VERSION 5.8 ;
BUSBITCHARS "[]" ;
DIVIDERCHAR "/" ;
UNITS
    DATABASE MICRONS 1000 ;
END UNITS

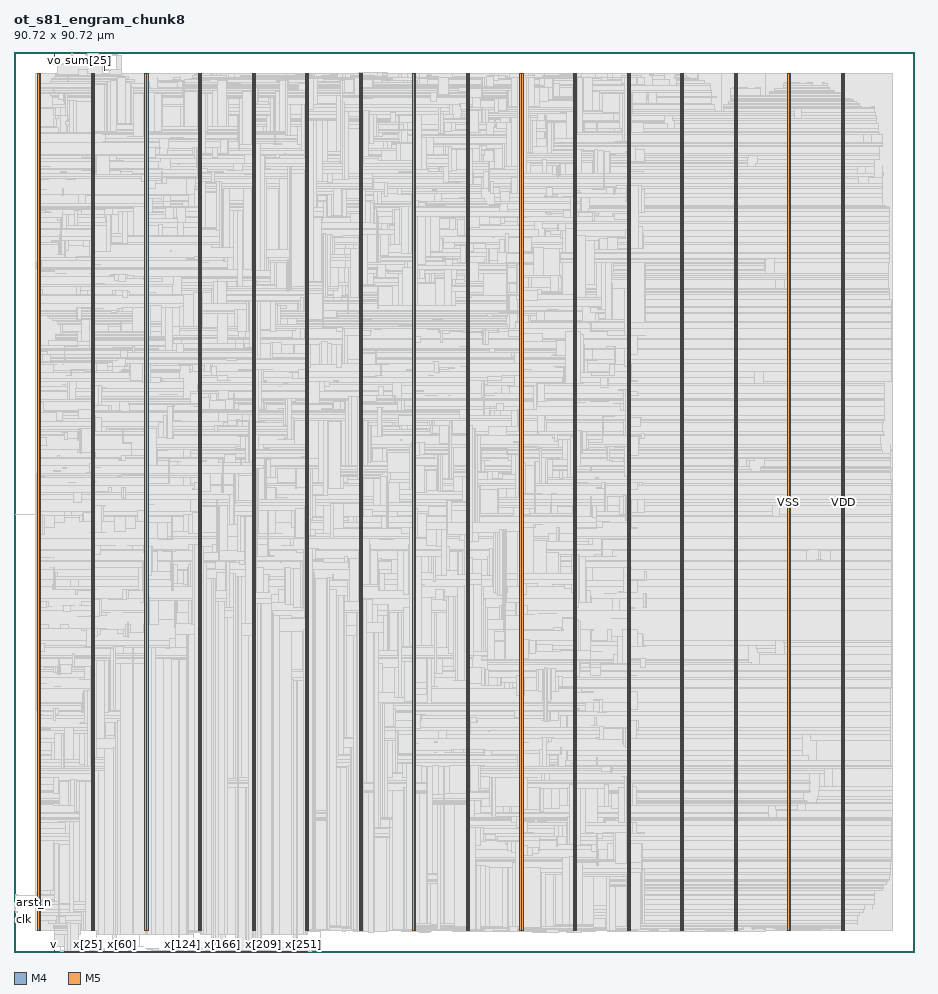
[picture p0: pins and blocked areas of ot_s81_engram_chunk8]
MACRO ot_s81_engram_chunk8
  FOREIGN ot_s81_engram_chunk8 0 0 ;
  CLASS BLOCK ;
  SIZE 90.72 BY 90.72 ;
  PIN arst_n
    DIRECTION INPUT ;
    USE SIGNAL ;
    PORT
      LAYER M4 ;
        RECT  0 4.992 0.084 5.016 ;
    END
  END arst_n
  PIN clk
    DIRECTION INPUT ;
    USE SIGNAL ;
    PORT
      LAYER M4 ;
        RECT  0 4.032 0.084 4.056 ;
    END
  END clk
  PIN fault
    DIRECTION OUTPUT ;
    USE SIGNAL ;
    PORT
      LAYER M5 ;
        RECT  9.12 90.636 9.144 90.72 ;
    END
    PORT
      LAYER M5 ;
        RECT  9.12 88.885 9.144 90.704 ;
    END
  END fault
  PIN sum[0]
    DIRECTION OUTPUT ;
    USE SIGNAL ;
    PORT
      LAYER M5 ;
        RECT  5.088 90.636 5.112 90.72 ;
    END
  END sum[0]
  PIN sum[10]
    DIRECTION OUTPUT ;
    USE SIGNAL ;
    PORT
      LAYER M5 ;
        RECT  6.048 90.636 6.072 90.72 ;
    END
  END sum[10]
  PIN sum[11]
    DIRECTION OUTPUT ;
    USE SIGNAL ;
    PORT
      LAYER M5 ;
        RECT  6.144 90.636 6.168 90.72 ;
    END
  END sum[11]
  PIN sum[12]
    DIRECTION OUTPUT ;
    USE SIGNAL ;
    PORT
      LAYER M5 ;
        RECT  6.24 90.636 6.264 90.72 ;
    END
  END sum[12]
  PIN sum[13]
    DIRECTION OUTPUT ;
    USE SIGNAL ;
    PORT
      LAYER M5 ;
        RECT  6.336 90.636 6.36 90.72 ;
    END
  END sum[13]
  PIN sum[14]
    DIRECTION OUTPUT ;
    USE SIGNAL ;
    PORT
      LAYER M5 ;
        RECT  6.432 90.636 6.456 90.72 ;
    END
  END sum[14]
  PIN sum[15]
    DIRECTION OUTPUT ;
    USE SIGNAL ;
    PORT
      LAYER M5 ;
        RECT  6.528 90.636 6.552 90.72 ;
    END
  END sum[15]
  PIN sum[16]
    DIRECTION OUTPUT ;
    USE SIGNAL ;
    PORT
      LAYER M5 ;
        RECT  6.624 90.636 6.648 90.72 ;
    END
  END sum[16]
  PIN sum[17]
    DIRECTION OUTPUT ;
    USE SIGNAL ;
    PORT
      LAYER M5 ;
        RECT  6.72 90.636 6.744 90.72 ;
    END
  END sum[17]
  PIN sum[18]
    DIRECTION OUTPUT ;
    USE SIGNAL ;
    PORT
      LAYER M5 ;
        RECT  6.816 90.636 6.84 90.72 ;
    END
  END sum[18]
  PIN sum[19]
    DIRECTION OUTPUT ;
    USE SIGNAL ;
    PORT
      LAYER M5 ;
        RECT  6.912 90.636 6.936 90.72 ;
    END
  END sum[19]
  PIN sum[1]
    DIRECTION OUTPUT ;
    USE SIGNAL ;
    PORT
      LAYER M5 ;
        RECT  5.184 90.636 5.208 90.72 ;
    END
  END sum[1]
  PIN sum[20]
    DIRECTION OUTPUT ;
    USE SIGNAL ;
    PORT
      LAYER M5 ;
        RECT  7.008 90.636 7.032 90.72 ;
    END
  END sum[20]
  PIN sum[21]
    DIRECTION OUTPUT ;
    USE SIGNAL ;
    PORT
      LAYER M5 ;
        RECT  7.104 90.636 7.128 90.72 ;
    END
  END sum[21]
  PIN sum[22]
    DIRECTION OUTPUT ;
    USE SIGNAL ;
    PORT
      LAYER M5 ;
        RECT  7.2 90.636 7.224 90.72 ;
    END
  END sum[22]
  PIN sum[23]
    DIRECTION OUTPUT ;
    USE SIGNAL ;
    PORT
      LAYER M5 ;
        RECT  7.296 90.636 7.32 90.72 ;
    END
  END sum[23]
  PIN sum[24]
    DIRECTION OUTPUT ;
    USE SIGNAL ;
    PORT
      LAYER M5 ;
        RECT  7.392 90.636 7.416 90.72 ;
    END
  END sum[24]
  PIN sum[25]
    DIRECTION OUTPUT ;
    USE SIGNAL ;
    PORT
      LAYER M5 ;
        RECT  7.488 90.636 7.512 90.72 ;
    END
  END sum[25]
  PIN sum[26]
    DIRECTION OUTPUT ;
    USE SIGNAL ;
    PORT
      LAYER M5 ;
        RECT  7.584 90.636 7.608 90.72 ;
    END
  END sum[26]
  PIN sum[27]
    DIRECTION OUTPUT ;
    USE SIGNAL ;
    PORT
      LAYER M5 ;
        RECT  7.68 90.636 7.704 90.72 ;
    END
  END sum[27]
  PIN sum[28]
    DIRECTION OUTPUT ;
    USE SIGNAL ;
    PORT
      LAYER M5 ;
        RECT  7.776 90.636 7.8 90.72 ;
    END
  END sum[28]
  PIN sum[29]
    DIRECTION OUTPUT ;
    USE SIGNAL ;
    PORT
      LAYER M5 ;
        RECT  7.872 90.636 7.896 90.72 ;
    END
  END sum[29]
  PIN sum[2]
    DIRECTION OUTPUT ;
    USE SIGNAL ;
    PORT
      LAYER M5 ;
        RECT  5.28 90.636 5.304 90.72 ;
    END
  END sum[2]
  PIN sum[30]
    DIRECTION OUTPUT ;
    USE SIGNAL ;
    PORT
      LAYER M5 ;
        RECT  7.968 90.636 7.992 90.72 ;
    END
  END sum[30]
  PIN sum[31]
    DIRECTION OUTPUT ;
    USE SIGNAL ;
    PORT
      LAYER M5 ;
        RECT  8.064 90.636 8.088 90.72 ;
    END
  END sum[31]
  PIN sum[3]
    DIRECTION OUTPUT ;
    USE SIGNAL ;
    PORT
      LAYER M5 ;
        RECT  5.376 90.636 5.4 90.72 ;
    END
  END sum[3]
  PIN sum[4]
    DIRECTION OUTPUT ;
    USE SIGNAL ;
    PORT
      LAYER M5 ;
        RECT  5.472 90.636 5.496 90.72 ;
    END
  END sum[4]
  PIN sum[5]
    DIRECTION OUTPUT ;
    USE SIGNAL ;
    PORT
      LAYER M5 ;
        RECT  5.568 90.636 5.592 90.72 ;
    END
  END sum[5]
  PIN sum[6]
    DIRECTION OUTPUT ;
    USE SIGNAL ;
    PORT
      LAYER M5 ;
        RECT  5.664 90.636 5.688 90.72 ;
    END
  END sum[6]
  PIN sum[7]
    DIRECTION OUTPUT ;
    USE SIGNAL ;
    PORT
      LAYER M5 ;
        RECT  5.76 90.636 5.784 90.72 ;
    END
  END sum[7]
  PIN sum[8]
    DIRECTION OUTPUT ;
    USE SIGNAL ;
    PORT
      LAYER M5 ;
        RECT  5.856 90.636 5.88 90.72 ;
    END
  END sum[8]
  PIN sum[9]
    DIRECTION OUTPUT ;
    USE SIGNAL ;
    PORT
      LAYER M5 ;
        RECT  5.952 90.636 5.976 90.72 ;
    END
  END sum[9]
  PIN v
    DIRECTION INPUT ;
    USE SIGNAL ;
    PORT
      LAYER M5 ;
        RECT  4.032 0 4.056 0.084 ;
    END
    PORT
      LAYER M5 ;
        RECT  4.032 0.016 4.056 0.611 ;
    END
  END v
  PIN vo
    DIRECTION OUTPUT ;
    USE SIGNAL ;
    PORT
      LAYER M5 ;
        RECT  4.032 90.636 4.056 90.72 ;
    END
    PORT
      LAYER M5 ;
        RECT  4.032 89.461 4.056 90.704 ;
    END
  END vo
  PIN x[0]
    DIRECTION INPUT ;
    USE SIGNAL ;
    PORT
      LAYER M5 ;
        RECT  5.088 0 5.112 0.084 ;
    END
  END x[0]
  PIN x[100]
    DIRECTION INPUT ;
    USE SIGNAL ;
    PORT
      LAYER M5 ;
        RECT  14.688 0 14.712 0.084 ;
    END
  END x[100]
  PIN x[101]
    DIRECTION INPUT ;
    USE SIGNAL ;
    PORT
      LAYER M5 ;
        RECT  14.784 0 14.808 0.084 ;
    END
  END x[101]
  PIN x[102]
    DIRECTION INPUT ;
    USE SIGNAL ;
    PORT
      LAYER M5 ;
        RECT  14.88 0 14.904 0.084 ;
    END
  END x[102]
  PIN x[103]
    DIRECTION INPUT ;
    USE SIGNAL ;
    PORT
      LAYER M5 ;
        RECT  14.976 0 15 0.084 ;
    END
  END x[103]
  PIN x[104]
    DIRECTION INPUT ;
    USE SIGNAL ;
    PORT
      LAYER M5 ;
        RECT  15.072 0 15.096 0.084 ;
    END
  END x[104]
  PIN x[105]
    DIRECTION INPUT ;
    USE SIGNAL ;
    PORT
      LAYER M5 ;
        RECT  15.168 0 15.192 0.084 ;
    END
  END x[105]
  PIN x[106]
    DIRECTION INPUT ;
    USE SIGNAL ;
    PORT
      LAYER M5 ;
        RECT  15.264 0 15.288 0.084 ;
    END
  END x[106]
  PIN x[107]
    DIRECTION INPUT ;
    USE SIGNAL ;
    PORT
      LAYER M5 ;
        RECT  15.36 0 15.384 0.084 ;
    END
  END x[107]
  PIN x[108]
    DIRECTION INPUT ;
    USE SIGNAL ;
    PORT
      LAYER M5 ;
        RECT  15.456 0 15.48 0.084 ;
    END
  END x[108]
  PIN x[109]
    DIRECTION INPUT ;
    USE SIGNAL ;
    PORT
      LAYER M5 ;
        RECT  15.552 0 15.576 0.084 ;
    END
  END x[109]
  PIN x[10]
    DIRECTION INPUT ;
    USE SIGNAL ;
    PORT
      LAYER M5 ;
        RECT  6.048 0 6.072 0.084 ;
    END
  END x[10]
  PIN x[110]
    DIRECTION INPUT ;
    USE SIGNAL ;
    PORT
      LAYER M5 ;
        RECT  15.648 0 15.672 0.084 ;
    END
  END x[110]
  PIN x[111]
    DIRECTION INPUT ;
    USE SIGNAL ;
    PORT
      LAYER M5 ;
        RECT  15.744 0 15.768 0.084 ;
    END
  END x[111]
  PIN x[112]
    DIRECTION INPUT ;
    USE SIGNAL ;
    PORT
      LAYER M5 ;
        RECT  15.84 0 15.864 0.084 ;
    END
  END x[112]
  PIN x[113]
    DIRECTION INPUT ;
    USE SIGNAL ;
    PORT
      LAYER M5 ;
        RECT  15.936 0 15.96 0.084 ;
    END
  END x[113]
  PIN x[114]
    DIRECTION INPUT ;
    USE SIGNAL ;
    PORT
      LAYER M5 ;
        RECT  16.032 0 16.056 0.084 ;
    END
  END x[114]
  PIN x[115]
    DIRECTION INPUT ;
    USE SIGNAL ;
    PORT
      LAYER M5 ;
        RECT  16.128 0 16.152 0.084 ;
    END
  END x[115]
  PIN x[116]
    DIRECTION INPUT ;
    USE SIGNAL ;
    PORT
      LAYER M5 ;
        RECT  16.224 0 16.248 0.084 ;
    END
  END x[116]
  PIN x[117]
    DIRECTION INPUT ;
    USE SIGNAL ;
    PORT
      LAYER M5 ;
        RECT  16.32 0 16.344 0.084 ;
    END
  END x[117]
  PIN x[118]
    DIRECTION INPUT ;
    USE SIGNAL ;
    PORT
      LAYER M5 ;
        RECT  16.416 0 16.44 0.084 ;
    END
  END x[118]
  PIN x[119]
    DIRECTION INPUT ;
    USE SIGNAL ;
    PORT
      LAYER M5 ;
        RECT  16.512 0 16.536 0.084 ;
    END
  END x[119]
  PIN x[11]
    DIRECTION INPUT ;
    USE SIGNAL ;
    PORT
      LAYER M5 ;
        RECT  6.144 0 6.168 0.084 ;
    END
  END x[11]
  PIN x[120]
    DIRECTION INPUT ;
    USE SIGNAL ;
    PORT
      LAYER M5 ;
        RECT  16.608 0 16.632 0.084 ;
    END
  END x[120]
  PIN x[121]
    DIRECTION INPUT ;
    USE SIGNAL ;
    PORT
      LAYER M5 ;
        RECT  16.704 0 16.728 0.084 ;
    END
  END x[121]
  PIN x[122]
    DIRECTION INPUT ;
    USE SIGNAL ;
    PORT
      LAYER M5 ;
        RECT  16.8 0 16.824 0.084 ;
    END
  END x[122]
  PIN x[123]
    DIRECTION INPUT ;
    USE SIGNAL ;
    PORT
      LAYER M5 ;
        RECT  16.896 0 16.92 0.084 ;
    END
  END x[123]
  PIN x[124]
    DIRECTION INPUT ;
    USE SIGNAL ;
    PORT
      LAYER M5 ;
        RECT  16.992 0 17.016 0.084 ;
    END
  END x[124]
  PIN x[125]
    DIRECTION INPUT ;
    USE SIGNAL ;
    PORT
      LAYER M5 ;
        RECT  17.088 0 17.112 0.084 ;
    END
  END x[125]
  PIN x[126]
    DIRECTION INPUT ;
    USE SIGNAL ;
    PORT
      LAYER M5 ;
        RECT  17.184 0 17.208 0.084 ;
    END
  END x[126]
  PIN x[127]
    DIRECTION INPUT ;
    USE SIGNAL ;
    PORT
      LAYER M5 ;
        RECT  17.28 0 17.304 0.084 ;
    END
  END x[127]
  PIN x[128]
    DIRECTION INPUT ;
    USE SIGNAL ;
    PORT
      LAYER M5 ;
        RECT  17.376 0 17.4 0.084 ;
    END
  END x[128]
  PIN x[129]
    DIRECTION INPUT ;
    USE SIGNAL ;
    PORT
      LAYER M5 ;
        RECT  17.472 0 17.496 0.084 ;
    END
  END x[129]
  PIN x[12]
    DIRECTION INPUT ;
    USE SIGNAL ;
    PORT
      LAYER M5 ;
        RECT  6.24 0 6.264 0.084 ;
    END
  END x[12]
  PIN x[130]
    DIRECTION INPUT ;
    USE SIGNAL ;
    PORT
      LAYER M5 ;
        RECT  17.568 0 17.592 0.084 ;
    END
  END x[130]
  PIN x[131]
    DIRECTION INPUT ;
    USE SIGNAL ;
    PORT
      LAYER M5 ;
        RECT  17.664 0 17.688 0.084 ;
    END
  END x[131]
  PIN x[132]
    DIRECTION INPUT ;
    USE SIGNAL ;
    PORT
      LAYER M5 ;
        RECT  17.76 0 17.784 0.084 ;
    END
  END x[132]
  PIN x[133]
    DIRECTION INPUT ;
    USE SIGNAL ;
    PORT
      LAYER M5 ;
        RECT  17.856 0 17.88 0.084 ;
    END
  END x[133]
  PIN x[134]
    DIRECTION INPUT ;
    USE SIGNAL ;
    PORT
      LAYER M5 ;
        RECT  17.952 0 17.976 0.084 ;
    END
  END x[134]
  PIN x[135]
    DIRECTION INPUT ;
    USE SIGNAL ;
    PORT
      LAYER M5 ;
        RECT  18.048 0 18.072 0.084 ;
    END
  END x[135]
  PIN x[136]
    DIRECTION INPUT ;
    USE SIGNAL ;
    PORT
      LAYER M5 ;
        RECT  18.144 0 18.168 0.084 ;
    END
  END x[136]
  PIN x[137]
    DIRECTION INPUT ;
    USE SIGNAL ;
    PORT
      LAYER M5 ;
        RECT  18.24 0 18.264 0.084 ;
    END
  END x[137]
  PIN x[138]
    DIRECTION INPUT ;
    USE SIGNAL ;
    PORT
      LAYER M5 ;
        RECT  18.336 0 18.36 0.084 ;
    END
  END x[138]
  PIN x[139]
    DIRECTION INPUT ;
    USE SIGNAL ;
    PORT
      LAYER M5 ;
        RECT  18.432 0 18.456 0.084 ;
    END
  END x[139]
  PIN x[13]
    DIRECTION INPUT ;
    USE SIGNAL ;
    PORT
      LAYER M5 ;
        RECT  6.336 0 6.36 0.084 ;
    END
  END x[13]
  PIN x[140]
    DIRECTION INPUT ;
    USE SIGNAL ;
    PORT
      LAYER M5 ;
        RECT  18.528 0 18.552 0.084 ;
    END
  END x[140]
  PIN x[141]
    DIRECTION INPUT ;
    USE SIGNAL ;
    PORT
      LAYER M5 ;
        RECT  18.624 0 18.648 0.084 ;
    END
  END x[141]
  PIN x[142]
    DIRECTION INPUT ;
    USE SIGNAL ;
    PORT
      LAYER M5 ;
        RECT  18.72 0 18.744 0.084 ;
    END
  END x[142]
  PIN x[143]
    DIRECTION INPUT ;
    USE SIGNAL ;
    PORT
      LAYER M5 ;
        RECT  18.816 0 18.84 0.084 ;
    END
  END x[143]
  PIN x[144]
    DIRECTION INPUT ;
    USE SIGNAL ;
    PORT
      LAYER M5 ;
        RECT  18.912 0 18.936 0.084 ;
    END
  END x[144]
  PIN x[145]
    DIRECTION INPUT ;
    USE SIGNAL ;
    PORT
      LAYER M5 ;
        RECT  19.008 0 19.032 0.084 ;
    END
  END x[145]
  PIN x[146]
    DIRECTION INPUT ;
    USE SIGNAL ;
    PORT
      LAYER M5 ;
        RECT  19.104 0 19.128 0.084 ;
    END
  END x[146]
  PIN x[147]
    DIRECTION INPUT ;
    USE SIGNAL ;
    PORT
      LAYER M5 ;
        RECT  19.2 0 19.224 0.084 ;
    END
  END x[147]
  PIN x[148]
    DIRECTION INPUT ;
    USE SIGNAL ;
    PORT
      LAYER M5 ;
        RECT  19.296 0 19.32 0.084 ;
    END
  END x[148]
  PIN x[149]
    DIRECTION INPUT ;
    USE SIGNAL ;
    PORT
      LAYER M5 ;
        RECT  19.392 0 19.416 0.084 ;
    END
  END x[149]
  PIN x[14]
    DIRECTION INPUT ;
    USE SIGNAL ;
    PORT
      LAYER M5 ;
        RECT  6.432 0 6.456 0.084 ;
    END
  END x[14]
  PIN x[150]
    DIRECTION INPUT ;
    USE SIGNAL ;
    PORT
      LAYER M5 ;
        RECT  19.488 0 19.512 0.084 ;
    END
  END x[150]
  PIN x[151]
    DIRECTION INPUT ;
    USE SIGNAL ;
    PORT
      LAYER M5 ;
        RECT  19.584 0 19.608 0.084 ;
    END
  END x[151]
  PIN x[152]
    DIRECTION INPUT ;
    USE SIGNAL ;
    PORT
      LAYER M5 ;
        RECT  19.68 0 19.704 0.084 ;
    END
  END x[152]
  PIN x[153]
    DIRECTION INPUT ;
    USE SIGNAL ;
    PORT
      LAYER M5 ;
        RECT  19.776 0 19.8 0.084 ;
    END
  END x[153]
  PIN x[154]
    DIRECTION INPUT ;
    USE SIGNAL ;
    PORT
      LAYER M5 ;
        RECT  19.872 0 19.896 0.084 ;
    END
  END x[154]
  PIN x[155]
    DIRECTION INPUT ;
    USE SIGNAL ;
    PORT
      LAYER M5 ;
        RECT  19.968 0 19.992 0.084 ;
    END
  END x[155]
  PIN x[156]
    DIRECTION INPUT ;
    USE SIGNAL ;
    PORT
      LAYER M5 ;
        RECT  20.064 0 20.088 0.084 ;
    END
  END x[156]
  PIN x[157]
    DIRECTION INPUT ;
    USE SIGNAL ;
    PORT
      LAYER M5 ;
        RECT  20.16 0 20.184 0.084 ;
    END
  END x[157]
  PIN x[158]
    DIRECTION INPUT ;
    USE SIGNAL ;
    PORT
      LAYER M5 ;
        RECT  20.256 0 20.28 0.084 ;
    END
  END x[158]
  PIN x[159]
    DIRECTION INPUT ;
    USE SIGNAL ;
    PORT
      LAYER M5 ;
        RECT  20.352 0 20.376 0.084 ;
    END
  END x[159]
  PIN x[15]
    DIRECTION INPUT ;
    USE SIGNAL ;
    PORT
      LAYER M5 ;
        RECT  6.528 0 6.552 0.084 ;
    END
  END x[15]
  PIN x[160]
    DIRECTION INPUT ;
    USE SIGNAL ;
    PORT
      LAYER M5 ;
        RECT  20.448 0 20.472 0.084 ;
    END
  END x[160]
  PIN x[161]
    DIRECTION INPUT ;
    USE SIGNAL ;
    PORT
      LAYER M5 ;
        RECT  20.544 0 20.568 0.084 ;
    END
  END x[161]
  PIN x[162]
    DIRECTION INPUT ;
    USE SIGNAL ;
    PORT
      LAYER M5 ;
        RECT  20.64 0 20.664 0.084 ;
    END
  END x[162]
  PIN x[163]
    DIRECTION INPUT ;
    USE SIGNAL ;
    PORT
      LAYER M5 ;
        RECT  20.736 0 20.76 0.084 ;
    END
  END x[163]
  PIN x[164]
    DIRECTION INPUT ;
    USE SIGNAL ;
    PORT
      LAYER M5 ;
        RECT  20.832 0 20.856 0.084 ;
    END
  END x[164]
  PIN x[165]
    DIRECTION INPUT ;
    USE SIGNAL ;
    PORT
      LAYER M5 ;
        RECT  20.928 0 20.952 0.084 ;
    END
  END x[165]
  PIN x[166]
    DIRECTION INPUT ;
    USE SIGNAL ;
    PORT
      LAYER M5 ;
        RECT  21.024 0 21.048 0.084 ;
    END
  END x[166]
  PIN x[167]
    DIRECTION INPUT ;
    USE SIGNAL ;
    PORT
      LAYER M5 ;
        RECT  21.12 0 21.144 0.084 ;
    END
  END x[167]
  PIN x[168]
    DIRECTION INPUT ;
    USE SIGNAL ;
    PORT
      LAYER M5 ;
        RECT  21.216 0 21.24 0.084 ;
    END
  END x[168]
  PIN x[169]
    DIRECTION INPUT ;
    USE SIGNAL ;
    PORT
      LAYER M5 ;
        RECT  21.312 0 21.336 0.084 ;
    END
  END x[169]
  PIN x[16]
    DIRECTION INPUT ;
    USE SIGNAL ;
    PORT
      LAYER M5 ;
        RECT  6.624 0 6.648 0.084 ;
    END
  END x[16]
  PIN x[170]
    DIRECTION INPUT ;
    USE SIGNAL ;
    PORT
      LAYER M5 ;
        RECT  21.408 0 21.432 0.084 ;
    END
  END x[170]
  PIN x[171]
    DIRECTION INPUT ;
    USE SIGNAL ;
    PORT
      LAYER M5 ;
        RECT  21.504 0 21.528 0.084 ;
    END
  END x[171]
  PIN x[172]
    DIRECTION INPUT ;
    USE SIGNAL ;
    PORT
      LAYER M5 ;
        RECT  21.6 0 21.624 0.084 ;
    END
  END x[172]
  PIN x[173]
    DIRECTION INPUT ;
    USE SIGNAL ;
    PORT
      LAYER M5 ;
        RECT  21.696 0 21.72 0.084 ;
    END
  END x[173]
  PIN x[174]
    DIRECTION INPUT ;
    USE SIGNAL ;
    PORT
      LAYER M5 ;
        RECT  21.792 0 21.816 0.084 ;
    END
  END x[174]
  PIN x[175]
    DIRECTION INPUT ;
    USE SIGNAL ;
    PORT
      LAYER M5 ;
        RECT  21.888 0 21.912 0.084 ;
    END
  END x[175]
  PIN x[176]
    DIRECTION INPUT ;
    USE SIGNAL ;
    PORT
      LAYER M5 ;
        RECT  21.984 0 22.008 0.084 ;
    END
  END x[176]
  PIN x[177]
    DIRECTION INPUT ;
    USE SIGNAL ;
    PORT
      LAYER M5 ;
        RECT  22.08 0 22.104 0.084 ;
    END
  END x[177]
  PIN x[178]
    DIRECTION INPUT ;
    USE SIGNAL ;
    PORT
      LAYER M5 ;
        RECT  22.176 0 22.2 0.084 ;
    END
  END x[178]
  PIN x[179]
    DIRECTION INPUT ;
    USE SIGNAL ;
    PORT
      LAYER M5 ;
        RECT  22.272 0 22.296 0.084 ;
    END
  END x[179]
  PIN x[17]
    DIRECTION INPUT ;
    USE SIGNAL ;
    PORT
      LAYER M5 ;
        RECT  6.72 0 6.744 0.084 ;
    END
  END x[17]
  PIN x[180]
    DIRECTION INPUT ;
    USE SIGNAL ;
    PORT
      LAYER M5 ;
        RECT  22.368 0 22.392 0.084 ;
    END
  END x[180]
  PIN x[181]
    DIRECTION INPUT ;
    USE SIGNAL ;
    PORT
      LAYER M5 ;
        RECT  22.464 0 22.488 0.084 ;
    END
  END x[181]
  PIN x[182]
    DIRECTION INPUT ;
    USE SIGNAL ;
    PORT
      LAYER M5 ;
        RECT  22.56 0 22.584 0.084 ;
    END
  END x[182]
  PIN x[183]
    DIRECTION INPUT ;
    USE SIGNAL ;
    PORT
      LAYER M5 ;
        RECT  22.656 0 22.68 0.084 ;
    END
  END x[183]
  PIN x[184]
    DIRECTION INPUT ;
    USE SIGNAL ;
    PORT
      LAYER M5 ;
        RECT  22.752 0 22.776 0.084 ;
    END
  END x[184]
  PIN x[185]
    DIRECTION INPUT ;
    USE SIGNAL ;
    PORT
      LAYER M5 ;
        RECT  22.848 0 22.872 0.084 ;
    END
  END x[185]
  PIN x[186]
    DIRECTION INPUT ;
    USE SIGNAL ;
    PORT
      LAYER M5 ;
        RECT  22.944 0 22.968 0.084 ;
    END
  END x[186]
  PIN x[187]
    DIRECTION INPUT ;
    USE SIGNAL ;
    PORT
      LAYER M5 ;
        RECT  23.04 0 23.064 0.084 ;
    END
  END x[187]
  PIN x[188]
    DIRECTION INPUT ;
    USE SIGNAL ;
    PORT
      LAYER M5 ;
        RECT  23.136 0 23.16 0.084 ;
    END
  END x[188]
  PIN x[189]
    DIRECTION INPUT ;
    USE SIGNAL ;
    PORT
      LAYER M5 ;
        RECT  23.232 0 23.256 0.084 ;
    END
  END x[189]
  PIN x[18]
    DIRECTION INPUT ;
    USE SIGNAL ;
    PORT
      LAYER M5 ;
        RECT  6.816 0 6.84 0.084 ;
    END
  END x[18]
  PIN x[190]
    DIRECTION INPUT ;
    USE SIGNAL ;
    PORT
      LAYER M5 ;
        RECT  23.328 0 23.352 0.084 ;
    END
  END x[190]
  PIN x[191]
    DIRECTION INPUT ;
    USE SIGNAL ;
    PORT
      LAYER M5 ;
        RECT  23.424 0 23.448 0.084 ;
    END
  END x[191]
  PIN x[192]
    DIRECTION INPUT ;
    USE SIGNAL ;
    PORT
      LAYER M5 ;
        RECT  23.52 0 23.544 0.084 ;
    END
  END x[192]
  PIN x[193]
    DIRECTION INPUT ;
    USE SIGNAL ;
    PORT
      LAYER M5 ;
        RECT  23.616 0 23.64 0.084 ;
    END
  END x[193]
  PIN x[194]
    DIRECTION INPUT ;
    USE SIGNAL ;
    PORT
      LAYER M5 ;
        RECT  23.712 0 23.736 0.084 ;
    END
  END x[194]
  PIN x[195]
    DIRECTION INPUT ;
    USE SIGNAL ;
    PORT
      LAYER M5 ;
        RECT  23.808 0 23.832 0.084 ;
    END
  END x[195]
  PIN x[196]
    DIRECTION INPUT ;
    USE SIGNAL ;
    PORT
      LAYER M5 ;
        RECT  23.904 0 23.928 0.084 ;
    END
  END x[196]
  PIN x[197]
    DIRECTION INPUT ;
    USE SIGNAL ;
    PORT
      LAYER M5 ;
        RECT  24 0 24.024 0.084 ;
    END
  END x[197]
  PIN x[198]
    DIRECTION INPUT ;
    USE SIGNAL ;
    PORT
      LAYER M5 ;
        RECT  24.096 0 24.12 0.084 ;
    END
  END x[198]
  PIN x[199]
    DIRECTION INPUT ;
    USE SIGNAL ;
    PORT
      LAYER M5 ;
        RECT  24.192 0 24.216 0.084 ;
    END
  END x[199]
  PIN x[19]
    DIRECTION INPUT ;
    USE SIGNAL ;
    PORT
      LAYER M5 ;
        RECT  6.912 0 6.936 0.084 ;
    END
  END x[19]
  PIN x[1]
    DIRECTION INPUT ;
    USE SIGNAL ;
    PORT
      LAYER M5 ;
        RECT  5.184 0 5.208 0.084 ;
    END
  END x[1]
  PIN x[200]
    DIRECTION INPUT ;
    USE SIGNAL ;
    PORT
      LAYER M5 ;
        RECT  24.288 0 24.312 0.084 ;
    END
  END x[200]
  PIN x[201]
    DIRECTION INPUT ;
    USE SIGNAL ;
    PORT
      LAYER M5 ;
        RECT  24.384 0 24.408 0.084 ;
    END
  END x[201]
  PIN x[202]
    DIRECTION INPUT ;
    USE SIGNAL ;
    PORT
      LAYER M5 ;
        RECT  24.48 0 24.504 0.084 ;
    END
  END x[202]
  PIN x[203]
    DIRECTION INPUT ;
    USE SIGNAL ;
    PORT
      LAYER M5 ;
        RECT  24.576 0 24.6 0.084 ;
    END
  END x[203]
  PIN x[204]
    DIRECTION INPUT ;
    USE SIGNAL ;
    PORT
      LAYER M5 ;
        RECT  24.672 0 24.696 0.084 ;
    END
  END x[204]
  PIN x[205]
    DIRECTION INPUT ;
    USE SIGNAL ;
    PORT
      LAYER M5 ;
        RECT  24.768 0 24.792 0.084 ;
    END
  END x[205]
  PIN x[206]
    DIRECTION INPUT ;
    USE SIGNAL ;
    PORT
      LAYER M5 ;
        RECT  24.864 0 24.888 0.084 ;
    END
  END x[206]
  PIN x[207]
    DIRECTION INPUT ;
    USE SIGNAL ;
    PORT
      LAYER M5 ;
        RECT  24.96 0 24.984 0.084 ;
    END
  END x[207]
  PIN x[208]
    DIRECTION INPUT ;
    USE SIGNAL ;
    PORT
      LAYER M5 ;
        RECT  25.056 0 25.08 0.084 ;
    END
  END x[208]
  PIN x[209]
    DIRECTION INPUT ;
    USE SIGNAL ;
    PORT
      LAYER M5 ;
        RECT  25.152 0 25.176 0.084 ;
    END
  END x[209]
  PIN x[20]
    DIRECTION INPUT ;
    USE SIGNAL ;
    PORT
      LAYER M5 ;
        RECT  7.008 0 7.032 0.084 ;
    END
  END x[20]
  PIN x[210]
    DIRECTION INPUT ;
    USE SIGNAL ;
    PORT
      LAYER M5 ;
        RECT  25.248 0 25.272 0.084 ;
    END
  END x[210]
  PIN x[211]
    DIRECTION INPUT ;
    USE SIGNAL ;
    PORT
      LAYER M5 ;
        RECT  25.344 0 25.368 0.084 ;
    END
  END x[211]
  PIN x[212]
    DIRECTION INPUT ;
    USE SIGNAL ;
    PORT
      LAYER M5 ;
        RECT  25.44 0 25.464 0.084 ;
    END
  END x[212]
  PIN x[213]
    DIRECTION INPUT ;
    USE SIGNAL ;
    PORT
      LAYER M5 ;
        RECT  25.536 0 25.56 0.084 ;
    END
  END x[213]
  PIN x[214]
    DIRECTION INPUT ;
    USE SIGNAL ;
    PORT
      LAYER M5 ;
        RECT  25.632 0 25.656 0.084 ;
    END
  END x[214]
  PIN x[215]
    DIRECTION INPUT ;
    USE SIGNAL ;
    PORT
      LAYER M5 ;
        RECT  25.728 0 25.752 0.084 ;
    END
  END x[215]
  PIN x[216]
    DIRECTION INPUT ;
    USE SIGNAL ;
    PORT
      LAYER M5 ;
        RECT  25.824 0 25.848 0.084 ;
    END
  END x[216]
  PIN x[217]
    DIRECTION INPUT ;
    USE SIGNAL ;
    PORT
      LAYER M5 ;
        RECT  25.92 0 25.944 0.084 ;
    END
  END x[217]
  PIN x[218]
    DIRECTION INPUT ;
    USE SIGNAL ;
    PORT
      LAYER M5 ;
        RECT  26.016 0 26.04 0.084 ;
    END
  END x[218]
  PIN x[219]
    DIRECTION INPUT ;
    USE SIGNAL ;
    PORT
      LAYER M5 ;
        RECT  26.112 0 26.136 0.084 ;
    END
  END x[219]
  PIN x[21]
    DIRECTION INPUT ;
    USE SIGNAL ;
    PORT
      LAYER M5 ;
        RECT  7.104 0 7.128 0.084 ;
    END
  END x[21]
  PIN x[220]
    DIRECTION INPUT ;
    USE SIGNAL ;
    PORT
      LAYER M5 ;
        RECT  26.208 0 26.232 0.084 ;
    END
  END x[220]
  PIN x[221]
    DIRECTION INPUT ;
    USE SIGNAL ;
    PORT
      LAYER M5 ;
        RECT  26.304 0 26.328 0.084 ;
    END
  END x[221]
  PIN x[222]
    DIRECTION INPUT ;
    USE SIGNAL ;
    PORT
      LAYER M5 ;
        RECT  26.4 0 26.424 0.084 ;
    END
  END x[222]
  PIN x[223]
    DIRECTION INPUT ;
    USE SIGNAL ;
    PORT
      LAYER M5 ;
        RECT  26.496 0 26.52 0.084 ;
    END
  END x[223]
  PIN x[224]
    DIRECTION INPUT ;
    USE SIGNAL ;
    PORT
      LAYER M5 ;
        RECT  26.592 0 26.616 0.084 ;
    END
  END x[224]
  PIN x[225]
    DIRECTION INPUT ;
    USE SIGNAL ;
    PORT
      LAYER M5 ;
        RECT  26.688 0 26.712 0.084 ;
    END
  END x[225]
  PIN x[226]
    DIRECTION INPUT ;
    USE SIGNAL ;
    PORT
      LAYER M5 ;
        RECT  26.784 0 26.808 0.084 ;
    END
  END x[226]
  PIN x[227]
    DIRECTION INPUT ;
    USE SIGNAL ;
    PORT
      LAYER M5 ;
        RECT  26.88 0 26.904 0.084 ;
    END
  END x[227]
  PIN x[228]
    DIRECTION INPUT ;
    USE SIGNAL ;
    PORT
      LAYER M5 ;
        RECT  26.976 0 27 0.084 ;
    END
  END x[228]
  PIN x[229]
    DIRECTION INPUT ;
    USE SIGNAL ;
    PORT
      LAYER M5 ;
        RECT  27.072 0 27.096 0.084 ;
    END
  END x[229]
  PIN x[22]
    DIRECTION INPUT ;
    USE SIGNAL ;
    PORT
      LAYER M5 ;
        RECT  7.2 0 7.224 0.084 ;
    END
  END x[22]
  PIN x[230]
    DIRECTION INPUT ;
    USE SIGNAL ;
    PORT
      LAYER M5 ;
        RECT  27.168 0 27.192 0.084 ;
    END
  END x[230]
  PIN x[231]
    DIRECTION INPUT ;
    USE SIGNAL ;
    PORT
      LAYER M5 ;
        RECT  27.264 0 27.288 0.084 ;
    END
  END x[231]
  PIN x[232]
    DIRECTION INPUT ;
    USE SIGNAL ;
    PORT
      LAYER M5 ;
        RECT  27.36 0 27.384 0.084 ;
    END
  END x[232]
  PIN x[233]
    DIRECTION INPUT ;
    USE SIGNAL ;
    PORT
      LAYER M5 ;
        RECT  27.456 0 27.48 0.084 ;
    END
  END x[233]
  PIN x[234]
    DIRECTION INPUT ;
    USE SIGNAL ;
    PORT
      LAYER M5 ;
        RECT  27.552 0 27.576 0.084 ;
    END
  END x[234]
  PIN x[235]
    DIRECTION INPUT ;
    USE SIGNAL ;
    PORT
      LAYER M5 ;
        RECT  27.648 0 27.672 0.084 ;
    END
  END x[235]
  PIN x[236]
    DIRECTION INPUT ;
    USE SIGNAL ;
    PORT
      LAYER M5 ;
        RECT  27.744 0 27.768 0.084 ;
    END
  END x[236]
  PIN x[237]
    DIRECTION INPUT ;
    USE SIGNAL ;
    PORT
      LAYER M5 ;
        RECT  27.84 0 27.864 0.084 ;
    END
  END x[237]
  PIN x[238]
    DIRECTION INPUT ;
    USE SIGNAL ;
    PORT
      LAYER M5 ;
        RECT  27.936 0 27.96 0.084 ;
    END
  END x[238]
  PIN x[239]
    DIRECTION INPUT ;
    USE SIGNAL ;
    PORT
      LAYER M5 ;
        RECT  28.032 0 28.056 0.084 ;
    END
  END x[239]
  PIN x[23]
    DIRECTION INPUT ;
    USE SIGNAL ;
    PORT
      LAYER M5 ;
        RECT  7.296 0 7.32 0.084 ;
    END
  END x[23]
  PIN x[240]
    DIRECTION INPUT ;
    USE SIGNAL ;
    PORT
      LAYER M5 ;
        RECT  28.128 0 28.152 0.084 ;
    END
  END x[240]
  PIN x[241]
    DIRECTION INPUT ;
    USE SIGNAL ;
    PORT
      LAYER M5 ;
        RECT  28.224 0 28.248 0.084 ;
    END
  END x[241]
  PIN x[242]
    DIRECTION INPUT ;
    USE SIGNAL ;
    PORT
      LAYER M5 ;
        RECT  28.32 0 28.344 0.084 ;
    END
  END x[242]
  PIN x[243]
    DIRECTION INPUT ;
    USE SIGNAL ;
    PORT
      LAYER M5 ;
        RECT  28.416 0 28.44 0.084 ;
    END
  END x[243]
  PIN x[244]
    DIRECTION INPUT ;
    USE SIGNAL ;
    PORT
      LAYER M5 ;
        RECT  28.512 0 28.536 0.084 ;
    END
  END x[244]
  PIN x[245]
    DIRECTION INPUT ;
    USE SIGNAL ;
    PORT
      LAYER M5 ;
        RECT  28.608 0 28.632 0.084 ;
    END
  END x[245]
  PIN x[246]
    DIRECTION INPUT ;
    USE SIGNAL ;
    PORT
      LAYER M5 ;
        RECT  28.704 0 28.728 0.084 ;
    END
  END x[246]
  PIN x[247]
    DIRECTION INPUT ;
    USE SIGNAL ;
    PORT
      LAYER M5 ;
        RECT  28.8 0 28.824 0.084 ;
    END
  END x[247]
  PIN x[248]
    DIRECTION INPUT ;
    USE SIGNAL ;
    PORT
      LAYER M5 ;
        RECT  28.896 0 28.92 0.084 ;
    END
  END x[248]
  PIN x[249]
    DIRECTION INPUT ;
    USE SIGNAL ;
    PORT
      LAYER M5 ;
        RECT  28.992 0 29.016 0.084 ;
    END
  END x[249]
  PIN x[24]
    DIRECTION INPUT ;
    USE SIGNAL ;
    PORT
      LAYER M5 ;
        RECT  7.392 0 7.416 0.084 ;
    END
  END x[24]
  PIN x[250]
    DIRECTION INPUT ;
    USE SIGNAL ;
    PORT
      LAYER M5 ;
        RECT  29.088 0 29.112 0.084 ;
    END
  END x[250]
  PIN x[251]
    DIRECTION INPUT ;
    USE SIGNAL ;
    PORT
      LAYER M5 ;
        RECT  29.184 0 29.208 0.084 ;
    END
  END x[251]
  PIN x[252]
    DIRECTION INPUT ;
    USE SIGNAL ;
    PORT
      LAYER M5 ;
        RECT  29.28 0 29.304 0.084 ;
    END
  END x[252]
  PIN x[253]
    DIRECTION INPUT ;
    USE SIGNAL ;
    PORT
      LAYER M5 ;
        RECT  29.376 0 29.4 0.084 ;
    END
  END x[253]
  PIN x[254]
    DIRECTION INPUT ;
    USE SIGNAL ;
    PORT
      LAYER M5 ;
        RECT  29.472 0 29.496 0.084 ;
    END
  END x[254]
  PIN x[255]
    DIRECTION INPUT ;
    USE SIGNAL ;
    PORT
      LAYER M5 ;
        RECT  29.568 0 29.592 0.084 ;
    END
  END x[255]
  PIN x[25]
    DIRECTION INPUT ;
    USE SIGNAL ;
    PORT
      LAYER M5 ;
        RECT  7.488 0 7.512 0.084 ;
    END
  END x[25]
  PIN x[26]
    DIRECTION INPUT ;
    USE SIGNAL ;
    PORT
      LAYER M5 ;
        RECT  7.584 0 7.608 0.084 ;
    END
  END x[26]
  PIN x[27]
    DIRECTION INPUT ;
    USE SIGNAL ;
    PORT
      LAYER M5 ;
        RECT  7.68 0 7.704 0.084 ;
    END
  END x[27]
  PIN x[28]
    DIRECTION INPUT ;
    USE SIGNAL ;
    PORT
      LAYER M5 ;
        RECT  7.776 0 7.8 0.084 ;
    END
  END x[28]
  PIN x[29]
    DIRECTION INPUT ;
    USE SIGNAL ;
    PORT
      LAYER M5 ;
        RECT  7.872 0 7.896 0.084 ;
    END
  END x[29]
  PIN x[2]
    DIRECTION INPUT ;
    USE SIGNAL ;
    PORT
      LAYER M5 ;
        RECT  5.28 0 5.304 0.084 ;
    END
  END x[2]
  PIN x[30]
    DIRECTION INPUT ;
    USE SIGNAL ;
    PORT
      LAYER M5 ;
        RECT  7.968 0 7.992 0.084 ;
    END
  END x[30]
  PIN x[31]
    DIRECTION INPUT ;
    USE SIGNAL ;
    PORT
      LAYER M5 ;
        RECT  8.064 0 8.088 0.084 ;
    END
  END x[31]
  PIN x[32]
    DIRECTION INPUT ;
    USE SIGNAL ;
    PORT
      LAYER M5 ;
        RECT  8.16 0 8.184 0.084 ;
    END
  END x[32]
  PIN x[33]
    DIRECTION INPUT ;
    USE SIGNAL ;
    PORT
      LAYER M5 ;
        RECT  8.256 0 8.28 0.084 ;
    END
  END x[33]
  PIN x[34]
    DIRECTION INPUT ;
    USE SIGNAL ;
    PORT
      LAYER M5 ;
        RECT  8.352 0 8.376 0.084 ;
    END
  END x[34]
  PIN x[35]
    DIRECTION INPUT ;
    USE SIGNAL ;
    PORT
      LAYER M5 ;
        RECT  8.448 0 8.472 0.084 ;
    END
  END x[35]
  PIN x[36]
    DIRECTION INPUT ;
    USE SIGNAL ;
    PORT
      LAYER M5 ;
        RECT  8.544 0 8.568 0.084 ;
    END
  END x[36]
  PIN x[37]
    DIRECTION INPUT ;
    USE SIGNAL ;
    PORT
      LAYER M5 ;
        RECT  8.64 0 8.664 0.084 ;
    END
  END x[37]
  PIN x[38]
    DIRECTION INPUT ;
    USE SIGNAL ;
    PORT
      LAYER M5 ;
        RECT  8.736 0 8.76 0.084 ;
    END
  END x[38]
  PIN x[39]
    DIRECTION INPUT ;
    USE SIGNAL ;
    PORT
      LAYER M5 ;
        RECT  8.832 0 8.856 0.084 ;
    END
  END x[39]
  PIN x[3]
    DIRECTION INPUT ;
    USE SIGNAL ;
    PORT
      LAYER M5 ;
        RECT  5.376 0 5.4 0.084 ;
    END
  END x[3]
  PIN x[40]
    DIRECTION INPUT ;
    USE SIGNAL ;
    PORT
      LAYER M5 ;
        RECT  8.928 0 8.952 0.084 ;
    END
  END x[40]
  PIN x[41]
    DIRECTION INPUT ;
    USE SIGNAL ;
    PORT
      LAYER M5 ;
        RECT  9.024 0 9.048 0.084 ;
    END
  END x[41]
  PIN x[42]
    DIRECTION INPUT ;
    USE SIGNAL ;
    PORT
      LAYER M5 ;
        RECT  9.12 0 9.144 0.084 ;
    END
  END x[42]
  PIN x[43]
    DIRECTION INPUT ;
    USE SIGNAL ;
    PORT
      LAYER M5 ;
        RECT  9.216 0 9.24 0.084 ;
    END
  END x[43]
  PIN x[44]
    DIRECTION INPUT ;
    USE SIGNAL ;
    PORT
      LAYER M5 ;
        RECT  9.312 0 9.336 0.084 ;
    END
  END x[44]
  PIN x[45]
    DIRECTION INPUT ;
    USE SIGNAL ;
    PORT
      LAYER M5 ;
        RECT  9.408 0 9.432 0.084 ;
    END
  END x[45]
  PIN x[46]
    DIRECTION INPUT ;
    USE SIGNAL ;
    PORT
      LAYER M5 ;
        RECT  9.504 0 9.528 0.084 ;
    END
  END x[46]
  PIN x[47]
    DIRECTION INPUT ;
    USE SIGNAL ;
    PORT
      LAYER M5 ;
        RECT  9.6 0 9.624 0.084 ;
    END
  END x[47]
  PIN x[48]
    DIRECTION INPUT ;
    USE SIGNAL ;
    PORT
      LAYER M5 ;
        RECT  9.696 0 9.72 0.084 ;
    END
  END x[48]
  PIN x[49]
    DIRECTION INPUT ;
    USE SIGNAL ;
    PORT
      LAYER M5 ;
        RECT  9.792 0 9.816 0.084 ;
    END
  END x[49]
  PIN x[4]
    DIRECTION INPUT ;
    USE SIGNAL ;
    PORT
      LAYER M5 ;
        RECT  5.472 0 5.496 0.084 ;
    END
  END x[4]
  PIN x[50]
    DIRECTION INPUT ;
    USE SIGNAL ;
    PORT
      LAYER M5 ;
        RECT  9.888 0 9.912 0.084 ;
    END
  END x[50]
  PIN x[51]
    DIRECTION INPUT ;
    USE SIGNAL ;
    PORT
      LAYER M5 ;
        RECT  9.984 0 10.008 0.084 ;
    END
  END x[51]
  PIN x[52]
    DIRECTION INPUT ;
    USE SIGNAL ;
    PORT
      LAYER M5 ;
        RECT  10.08 0 10.104 0.084 ;
    END
  END x[52]
  PIN x[53]
    DIRECTION INPUT ;
    USE SIGNAL ;
    PORT
      LAYER M5 ;
        RECT  10.176 0 10.2 0.084 ;
    END
  END x[53]
  PIN x[54]
    DIRECTION INPUT ;
    USE SIGNAL ;
    PORT
      LAYER M5 ;
        RECT  10.272 0 10.296 0.084 ;
    END
  END x[54]
  PIN x[55]
    DIRECTION INPUT ;
    USE SIGNAL ;
    PORT
      LAYER M5 ;
        RECT  10.368 0 10.392 0.084 ;
    END
  END x[55]
  PIN x[56]
    DIRECTION INPUT ;
    USE SIGNAL ;
    PORT
      LAYER M5 ;
        RECT  10.464 0 10.488 0.084 ;
    END
  END x[56]
  PIN x[57]
    DIRECTION INPUT ;
    USE SIGNAL ;
    PORT
      LAYER M5 ;
        RECT  10.56 0 10.584 0.084 ;
    END
  END x[57]
  PIN x[58]
    DIRECTION INPUT ;
    USE SIGNAL ;
    PORT
      LAYER M5 ;
        RECT  10.656 0 10.68 0.084 ;
    END
  END x[58]
  PIN x[59]
    DIRECTION INPUT ;
    USE SIGNAL ;
    PORT
      LAYER M5 ;
        RECT  10.752 0 10.776 0.084 ;
    END
  END x[59]
  PIN x[5]
    DIRECTION INPUT ;
    USE SIGNAL ;
    PORT
      LAYER M5 ;
        RECT  5.568 0 5.592 0.084 ;
    END
  END x[5]
  PIN x[60]
    DIRECTION INPUT ;
    USE SIGNAL ;
    PORT
      LAYER M5 ;
        RECT  10.848 0 10.872 0.084 ;
    END
  END x[60]
  PIN x[61]
    DIRECTION INPUT ;
    USE SIGNAL ;
    PORT
      LAYER M5 ;
        RECT  10.944 0 10.968 0.084 ;
    END
  END x[61]
  PIN x[62]
    DIRECTION INPUT ;
    USE SIGNAL ;
    PORT
      LAYER M5 ;
        RECT  11.04 0 11.064 0.084 ;
    END
  END x[62]
  PIN x[63]
    DIRECTION INPUT ;
    USE SIGNAL ;
    PORT
      LAYER M5 ;
        RECT  11.136 0 11.16 0.084 ;
    END
  END x[63]
  PIN x[64]
    DIRECTION INPUT ;
    USE SIGNAL ;
    PORT
      LAYER M5 ;
        RECT  11.232 0 11.256 0.084 ;
    END
  END x[64]
  PIN x[65]
    DIRECTION INPUT ;
    USE SIGNAL ;
    PORT
      LAYER M5 ;
        RECT  11.328 0 11.352 0.084 ;
    END
  END x[65]
  PIN x[66]
    DIRECTION INPUT ;
    USE SIGNAL ;
    PORT
      LAYER M5 ;
        RECT  11.424 0 11.448 0.084 ;
    END
  END x[66]
  PIN x[67]
    DIRECTION INPUT ;
    USE SIGNAL ;
    PORT
      LAYER M5 ;
        RECT  11.52 0 11.544 0.084 ;
    END
  END x[67]
  PIN x[68]
    DIRECTION INPUT ;
    USE SIGNAL ;
    PORT
      LAYER M5 ;
        RECT  11.616 0 11.64 0.084 ;
    END
  END x[68]
  PIN x[69]
    DIRECTION INPUT ;
    USE SIGNAL ;
    PORT
      LAYER M5 ;
        RECT  11.712 0 11.736 0.084 ;
    END
  END x[69]
  PIN x[6]
    DIRECTION INPUT ;
    USE SIGNAL ;
    PORT
      LAYER M5 ;
        RECT  5.664 0 5.688 0.084 ;
    END
  END x[6]
  PIN x[70]
    DIRECTION INPUT ;
    USE SIGNAL ;
    PORT
      LAYER M5 ;
        RECT  11.808 0 11.832 0.084 ;
    END
  END x[70]
  PIN x[71]
    DIRECTION INPUT ;
    USE SIGNAL ;
    PORT
      LAYER M5 ;
        RECT  11.904 0 11.928 0.084 ;
    END
  END x[71]
  PIN x[72]
    DIRECTION INPUT ;
    USE SIGNAL ;
    PORT
      LAYER M5 ;
        RECT  12 0 12.024 0.084 ;
    END
  END x[72]
  PIN x[73]
    DIRECTION INPUT ;
    USE SIGNAL ;
    PORT
      LAYER M5 ;
        RECT  12.096 0 12.12 0.084 ;
    END
  END x[73]
  PIN x[74]
    DIRECTION INPUT ;
    USE SIGNAL ;
    PORT
      LAYER M5 ;
        RECT  12.192 0 12.216 0.084 ;
    END
  END x[74]
  PIN x[75]
    DIRECTION INPUT ;
    USE SIGNAL ;
    PORT
      LAYER M5 ;
        RECT  12.288 0 12.312 0.084 ;
    END
  END x[75]
  PIN x[76]
    DIRECTION INPUT ;
    USE SIGNAL ;
    PORT
      LAYER M5 ;
        RECT  12.384 0 12.408 0.084 ;
    END
  END x[76]
  PIN x[77]
    DIRECTION INPUT ;
    USE SIGNAL ;
    PORT
      LAYER M5 ;
        RECT  12.48 0 12.504 0.084 ;
    END
  END x[77]
  PIN x[78]
    DIRECTION INPUT ;
    USE SIGNAL ;
    PORT
      LAYER M5 ;
        RECT  12.576 0 12.6 0.084 ;
    END
  END x[78]
  PIN x[79]
    DIRECTION INPUT ;
    USE SIGNAL ;
    PORT
      LAYER M5 ;
        RECT  12.672 0 12.696 0.084 ;
    END
  END x[79]
  PIN x[7]
    DIRECTION INPUT ;
    USE SIGNAL ;
    PORT
      LAYER M5 ;
        RECT  5.76 0 5.784 0.084 ;
    END
  END x[7]
  PIN x[80]
    DIRECTION INPUT ;
    USE SIGNAL ;
    PORT
      LAYER M5 ;
        RECT  12.768 0 12.792 0.084 ;
    END
  END x[80]
  PIN x[81]
    DIRECTION INPUT ;
    USE SIGNAL ;
    PORT
      LAYER M5 ;
        RECT  12.864 0 12.888 0.084 ;
    END
  END x[81]
  PIN x[82]
    DIRECTION INPUT ;
    USE SIGNAL ;
    PORT
      LAYER M5 ;
        RECT  12.96 0 12.984 0.084 ;
    END
  END x[82]
  PIN x[83]
    DIRECTION INPUT ;
    USE SIGNAL ;
    PORT
      LAYER M5 ;
        RECT  13.056 0 13.08 0.084 ;
    END
  END x[83]
  PIN x[84]
    DIRECTION INPUT ;
    USE SIGNAL ;
    PORT
      LAYER M5 ;
        RECT  13.152 0 13.176 0.084 ;
    END
  END x[84]
  PIN x[85]
    DIRECTION INPUT ;
    USE SIGNAL ;
    PORT
      LAYER M5 ;
        RECT  13.248 0 13.272 0.084 ;
    END
  END x[85]
  PIN x[86]
    DIRECTION INPUT ;
    USE SIGNAL ;
    PORT
      LAYER M5 ;
        RECT  13.344 0 13.368 0.084 ;
    END
  END x[86]
  PIN x[87]
    DIRECTION INPUT ;
    USE SIGNAL ;
    PORT
      LAYER M5 ;
        RECT  13.44 0 13.464 0.084 ;
    END
  END x[87]
  PIN x[88]
    DIRECTION INPUT ;
    USE SIGNAL ;
    PORT
      LAYER M5 ;
        RECT  13.536 0 13.56 0.084 ;
    END
  END x[88]
  PIN x[89]
    DIRECTION INPUT ;
    USE SIGNAL ;
    PORT
      LAYER M5 ;
        RECT  13.632 0 13.656 0.084 ;
    END
  END x[89]
  PIN x[8]
    DIRECTION INPUT ;
    USE SIGNAL ;
    PORT
      LAYER M5 ;
        RECT  5.856 0 5.88 0.084 ;
    END
  END x[8]
  PIN x[90]
    DIRECTION INPUT ;
    USE SIGNAL ;
    PORT
      LAYER M5 ;
        RECT  13.728 0 13.752 0.084 ;
    END
  END x[90]
  PIN x[91]
    DIRECTION INPUT ;
    USE SIGNAL ;
    PORT
      LAYER M5 ;
        RECT  13.824 0 13.848 0.084 ;
    END
  END x[91]
  PIN x[92]
    DIRECTION INPUT ;
    USE SIGNAL ;
    PORT
      LAYER M5 ;
        RECT  13.92 0 13.944 0.084 ;
    END
  END x[92]
  PIN x[93]
    DIRECTION INPUT ;
    USE SIGNAL ;
    PORT
      LAYER M5 ;
        RECT  14.016 0 14.04 0.084 ;
    END
  END x[93]
  PIN x[94]
    DIRECTION INPUT ;
    USE SIGNAL ;
    PORT
      LAYER M5 ;
        RECT  14.112 0 14.136 0.084 ;
    END
  END x[94]
  PIN x[95]
    DIRECTION INPUT ;
    USE SIGNAL ;
    PORT
      LAYER M5 ;
        RECT  14.208 0 14.232 0.084 ;
    END
  END x[95]
  PIN x[96]
    DIRECTION INPUT ;
    USE SIGNAL ;
    PORT
      LAYER M5 ;
        RECT  14.304 0 14.328 0.084 ;
    END
  END x[96]
  PIN x[97]
    DIRECTION INPUT ;
    USE SIGNAL ;
    PORT
      LAYER M5 ;
        RECT  14.4 0 14.424 0.084 ;
    END
  END x[97]
  PIN x[98]
    DIRECTION INPUT ;
    USE SIGNAL ;
    PORT
      LAYER M5 ;
        RECT  14.496 0 14.52 0.084 ;
    END
  END x[98]
  PIN x[99]
    DIRECTION INPUT ;
    USE SIGNAL ;
    PORT
      LAYER M5 ;
        RECT  14.592 0 14.616 0.084 ;
    END
  END x[99]
  PIN x[9]
    DIRECTION INPUT ;
    USE SIGNAL ;
    PORT
      LAYER M5 ;
        RECT  5.952 0 5.976 0.084 ;
    END
  END x[9]
  PIN VDD
    DIRECTION INOUT ;
    USE POWER ;
    PORT
      LAYER M5 ;
        RECT  83.592 2.151 83.712 88.569 ;
        RECT  78.192 2.151 78.312 88.569 ;
        RECT  72.792 2.151 72.912 88.569 ;
        RECT  67.392 2.151 67.512 88.569 ;
        RECT  61.992 2.151 62.112 88.569 ;
        RECT  56.592 2.151 56.712 88.569 ;
        RECT  51.192 2.151 51.312 88.569 ;
        RECT  45.792 2.151 45.912 88.569 ;
        RECT  40.392 2.151 40.512 88.569 ;
        RECT  34.992 2.151 35.112 88.569 ;
        RECT  29.592 2.151 29.712 88.569 ;
        RECT  24.192 2.151 24.312 88.569 ;
        RECT  18.792 2.151 18.912 88.569 ;
        RECT  13.392 2.151 13.512 88.569 ;
        RECT  7.992 2.151 8.112 88.569 ;
        RECT  2.592 2.151 2.712 88.569 ;
    END
  END VDD
  PIN VSS
    DIRECTION INOUT ;
    USE GROUND ;
    PORT
      LAYER M5 ;
        RECT  83.4 2.137 83.52 88.583 ;
        RECT  78 2.137 78.12 88.583 ;
        RECT  72.6 2.137 72.72 88.583 ;
        RECT  67.2 2.137 67.32 88.583 ;
        RECT  61.8 2.137 61.92 88.583 ;
        RECT  56.4 2.137 56.52 88.583 ;
        RECT  51 2.137 51.12 88.583 ;
        RECT  45.6 2.137 45.72 88.583 ;
        RECT  40.2 2.137 40.32 88.583 ;
        RECT  34.8 2.137 34.92 88.583 ;
        RECT  29.4 2.137 29.52 88.583 ;
        RECT  24 2.137 24.12 88.583 ;
        RECT  18.6 2.137 18.72 88.583 ;
        RECT  13.2 2.137 13.32 88.583 ;
        RECT  7.8 2.137 7.92 88.583 ;
        RECT  2.4 2.137 2.52 88.583 ;
    END
  END VSS
  # OT_OBS_CLOSED layer=M5 d_um=1.536 added=459
  OBS
    LAYER RVTN ;
     RECT  2.16 2.16 88.56 2.295 ;
     RECT  2.16 2.565 88.56 2.835 ;
     RECT  2.16 3.105 88.56 3.375 ;
     RECT  2.16 3.645 88.56 3.915 ;
     RECT  2.16 4.185 88.56 4.455 ;
     RECT  2.16 4.725 88.56 4.995 ;
     RECT  2.16 5.265 88.56 5.535 ;
     RECT  2.16 5.805 88.56 6.075 ;
     RECT  2.16 6.345 88.56 6.615 ;
     RECT  2.16 6.885 88.56 7.155 ;
     RECT  2.16 7.425 88.56 7.695 ;
     RECT  2.16 7.965 88.56 8.235 ;
     RECT  2.16 8.505 88.56 8.775 ;
     RECT  2.16 9.045 88.56 9.315 ;
     RECT  2.16 9.585 88.56 9.855 ;
     RECT  2.16 10.125 88.56 10.395 ;
     RECT  2.16 10.665 88.56 10.935 ;
     RECT  2.16 11.205 88.56 11.475 ;
     RECT  2.16 11.745 88.56 12.015 ;
     RECT  2.16 12.285 88.56 12.555 ;
     RECT  2.16 12.825 88.56 13.095 ;
     RECT  2.16 13.365 88.56 13.635 ;
     RECT  2.16 13.905 88.56 14.175 ;
     RECT  2.16 14.445 88.56 14.715 ;
     RECT  2.16 14.985 88.56 15.255 ;
     RECT  2.16 15.525 88.56 15.795 ;
     RECT  2.16 16.065 88.56 16.335 ;
     RECT  2.16 16.605 88.56 16.875 ;
     RECT  2.16 17.145 88.56 17.415 ;
     RECT  2.16 17.685 88.56 17.955 ;
     RECT  2.16 18.225 88.56 18.495 ;
     RECT  2.16 18.765 88.56 19.035 ;
     RECT  2.16 19.305 88.56 19.575 ;
     RECT  2.16 19.845 88.56 20.115 ;
     RECT  2.16 20.385 88.56 20.655 ;
     RECT  2.16 20.925 88.56 21.195 ;
     RECT  2.16 21.465 88.56 21.735 ;
     RECT  2.16 22.005 88.56 22.275 ;
     RECT  2.16 22.545 88.56 22.815 ;
     RECT  2.16 23.085 88.56 23.355 ;
     RECT  2.16 23.625 88.56 23.895 ;
     RECT  2.16 24.165 88.56 24.435 ;
     RECT  2.16 24.705 88.56 24.975 ;
     RECT  2.16 25.245 88.56 25.515 ;
     RECT  2.16 25.785 88.56 26.055 ;
     RECT  2.16 26.325 88.56 26.595 ;
     RECT  2.16 26.865 88.56 27.135 ;
     RECT  2.16 27.405 88.56 27.675 ;
     RECT  2.16 27.945 88.56 28.215 ;
     RECT  2.16 28.485 88.56 28.755 ;
     RECT  2.16 29.025 88.56 29.295 ;
     RECT  2.16 29.565 88.56 29.835 ;
     RECT  2.16 30.105 88.56 30.375 ;
     RECT  2.16 30.645 88.56 30.915 ;
     RECT  2.16 31.185 88.56 31.455 ;
     RECT  2.16 31.725 88.56 31.995 ;
     RECT  2.16 32.265 88.56 32.535 ;
     RECT  2.16 32.805 88.56 33.075 ;
     RECT  2.16 33.345 88.56 33.615 ;
     RECT  2.16 33.885 88.56 34.155 ;
     RECT  2.16 34.425 88.56 34.695 ;
     RECT  2.16 34.965 88.56 35.235 ;
     RECT  2.16 35.505 88.56 35.775 ;
     RECT  2.16 36.045 88.56 36.315 ;
     RECT  2.16 36.585 88.56 36.855 ;
     RECT  2.16 37.125 88.56 37.395 ;
     RECT  2.16 37.665 88.56 37.935 ;
     RECT  2.16 38.205 88.56 38.475 ;
     RECT  2.16 38.745 88.56 39.015 ;
     RECT  2.16 39.285 88.56 39.555 ;
     RECT  2.16 39.825 88.56 40.095 ;
     RECT  2.16 40.365 88.56 40.635 ;
     RECT  2.16 40.905 88.56 41.175 ;
     RECT  2.16 41.445 88.56 41.715 ;
     RECT  2.16 41.985 88.56 42.255 ;
     RECT  2.16 42.525 88.56 42.795 ;
     RECT  2.16 43.065 88.56 43.335 ;
     RECT  2.16 43.605 88.56 43.875 ;
     RECT  2.16 44.145 88.56 44.415 ;
     RECT  2.16 44.685 88.56 44.955 ;
     RECT  2.16 45.225 88.56 45.495 ;
     RECT  2.16 45.765 88.56 46.035 ;
     RECT  2.16 46.305 88.56 46.575 ;
     RECT  2.16 46.845 88.56 47.115 ;
     RECT  2.16 47.385 88.56 47.655 ;
     RECT  2.16 47.925 88.56 48.195 ;
     RECT  2.16 48.465 88.56 48.735 ;
     RECT  2.16 49.005 88.56 49.275 ;
     RECT  2.16 49.545 88.56 49.815 ;
     RECT  2.16 50.085 88.56 50.355 ;
     RECT  2.16 50.625 88.56 50.895 ;
     RECT  2.16 51.165 88.56 51.435 ;
     RECT  2.16 51.705 88.56 51.975 ;
     RECT  2.16 52.245 88.56 52.515 ;
     RECT  2.16 52.785 88.56 53.055 ;
     RECT  2.16 53.325 88.56 53.595 ;
     RECT  2.16 53.865 88.56 54.135 ;
     RECT  2.16 54.405 88.56 54.675 ;
     RECT  2.16 54.945 88.56 55.215 ;
     RECT  2.16 55.485 88.56 55.755 ;
     RECT  2.16 56.025 88.56 56.295 ;
     RECT  2.16 56.565 88.56 56.835 ;
     RECT  2.16 57.105 88.56 57.375 ;
     RECT  2.16 57.645 88.56 57.915 ;
     RECT  2.16 58.185 88.56 58.455 ;
     RECT  2.16 58.725 88.56 58.995 ;
     RECT  2.16 59.265 88.56 59.535 ;
     RECT  2.16 59.805 88.56 60.075 ;
     RECT  2.16 60.345 88.56 60.615 ;
     RECT  2.16 60.885 88.56 61.155 ;
     RECT  2.16 61.425 88.56 61.695 ;
     RECT  2.16 61.965 88.56 62.235 ;
     RECT  2.16 62.505 88.56 62.775 ;
     RECT  2.16 63.045 88.56 63.315 ;
     RECT  2.16 63.585 88.56 63.855 ;
     RECT  2.16 64.125 88.56 64.395 ;
     RECT  2.16 64.665 88.56 64.935 ;
     RECT  2.16 65.205 88.56 65.475 ;
     RECT  2.16 65.745 88.56 66.015 ;
     RECT  2.16 66.285 88.56 66.555 ;
     RECT  2.16 66.825 88.56 67.095 ;
     RECT  2.16 67.365 88.56 67.635 ;
     RECT  2.16 67.905 88.56 68.175 ;
     RECT  2.16 68.445 88.56 68.715 ;
     RECT  2.16 68.985 88.56 69.255 ;
     RECT  2.16 69.525 88.56 69.795 ;
     RECT  2.16 70.065 88.56 70.335 ;
     RECT  2.16 70.605 88.56 70.875 ;
     RECT  2.16 71.145 88.56 71.415 ;
     RECT  2.16 71.685 88.56 71.955 ;
     RECT  2.16 72.225 88.56 72.495 ;
     RECT  2.16 72.765 88.56 73.035 ;
     RECT  2.16 73.305 88.56 73.575 ;
     RECT  2.16 73.845 88.56 74.115 ;
     RECT  2.16 74.385 88.56 74.655 ;
     RECT  2.16 74.925 88.56 75.195 ;
     RECT  2.16 75.465 88.56 75.735 ;
     RECT  2.16 76.005 88.56 76.275 ;
     RECT  2.16 76.545 88.56 76.815 ;
     RECT  2.16 77.085 88.56 77.355 ;
     RECT  2.16 77.625 88.56 77.895 ;
     RECT  2.16 78.165 88.56 78.435 ;
     RECT  2.16 78.705 88.56 78.975 ;
     RECT  2.16 79.245 88.56 79.515 ;
     RECT  2.16 79.785 88.56 80.055 ;
     RECT  2.16 80.325 88.56 80.595 ;
     RECT  2.16 80.865 88.56 81.135 ;
     RECT  2.16 81.405 88.56 81.675 ;
     RECT  2.16 81.945 88.56 82.215 ;
     RECT  2.16 82.485 88.56 82.755 ;
     RECT  2.16 83.025 88.56 83.295 ;
     RECT  2.16 83.565 88.56 83.835 ;
     RECT  2.16 84.105 88.56 84.375 ;
     RECT  2.16 84.645 88.56 84.915 ;
     RECT  2.16 85.185 88.56 85.455 ;
     RECT  2.16 85.725 88.56 85.995 ;
     RECT  2.16 86.265 88.56 86.535 ;
     RECT  2.16 86.805 88.56 87.075 ;
     RECT  2.16 87.345 88.56 87.615 ;
     RECT  2.16 87.885 88.56 88.155 ;
     RECT  2.16 88.425 88.56 88.56 ;
    LAYER RVTP ;
     RECT  2.16 2.295 88.56 2.565 ;
     RECT  2.16 2.835 88.56 3.105 ;
     RECT  2.16 3.375 88.56 3.645 ;
     RECT  2.16 3.915 88.56 4.185 ;
     RECT  2.16 4.455 88.56 4.725 ;
     RECT  2.16 4.995 88.56 5.265 ;
     RECT  2.16 5.535 88.56 5.805 ;
     RECT  2.16 6.075 88.56 6.345 ;
     RECT  2.16 6.615 88.56 6.885 ;
     RECT  2.16 7.155 88.56 7.425 ;
     RECT  2.16 7.695 88.56 7.965 ;
     RECT  2.16 8.235 88.56 8.505 ;
     RECT  2.16 8.775 88.56 9.045 ;
     RECT  2.16 9.315 88.56 9.585 ;
     RECT  2.16 9.855 88.56 10.125 ;
     RECT  2.16 10.395 88.56 10.665 ;
     RECT  2.16 10.935 88.56 11.205 ;
     RECT  2.16 11.475 88.56 11.745 ;
     RECT  2.16 12.015 88.56 12.285 ;
     RECT  2.16 12.555 88.56 12.825 ;
     RECT  2.16 13.095 88.56 13.365 ;
     RECT  2.16 13.635 88.56 13.905 ;
     RECT  2.16 14.175 88.56 14.445 ;
     RECT  2.16 14.715 88.56 14.985 ;
     RECT  2.16 15.255 88.56 15.525 ;
     RECT  2.16 15.795 88.56 16.065 ;
     RECT  2.16 16.335 88.56 16.605 ;
     RECT  2.16 16.875 88.56 17.145 ;
     RECT  2.16 17.415 88.56 17.685 ;
     RECT  2.16 17.955 88.56 18.225 ;
     RECT  2.16 18.495 88.56 18.765 ;
     RECT  2.16 19.035 88.56 19.305 ;
     RECT  2.16 19.575 88.56 19.845 ;
     RECT  2.16 20.115 88.56 20.385 ;
     RECT  2.16 20.655 88.56 20.925 ;
     RECT  2.16 21.195 88.56 21.465 ;
     RECT  2.16 21.735 88.56 22.005 ;
     RECT  2.16 22.275 88.56 22.545 ;
     RECT  2.16 22.815 88.56 23.085 ;
     RECT  2.16 23.355 88.56 23.625 ;
     RECT  2.16 23.895 88.56 24.165 ;
     RECT  2.16 24.435 88.56 24.705 ;
     RECT  2.16 24.975 88.56 25.245 ;
     RECT  2.16 25.515 88.56 25.785 ;
     RECT  2.16 26.055 88.56 26.325 ;
     RECT  2.16 26.595 88.56 26.865 ;
     RECT  2.16 27.135 88.56 27.405 ;
     RECT  2.16 27.675 88.56 27.945 ;
     RECT  2.16 28.215 88.56 28.485 ;
     RECT  2.16 28.755 88.56 29.025 ;
     RECT  2.16 29.295 88.56 29.565 ;
     RECT  2.16 29.835 88.56 30.105 ;
     RECT  2.16 30.375 88.56 30.645 ;
     RECT  2.16 30.915 88.56 31.185 ;
     RECT  2.16 31.455 88.56 31.725 ;
     RECT  2.16 31.995 88.56 32.265 ;
     RECT  2.16 32.535 88.56 32.805 ;
     RECT  2.16 33.075 88.56 33.345 ;
     RECT  2.16 33.615 88.56 33.885 ;
     RECT  2.16 34.155 88.56 34.425 ;
     RECT  2.16 34.695 88.56 34.965 ;
     RECT  2.16 35.235 88.56 35.505 ;
     RECT  2.16 35.775 88.56 36.045 ;
     RECT  2.16 36.315 88.56 36.585 ;
     RECT  2.16 36.855 88.56 37.125 ;
     RECT  2.16 37.395 88.56 37.665 ;
     RECT  2.16 37.935 88.56 38.205 ;
     RECT  2.16 38.475 88.56 38.745 ;
     RECT  2.16 39.015 88.56 39.285 ;
     RECT  2.16 39.555 88.56 39.825 ;
     RECT  2.16 40.095 88.56 40.365 ;
     RECT  2.16 40.635 88.56 40.905 ;
     RECT  2.16 41.175 88.56 41.445 ;
     RECT  2.16 41.715 88.56 41.985 ;
     RECT  2.16 42.255 88.56 42.525 ;
     RECT  2.16 42.795 88.56 43.065 ;
     RECT  2.16 43.335 88.56 43.605 ;
     RECT  2.16 43.875 88.56 44.145 ;
     RECT  2.16 44.415 88.56 44.685 ;
     RECT  2.16 44.955 88.56 45.225 ;
     RECT  2.16 45.495 88.56 45.765 ;
     RECT  2.16 46.035 88.56 46.305 ;
     RECT  2.16 46.575 88.56 46.845 ;
     RECT  2.16 47.115 88.56 47.385 ;
     RECT  2.16 47.655 88.56 47.925 ;
     RECT  2.16 48.195 88.56 48.465 ;
     RECT  2.16 48.735 88.56 49.005 ;
     RECT  2.16 49.275 88.56 49.545 ;
     RECT  2.16 49.815 88.56 50.085 ;
     RECT  2.16 50.355 88.56 50.625 ;
     RECT  2.16 50.895 88.56 51.165 ;
     RECT  2.16 51.435 88.56 51.705 ;
     RECT  2.16 51.975 88.56 52.245 ;
     RECT  2.16 52.515 88.56 52.785 ;
     RECT  2.16 53.055 88.56 53.325 ;
     RECT  2.16 53.595 88.56 53.865 ;
     RECT  2.16 54.135 88.56 54.405 ;
     RECT  2.16 54.675 88.56 54.945 ;
     RECT  2.16 55.215 88.56 55.485 ;
     RECT  2.16 55.755 88.56 56.025 ;
     RECT  2.16 56.295 88.56 56.565 ;
     RECT  2.16 56.835 88.56 57.105 ;
     RECT  2.16 57.375 88.56 57.645 ;
     RECT  2.16 57.915 88.56 58.185 ;
     RECT  2.16 58.455 88.56 58.725 ;
     RECT  2.16 58.995 88.56 59.265 ;
     RECT  2.16 59.535 88.56 59.805 ;
     RECT  2.16 60.075 88.56 60.345 ;
     RECT  2.16 60.615 88.56 60.885 ;
     RECT  2.16 61.155 88.56 61.425 ;
     RECT  2.16 61.695 88.56 61.965 ;
     RECT  2.16 62.235 88.56 62.505 ;
     RECT  2.16 62.775 88.56 63.045 ;
     RECT  2.16 63.315 88.56 63.585 ;
     RECT  2.16 63.855 88.56 64.125 ;
     RECT  2.16 64.395 88.56 64.665 ;
     RECT  2.16 64.935 88.56 65.205 ;
     RECT  2.16 65.475 88.56 65.745 ;
     RECT  2.16 66.015 88.56 66.285 ;
     RECT  2.16 66.555 88.56 66.825 ;
     RECT  2.16 67.095 88.56 67.365 ;
     RECT  2.16 67.635 88.56 67.905 ;
     RECT  2.16 68.175 88.56 68.445 ;
     RECT  2.16 68.715 88.56 68.985 ;
     RECT  2.16 69.255 88.56 69.525 ;
     RECT  2.16 69.795 88.56 70.065 ;
     RECT  2.16 70.335 88.56 70.605 ;
     RECT  2.16 70.875 88.56 71.145 ;
     RECT  2.16 71.415 88.56 71.685 ;
     RECT  2.16 71.955 88.56 72.225 ;
     RECT  2.16 72.495 88.56 72.765 ;
     RECT  2.16 73.035 88.56 73.305 ;
     RECT  2.16 73.575 88.56 73.845 ;
     RECT  2.16 74.115 88.56 74.385 ;
     RECT  2.16 74.655 88.56 74.925 ;
     RECT  2.16 75.195 88.56 75.465 ;
     RECT  2.16 75.735 88.56 76.005 ;
     RECT  2.16 76.275 88.56 76.545 ;
     RECT  2.16 76.815 88.56 77.085 ;
     RECT  2.16 77.355 88.56 77.625 ;
     RECT  2.16 77.895 88.56 78.165 ;
     RECT  2.16 78.435 88.56 78.705 ;
     RECT  2.16 78.975 88.56 79.245 ;
     RECT  2.16 79.515 88.56 79.785 ;
     RECT  2.16 80.055 88.56 80.325 ;
     RECT  2.16 80.595 88.56 80.865 ;
     RECT  2.16 81.135 88.56 81.405 ;
     RECT  2.16 81.675 88.56 81.945 ;
     RECT  2.16 82.215 88.56 82.485 ;
     RECT  2.16 82.755 88.56 83.025 ;
     RECT  2.16 83.295 88.56 83.565 ;
     RECT  2.16 83.835 88.56 84.105 ;
     RECT  2.16 84.375 88.56 84.645 ;
     RECT  2.16 84.915 88.56 85.185 ;
     RECT  2.16 85.455 88.56 85.725 ;
     RECT  2.16 85.995 88.56 86.265 ;
     RECT  2.16 86.535 88.56 86.805 ;
     RECT  2.16 87.075 88.56 87.345 ;
     RECT  2.16 87.615 88.56 87.885 ;
     RECT  2.16 88.155 88.56 88.425 ;
    LAYER M1 ;
     RECT  2.16 2.151 88.56 88.569 ;
    LAYER M2 ;
     RECT  2.16 2.151 4.711 88.569 ;
     RECT  4.711 2.106 5.567 88.569 ;
     RECT  5.567 2.151 7.267 88.569 ;
     RECT  7.267 2.151 7.799 88.92 ;
     RECT  7.799 2.151 19.759 88.569 ;
     RECT  19.759 2.106 20.399 88.569 ;
     RECT  20.399 2.151 21.631 88.569 ;
     RECT  21.631 2.106 22.199 88.569 ;
     RECT  23.575 1.152 23.819 1.17 ;
     RECT  22.199 2.151 28.903 88.569 ;
     RECT  28.903 2.106 30.299 88.569 ;
     RECT  30.299 2.151 33.079 88.569 ;
     RECT  33.079 2.106 33.431 88.569 ;
     RECT  33.431 2.151 34.195 88.569 ;
     RECT  34.195 2.106 34.691 88.569 ;
     RECT  34.691 2.151 34.771 88.569 ;
     RECT  34.771 2.151 36.643 88.614 ;
     RECT  36.643 2.106 37.643 88.614 ;
     RECT  37.643 2.151 37.679 88.614 ;
     RECT  37.679 2.151 39.055 88.569 ;
     RECT  39.055 2.106 39.703 88.569 ;
     RECT  39.703 2.034 40.891 88.569 ;
     RECT  40.891 1.962 41.855 88.569 ;
     RECT  41.855 2.106 42.107 88.569 ;
     RECT  42.107 2.151 44.167 88.569 ;
     RECT  44.167 2.106 48.415 88.569 ;
     RECT  48.415 2.034 49.991 88.569 ;
     RECT  49.991 2.07 51.835 88.569 ;
     RECT  51.835 2.034 52.231 88.569 ;
     RECT  52.231 1.998 53.455 88.569 ;
     RECT  53.455 1.962 54.887 88.569 ;
     RECT  54.887 2.07 55.723 88.569 ;
     RECT  55.723 1.998 57.191 88.569 ;
     RECT  57.191 2.106 58.631 88.569 ;
     RECT  58.631 2.151 59.791 88.569 ;
     RECT  59.791 2.106 60.367 88.569 ;
     RECT  60.367 2.07 62.743 88.569 ;
     RECT  62.743 2.034 71.267 88.569 ;
     RECT  71.267 2.106 75.767 88.569 ;
     RECT  75.767 2.151 88.56 88.569 ;
    LAYER M3 ;
     RECT  8.28 0.091 8.91 0.139 ;
     RECT  23.4 0.091 23.418 0.139 ;
     RECT  24.912 0.091 24.93 0.221 ;
     RECT  26.028 0.091 26.622 0.221 ;
     RECT  22.968 0.139 23.418 0.235 ;
     RECT  28.332 0.091 28.35 0.235 ;
     RECT  13.896 0.091 13.914 0.269 ;
     RECT  8.28 0.139 9.018 0.317 ;
     RECT  22.968 0.235 23.742 0.365 ;
     RECT  26.028 0.221 26.334 0.365 ;
     RECT  8.28 0.317 8.766 0.413 ;
     RECT  27.288 0.235 27.306 0.413 ;
     RECT  23.04 0.365 23.742 0.461 ;
     RECT  4.68 0.091 4.698 0.523 ;
     RECT  5.652 0.091 5.67 0.523 ;
     RECT  10.296 0.091 10.314 0.523 ;
     RECT  4.68 0.523 5.67 0.571 ;
     RECT  6.48 0.091 6.498 0.571 ;
     RECT  23.4 0.461 23.742 1.147 ;
     RECT  28.188 0.235 28.35 1.147 ;
     RECT  4.032 0.571 6.498 1.723 ;
     RECT  9.972 0.523 10.314 1.723 ;
     RECT  12.6 0.523 12.618 1.723 ;
     RECT  16.56 1.099 16.578 1.723 ;
     RECT  18.072 0.091 18.09 1.723 ;
     RECT  20.772 0.091 21.294 1.723 ;
     RECT  23.4 1.147 23.814 1.723 ;
     RECT  24.66 1.147 24.678 1.723 ;
     RECT  28.188 1.147 28.53 1.723 ;
     RECT  8.28 0.413 8.298 1.771 ;
     RECT  9.072 1.723 9.09 1.771 ;
     RECT  11.916 1.723 13.122 1.771 ;
     RECT  13.86 1.723 13.878 1.771 ;
     RECT  19.836 1.723 19.854 1.771 ;
     RECT  8.28 1.771 9.09 1.819 ;
     RECT  9.972 1.723 10.998 1.819 ;
     RECT  19.728 1.771 19.854 1.963 ;
     RECT  53.46 1.957 53.478 1.993 ;
     RECT  17.424 1.723 18.09 2.011 ;
     RECT  19.116 1.963 19.854 2.011 ;
     RECT  40.896 1.957 40.914 2.029 ;
     RECT  41.832 1.957 41.85 2.029 ;
     RECT  52.236 1.993 52.254 2.029 ;
     RECT  53.28 1.993 53.478 2.029 ;
     RECT  36.252 2.011 36.27 2.059 ;
     RECT  49.968 2.029 49.986 2.065 ;
     RECT  51.84 2.029 52.254 2.065 ;
     RECT  54.864 1.957 54.882 2.065 ;
     RECT  55.728 1.993 55.746 2.065 ;
     RECT  62.748 2.029 62.766 2.065 ;
     RECT  17.424 2.011 19.854 2.101 ;
     RECT  20.772 1.723 22.482 2.101 ;
     RECT  27.144 1.723 29.574 2.101 ;
     RECT  30.888 0.523 30.906 2.101 ;
     RECT  34.632 2.059 34.65 2.101 ;
     RECT  36 2.059 36.27 2.101 ;
     RECT  37.476 2.059 37.494 2.101 ;
     RECT  39.708 2.029 39.726 2.101 ;
     RECT  40.896 2.029 41.85 2.101 ;
     RECT  48.42 2.029 48.438 2.101 ;
     RECT  49.32 2.065 49.986 2.101 ;
     RECT  51.696 2.065 52.254 2.101 ;
     RECT  53.28 2.029 53.55 2.101 ;
     RECT  54.864 2.065 56.322 2.101 ;
     RECT  57.168 1.993 57.186 2.101 ;
     RECT  60.372 2.065 62.766 2.101 ;
     RECT  71.244 2.029 71.262 2.101 ;
     RECT  36 2.101 36.666 2.107 ;
     RECT  8.28 1.819 10.998 2.143 ;
     RECT  34.2 2.101 34.686 2.143 ;
     RECT  39.06 2.101 40.05 2.143 ;
     RECT  40.896 2.101 42.102 2.143 ;
     RECT  44.172 2.101 45.27 2.143 ;
     RECT  50.796 2.101 50.814 2.143 ;
     RECT  51.696 2.101 53.694 2.143 ;
     RECT  54.864 2.101 56.358 2.143 ;
     RECT  57.168 2.101 57.69 2.143 ;
     RECT  66.024 2.029 66.726 2.143 ;
     RECT  7.815 2.143 10.998 2.155 ;
     RECT  11.772 1.771 13.95 2.155 ;
     RECT  15.048 1.723 16.578 2.155 ;
     RECT  17.424 2.101 22.482 2.155 ;
     RECT  23.4 1.723 26.262 2.155 ;
     RECT  4.032 1.723 6.678 2.191 ;
     RECT  7.416 2.155 10.998 2.191 ;
     RECT  11.772 2.155 16.578 2.191 ;
     RECT  17.424 2.155 26.262 2.191 ;
     RECT  27.144 2.101 30.906 2.191 ;
     RECT  35.712 2.107 36.666 2.191 ;
     RECT  37.476 2.101 37.638 2.191 ;
     RECT  44.172 2.143 45.705 2.191 ;
     RECT  47.124 2.101 47.322 2.191 ;
     RECT  48.42 2.101 49.986 2.191 ;
     RECT  54.864 2.143 57.69 2.191 ;
     RECT  58.608 2.101 58.626 2.191 ;
     RECT  59.796 2.101 62.766 2.191 ;
     RECT  64.044 2.101 64.062 2.191 ;
     RECT  64.944 2.101 64.962 2.191 ;
     RECT  66.024 2.143 67.305 2.191 ;
     RECT  69.66 2.101 71.262 2.191 ;
     RECT  72.615 2.143 72.705 2.191 ;
     RECT  78.015 2.143 78.105 2.191 ;
     RECT  54.864 2.191 58.914 2.203 ;
     RECT  59.796 2.191 62.874 2.203 ;
     RECT  27.036 2.191 30.906 2.227 ;
     RECT  50.796 2.143 53.694 2.227 ;
     RECT  54.864 2.203 62.874 2.227 ;
     RECT  66.024 2.191 67.554 2.227 ;
     RECT  68.4 2.191 68.418 2.227 ;
     RECT  69.66 2.191 71.766 2.227 ;
     RECT  72.615 2.191 73.134 2.227 ;
     RECT  77.976 2.191 79.254 2.227 ;
     RECT  43.488 2.191 47.322 2.251 ;
     RECT  66.024 2.227 68.418 2.251 ;
     RECT  77.976 2.227 81.378 2.251 ;
     RECT  39.06 2.143 42.102 2.263 ;
     RECT  42.948 2.251 47.322 2.263 ;
     RECT  50.796 2.227 62.874 2.263 ;
     RECT  64.044 2.191 64.962 2.263 ;
     RECT  66.024 2.251 68.634 2.263 ;
     RECT  69.48 2.227 71.766 2.263 ;
     RECT  72.615 2.227 73.386 2.263 ;
     RECT  77.4 2.251 81.378 2.263 ;
     RECT  35.64 2.191 38.106 2.299 ;
     RECT  39.06 2.263 47.574 2.299 ;
     RECT  74.592 2.263 74.61 2.299 ;
     RECT  75.744 2.101 75.762 2.299 ;
     RECT  33.084 2.101 33.426 2.335 ;
     RECT  34.2 2.143 34.905 2.335 ;
     RECT  35.64 2.299 47.574 2.335 ;
     RECT  48.312 2.191 49.986 2.335 ;
     RECT  33.084 2.335 34.905 2.347 ;
     RECT  35.64 2.335 49.986 2.347 ;
     RECT  4.032 2.191 26.298 2.371 ;
     RECT  27.036 2.227 31.59 2.371 ;
     RECT  50.796 2.263 64.962 2.371 ;
     RECT  66.024 2.263 73.53 2.371 ;
     RECT  74.448 2.299 74.61 2.371 ;
     RECT  75.564 2.299 75.762 2.371 ;
     RECT  76.86 2.263 81.378 2.371 ;
     RECT  82.368 2.251 82.386 2.371 ;
     RECT  83.415 2.143 83.505 2.371 ;
     RECT  2.415 2.143 2.505 2.413 ;
     RECT  76.572 2.371 83.505 2.413 ;
     RECT  3.996 2.371 26.298 2.461 ;
     RECT  27.036 2.371 31.698 2.461 ;
     RECT  33.084 2.347 49.986 2.461 ;
     RECT  74.376 2.371 75.762 2.461 ;
     RECT  76.572 2.413 83.697 2.461 ;
     RECT  3.996 2.461 49.986 2.605 ;
     RECT  50.796 2.371 73.53 2.605 ;
     RECT  74.376 2.461 83.697 2.605 ;
     RECT  3.996 2.605 83.697 2.641 ;
     RECT  3.996 2.641 83.718 2.875 ;
     RECT  84.996 2.731 85.014 2.875 ;
     RECT  3.996 2.875 85.014 2.911 ;
     RECT  2.415 2.413 2.697 3.158 ;
     RECT  3.492 2.911 85.014 3.158 ;
     RECT  2.415 3.158 85.014 3.685 ;
     RECT  2.415 3.685 85.23 3.955 ;
     RECT  2.415 3.955 85.626 4.261 ;
     RECT  2.415 4.261 85.734 4.765 ;
     RECT  86.508 4.261 86.526 4.765 ;
     RECT  2.415 4.765 86.526 4.801 ;
     RECT  2.415 4.801 86.706 5.305 ;
     RECT  2.376 5.305 86.706 5.707 ;
     RECT  2.304 5.707 86.706 5.801 ;
     RECT  2.304 5.801 2.754 5.909 ;
     RECT  2.304 5.909 2.697 6.035 ;
     RECT  3.636 5.801 86.706 6.151 ;
     RECT  3.636 6.151 87.39 6.241 ;
     RECT  3.636 6.241 87.534 6.385 ;
     RECT  3.636 6.385 87.678 6.547 ;
     RECT  2.415 6.035 2.697 6.655 ;
     RECT  3.6 6.547 87.678 6.655 ;
     RECT  2.415 6.655 87.678 6.781 ;
     RECT  2.415 6.781 87.93 7.123 ;
     RECT  2.415 7.123 88.002 7.231 ;
     RECT  2.415 7.231 88.11 7.321 ;
     RECT  2.415 7.321 88.254 7.771 ;
     RECT  2.415 7.771 88.326 8.041 ;
     RECT  2.415 8.041 88.362 8.429 ;
     RECT  34.668 8.429 88.362 9.085 ;
     RECT  2.415 8.429 33.93 9.247 ;
     RECT  34.668 9.085 88.434 9.247 ;
     RECT  2.415 9.247 88.434 9.355 ;
     RECT  2.412 9.355 88.434 9.509 ;
     RECT  2.415 9.509 88.434 10.291 ;
     RECT  2.376 10.291 88.434 11.281 ;
     RECT  2.376 11.281 88.47 11.669 ;
     RECT  2.376 11.669 54.522 11.939 ;
     RECT  2.415 11.939 54.522 12.479 ;
     RECT  38.736 12.479 54.522 12.721 ;
     RECT  55.26 11.669 88.47 12.721 ;
     RECT  38.736 12.721 88.47 13.261 ;
     RECT  2.415 12.479 37.89 13.405 ;
     RECT  38.664 13.261 88.47 13.405 ;
     RECT  2.415 13.405 88.47 13.441 ;
     RECT  2.415 13.441 88.506 13.559 ;
     RECT  2.415 13.559 76.086 13.973 ;
     RECT  2.415 13.973 76.014 14.099 ;
     RECT  76.86 13.559 88.506 14.243 ;
     RECT  76.86 14.243 78.966 14.341 ;
     RECT  50.112 14.099 76.014 14.719 ;
     RECT  76.788 14.341 78.966 14.719 ;
     RECT  2.415 14.099 49.374 14.989 ;
     RECT  50.112 14.719 78.966 14.989 ;
     RECT  79.74 14.243 88.506 14.989 ;
     RECT  2.376 14.989 49.374 15.061 ;
     RECT  50.112 14.989 88.506 15.061 ;
     RECT  2.376 15.061 88.506 15.089 ;
     RECT  2.376 15.089 79.974 15.179 ;
     RECT  2.376 15.179 79.866 15.251 ;
     RECT  80.928 15.089 88.506 15.359 ;
     RECT  2.376 15.251 79.578 15.449 ;
     RECT  80.964 15.359 88.506 15.629 ;
     RECT  2.415 15.449 79.578 16.105 ;
     RECT  2.415 16.105 80.19 16.141 ;
     RECT  2.415 16.141 80.334 16.259 ;
     RECT  81.108 15.629 88.506 16.259 ;
     RECT  81.144 16.259 88.506 16.673 ;
     RECT  2.415 16.259 80.19 16.951 ;
     RECT  2.376 16.951 80.19 16.987 ;
     RECT  2.376 16.987 80.262 17.069 ;
     RECT  2.376 17.069 80.226 17.249 ;
     RECT  2.376 17.249 53.19 18.031 ;
     RECT  53.928 17.249 80.226 18.031 ;
     RECT  81.144 16.673 81.666 18.031 ;
     RECT  2.376 18.031 80.226 18.043 ;
     RECT  80.964 18.031 81.666 18.043 ;
     RECT  2.376 18.043 81.666 18.329 ;
     RECT  2.415 18.329 81.666 18.463 ;
     RECT  82.512 16.673 88.506 18.463 ;
     RECT  2.415 18.463 88.506 18.689 ;
     RECT  55.62 18.689 88.506 18.797 ;
     RECT  2.415 18.689 54.81 19.111 ;
     RECT  55.62 18.797 88.398 19.265 ;
     RECT  55.62 19.265 80.082 19.301 ;
     RECT  2.376 19.111 54.81 19.373 ;
     RECT  55.836 19.301 80.082 19.769 ;
     RECT  2.415 19.373 54.81 19.849 ;
     RECT  2.415 19.849 54.846 19.921 ;
     RECT  2.415 19.921 55.098 20.317 ;
     RECT  55.836 19.769 79.47 20.317 ;
     RECT  80.856 19.265 88.398 21.271 ;
     RECT  80.388 21.271 88.398 21.361 ;
     RECT  2.415 20.317 79.47 21.533 ;
     RECT  43.596 21.533 79.47 21.901 ;
     RECT  80.244 21.361 88.398 21.901 ;
     RECT  2.415 21.533 42.75 22.279 ;
     RECT  43.596 21.901 88.398 22.279 ;
     RECT  2.415 22.279 88.398 22.613 ;
     RECT  2.415 22.613 55.062 23.557 ;
     RECT  2.34 23.557 55.062 23.863 ;
     RECT  55.836 22.613 88.398 23.863 ;
     RECT  2.34 23.863 88.398 24.269 ;
     RECT  2.34 24.269 57.618 24.331 ;
     RECT  2.304 24.331 57.618 24.871 ;
     RECT  2.268 24.871 57.618 25.051 ;
     RECT  2.268 25.051 57.654 25.141 ;
     RECT  58.428 24.269 88.398 25.141 ;
     RECT  2.268 25.141 88.398 26.591 ;
     RECT  50.292 26.591 88.398 26.671 ;
     RECT  50.292 26.671 88.47 27.445 ;
     RECT  2.268 26.591 49.482 27.643 ;
     RECT  50.22 27.445 88.47 27.643 ;
     RECT  2.268 27.643 88.47 28.319 ;
     RECT  47.304 28.319 88.47 28.409 ;
     RECT  2.268 28.319 46.386 28.451 ;
     RECT  47.772 28.409 88.47 28.949 ;
     RECT  47.772 28.949 74.358 29.219 ;
     RECT  47.772 29.219 74.034 29.335 ;
     RECT  47.124 29.335 74.034 29.489 ;
     RECT  2.268 28.451 46.242 29.561 ;
     RECT  2.304 29.561 46.242 29.641 ;
     RECT  47.124 29.489 49.59 29.759 ;
     RECT  2.304 29.641 46.314 29.875 ;
     RECT  47.124 29.759 49.482 29.875 ;
     RECT  75.096 28.949 88.47 29.939 ;
     RECT  75.096 29.939 76.806 30.181 ;
     RECT  74.988 30.181 76.806 30.613 ;
     RECT  2.304 29.875 49.482 30.685 ;
     RECT  77.652 29.939 88.47 30.811 ;
     RECT  2.304 30.685 49.698 30.883 ;
     RECT  50.544 29.489 74.034 30.883 ;
     RECT  74.844 30.613 76.806 30.883 ;
     RECT  2.304 30.883 49.77 30.919 ;
     RECT  50.544 30.883 76.806 30.919 ;
     RECT  77.616 30.811 88.47 31.153 ;
     RECT  2.304 30.919 76.806 31.351 ;
     RECT  77.544 31.153 88.47 31.351 ;
     RECT  2.304 31.351 88.47 34.385 ;
     RECT  2.304 34.385 60.318 35.671 ;
     RECT  61.056 34.385 88.47 35.671 ;
     RECT  2.304 35.671 88.47 36.815 ;
     RECT  2.304 36.815 5.742 37.561 ;
     RECT  6.48 36.815 88.47 37.561 ;
     RECT  2.304 37.561 88.47 38.543 ;
     RECT  2.304 38.543 43.11 39.361 ;
     RECT  43.884 38.543 88.47 39.361 ;
     RECT  2.304 39.361 88.47 39.479 ;
     RECT  80.856 39.479 81.486 39.515 ;
     RECT  80.892 39.515 81.342 39.587 ;
     RECT  2.304 39.479 79.902 40.441 ;
     RECT  81.072 39.587 81.342 40.441 ;
     RECT  82.26 39.479 88.47 40.441 ;
     RECT  2.304 40.441 80.118 40.531 ;
     RECT  81.072 40.441 88.47 40.531 ;
     RECT  2.304 40.531 88.47 41.645 ;
     RECT  2.304 41.645 14.598 41.648 ;
     RECT  15.444 41.645 88.47 41.909 ;
     RECT  15.516 41.909 88.47 43.259 ;
     RECT  15.516 43.259 33.714 43.303 ;
     RECT  15.48 43.303 33.714 43.537 ;
     RECT  2.304 41.648 14.49 43.843 ;
     RECT  15.372 43.537 33.714 43.843 ;
     RECT  34.524 43.259 88.47 43.871 ;
     RECT  2.304 43.843 33.714 44.041 ;
     RECT  34.524 43.871 76.41 44.041 ;
     RECT  77.184 43.871 88.47 44.141 ;
     RECT  2.304 44.041 76.41 44.375 ;
     RECT  18.615 44.375 76.41 45.031 ;
     RECT  77.184 44.141 88.434 45.031 ;
     RECT  18.615 45.031 88.434 45.293 ;
     RECT  2.304 44.375 17.838 45.571 ;
     RECT  18.615 45.293 88.398 45.571 ;
     RECT  2.304 45.571 88.398 46.111 ;
     RECT  2.304 46.111 88.434 47.039 ;
     RECT  17.82 47.039 88.434 47.183 ;
     RECT  37.836 47.183 88.434 47.615 ;
     RECT  37.98 47.615 88.434 47.651 ;
     RECT  2.304 47.039 17.082 47.857 ;
     RECT  17.82 47.183 36.99 47.857 ;
     RECT  2.304 47.857 36.99 47.981 ;
     RECT  25.128 47.981 36.99 48.091 ;
     RECT  2.304 47.981 24.297 48.191 ;
     RECT  25.128 48.091 37.134 48.361 ;
     RECT  37.98 47.651 88.398 48.361 ;
     RECT  25.128 48.361 88.398 48.389 ;
     RECT  25.128 48.389 74.43 48.425 ;
     RECT  75.24 48.389 88.398 48.505 ;
     RECT  25.128 48.425 74.358 48.659 ;
     RECT  75.24 48.505 88.434 48.767 ;
     RECT  75.24 48.767 88.398 48.803 ;
     RECT  75.348 48.803 88.398 48.929 ;
     RECT  25.128 48.659 74.178 48.965 ;
     RECT  75.384 48.929 88.398 48.965 ;
     RECT  2.34 48.191 24.297 49.045 ;
     RECT  25.128 48.965 73.062 49.045 ;
     RECT  75.672 48.965 88.398 49.541 ;
     RECT  73.872 48.965 74.178 49.549 ;
     RECT  73.872 49.549 74.214 49.585 ;
     RECT  2.34 49.045 73.062 49.711 ;
     RECT  73.872 49.585 74.646 49.711 ;
     RECT  2.34 49.711 74.646 49.747 ;
     RECT  75.672 49.541 88.362 49.747 ;
     RECT  2.34 49.747 88.362 49.811 ;
     RECT  17.82 49.811 88.362 50.279 ;
     RECT  88.308 50.279 88.362 50.431 ;
     RECT  17.82 50.279 87.498 50.549 ;
     RECT  88.308 50.431 88.434 50.657 ;
     RECT  2.34 49.811 17.082 50.693 ;
     RECT  14.292 50.693 17.082 50.701 ;
     RECT  17.82 50.549 87.462 50.701 ;
     RECT  14.292 50.701 87.462 50.891 ;
     RECT  88.308 50.657 88.362 50.999 ;
     RECT  88.308 50.999 88.326 51.125 ;
     RECT  14.292 50.891 87.426 51.197 ;
     RECT  14.292 51.197 87.318 52.015 ;
     RECT  2.34 50.693 13.497 52.051 ;
     RECT  14.292 52.015 87.786 52.051 ;
     RECT  2.34 52.051 87.786 52.205 ;
     RECT  2.34 52.205 87.678 52.439 ;
     RECT  2.34 52.439 41.67 52.475 ;
     RECT  42.408 52.439 87.534 52.475 ;
     RECT  42.408 52.475 52.866 52.493 ;
     RECT  2.376 52.475 41.67 52.619 ;
     RECT  2.376 52.619 38.826 52.979 ;
     RECT  24.015 52.979 38.826 53.365 ;
     RECT  39.636 52.619 41.67 53.365 ;
     RECT  53.676 52.475 87.534 53.401 ;
     RECT  2.376 52.979 23.058 53.519 ;
     RECT  24.015 53.365 41.67 53.557 ;
     RECT  42.408 52.493 52.758 53.557 ;
     RECT  53.676 53.401 87.678 53.563 ;
     RECT  53.64 53.563 87.786 53.635 ;
     RECT  24.015 53.557 52.758 53.789 ;
     RECT  45.615 53.789 52.758 54.031 ;
     RECT  53.532 53.635 87.786 54.031 ;
     RECT  45.615 54.031 87.786 54.059 ;
     RECT  24.015 53.789 44.874 54.133 ;
     RECT  21.492 53.519 23.058 54.139 ;
     RECT  23.832 54.133 44.874 54.139 ;
     RECT  2.376 53.519 20.574 54.409 ;
     RECT  21.492 54.139 44.874 54.409 ;
     RECT  2.376 54.409 44.874 54.473 ;
     RECT  2.376 54.473 10.854 54.599 ;
     RECT  11.628 54.473 44.874 54.599 ;
     RECT  39.348 54.599 44.874 54.715 ;
     RECT  45.615 54.059 48.006 54.715 ;
     RECT  39.348 54.715 48.006 54.985 ;
     RECT  39.348 54.985 48.222 55.021 ;
     RECT  49.068 54.059 87.786 55.021 ;
     RECT  11.628 54.599 38.61 55.219 ;
     RECT  11.52 55.219 38.61 55.247 ;
     RECT  18.615 55.247 38.61 55.409 ;
     RECT  18.615 55.409 19.674 55.445 ;
     RECT  2.415 54.599 10.674 55.489 ;
     RECT  11.52 55.247 17.838 55.489 ;
     RECT  20.412 55.409 38.61 55.561 ;
     RECT  39.348 55.021 87.786 55.561 ;
     RECT  2.415 55.489 17.838 55.679 ;
     RECT  20.412 55.561 87.786 55.715 ;
     RECT  21.636 55.715 87.786 55.751 ;
     RECT  6.228 55.679 17.838 55.823 ;
     RECT  6.228 55.823 17.082 55.949 ;
     RECT  39.096 55.751 87.786 56.255 ;
     RECT  17.82 55.823 17.838 56.335 ;
     RECT  18.615 55.445 19.602 56.335 ;
     RECT  20.412 55.715 20.646 56.335 ;
     RECT  6.228 55.949 17.046 56.461 ;
     RECT  17.82 56.335 20.646 56.489 ;
     RECT  21.636 55.751 38.178 56.489 ;
     RECT  2.415 55.679 5.346 56.539 ;
     RECT  2.376 56.539 5.346 56.641 ;
     RECT  18.504 56.489 20.646 56.641 ;
     RECT  21.636 56.489 38.142 56.641 ;
     RECT  6.192 56.461 17.046 56.795 ;
     RECT  2.376 56.641 5.418 57.029 ;
     RECT  49.896 56.255 87.786 57.065 ;
     RECT  39.096 56.255 49.158 57.109 ;
     RECT  49.896 57.065 59.094 57.109 ;
     RECT  18.504 56.641 38.142 57.209 ;
     RECT  59.904 57.065 87.786 57.335 ;
     RECT  18.615 57.209 38.142 57.415 ;
     RECT  39.096 57.109 59.094 57.415 ;
     RECT  2.415 57.029 5.418 57.541 ;
     RECT  6.264 56.795 17.046 57.541 ;
     RECT  75.564 57.335 87.786 57.541 ;
     RECT  2.415 57.541 17.046 57.839 ;
     RECT  18.615 57.415 59.094 57.955 ;
     RECT  59.904 57.335 74.682 57.955 ;
     RECT  2.415 57.839 16.722 58.379 ;
     RECT  17.676 58.459 17.766 58.495 ;
     RECT  18.615 57.955 74.682 58.495 ;
     RECT  75.564 57.541 88.434 58.495 ;
     RECT  10.656 58.379 16.722 58.523 ;
     RECT  17.676 58.495 88.434 58.541 ;
     RECT  10.8 58.523 16.722 58.559 ;
     RECT  10.836 58.559 16.722 58.621 ;
     RECT  2.415 58.379 9.918 58.649 ;
     RECT  10.836 58.621 16.758 58.685 ;
     RECT  17.676 58.541 19.206 58.693 ;
     RECT  11.088 58.685 16.758 58.729 ;
     RECT  11.088 58.729 16.83 59.069 ;
     RECT  11.268 59.069 16.83 59.071 ;
     RECT  17.64 58.693 19.206 59.071 ;
     RECT  11.268 59.071 19.206 59.305 ;
     RECT  20.016 58.541 88.434 59.305 ;
     RECT  2.415 58.649 3.006 59.431 ;
     RECT  3.744 58.649 9.918 59.431 ;
     RECT  2.415 59.431 9.918 59.495 ;
     RECT  3.672 59.495 9.918 59.611 ;
     RECT  11.268 59.305 88.434 59.729 ;
     RECT  3.672 59.611 10.386 59.809 ;
     RECT  11.268 59.729 57.402 59.809 ;
     RECT  3.672 59.809 57.402 59.909 ;
     RECT  2.415 59.495 2.862 60.235 ;
     RECT  3.672 59.909 10.71 60.235 ;
     RECT  11.484 59.909 57.402 60.475 ;
     RECT  11.484 60.475 57.438 60.619 ;
     RECT  2.415 60.235 10.71 60.655 ;
     RECT  11.484 60.619 57.474 60.655 ;
     RECT  2.415 60.655 57.474 60.691 ;
     RECT  58.284 59.729 88.434 60.691 ;
     RECT  2.415 60.691 88.434 60.845 ;
     RECT  2.415 60.845 16.11 61.115 ;
     RECT  3.492 61.115 16.11 61.655 ;
     RECT  4.176 61.655 16.11 61.735 ;
     RECT  16.848 60.845 22.338 61.735 ;
     RECT  23.112 60.845 88.434 61.735 ;
     RECT  4.176 61.735 88.434 61.799 ;
     RECT  4.176 61.799 28.062 61.925 ;
     RECT  4.212 61.925 22.59 62.159 ;
     RECT  4.212 62.159 15.966 62.195 ;
     RECT  4.932 62.195 15.966 62.465 ;
     RECT  16.704 62.159 22.59 62.671 ;
     RECT  23.328 61.925 28.062 62.671 ;
     RECT  29.232 61.799 88.434 62.813 ;
     RECT  16.704 62.671 28.35 62.851 ;
     RECT  29.232 62.813 49.77 62.851 ;
     RECT  12.564 62.465 15.966 63.013 ;
     RECT  16.704 62.851 49.77 63.013 ;
     RECT  4.932 62.465 11.718 63.211 ;
     RECT  12.564 63.013 49.77 63.211 ;
     RECT  4.932 63.211 49.77 63.239 ;
     RECT  4.932 63.239 49.626 63.283 ;
     RECT  4.464 63.283 49.626 63.319 ;
     RECT  50.544 62.813 88.434 63.419 ;
     RECT  50.544 63.419 51.297 63.509 ;
     RECT  52.02 63.419 88.434 63.509 ;
     RECT  4.392 63.319 49.626 63.517 ;
     RECT  52.02 63.509 57.798 63.545 ;
     RECT  52.02 63.545 57.294 63.653 ;
     RECT  4.32 63.517 49.626 63.661 ;
     RECT  3.924 63.661 49.626 63.859 ;
     RECT  3.816 63.859 49.626 63.895 ;
     RECT  3.528 63.895 49.626 64.021 ;
     RECT  3.528 64.021 49.77 64.057 ;
     RECT  2.415 61.115 2.697 64.129 ;
     RECT  3.42 64.057 49.77 64.129 ;
     RECT  50.76 63.509 51.297 64.201 ;
     RECT  52.02 63.653 52.65 64.201 ;
     RECT  58.932 63.509 88.434 64.327 ;
     RECT  2.415 64.129 49.77 64.411 ;
     RECT  50.76 64.201 52.65 64.411 ;
     RECT  58.716 64.327 88.434 64.435 ;
     RECT  58.644 64.435 88.434 64.471 ;
     RECT  2.415 64.411 52.65 64.561 ;
     RECT  53.424 63.653 57.294 64.561 ;
     RECT  2.415 64.561 57.294 64.625 ;
     RECT  58.14 64.471 88.434 64.975 ;
     RECT  50.76 64.625 57.294 65.101 ;
     RECT  58.032 64.975 88.434 65.101 ;
     RECT  2.415 64.625 49.806 65.399 ;
     RECT  20.7 65.399 49.806 65.551 ;
     RECT  20.7 65.551 49.842 65.705 ;
     RECT  50.76 65.101 88.434 65.741 ;
     RECT  50.76 65.741 88.218 65.821 ;
     RECT  32.976 65.705 49.842 66.125 ;
     RECT  2.415 65.399 19.926 66.181 ;
     RECT  20.7 65.705 32.166 66.181 ;
     RECT  33.408 66.125 49.842 66.245 ;
     RECT  2.415 66.181 32.166 66.281 ;
     RECT  33.804 66.245 49.842 66.283 ;
     RECT  50.616 65.821 88.218 66.283 ;
     RECT  33.804 66.283 88.218 66.479 ;
     RECT  50.616 66.479 88.218 66.623 ;
     RECT  16.884 66.281 32.166 66.631 ;
     RECT  54.864 66.623 88.218 66.749 ;
     RECT  55.152 66.749 88.218 66.857 ;
     RECT  55.152 66.857 88.182 66.893 ;
     RECT  16.884 66.631 32.562 66.901 ;
     RECT  50.616 66.623 54.126 67.019 ;
     RECT  2.415 66.281 15.966 67.063 ;
     RECT  33.804 66.479 49.77 67.063 ;
     RECT  16.884 66.901 32.742 67.135 ;
     RECT  33.624 67.063 49.77 67.135 ;
     RECT  16.884 67.135 49.77 67.181 ;
     RECT  2.415 67.063 16.002 67.261 ;
     RECT  50.616 67.019 51.354 67.261 ;
     RECT  44.496 67.181 49.77 67.369 ;
     RECT  50.544 67.261 51.354 67.369 ;
     RECT  16.884 67.181 43.758 67.469 ;
     RECT  55.152 66.893 76.806 67.837 ;
     RECT  77.652 66.893 88.182 67.837 ;
     RECT  16.884 67.469 41.454 67.865 ;
     RECT  42.336 67.469 43.758 67.945 ;
     RECT  44.496 67.369 51.354 67.945 ;
     RECT  42.336 67.945 51.354 67.981 ;
     RECT  52.2 67.019 54.054 67.981 ;
     RECT  55.152 67.837 88.182 67.981 ;
     RECT  16.884 67.865 40.662 68.009 ;
     RECT  2.415 67.261 16.074 68.071 ;
     RECT  16.884 68.009 36.594 68.071 ;
     RECT  2.415 68.071 36.594 68.099 ;
     RECT  42.336 67.981 54.054 68.143 ;
     RECT  55.08 67.981 88.182 68.143 ;
     RECT  42.336 68.143 88.182 68.405 ;
     RECT  41.4 67.865 41.454 68.413 ;
     RECT  42.336 68.405 75.906 68.413 ;
     RECT  41.4 68.413 75.906 68.441 ;
     RECT  37.404 68.009 40.662 68.639 ;
     RECT  37.404 68.639 39.402 68.675 ;
     RECT  41.4 68.441 75.762 68.675 ;
     RECT  2.415 68.099 36.522 68.791 ;
     RECT  40.14 68.639 40.662 68.791 ;
     RECT  41.4 68.675 75.69 68.791 ;
     RECT  40.14 68.791 75.69 68.819 ;
     RECT  2.34 68.791 36.522 68.881 ;
     RECT  2.34 68.881 36.63 68.957 ;
     RECT  40.14 68.819 75.654 69.215 ;
     RECT  34.2 68.957 36.63 69.331 ;
     RECT  37.404 68.675 39.366 69.331 ;
     RECT  44.244 69.215 75.654 69.449 ;
     RECT  76.68 68.405 88.182 69.493 ;
     RECT  49.536 69.449 75.654 69.521 ;
     RECT  34.2 69.331 39.366 69.601 ;
     RECT  40.14 69.215 43.47 69.601 ;
     RECT  2.415 68.957 33.462 69.691 ;
     RECT  34.2 69.601 43.47 69.691 ;
     RECT  55.044 69.521 75.654 69.799 ;
     RECT  55.044 69.799 75.834 69.871 ;
     RECT  76.68 69.493 88.218 69.871 ;
     RECT  2.415 69.691 43.47 70.025 ;
     RECT  34.2 70.025 43.47 70.141 ;
     RECT  44.244 69.449 48.762 70.141 ;
     RECT  49.644 69.521 54.162 70.411 ;
     RECT  55.044 69.871 88.218 70.411 ;
     RECT  34.2 70.141 48.762 70.501 ;
     RECT  49.644 70.411 88.218 70.501 ;
     RECT  2.415 70.025 33.462 71.347 ;
     RECT  34.2 70.501 88.218 71.347 ;
     RECT  2.415 71.347 88.218 71.491 ;
     RECT  2.415 71.491 88.254 72.149 ;
     RECT  53.568 72.149 88.254 72.689 ;
     RECT  2.415 72.149 52.83 72.797 ;
     RECT  37.872 72.797 52.83 72.869 ;
     RECT  53.568 72.689 54.81 72.931 ;
     RECT  2.415 72.797 37.062 72.967 ;
     RECT  37.872 72.869 52.434 73.229 ;
     RECT  37.872 73.229 46.674 73.301 ;
     RECT  53.244 72.931 54.81 73.471 ;
     RECT  55.548 72.689 88.254 73.471 ;
     RECT  2.376 72.967 37.062 73.499 ;
     RECT  2.376 73.499 9.306 73.517 ;
     RECT  10.08 73.499 37.062 73.517 ;
     RECT  17.28 73.517 37.062 73.543 ;
     RECT  37.872 73.301 46.458 73.543 ;
     RECT  47.412 73.229 52.434 73.651 ;
     RECT  53.244 73.471 88.254 73.651 ;
     RECT  10.08 73.517 16.47 73.913 ;
     RECT  2.376 73.517 9.198 74.039 ;
     RECT  17.28 73.543 46.458 74.047 ;
     RECT  16.056 73.913 16.47 74.075 ;
     RECT  17.28 74.047 46.494 74.083 ;
     RECT  17.28 74.083 46.674 74.107 ;
     RECT  47.412 73.651 88.254 74.107 ;
     RECT  10.08 73.913 15.246 74.389 ;
     RECT  17.28 74.107 88.254 74.651 ;
     RECT  2.376 74.039 9.126 74.849 ;
     RECT  49.716 74.651 57.15 74.849 ;
     RECT  2.415 74.849 9.126 74.893 ;
     RECT  2.415 74.893 9.198 74.965 ;
     RECT  9.936 74.389 15.246 74.965 ;
     RECT  57.888 74.651 88.254 74.993 ;
     RECT  2.415 74.965 15.246 75.001 ;
     RECT  16.056 74.075 16.362 75.001 ;
     RECT  17.28 74.651 48.942 75.001 ;
     RECT  57.96 74.993 88.254 75.029 ;
     RECT  2.415 75.001 48.942 75.119 ;
     RECT  57.96 75.029 88.11 75.191 ;
     RECT  57.96 75.191 87.822 75.227 ;
     RECT  15.804 75.119 48.942 75.389 ;
     RECT  15.804 75.389 47.61 75.425 ;
     RECT  2.415 75.119 15.066 75.461 ;
     RECT  48.384 75.389 48.942 75.469 ;
     RECT  49.716 74.849 57.078 75.469 ;
     RECT  37.044 75.425 47.61 75.659 ;
     RECT  48.384 75.469 57.078 75.659 ;
     RECT  15.804 75.425 36.306 75.731 ;
     RECT  43.092 75.659 47.466 75.929 ;
     RECT  48.42 75.659 57.078 76.009 ;
     RECT  57.96 75.227 87.57 76.009 ;
     RECT  7.236 75.461 15.066 76.279 ;
     RECT  15.804 75.731 36.27 76.279 ;
     RECT  2.415 75.461 6.498 76.315 ;
     RECT  7.236 76.279 36.27 76.315 ;
     RECT  2.415 76.315 36.27 76.349 ;
     RECT  48.42 76.009 87.57 76.441 ;
     RECT  37.044 75.659 42.354 76.459 ;
     RECT  43.092 75.929 47.142 76.459 ;
     RECT  48.312 76.441 87.57 76.459 ;
     RECT  18.216 76.349 36.27 76.621 ;
     RECT  37.044 76.459 47.142 76.621 ;
     RECT  18.216 76.621 47.142 76.939 ;
     RECT  48.06 76.459 87.57 76.939 ;
     RECT  18.216 76.939 87.57 77.117 ;
     RECT  18.252 77.117 87.57 77.453 ;
     RECT  2.415 76.349 17.406 77.935 ;
     RECT  18.252 77.453 85.086 77.935 ;
     RECT  86.148 77.453 87.57 78.089 ;
     RECT  2.415 77.935 85.086 78.205 ;
     RECT  86.148 78.089 86.778 78.205 ;
     RECT  87.552 78.089 87.57 78.241 ;
     RECT  2.415 78.205 86.778 78.467 ;
     RECT  87.552 78.241 87.678 78.539 ;
     RECT  2.415 78.467 85.014 78.899 ;
     RECT  2.415 78.899 14.958 78.935 ;
     RECT  15.804 78.899 85.014 79.205 ;
     RECT  74.7 79.205 85.014 79.213 ;
     RECT  85.788 78.467 86.778 79.213 ;
     RECT  87.552 78.539 87.57 79.277 ;
     RECT  74.7 79.213 86.778 79.511 ;
     RECT  15.804 79.205 73.962 79.517 ;
     RECT  48.276 79.517 73.962 79.556 ;
     RECT  2.415 78.935 14.598 79.681 ;
     RECT  48.312 79.556 73.962 79.781 ;
     RECT  74.916 79.511 86.778 79.861 ;
     RECT  2.415 79.681 14.814 79.951 ;
     RECT  2.415 79.951 14.85 79.987 ;
     RECT  15.804 79.517 47.358 79.987 ;
     RECT  48.348 79.781 73.962 80.095 ;
     RECT  2.415 79.987 47.358 80.293 ;
     RECT  48.348 80.095 74.07 80.329 ;
     RECT  74.916 79.861 87.282 80.329 ;
     RECT  2.415 80.293 47.43 80.357 ;
     RECT  48.348 80.329 87.282 80.519 ;
     RECT  15.444 80.357 47.43 80.761 ;
     RECT  48.348 80.519 49.95 80.761 ;
     RECT  15.444 80.761 49.95 80.969 ;
     RECT  50.688 80.519 87.282 81.211 ;
     RECT  50.688 81.211 87.498 81.329 ;
     RECT  38.052 80.969 49.95 81.373 ;
     RECT  50.688 81.329 52.506 81.373 ;
     RECT  53.316 81.329 87.498 81.473 ;
     RECT  38.052 81.373 52.506 81.509 ;
     RECT  2.415 80.357 14.706 81.599 ;
     RECT  53.568 81.473 87.498 81.599 ;
     RECT  38.052 81.509 40.497 81.635 ;
     RECT  8.928 81.599 14.706 81.671 ;
     RECT  15.552 80.969 37.242 81.715 ;
     RECT  38.052 81.635 38.862 81.715 ;
     RECT  15.552 81.715 38.862 81.869 ;
     RECT  9.252 81.671 14.706 82.021 ;
     RECT  15.552 81.869 38.754 82.021 ;
     RECT  41.22 81.509 52.506 82.111 ;
     RECT  39.672 81.635 40.497 82.291 ;
     RECT  41.22 82.111 52.686 82.291 ;
     RECT  53.568 81.599 85.662 82.381 ;
     RECT  86.436 81.599 87.498 82.381 ;
     RECT  39.672 82.291 52.686 82.409 ;
     RECT  9.252 82.021 38.754 82.417 ;
     RECT  53.568 82.381 87.498 82.445 ;
     RECT  2.415 81.599 8.154 82.489 ;
     RECT  8.892 82.417 38.754 82.489 ;
     RECT  2.415 82.489 38.754 82.589 ;
     RECT  53.568 82.445 87.282 82.589 ;
     RECT  5.328 82.589 38.754 82.651 ;
     RECT  53.568 82.589 87.138 82.679 ;
     RECT  48.348 82.409 52.686 82.687 ;
     RECT  53.568 82.679 60.534 82.687 ;
     RECT  5.328 82.651 38.826 82.795 ;
     RECT  39.672 82.409 47.61 82.795 ;
     RECT  5.328 82.795 47.61 82.949 ;
     RECT  61.272 82.679 87.138 82.985 ;
     RECT  2.415 82.589 4.518 83.093 ;
     RECT  48.348 82.687 60.534 83.093 ;
     RECT  2.415 83.093 4.266 83.219 ;
     RECT  48.492 83.093 60.534 83.219 ;
     RECT  5.328 82.949 39.294 83.371 ;
     RECT  40.176 82.949 47.61 83.371 ;
     RECT  61.272 82.985 65.826 83.489 ;
     RECT  66.564 82.985 87.138 83.525 ;
     RECT  50.004 83.219 60.534 83.641 ;
     RECT  61.272 83.489 65.61 83.641 ;
     RECT  5.148 83.371 39.294 83.759 ;
     RECT  50.004 83.641 65.61 83.759 ;
     RECT  66.564 83.525 86.922 83.767 ;
     RECT  5.328 83.759 39.294 83.795 ;
     RECT  53.46 83.759 65.61 83.795 ;
     RECT  5.364 83.795 39.294 83.875 ;
     RECT  40.176 83.371 47.646 83.875 ;
     RECT  5.364 83.875 47.646 83.911 ;
     RECT  48.492 83.219 49.086 83.911 ;
     RECT  3.996 83.219 4.266 84.001 ;
     RECT  3.996 84.001 4.518 84.029 ;
     RECT  5.364 83.911 49.086 84.029 ;
     RECT  66.384 83.767 86.922 84.029 ;
     RECT  45.036 84.029 49.086 84.109 ;
     RECT  50.004 83.759 52.722 84.109 ;
     RECT  61.164 83.795 65.61 84.283 ;
     RECT  66.384 84.029 78.678 84.283 ;
     RECT  4.14 84.029 4.518 84.299 ;
     RECT  45.036 84.109 52.722 84.299 ;
     RECT  79.416 84.029 86.922 84.335 ;
     RECT  5.364 84.029 44.298 84.407 ;
     RECT  45.108 84.299 52.722 84.541 ;
     RECT  53.46 83.795 60.426 84.541 ;
     RECT  45.108 84.541 60.426 84.571 ;
     RECT  61.164 84.283 78.678 84.571 ;
     RECT  79.416 84.335 86.814 84.641 ;
     RECT  45.108 84.571 78.678 84.713 ;
     RECT  5.364 84.407 43.938 84.721 ;
     RECT  45.108 84.713 70.722 84.893 ;
     RECT  61.344 84.893 70.722 84.947 ;
     RECT  71.532 84.713 78.678 84.991 ;
     RECT  79.416 84.641 86.778 84.991 ;
     RECT  4.14 84.299 4.194 85.051 ;
     RECT  3.672 85.051 4.194 85.109 ;
     RECT  45.108 84.893 60.426 85.109 ;
     RECT  71.532 84.991 86.778 85.109 ;
     RECT  3.924 85.109 4.194 85.117 ;
     RECT  5.148 84.721 43.938 85.117 ;
     RECT  86.328 85.109 86.778 85.145 ;
     RECT  45.108 85.109 46.17 85.189 ;
     RECT  71.532 85.109 85.41 85.217 ;
     RECT  86.4 85.145 86.742 85.217 ;
     RECT  86.544 85.217 86.634 85.253 ;
     RECT  61.344 84.947 70.65 85.415 ;
     RECT  71.532 85.217 85.194 85.415 ;
     RECT  61.344 85.415 70.578 85.421 ;
     RECT  3.924 85.117 43.938 85.459 ;
     RECT  44.892 85.189 46.17 85.459 ;
     RECT  61.344 85.421 70.29 85.487 ;
     RECT  72 85.415 85.194 85.487 ;
     RECT  72 85.487 84.906 85.685 ;
     RECT  72 85.685 84.798 85.721 ;
     RECT  72.18 85.721 84.726 85.757 ;
     RECT  47.016 85.109 60.426 85.801 ;
     RECT  72.18 85.757 84.654 85.829 ;
     RECT  47.016 85.801 60.498 85.891 ;
     RECT  61.344 85.487 63.954 85.891 ;
     RECT  72.18 85.829 84.618 85.919 ;
     RECT  72.18 85.919 84.402 85.955 ;
     RECT  47.016 85.891 63.954 85.963 ;
     RECT  72.18 85.955 84.33 86.027 ;
     RECT  46.98 85.963 63.954 86.071 ;
     RECT  64.8 85.487 70.29 86.152 ;
     RECT  3.924 85.459 46.17 86.155 ;
     RECT  46.944 86.071 63.954 86.155 ;
     RECT  64.8 86.152 70.794 86.189 ;
     RECT  3.924 86.155 63.954 86.233 ;
     RECT  72.18 86.027 83.697 86.261 ;
     RECT  72.216 86.261 83.697 86.333 ;
     RECT  3.816 86.233 63.954 86.341 ;
     RECT  2.415 83.219 2.697 86.539 ;
     RECT  3.636 86.341 63.99 86.539 ;
     RECT  76.104 86.333 83.697 86.567 ;
     RECT  2.415 86.539 63.99 86.611 ;
     RECT  64.8 86.189 70.29 86.611 ;
     RECT  76.176 86.567 83.697 86.639 ;
     RECT  76.176 86.639 82.674 86.729 ;
     RECT  76.644 86.729 82.674 86.801 ;
     RECT  2.415 86.611 70.29 86.837 ;
     RECT  76.644 86.801 82.494 86.837 ;
     RECT  2.415 86.837 70.182 86.861 ;
     RECT  72.216 86.333 75.222 86.999 ;
     RECT  76.644 86.837 82.206 86.999 ;
     RECT  2.415 86.861 53.514 87.035 ;
     RECT  76.644 86.999 76.77 87.035 ;
     RECT  74.664 86.999 75.222 87.071 ;
     RECT  76.752 87.035 76.77 87.071 ;
     RECT  14.472 87.035 53.514 87.101 ;
     RECT  74.736 87.071 75.222 87.107 ;
     RECT  72.396 86.999 73.89 87.143 ;
     RECT  75.096 87.107 75.222 87.143 ;
     RECT  77.544 86.999 82.206 87.143 ;
     RECT  2.415 87.035 13.734 87.179 ;
     RECT  14.472 87.101 53.442 87.179 ;
     RECT  72.396 87.143 72.897 87.179 ;
     RECT  73.872 87.143 73.89 87.179 ;
     RECT  17.172 87.179 53.442 87.269 ;
     RECT  54.324 86.861 70.182 87.305 ;
     RECT  77.544 87.143 81.99 87.341 ;
     RECT  17.172 87.269 53.334 87.377 ;
     RECT  54.324 87.305 66.042 87.377 ;
     RECT  17.172 87.377 52.938 87.449 ;
     RECT  54.324 87.377 63.594 87.449 ;
     RECT  2.415 87.179 13.626 87.539 ;
     RECT  66.816 87.305 70.182 87.539 ;
     RECT  77.544 87.341 80.478 87.539 ;
     RECT  81.468 87.341 81.99 87.539 ;
     RECT  13.215 87.539 13.626 87.611 ;
     RECT  17.172 87.449 40.698 87.611 ;
     RECT  79.884 87.539 80.478 87.611 ;
     RECT  81.504 87.539 81.738 87.611 ;
     RECT  14.472 87.179 16.434 87.647 ;
     RECT  79.884 87.611 79.902 87.647 ;
     RECT  77.616 87.539 79.146 87.683 ;
     RECT  3.636 87.539 12.186 87.719 ;
     RECT  66.816 87.539 69.642 87.809 ;
     RECT  14.472 87.647 14.742 87.821 ;
     RECT  15.48 87.647 16.434 87.845 ;
     RECT  54.324 87.449 62.097 87.845 ;
     RECT  66.816 87.809 69.57 87.845 ;
     RECT  59.94 87.845 62.097 87.917 ;
     RECT  66.816 87.845 68.994 87.917 ;
     RECT  17.172 87.611 39.258 87.953 ;
     RECT  60.264 87.917 60.282 87.953 ;
     RECT  15.984 87.845 16.434 87.961 ;
     RECT  3.78 87.719 12.186 87.989 ;
     RECT  15.984 87.961 16.758 87.989 ;
     RECT  41.724 87.449 52.938 87.989 ;
     RECT  64.404 87.377 66.042 87.989 ;
     RECT  54.324 87.845 59.202 88.051 ;
     RECT  66.816 87.917 68.958 88.051 ;
     RECT  3.78 87.989 11.538 88.079 ;
     RECT  17.82 87.953 39.258 88.079 ;
     RECT  46.908 87.989 52.938 88.079 ;
     RECT  66.528 88.051 68.958 88.079 ;
     RECT  17.964 88.079 39.258 88.109 ;
     RECT  16.056 87.989 16.758 88.115 ;
     RECT  17.964 88.109 37.89 88.115 ;
     RECT  38.628 88.109 39.258 88.115 ;
     RECT  40.032 87.611 40.698 88.115 ;
     RECT  41.724 87.989 45.897 88.115 ;
     RECT  50.508 88.079 52.938 88.115 ;
     RECT  66.528 88.079 68.094 88.115 ;
     RECT  50.904 88.115 52.938 88.123 ;
     RECT  53.676 88.051 59.202 88.123 ;
     RECT  14.472 87.821 14.49 88.151 ;
     RECT  22.536 88.115 32.634 88.151 ;
     RECT  40.068 88.115 40.626 88.151 ;
     RECT  50.904 88.123 59.202 88.151 ;
     RECT  61.092 87.917 62.097 88.157 ;
     RECT  62.82 87.449 63.594 88.157 ;
     RECT  38.772 88.115 39.258 88.187 ;
     RECT  40.068 88.151 40.59 88.187 ;
     RECT  43.704 88.115 45.897 88.187 ;
     RECT  46.908 88.079 49.698 88.187 ;
     RECT  53.316 88.151 57.942 88.187 ;
     RECT  61.272 88.157 62.097 88.195 ;
     RECT  62.82 88.157 63.234 88.195 ;
     RECT  16.74 88.115 16.758 88.223 ;
     RECT  47.628 88.187 49.698 88.223 ;
     RECT  53.316 88.187 57.186 88.223 ;
     RECT  57.924 88.187 57.942 88.223 ;
     RECT  59.184 88.151 59.202 88.223 ;
     RECT  41.724 88.115 42.75 88.231 ;
     RECT  4.032 88.079 11.538 88.259 ;
     RECT  22.824 88.151 32.634 88.259 ;
     RECT  33.912 88.115 37.674 88.259 ;
     RECT  40.14 88.187 40.59 88.259 ;
     RECT  41.616 88.231 42.75 88.259 ;
     RECT  44.352 88.187 45.897 88.259 ;
     RECT  47.628 88.223 49.554 88.259 ;
     RECT  2.415 87.539 2.697 88.307 ;
     RECT  13.215 87.611 13.497 88.307 ;
     RECT  22.824 88.259 24.966 88.307 ;
     RECT  40.215 88.259 40.497 88.307 ;
     RECT  45.615 88.259 45.897 88.307 ;
     RECT  50.904 88.151 52.434 88.307 ;
     RECT  53.316 88.223 56.697 88.307 ;
     RECT  61.272 88.195 63.234 88.307 ;
     RECT  72.615 87.179 72.897 88.307 ;
     RECT  78.015 87.683 78.297 88.307 ;
     RECT  83.415 86.639 83.697 88.307 ;
     RECT  64.404 87.989 65.61 88.321 ;
     RECT  4.14 88.259 10.998 88.349 ;
     RECT  17.964 88.115 21.438 88.349 ;
     RECT  22.824 88.307 24.105 88.349 ;
     RECT  24.948 88.307 24.966 88.349 ;
     RECT  25.704 88.259 30.078 88.349 ;
     RECT  30.996 88.259 32.634 88.349 ;
     RECT  33.912 88.259 36.342 88.349 ;
     RECT  41.616 88.259 42.03 88.349 ;
     RECT  47.7 88.259 48.33 88.349 ;
     RECT  50.904 88.307 51.105 88.349 ;
     RECT  51.876 88.307 52.434 88.349 ;
     RECT  53.316 88.307 56.574 88.349 ;
     RECT  61.272 88.307 61.905 88.349 ;
     RECT  62.712 88.307 63.234 88.349 ;
     RECT  66.528 88.115 67.806 88.349 ;
     RECT  25.704 88.349 25.722 88.355 ;
     RECT  49.32 88.259 49.554 88.355 ;
     RECT  18.18 88.349 19.062 88.385 ;
     RECT  19.872 88.349 20.934 88.385 ;
     RECT  27.432 88.349 27.522 88.385 ;
     RECT  33.912 88.349 34.905 88.385 ;
     RECT  37.116 88.259 37.674 88.385 ;
     RECT  41.616 88.349 41.742 88.385 ;
     RECT  47.988 88.349 48.114 88.385 ;
     RECT  49.32 88.355 49.338 88.385 ;
     RECT  53.316 88.349 53.694 88.385 ;
     RECT  54.972 88.349 56.574 88.385 ;
     RECT  64.044 88.321 65.61 88.397 ;
     RECT  4.14 88.349 10.854 88.421 ;
     RECT  18.18 88.385 18.705 88.421 ;
     RECT  19.872 88.385 19.962 88.421 ;
     RECT  28.332 88.349 30.078 88.421 ;
     RECT  38.772 88.187 38.79 88.421 ;
     RECT  55.116 88.385 56.505 88.421 ;
     RECT  62.712 88.349 62.73 88.421 ;
     RECT  65.592 88.397 65.61 88.421 ;
     RECT  68.94 88.079 68.958 88.421 ;
     RECT  31.86 88.349 32.634 88.457 ;
     RECT  18.288 88.421 18.705 88.493 ;
     RECT  27.432 88.385 27.45 88.493 ;
     RECT  28.728 88.421 30.078 88.493 ;
     RECT  31.86 88.457 31.878 88.493 ;
     RECT  32.616 88.457 32.634 88.493 ;
     RECT  33.912 88.385 33.93 88.493 ;
     RECT  35.928 88.349 35.946 88.493 ;
     RECT  48.096 88.385 48.114 88.493 ;
     RECT  52.416 88.349 52.434 88.493 ;
     RECT  55.116 88.421 55.134 88.493 ;
     RECT  64.044 88.397 64.494 88.493 ;
     RECT  66.708 88.349 67.305 88.493 ;
     RECT  20.772 88.385 20.79 88.529 ;
     RECT  37.188 88.385 37.674 88.529 ;
     RECT  41.724 88.385 41.742 88.529 ;
     RECT  2.415 88.307 2.505 88.577 ;
     RECT  13.215 88.307 13.305 88.577 ;
     RECT  18.615 88.493 18.705 88.577 ;
     RECT  24.015 88.349 24.105 88.577 ;
     RECT  29.415 88.493 29.505 88.577 ;
     RECT  34.776 88.385 34.905 88.577 ;
     RECT  40.215 88.307 40.305 88.577 ;
     RECT  45.615 88.307 45.705 88.577 ;
     RECT  51.015 88.349 51.105 88.577 ;
     RECT  56.415 88.421 56.505 88.577 ;
     RECT  61.815 88.349 61.905 88.577 ;
     RECT  67.215 88.493 67.305 88.577 ;
     RECT  72.615 88.307 72.705 88.577 ;
     RECT  78.015 88.307 78.105 88.577 ;
     RECT  83.415 88.307 83.505 88.577 ;
     RECT  34.776 88.577 34.794 88.619 ;
     RECT  37.656 88.529 37.674 88.619 ;
     RECT  9.648 88.421 10.854 88.925 ;
     RECT  4.356 88.421 8.874 89.501 ;
     RECT  4.86 89.501 8.874 89.549 ;
     RECT  5.148 89.549 8.874 90.029 ;
     RECT  5.58 90.029 8.874 90.077 ;
     RECT  7.452 90.077 8.874 90.365 ;
     RECT  10.368 88.925 10.854 90.413 ;
     RECT  10.368 90.413 10.386 90.461 ;
     RECT  7.452 90.365 7.794 90.509 ;
     RECT  8.532 90.365 8.874 90.509 ;
     RECT  5.868 90.077 5.886 90.605 ;
     RECT  7.452 90.509 7.47 90.605 ;
     RECT  8.532 90.509 8.55 90.605 ;
    LAYER M4 ;
     RECT  0.06 4.032 0.133 5.016 ;
     RECT  0.133 4.032 0.179 5.736 ;
     RECT  0.179 5.712 0.181 5.736 ;
     RECT  0.179 4.032 0.323 4.056 ;
     RECT  0.181 5.712 0.323 5.832 ;
     RECT  0.323 5.712 2.408 5.736 ;
     RECT  2.293 33.024 2.408 33.048 ;
     RECT  2.285 34.224 2.408 34.248 ;
     RECT  0.181 44.112 2.408 44.136 ;
     RECT  2.365 47.952 2.408 47.976 ;
     RECT  2.365 54.432 2.408 54.456 ;
     RECT  2.365 56.544 2.408 56.568 ;
     RECT  2.293 68.928 2.408 69.576 ;
     RECT  2.365 74.688 2.408 74.712 ;
     RECT  2.408 2.148 2.512 88.572 ;
     RECT  2.512 2.418 2.704 88.302 ;
     RECT  2.704 68.64 2.765 69.576 ;
     RECT  2.704 66.288 2.837 66.792 ;
     RECT  2.704 23.904 2.909 23.928 ;
     RECT  2.704 42.096 2.909 44.136 ;
     RECT  2.704 54.432 2.963 55.368 ;
     RECT  2.963 54.432 3.017 54.696 ;
     RECT  2.704 28.464 3.053 28.776 ;
     RECT  2.704 30.288 3.053 31.08 ;
     RECT  2.909 42.096 3.059 44.04 ;
     RECT  3.053 30.72 3.089 31.08 ;
     RECT  3.089 31.056 3.125 31.08 ;
     RECT  2.704 47.952 3.155 47.976 ;
     RECT  2.704 74.544 3.161 74.712 ;
     RECT  2.704 76.848 3.269 76.872 ;
     RECT  2.704 27.072 3.299 27.096 ;
     RECT  2.704 34.752 3.299 35.352 ;
     RECT  2.704 51.072 3.305 51.912 ;
     RECT  2.704 60.24 3.377 60.552 ;
     RECT  3.305 51.072 3.413 51.096 ;
     RECT  2.704 32.592 3.449 33.048 ;
     RECT  3.299 34.8 3.449 35.352 ;
     RECT  2.704 56.496 3.449 56.568 ;
     RECT  2.704 77.856 3.521 77.88 ;
     RECT  3.161 74.544 3.557 74.664 ;
     RECT  2.704 22.464 3.665 22.488 ;
     RECT  2.704 79.152 3.701 79.176 ;
     RECT  3.557 74.544 3.737 74.568 ;
     RECT  3.449 34.8 3.773 34.824 ;
     RECT  2.704 39.744 3.773 39.768 ;
     RECT  3.697 38.736 3.809 38.76 ;
     RECT  2.704 19.392 3.829 19.848 ;
     RECT  2.704 21.12 3.829 21.144 ;
     RECT  3.841 36.528 3.949 37.032 ;
     RECT  2.704 87.168 3.949 87.192 ;
     RECT  2.704 85.056 3.973 85.08 ;
     RECT  2.704 14.88 3.985 15 ;
     RECT  2.704 16.848 3.985 17.64 ;
     RECT  2.704 6.24 4.019 11.256 ;
     RECT  3.932 39.696 4.019 39.72 ;
     RECT  3.973 84.336 4.019 85.08 ;
     RECT  3.949 23.376 4.021 23.928 ;
     RECT  3.053 28.704 4.021 28.776 ;
     RECT  3.949 48.432 4.021 48.456 ;
     RECT  2.704 58.368 4.025 59.208 ;
     RECT  2.704 5.136 4.057 5.16 ;
     RECT  4.019 6.24 4.057 10.968 ;
     RECT  3.949 36.528 4.061 38.712 ;
     RECT  3.059 42.768 4.061 44.04 ;
     RECT  2.765 68.64 4.061 68.664 ;
     RECT  3.949 86.544 4.061 87.192 ;
     RECT  4.021 0.576 4.105 0.6 ;
     RECT  3.829 19.392 4.129 21.144 ;
     RECT  4.061 36.528 4.133 38.232 ;
     RECT  2.704 3.168 4.165 3.192 ;
     RECT  2.704 83.184 4.169 83.208 ;
     RECT  4.021 28.224 4.201 28.776 ;
     RECT  4.021 23.376 4.211 24.504 ;
     RECT  4.165 2.88 4.273 3.192 ;
     RECT  3.017 54.432 4.273 54.504 ;
     RECT  4.025 59.184 4.277 59.208 ;
     RECT  4.201 28.176 4.345 28.776 ;
     RECT  4.237 49.776 4.345 49.8 ;
     RECT  4.133 37.872 4.355 38.232 ;
     RECT  3.769 74.064 4.417 74.088 ;
     RECT  2.704 13.008 4.453 13.032 ;
     RECT  4.345 27.936 4.453 28.776 ;
     RECT  4.061 86.544 4.453 86.568 ;
     RECT  4.211 23.904 4.457 24.504 ;
     RECT  4.273 2.88 4.481 3.576 ;
     RECT  4.057 5.136 4.481 10.968 ;
     RECT  4.381 70.32 4.489 70.344 ;
     RECT  3.805 71.664 4.489 71.688 ;
     RECT  4.481 2.88 4.493 10.968 ;
     RECT  3.985 15.984 4.493 17.64 ;
     RECT  4.457 24.48 4.499 24.504 ;
     RECT  4.021 48.432 4.529 48.504 ;
     RECT  4.453 27.936 4.537 29.688 ;
     RECT  3.985 14.784 4.561 15 ;
     RECT  4.493 15.984 4.561 17.16 ;
     RECT  4.489 70.32 4.561 71.688 ;
     RECT  4.493 2.88 4.565 10.872 ;
     RECT  4.345 49.776 4.601 50.088 ;
     RECT  4.129 26.736 4.637 26.76 ;
     RECT  4.537 27.936 4.637 28.968 ;
     RECT  4.529 48.48 4.637 48.504 ;
     RECT  3.449 32.592 4.669 32.616 ;
     RECT  4.561 70.32 4.669 72.312 ;
     RECT  4.417 73.728 4.669 74.088 ;
     RECT  4.669 70.32 4.745 74.088 ;
     RECT  4.129 19.392 4.789 22.008 ;
     RECT  3.449 56.496 4.817 56.52 ;
     RECT  4.745 72.96 4.849 74.088 ;
     RECT  4.021 89.472 4.849 89.496 ;
     RECT  4.813 76.272 4.877 76.296 ;
     RECT  4.273 53.568 4.889 54.504 ;
     RECT  4.849 72.96 4.933 74.616 ;
     RECT  4.877 76.272 4.961 76.968 ;
     RECT  4.789 18.48 4.979 22.008 ;
     RECT  4.892 59.232 4.979 59.256 ;
     RECT  4.885 34.896 4.993 34.92 ;
     RECT  4.453 85.92 4.993 86.568 ;
     RECT  4.961 76.272 5.033 76.296 ;
     RECT  4.813 52.32 5.065 52.344 ;
     RECT  4.993 85.68 5.065 86.568 ;
     RECT  4.979 18.624 5.069 22.008 ;
     RECT  3.377 60.24 5.077 60.264 ;
     RECT  4.745 70.32 5.077 71.688 ;
     RECT  4.561 1.728 5.101 1.752 ;
     RECT  4.061 43.296 5.101 44.04 ;
     RECT  5.077 59.76 5.101 60.264 ;
     RECT  5.101 43.296 5.105 44.424 ;
     RECT  5.069 18.768 5.113 22.008 ;
     RECT  5.101 59.76 5.123 61.032 ;
     RECT  4.669 0.096 5.137 0.12 ;
     RECT  5.101 1.2 5.137 1.752 ;
     RECT  5.113 19.392 5.137 22.008 ;
     RECT  4.849 89.472 5.137 89.544 ;
     RECT  4.933 57.216 5.141 57.24 ;
     RECT  5.123 59.76 5.164 59.784 ;
     RECT  5.077 69.984 5.164 71.688 ;
     RECT  4.237 11.952 5.173 11.976 ;
     RECT  4.453 13.008 5.173 13.128 ;
     RECT  4.019 84.336 5.173 84.36 ;
     RECT  5.065 85.392 5.173 86.568 ;
     RECT  4.565 2.88 5.177 3.576 ;
     RECT  4.601 49.776 5.213 49.848 ;
     RECT  4.705 78.624 5.249 78.648 ;
     RECT  4.777 80.256 5.249 80.28 ;
     RECT  4.921 48.768 5.285 48.792 ;
     RECT  4.201 68.352 5.285 68.376 ;
     RECT  4.933 72.96 5.321 74.328 ;
     RECT  5.213 49.776 5.357 49.8 ;
     RECT  5.173 84.336 5.357 86.568 ;
     RECT  5.173 88.32 5.365 88.344 ;
     RECT  4.345 82.56 5.389 82.584 ;
     RECT  5.065 51.648 5.393 52.344 ;
     RECT  5.357 84.336 5.393 86.232 ;
     RECT  5.137 0.096 5.42 1.752 ;
     RECT  5.177 2.88 5.42 2.952 ;
     RECT  5.393 51.744 5.425 52.344 ;
     RECT  5.137 89.472 5.461 90.024 ;
     RECT  4.669 32.592 5.465 33.048 ;
     RECT  4.561 14.784 5.497 17.16 ;
     RECT  5.164 70.752 5.501 71.688 ;
     RECT  5.321 73.2 5.501 74.328 ;
     RECT  5.365 87.792 5.537 88.344 ;
     RECT  4.565 4.848 5.569 10.872 ;
     RECT  5.569 4.848 5.605 10.968 ;
     RECT  5.605 3.984 5.641 10.968 ;
     RECT  5.173 11.952 5.641 13.128 ;
     RECT  5.389 82.56 5.641 83.208 ;
     RECT  5.393 84.336 5.641 85.848 ;
     RECT  4.993 34.368 5.645 34.92 ;
     RECT  5.497 14.784 5.677 17.208 ;
     RECT  5.42 0.096 5.699 2.952 ;
     RECT  5.245 58.128 5.713 58.152 ;
     RECT  5.461 89.472 5.749 90.072 ;
     RECT  5.713 58.128 5.753 58.68 ;
     RECT  4.637 28.08 5.789 28.968 ;
     RECT  5.105 44.016 5.825 44.424 ;
     RECT  5.789 28.704 5.893 28.968 ;
     RECT  5.857 30.096 5.893 30.12 ;
     RECT  5.749 89.472 5.897 90.6 ;
     RECT  2.704 46.272 6.001 46.296 ;
     RECT  5.137 19.392 6.005 22.632 ;
     RECT  5.641 3.984 6.041 13.128 ;
     RECT  5.641 82.56 6.041 85.848 ;
     RECT  5.893 28.704 6.077 30.12 ;
     RECT  5.645 34.896 6.077 34.92 ;
     RECT  5.677 14.784 6.085 17.4 ;
     RECT  5.501 73.248 6.109 74.328 ;
     RECT  5.897 89.472 6.112 90.072 ;
     RECT  5.497 47.328 6.149 47.352 ;
     RECT  5.317 77.904 6.149 77.928 ;
     RECT  4.133 36.528 6.181 36.552 ;
     RECT  6.112 89.424 6.221 90.072 ;
     RECT  6.253 63.744 6.289 63.768 ;
     RECT  5.18 69.696 6.289 69.72 ;
     RECT  2.837 66.288 6.325 66.312 ;
     RECT  6.085 14.208 6.329 17.4 ;
     RECT  6.289 69.696 6.329 70.104 ;
     RECT  6.041 82.56 6.329 85.8 ;
     RECT  5.425 51.744 6.361 52.488 ;
     RECT  6.181 36.048 6.365 36.552 ;
     RECT  5.123 61.008 6.373 61.032 ;
     RECT  4.933 62.544 6.373 62.568 ;
     RECT  6.289 63.744 6.397 64.92 ;
     RECT  6.109 73.248 6.401 74.76 ;
     RECT  6.373 61.008 6.419 62.568 ;
     RECT  5.699 0.096 6.467 2.904 ;
     RECT  6.361 51.6 6.469 52.488 ;
     RECT  4.889 53.808 6.469 54.072 ;
     RECT  6.467 0.096 6.509 0.6 ;
     RECT  5.605 88.368 6.517 88.392 ;
     RECT  6.509 0.576 6.563 0.6 ;
     RECT  6.433 50.304 6.577 50.616 ;
     RECT  6.469 51.6 6.577 52.728 ;
     RECT  6.041 5.088 6.613 13.128 ;
     RECT  6.329 14.208 6.613 17.16 ;
     RECT  5.825 44.016 6.613 44.04 ;
     RECT  6.005 19.392 6.649 22.008 ;
     RECT  6.325 66.288 6.653 67.08 ;
     RECT  6.613 23.04 6.685 23.064 ;
     RECT  6.577 50.304 6.685 52.728 ;
     RECT  6.467 1.728 6.689 2.904 ;
     RECT  6.433 33.84 6.721 33.864 ;
     RECT  6.689 2.16 6.757 2.904 ;
     RECT  6.041 3.984 6.757 4.056 ;
     RECT  5.465 32.592 6.757 32.616 ;
     RECT  5.852 25.008 6.793 25.032 ;
     RECT  6.001 45.312 6.797 46.296 ;
     RECT  6.397 63.744 6.797 64.968 ;
     RECT  6.401 74.304 6.797 74.76 ;
     RECT  6.757 32.544 6.805 32.616 ;
     RECT  6.577 34.944 6.829 34.968 ;
     RECT  6.419 61.584 6.829 62.568 ;
     RECT  6.797 63.744 6.829 63.768 ;
     RECT  6.685 50.208 6.833 52.728 ;
     RECT  6.613 43.392 6.865 44.04 ;
     RECT  6.577 80.256 6.865 80.28 ;
     RECT  6.793 24.192 6.901 25.032 ;
     RECT  6.865 26.016 6.901 26.04 ;
     RECT  6.865 43.392 6.973 44.184 ;
     RECT  5.501 71.232 7.009 71.688 ;
     RECT  6.757 2.16 7.045 4.056 ;
     RECT  6.901 24.192 7.045 26.04 ;
     RECT  6.613 27.456 7.081 27.48 ;
     RECT  6.077 28.704 7.081 28.776 ;
     RECT  6.685 23.04 7.117 23.112 ;
     RECT  7.045 24.192 7.117 26.328 ;
     RECT  5.753 58.656 7.117 58.68 ;
     RECT  6.649 18.864 7.148 22.008 ;
     RECT  7.045 2.16 7.189 4.104 ;
     RECT  6.613 5.088 7.189 17.16 ;
     RECT  6.221 90.048 7.189 90.072 ;
     RECT  6.865 80.112 7.261 80.28 ;
     RECT  7.153 30.816 7.333 30.84 ;
     RECT  6.805 32.448 7.333 32.616 ;
     RECT  7.117 58.512 7.333 58.68 ;
     RECT  7.148 18.72 7.388 22.008 ;
     RECT  7.117 23.04 7.388 26.328 ;
     RECT  6.653 66.288 7.405 66.696 ;
     RECT  6.517 88.368 7.409 88.92 ;
     RECT  7.189 90.048 7.441 90.504 ;
     RECT  6.829 61.584 7.573 63.768 ;
     RECT  7.261 48.336 7.621 48.36 ;
     RECT  6.329 70.08 7.621 70.104 ;
     RECT  7.009 71.088 7.621 71.688 ;
     RECT  6.721 33.792 7.657 33.864 ;
     RECT  7.388 18.72 7.669 26.328 ;
     RECT  7.081 27.456 7.669 28.776 ;
     RECT  7.333 58.512 7.729 58.728 ;
     RECT  7.621 0.144 7.765 0.168 ;
     RECT  7.189 2.16 7.808 17.16 ;
     RECT  7.669 18.72 7.808 28.776 ;
     RECT  6.077 29.808 7.808 29.832 ;
     RECT  7.333 30.816 7.808 32.616 ;
     RECT  7.657 33.792 7.808 33.96 ;
     RECT  6.829 34.944 7.808 35.352 ;
     RECT  6.365 36.432 7.808 36.552 ;
     RECT  4.355 37.872 7.808 37.896 ;
     RECT  7.621 42.288 7.808 42.312 ;
     RECT  6.973 43.392 7.808 44.28 ;
     RECT  6.797 46.272 7.808 46.296 ;
     RECT  7.621 48.336 7.808 49.224 ;
     RECT  6.833 50.352 7.808 52.728 ;
     RECT  6.469 53.808 7.808 54.648 ;
     RECT  7.693 57.072 7.808 57.096 ;
     RECT  7.729 58.464 7.808 58.728 ;
     RECT  6.829 59.808 7.808 59.832 ;
     RECT  7.573 60.816 7.808 63.768 ;
     RECT  6.797 64.896 7.808 64.968 ;
     RECT  7.405 66.24 7.808 66.696 ;
     RECT  7.621 68.4 7.808 68.424 ;
     RECT  7.621 70.08 7.808 71.688 ;
     RECT  6.401 73.248 7.808 73.272 ;
     RECT  6.797 74.304 7.808 74.328 ;
     RECT  6.937 78.768 7.808 78.792 ;
     RECT  7.261 80.112 7.808 80.328 ;
     RECT  6.329 82.56 7.808 85.704 ;
     RECT  7.409 88.368 7.808 88.572 ;
     RECT  7.808 2.148 7.912 88.572 ;
     RECT  7.765 0.096 7.957 0.168 ;
     RECT  7.441 90.048 7.985 90.6 ;
     RECT  7.957 0.096 8.053 0.408 ;
     RECT  7.912 2.148 8.104 88.488 ;
     RECT  8.053 0.096 8.149 0.504 ;
     RECT  7.985 90.336 8.165 90.6 ;
     RECT  8.104 49.872 8.201 50.376 ;
     RECT  8.104 52.512 8.201 54.12 ;
     RECT  8.104 78.384 8.237 80.376 ;
     RECT  8.104 36.528 8.273 36.552 ;
     RECT  8.104 47.424 8.273 47.448 ;
     RECT  8.104 58.512 8.273 59.304 ;
     RECT  8.104 19.632 8.345 29.4 ;
     RECT  8.237 78.384 8.345 80.328 ;
     RECT  8.104 31.776 8.381 32.568 ;
     RECT  8.149 0.096 8.387 0.552 ;
     RECT  8.104 88.464 8.453 88.488 ;
     RECT  8.104 55.104 8.525 57.144 ;
     RECT  8.104 2.148 8.533 18.312 ;
     RECT  8.165 90.384 8.561 90.6 ;
     RECT  8.104 33.84 8.579 35.544 ;
     RECT  8.104 40.08 8.669 40.968 ;
     RECT  8.104 69.264 8.669 69.288 ;
     RECT  8.104 48.816 8.705 48.84 ;
     RECT  8.381 32.016 8.741 32.568 ;
     RECT  8.104 42.288 8.777 45 ;
     RECT  8.525 55.104 8.813 57.096 ;
     RECT  8.813 55.104 8.819 56.952 ;
     RECT  8.579 33.888 8.849 35.544 ;
     RECT  8.819 56.112 8.86 56.952 ;
     RECT  8.387 0.096 8.867 0.408 ;
     RECT  8.201 52.512 8.867 53.928 ;
     RECT  8.104 66.24 8.885 66.312 ;
     RECT  8.561 90.384 8.885 90.504 ;
     RECT  8.86 56.448 8.893 56.952 ;
     RECT  8.867 0.096 8.965 0.312 ;
     RECT  8.777 43.392 9.029 45 ;
     RECT  8.104 64.848 9.065 64.872 ;
     RECT  8.965 0.144 9.073 0.312 ;
     RECT  8.345 21.504 9.101 29.4 ;
     RECT  9.029 44.928 9.101 45 ;
     RECT  8.533 1.728 9.136 18.312 ;
     RECT  8.345 19.632 9.136 20.52 ;
     RECT  8.104 67.344 9.137 67.368 ;
     RECT  8.104 82.704 9.137 87.432 ;
     RECT  9.101 21.504 9.173 23.112 ;
     RECT  9.101 44.976 9.173 45 ;
     RECT  8.893 56.928 9.173 56.952 ;
     RECT  8.777 42.288 9.245 42.312 ;
     RECT  8.104 70.656 9.277 73.272 ;
     RECT  8.104 74.304 9.277 74.328 ;
     RECT  8.741 32.496 9.281 32.568 ;
     RECT  8.849 33.888 9.281 34.2 ;
     RECT  9.137 82.752 9.313 87.432 ;
     RECT  8.867 52.512 9.353 52.968 ;
     RECT  9.313 82.752 9.457 87.624 ;
     RECT  8.273 58.608 9.461 59.304 ;
     RECT  9.101 24.096 9.491 29.4 ;
     RECT  8.104 46.272 9.493 46.392 ;
     RECT  8.104 62.544 9.497 63.288 ;
     RECT  8.819 55.104 9.529 55.128 ;
     RECT  9.491 24.384 9.601 29.4 ;
     RECT  8.345 78.384 9.605 80.28 ;
     RECT  9.353 52.512 9.641 52.728 ;
     RECT  9.281 34.176 9.677 34.2 ;
     RECT  9.109 88.896 9.677 88.92 ;
     RECT  9.277 70.656 9.683 74.328 ;
     RECT  9.601 24.384 9.733 29.592 ;
     RECT  8.104 30.576 9.733 30.6 ;
     RECT  9.673 68.16 9.745 68.184 ;
     RECT  9.457 82.752 9.745 87.768 ;
     RECT  8.201 49.872 9.785 49.896 ;
     RECT  9.493 46.272 9.821 46.776 ;
     RECT  9.529 54.576 9.821 55.128 ;
     RECT  9.683 71.424 9.821 74.328 ;
     RECT  9.745 64.56 9.853 64.68 ;
     RECT  8.885 66.288 9.889 66.312 ;
     RECT  9.461 58.608 9.929 59.064 ;
     RECT  9.733 24.384 9.997 30.6 ;
     RECT  9.136 1.728 10.069 20.52 ;
     RECT  9.029 43.392 10.141 43.944 ;
     RECT  9.173 21.84 10.165 23.112 ;
     RECT  9.745 68.16 10.177 68.28 ;
     RECT  8.669 40.944 10.181 40.968 ;
     RECT  9.961 0.528 10.211 0.552 ;
     RECT  10.069 1.728 10.213 20.568 ;
     RECT  10.165 21.744 10.213 23.112 ;
     RECT  9.529 35.568 10.213 35.592 ;
     RECT  9.889 66.288 10.213 66.648 ;
     RECT  9.997 24.384 10.217 30.792 ;
     RECT  9.605 79.776 10.289 80.28 ;
     RECT  9.745 82.752 10.289 87.816 ;
     RECT  10.241 0.096 10.325 0.12 ;
     RECT  9.853 64.464 10.361 64.68 ;
     RECT  10.289 83.52 10.393 87.816 ;
     RECT  8.885 90.384 10.397 90.456 ;
     RECT  10.213 1.728 10.405 23.112 ;
     RECT  10.361 64.56 10.429 64.68 ;
     RECT  9.281 32.496 10.465 32.52 ;
     RECT  9.821 72.432 10.537 74.328 ;
     RECT  10.177 67.68 10.573 68.28 ;
     RECT  10.429 64.56 10.613 64.824 ;
     RECT  10.289 79.776 10.649 79.944 ;
     RECT  9.821 54.576 10.685 54.6 ;
     RECT  9.605 78.384 10.685 78.744 ;
     RECT  9.497 62.544 10.717 63.048 ;
     RECT  10.573 76.32 10.721 76.344 ;
     RECT  10.405 1.728 10.753 23.352 ;
     RECT  10.217 24.384 10.753 29.064 ;
     RECT  10.393 47.856 10.789 47.88 ;
     RECT  9.821 46.272 10.825 46.296 ;
     RECT  10.501 49.584 10.825 49.608 ;
     RECT  10.789 47.856 10.835 48.12 ;
     RECT  10.717 62.544 10.865 63.576 ;
     RECT  10.397 90.384 10.865 90.408 ;
     RECT  10.213 66.192 10.897 66.648 ;
     RECT  9.821 71.424 10.897 71.448 ;
     RECT  10.537 72.432 10.897 74.616 ;
     RECT  10.213 35.52 10.933 35.592 ;
     RECT  9.641 52.704 10.933 52.728 ;
     RECT  10.613 64.608 10.933 64.824 ;
     RECT  10.465 32.064 11.005 32.52 ;
     RECT  10.649 79.776 11.009 79.8 ;
     RECT  10.825 45.84 11.041 46.872 ;
     RECT  10.537 82.416 11.045 82.44 ;
     RECT  10.933 51.264 11.075 52.728 ;
     RECT  10.217 30.096 11.081 30.792 ;
     RECT  11.041 45.744 11.189 46.872 ;
     RECT  10.393 83.52 11.189 88.104 ;
     RECT  11.005 31.776 11.221 32.52 ;
     RECT  10.825 49.584 11.225 50.04 ;
     RECT  10.141 42.432 11.261 43.944 ;
     RECT  11.189 46.272 11.261 46.872 ;
     RECT  10.573 67.632 11.261 68.28 ;
     RECT  10.933 35.52 11.297 36.504 ;
     RECT  10.897 66 11.405 66.648 ;
     RECT  11.221 31.776 11.437 33 ;
     RECT  9.929 59.04 11.437 59.064 ;
     RECT  10.897 71.424 11.459 74.616 ;
     RECT  11.437 31.776 11.473 33.192 ;
     RECT  11.261 67.872 11.477 68.28 ;
     RECT  11.473 31.68 11.549 33.192 ;
     RECT  11.549 31.68 11.585 33 ;
     RECT  11.297 35.616 11.585 36.504 ;
     RECT  11.405 66.192 11.621 66.552 ;
     RECT  11.437 59.04 11.689 59.304 ;
     RECT  11.689 58.08 11.725 59.304 ;
     RECT  11.189 83.52 11.729 87.624 ;
     RECT  11.585 32.208 11.765 33 ;
     RECT  11.225 50.016 11.804 50.04 ;
     RECT  11.075 51.264 11.804 51.336 ;
     RECT  11.729 83.52 11.873 87.336 ;
     RECT  11.804 50.016 11.891 51.336 ;
     RECT  9.925 60.96 11.905 60.984 ;
     RECT  11.557 0.144 11.939 0.168 ;
     RECT  11.401 40.944 11.941 40.968 ;
     RECT  11.621 66.192 11.945 66.312 ;
     RECT  10.685 78.384 11.945 78.648 ;
     RECT  10.753 1.728 11.977 29.064 ;
     RECT  11.081 30.096 11.977 30.696 ;
     RECT  10.789 54.432 11.977 54.456 ;
     RECT  10.865 62.544 11.977 63.384 ;
     RECT  10.933 64.608 11.977 64.968 ;
     RECT  11.891 51.312 11.981 51.336 ;
     RECT  11.977 54.432 11.981 54.552 ;
     RECT  11.477 67.872 12.017 68.232 ;
     RECT  11.873 83.52 12.017 87.192 ;
     RECT  11.459 72.192 12.049 74.616 ;
     RECT  12.017 83.52 12.053 87 ;
     RECT  11.977 1.728 12.089 30.696 ;
     RECT  11.437 82.224 12.092 82.248 ;
     RECT  12.053 83.52 12.092 86.52 ;
     RECT  11.905 60.432 12.161 61.032 ;
     RECT  11.261 42.672 12.197 43.944 ;
     RECT  12.197 43.392 12.409 43.944 ;
     RECT  11.585 36.48 12.589 36.504 ;
     RECT  8.104 37.872 12.589 38.712 ;
     RECT  11.945 78.384 12.877 78.408 ;
     RECT  12.589 36.48 12.908 38.712 ;
     RECT  10.897 34.176 12.949 34.2 ;
     RECT  11.725 57.648 12.949 59.304 ;
     RECT  11.075 52.704 13.021 52.728 ;
     RECT  12.092 82.224 13.021 86.52 ;
     RECT  11.765 32.208 13.052 32.232 ;
     RECT  11.941 40.56 13.057 40.968 ;
     RECT  12.017 67.92 13.057 68.088 ;
     RECT  12.589 0.528 13.091 0.552 ;
     RECT  13.052 32.208 13.093 32.472 ;
     RECT  12.769 35.232 13.093 35.256 ;
     RECT  12.908 36.48 13.093 39.336 ;
     RECT  13.021 82.224 13.129 86.664 ;
     RECT  11.945 66.288 13.201 66.312 ;
     RECT  12.089 1.728 13.208 29.064 ;
     RECT  12.089 30.048 13.208 30.696 ;
     RECT  13.093 32.208 13.208 33.048 ;
     RECT  12.949 34.176 13.208 34.248 ;
     RECT  13.093 35.232 13.208 39.336 ;
     RECT  13.057 40.32 13.208 40.968 ;
     RECT  12.409 43.392 13.208 44.472 ;
     RECT  11.261 46.272 13.208 46.296 ;
     RECT  10.835 48.096 13.208 48.12 ;
     RECT  11.891 50.016 13.208 50.04 ;
     RECT  13.021 52.56 13.208 52.728 ;
     RECT  11.981 54.528 13.208 54.552 ;
     RECT  12.949 57.408 13.208 59.304 ;
     RECT  12.161 60.432 13.208 60.456 ;
     RECT  11.977 62.544 13.208 64.968 ;
     RECT  13.201 66.288 13.208 66.504 ;
     RECT  13.057 67.824 13.208 68.088 ;
     RECT  12.841 70.032 13.208 70.056 ;
     RECT  12.049 72.192 13.208 75.192 ;
     RECT  12.877 77.664 13.208 78.408 ;
     RECT  13.129 82.224 13.208 86.76 ;
     RECT  13.208 1.728 13.312 88.572 ;
     RECT  13.237 0.336 13.477 0.36 ;
     RECT  13.312 1.728 13.504 88.302 ;
     RECT  13.504 33.024 13.673 35.832 ;
     RECT  13.504 57.408 13.709 59.304 ;
     RECT  13.504 62.064 13.745 65.208 ;
     RECT  13.477 0.24 13.813 0.36 ;
     RECT  13.504 37.968 13.853 40.872 ;
     RECT  13.813 0.144 13.858 0.36 ;
     RECT  13.504 1.728 13.889 30.696 ;
     RECT  13.853 38.4 13.925 40.872 ;
     RECT  13.504 74.592 13.961 75.912 ;
     RECT  13.858 0.096 13.969 0.36 ;
     RECT  13.504 45.12 14.044 45.144 ;
     RECT  13.504 82.656 14.141 86.616 ;
     RECT  13.961 74.592 14.243 74.664 ;
     RECT  13.504 76.944 14.257 77.784 ;
     RECT  13.889 1.776 14.284 30.696 ;
     RECT  13.504 66.288 14.285 66.504 ;
     RECT  13.504 80.112 14.291 81.048 ;
     RECT  13.504 49.056 14.321 52.728 ;
     RECT  13.709 59.088 14.357 59.304 ;
     RECT  13.925 38.4 14.429 40.344 ;
     RECT  14.429 38.4 14.465 39.384 ;
     RECT  14.321 49.056 14.483 50.616 ;
     RECT  13.969 0.144 14.531 0.36 ;
     RECT  14.321 51.84 14.533 52.728 ;
     RECT  13.504 61.008 14.533 61.032 ;
     RECT  13.673 33.024 14.537 35.4 ;
     RECT  14.483 50.544 14.537 50.616 ;
     RECT  14.531 0.144 14.579 0.264 ;
     RECT  13.504 72.192 14.605 73.272 ;
     RECT  14.291 81.024 14.717 81.048 ;
     RECT  13.709 57.408 14.753 57.96 ;
     RECT  13.745 63.6 14.857 65.208 ;
     RECT  14.753 57.6 14.861 57.96 ;
     RECT  14.857 63.552 14.861 65.208 ;
     RECT  13.961 75.648 14.861 75.912 ;
     RECT  14.141 82.656 14.861 86.568 ;
     RECT  14.257 77.424 14.885 77.784 ;
     RECT  13.745 62.064 14.893 62.568 ;
     RECT  14.861 63.552 14.893 64.968 ;
     RECT  13.504 67.584 14.933 67.848 ;
     RECT  14.605 72.192 14.933 73.368 ;
     RECT  14.885 77.424 14.969 78.696 ;
     RECT  14.861 83.232 14.969 86.568 ;
     RECT  14.933 67.824 15.005 67.848 ;
     RECT  14.284 1.776 15.037 29.544 ;
     RECT  14.533 51.84 15.073 53.4 ;
     RECT  14.861 57.6 15.077 57.624 ;
     RECT  14.243 74.592 15.113 74.616 ;
     RECT  14.533 60.672 15.26 61.032 ;
     RECT  14.893 62.064 15.26 64.968 ;
     RECT  14.969 77.424 15.347 78.072 ;
     RECT  14.284 30.672 15.397 30.696 ;
     RECT  15.073 51.84 15.397 54.072 ;
     RECT  14.357 59.088 15.401 59.112 ;
     RECT  15.397 51.744 15.433 54.072 ;
     RECT  14.537 50.544 15.501 50.568 ;
     RECT  14.483 49.056 15.577 49.56 ;
     RECT  13.504 47.184 15.589 47.208 ;
     RECT  15.577 49.056 15.589 49.608 ;
     RECT  15.589 47.184 15.635 49.608 ;
     RECT  15.397 30.576 15.649 30.696 ;
     RECT  15.635 48.096 15.661 49.608 ;
     RECT  15.649 30.576 15.676 30.744 ;
     RECT  15.661 48.096 15.676 49.464 ;
     RECT  15.676 30.672 15.685 30.744 ;
     RECT  14.465 38.4 15.788 39.336 ;
     RECT  15.037 1.728 15.833 29.544 ;
     RECT  15.788 37.488 15.865 39.336 ;
     RECT  15.757 70.656 15.905 70.68 ;
     RECT  15.865 36.48 15.925 39.336 ;
     RECT  15.001 40.416 15.925 40.44 ;
     RECT  14.569 41.616 15.925 41.64 ;
     RECT  13.504 43.248 15.925 43.944 ;
     RECT  15.26 60.672 15.964 64.968 ;
     RECT  15.964 62.544 15.971 64.968 ;
     RECT  15.925 36.48 15.973 40.44 ;
     RECT  15.433 51.744 15.973 54.984 ;
     RECT  15.973 36.48 16.012 40.584 ;
     RECT  15.964 60.672 16.012 61.56 ;
     RECT  15.925 41.616 16.013 43.944 ;
     RECT  15.973 51.744 16.013 55.176 ;
     RECT  16.013 51.744 16.049 52.488 ;
     RECT  16.012 36.48 16.085 39.048 ;
     RECT  16.013 53.52 16.085 55.176 ;
     RECT  16.085 54.96 16.193 55.176 ;
     RECT  14.537 33.552 16.213 35.4 ;
     RECT  16.012 40.416 16.229 40.584 ;
     RECT  15.685 30.672 16.261 31.608 ;
     RECT  16.213 32.688 16.261 35.4 ;
     RECT  16.261 30.672 16.301 35.4 ;
     RECT  16.012 60.672 16.369 61.368 ;
     RECT  16.301 33.072 16.373 35.4 ;
     RECT  16.373 34.176 16.44 35.4 ;
     RECT  14.933 72.192 16.441 73.032 ;
     RECT  16.085 37.152 16.481 39.048 ;
     RECT  15.676 49.056 16.481 49.464 ;
     RECT  16.193 55.152 16.481 55.176 ;
     RECT  16.481 49.2 16.517 49.464 ;
     RECT  14.713 56.208 16.517 56.232 ;
     RECT  14.579 0.144 16.549 0.168 ;
     RECT  15.833 1.728 16.549 29.496 ;
     RECT  16.477 79.392 16.549 79.416 ;
     RECT  16.229 40.464 16.589 40.584 ;
     RECT  16.549 0.144 16.643 29.496 ;
     RECT  16.549 79.392 16.661 79.512 ;
     RECT  15.971 63.024 16.729 64.968 ;
     RECT  14.969 83.232 16.801 85.272 ;
     RECT  16.517 49.44 16.805 49.464 ;
     RECT  16.085 53.52 16.877 53.544 ;
     RECT  14.861 75.648 16.981 75.672 ;
     RECT  14.969 86.304 16.981 86.568 ;
     RECT  14.713 87.792 16.981 87.816 ;
     RECT  16.873 68.928 16.985 68.952 ;
     RECT  16.729 63.024 17.053 65.016 ;
     RECT  14.285 66.288 17.053 66.312 ;
     RECT  16.801 83.184 17.053 85.272 ;
     RECT  16.981 86.304 17.053 87.816 ;
     RECT  16.369 60.432 17.057 61.368 ;
     RECT  16.643 0.144 17.075 0.168 ;
     RECT  16.481 37.152 17.077 38.424 ;
     RECT  16.013 42.384 17.089 43.944 ;
     RECT  16.441 72.192 17.129 73.512 ;
     RECT  15.757 82.032 17.129 82.056 ;
     RECT  17.053 83.184 17.201 87.816 ;
     RECT  16.873 67.488 17.273 67.512 ;
     RECT  16.643 1.728 17.377 29.496 ;
     RECT  16.301 30.672 17.377 32.04 ;
     RECT  17.377 1.728 17.453 32.04 ;
     RECT  17.077 37.008 17.485 38.424 ;
     RECT  17.485 37.008 17.509 38.712 ;
     RECT  16.373 33.072 17.557 33.096 ;
     RECT  16.44 34.176 17.557 35.448 ;
     RECT  17.089 42.384 17.564 44.136 ;
     RECT  16.589 40.464 17.593 40.488 ;
     RECT  17.453 1.776 17.597 32.04 ;
     RECT  17.509 36.864 17.605 38.712 ;
     RECT  16.981 75.168 17.605 75.672 ;
     RECT  17.605 75.168 17.629 76.344 ;
     RECT  17.605 36.816 17.773 39.096 ;
     RECT  17.557 33.072 17.893 35.448 ;
     RECT  17.893 33.024 17.953 35.448 ;
     RECT  17.773 36.816 17.953 39.384 ;
     RECT  17.953 33.024 17.989 39.384 ;
     RECT  17.593 40.464 17.989 41.064 ;
     RECT  17.845 80.352 17.989 80.376 ;
     RECT  17.564 42.144 18.037 44.136 ;
     RECT  16.621 59.184 18.037 59.208 ;
     RECT  17.461 0.096 18.101 0.12 ;
     RECT  17.053 63.024 18.133 66.312 ;
     RECT  17.597 2.208 18.181 32.04 ;
     RECT  17.989 33.024 18.181 41.064 ;
     RECT  17.377 69.84 18.181 69.864 ;
     RECT  18.133 55.008 18.205 55.032 ;
     RECT  17.953 46.656 18.229 46.68 ;
     RECT  17.629 75.12 18.241 76.344 ;
     RECT  17.989 80.352 18.241 81.096 ;
     RECT  18.241 79.968 18.421 81.096 ;
     RECT  17.201 83.184 18.457 86.76 ;
     RECT  15.347 78.048 18.469 78.072 ;
     RECT  18.421 79.056 18.469 81.096 ;
     RECT  18.181 69.84 18.601 70.104 ;
     RECT  18.181 2.208 18.608 41.064 ;
     RECT  18.037 42.144 18.608 44.328 ;
     RECT  18.229 46.656 18.608 47.352 ;
     RECT  16.049 52.464 18.608 52.488 ;
     RECT  18.205 54.96 18.608 55.032 ;
     RECT  18.037 58.512 18.608 59.208 ;
     RECT  17.057 61.344 18.608 61.368 ;
     RECT  18.133 63.024 18.608 66.504 ;
     RECT  18.601 69.456 18.608 70.104 ;
     RECT  17.129 72.192 18.608 73.032 ;
     RECT  17.809 74.112 18.608 74.136 ;
     RECT  18.241 75.12 18.608 76.872 ;
     RECT  18.469 78.048 18.608 81.096 ;
     RECT  18.457 82.944 18.608 86.76 ;
     RECT  18.608 2.148 18.613 88.572 ;
     RECT  18.613 2.016 18.709 88.572 ;
     RECT  18.709 1.968 18.712 88.572 ;
     RECT  18.712 1.968 18.805 88.302 ;
     RECT  18.805 1.728 18.904 88.302 ;
     RECT  18.904 62.928 19.001 66.504 ;
     RECT  18.904 50.832 19.073 50.856 ;
     RECT  18.904 1.728 19.109 40.872 ;
     RECT  18.904 80.448 19.283 86.52 ;
     RECT  18.517 0.24 19.285 0.504 ;
     RECT  18.904 73.008 19.289 77.64 ;
     RECT  19.283 82.416 19.325 86.52 ;
     RECT  19.109 1.728 19.397 39.24 ;
     RECT  18.904 49.488 19.433 49.512 ;
     RECT  18.904 78.624 19.505 78.984 ;
     RECT  19.325 82.656 19.541 86.52 ;
     RECT  19.285 0.192 19.573 0.504 ;
     RECT  18.904 69.456 19.577 69.48 ;
     RECT  18.904 54.72 19.667 55.896 ;
     RECT  18.904 87.84 19.721 87.864 ;
     RECT  18.904 46.368 19.837 48.264 ;
     RECT  19.573 0.144 19.861 0.504 ;
     RECT  19.397 1.728 19.861 37.656 ;
     RECT  18.904 71.28 19.933 71.304 ;
     RECT  19.289 77.52 19.933 77.64 ;
     RECT  19.505 78.624 19.933 78.648 ;
     RECT  18.904 58.128 19.957 58.536 ;
     RECT  19.001 65.376 19.957 66.504 ;
     RECT  19.283 80.448 19.969 81.048 ;
     RECT  19.541 83.232 20.005 86.52 ;
     RECT  19.109 40.224 20.041 40.872 ;
     RECT  19.957 65.376 20.101 66.744 ;
     RECT  19.861 0.144 20.149 37.656 ;
     RECT  19.933 77.52 20.225 78.648 ;
     RECT  18.904 52.464 20.245 52.488 ;
     RECT  19.397 38.688 20.261 39.24 ;
     RECT  20.149 0.096 20.297 37.656 ;
     RECT  20.041 40.224 20.365 41.112 ;
     RECT  18.904 42.24 20.365 44.904 ;
     RECT  19.289 73.008 20.365 76.536 ;
     RECT  20.365 72.768 20.401 76.536 ;
     RECT  20.225 77.52 20.401 77.64 ;
     RECT  20.297 36.48 20.437 37.656 ;
     RECT  20.365 40.224 20.437 44.904 ;
     RECT  19.957 58.128 20.441 59.016 ;
     RECT  20.441 58.128 20.473 58.152 ;
     RECT  18.904 61.344 20.473 61.848 ;
     RECT  19.001 62.928 20.473 64.392 ;
     RECT  20.101 65.376 20.473 67.608 ;
     RECT  19.969 80.064 20.513 81.048 ;
     RECT  20.437 40.224 20.521 45.624 ;
     RECT  20.245 52.464 20.531 53.064 ;
     RECT  20.005 83.232 20.533 86.856 ;
     RECT  20.473 65.376 20.557 67.848 ;
     RECT  20.521 40.224 20.581 45.048 ;
     RECT  20.297 0.096 20.627 35.352 ;
     RECT  20.581 49.344 20.653 49.368 ;
     RECT  20.581 39.36 20.665 45.048 ;
     RECT  20.401 72.768 20.689 77.64 ;
     RECT  19.933 71.04 20.761 71.304 ;
     RECT  20.689 72.384 20.761 77.64 ;
     RECT  20.513 80.448 20.833 81.048 ;
     RECT  20.761 71.04 20.909 77.64 ;
     RECT  20.909 71.04 20.915 77.544 ;
     RECT  19.837 47.088 20.941 48.264 ;
     RECT  20.941 46.32 21.013 48.264 ;
     RECT  20.653 49.344 21.013 49.608 ;
     RECT  20.915 71.04 21.049 76.92 ;
     RECT  21.013 46.32 21.107 49.608 ;
     RECT  20.225 78.624 21.125 78.648 ;
     RECT  20.531 53.04 21.157 53.064 ;
     RECT  20.149 69.984 21.157 70.008 ;
     RECT  21.049 70.992 21.161 76.92 ;
     RECT  21.157 69.6 21.193 70.008 ;
     RECT  20.627 1.728 21.197 35.352 ;
     RECT  21.107 49.344 21.229 49.608 ;
     RECT  19.667 54.72 21.301 55.56 ;
     RECT  20.627 0.096 21.305 0.312 ;
     RECT  20.437 36.48 21.337 38.28 ;
     RECT  20.665 39.36 21.337 39.384 ;
     RECT  21.197 34.704 21.445 35.352 ;
     RECT  21.337 36.48 21.445 39.384 ;
     RECT  21.409 59.76 21.445 59.784 ;
     RECT  20.533 83.232 21.445 87.816 ;
     RECT  20.557 65.376 21.449 67.608 ;
     RECT  21.445 83.184 21.449 87.816 ;
     RECT  21.157 53.04 21.481 53.352 ;
     RECT  21.193 69.6 21.481 70.056 ;
     RECT  21.449 66.768 21.485 67.608 ;
     RECT  21.197 1.728 21.491 33.672 ;
     RECT  20.473 57.6 21.491 58.152 ;
     RECT  21.449 87.504 21.493 87.816 ;
     RECT  20.833 80.448 21.517 81.864 ;
     RECT  20.665 40.464 21.557 45.048 ;
     RECT  20.473 61.344 21.557 64.392 ;
     RECT  21.449 83.184 21.593 86.04 ;
     RECT  21.449 65.376 21.665 65.4 ;
     RECT  21.517 80.352 21.665 81.864 ;
     RECT  21.445 34.704 21.683 39.384 ;
     RECT  21.161 71.04 21.731 76.92 ;
     RECT  21.557 43.104 21.733 45.048 ;
     RECT  21.637 46.032 21.733 46.104 ;
     RECT  21.491 57.6 21.845 57.624 ;
     RECT  21.733 43.104 22.093 46.104 ;
     RECT  21.107 47.088 22.093 48.264 ;
     RECT  21.517 78.816 22.093 78.84 ;
     RECT  21.481 68.832 22.129 70.056 ;
     RECT  21.731 71.04 22.129 74.712 ;
     RECT  21.491 17.52 22.165 33.672 ;
     RECT  21.683 34.704 22.165 38.184 ;
     RECT  21.301 54.72 22.165 55.704 ;
     RECT  21.557 61.344 22.165 61.368 ;
     RECT  21.557 63.072 22.201 64.392 ;
     RECT  22.165 54.72 22.211 56.28 ;
     RECT  22.093 43.104 22.213 48.264 ;
     RECT  22.211 56.256 22.252 56.28 ;
     RECT  21.229 49.344 22.277 50.136 ;
     RECT  21.305 0.144 22.309 0.312 ;
     RECT  21.491 1.728 22.309 16.536 ;
     RECT  22.165 17.52 22.313 38.184 ;
     RECT  21.683 39.312 22.345 39.384 ;
     RECT  22.213 45.168 22.348 48.264 ;
     RECT  21.481 53.04 22.405 53.592 ;
     RECT  21.485 67.056 22.453 67.608 ;
     RECT  21.445 59.664 22.457 59.784 ;
     RECT  22.405 53.04 22.492 53.64 ;
     RECT  22.309 0.144 22.508 16.536 ;
     RECT  22.313 17.52 22.508 37.848 ;
     RECT  21.557 40.464 22.525 41.928 ;
     RECT  22.213 43.104 22.525 44.04 ;
     RECT  22.453 67.056 22.525 67.704 ;
     RECT  22.129 68.832 22.525 74.712 ;
     RECT  22.201 63.072 22.561 64.776 ;
     RECT  21.665 81.696 22.561 81.864 ;
     RECT  21.593 83.232 22.561 84.36 ;
     RECT  22.508 0.144 22.595 37.848 ;
     RECT  22.561 81.696 22.633 84.36 ;
     RECT  22.211 54.72 22.637 55.272 ;
     RECT  22.348 45.552 22.673 48.264 ;
     RECT  22.457 59.76 22.673 59.784 ;
     RECT  22.345 39.312 22.7 39.432 ;
     RECT  22.633 80.88 22.705 84.36 ;
     RECT  21.593 85.44 22.705 86.04 ;
     RECT  22.705 80.88 22.739 86.04 ;
     RECT  22.492 53.472 22.745 53.64 ;
     RECT  22.309 50.784 22.789 50.904 ;
     RECT  22.669 51.984 22.789 52.008 ;
     RECT  22.277 49.344 22.849 49.608 ;
     RECT  22.525 40.416 22.853 44.04 ;
     RECT  21.493 87.504 22.853 87.528 ;
     RECT  22.595 17.568 22.925 37.848 ;
     RECT  22.849 49.056 22.933 49.608 ;
     RECT  22.637 55.248 22.961 55.272 ;
     RECT  22.525 67.056 22.997 74.712 ;
     RECT  22.093 78.816 22.997 79.512 ;
     RECT  22.739 81.408 23.065 86.04 ;
     RECT  22.997 68.832 23.137 74.712 ;
     RECT  21.731 75.744 23.137 76.92 ;
     RECT  22.997 79.488 23.209 79.512 ;
     RECT  22.165 61.296 23.245 61.368 ;
     RECT  22.7 39.072 23.281 39.432 ;
     RECT  22.853 40.416 23.281 43.944 ;
     RECT  22.595 0.144 23.317 16.536 ;
     RECT  22.925 33.12 23.317 37.848 ;
     RECT  23.281 39.072 23.317 43.944 ;
     RECT  22.933 49.344 23.317 49.608 ;
     RECT  22.789 50.784 23.317 52.008 ;
     RECT  22.561 62.544 23.389 64.776 ;
     RECT  23.317 0.096 23.429 16.536 ;
     RECT  23.317 49.344 23.612 52.008 ;
     RECT  22.745 53.472 23.612 53.592 ;
     RECT  23.429 0.192 23.641 16.536 ;
     RECT  22.925 17.568 23.641 31.944 ;
     RECT  23.389 62.544 23.677 65.544 ;
     RECT  23.245 60.96 23.713 61.368 ;
     RECT  23.677 62.544 23.713 65.688 ;
     RECT  23.612 49.344 23.749 53.592 ;
     RECT  23.065 81.408 23.893 86.76 ;
     RECT  23.137 68.832 23.965 76.92 ;
     RECT  23.749 49.344 24.001 54.168 ;
     RECT  23.641 0.192 24.008 31.944 ;
     RECT  23.317 33.12 24.008 43.944 ;
     RECT  22.673 45.552 24.008 48.072 ;
     RECT  24.001 49.344 24.008 54.696 ;
     RECT  23.641 56.592 24.008 56.616 ;
     RECT  22.633 58.656 24.008 58.68 ;
     RECT  23.929 59.76 24.008 59.784 ;
     RECT  23.713 60.96 24.008 65.688 ;
     RECT  22.997 67.056 24.008 67.704 ;
     RECT  23.965 68.688 24.008 76.92 ;
     RECT  23.209 78.336 24.008 78.36 ;
     RECT  23.209 79.488 24.008 80.424 ;
     RECT  23.893 81.408 24.008 87.144 ;
     RECT  24.008 0.192 24.112 88.572 ;
     RECT  24.112 0.192 24.304 88.344 ;
     RECT  24.304 36.24 24.445 48.696 ;
     RECT  24.304 67.248 24.473 67.704 ;
     RECT  24.445 39.888 24.515 48.696 ;
     RECT  24.304 59.76 24.537 65.544 ;
     RECT  24.304 0.192 24.565 35.16 ;
     RECT  24.304 85.488 24.581 87.144 ;
     RECT  24.515 42.144 24.659 48.696 ;
     RECT  24.304 50.688 24.659 52.152 ;
     RECT  24.304 53.52 24.659 58.728 ;
     RECT  24.581 85.776 24.689 87.144 ;
     RECT  24.537 59.856 24.833 65.544 ;
     RECT  24.304 68.688 24.833 81.48 ;
     RECT  24.565 0.144 24.853 35.16 ;
     RECT  24.853 0.096 24.899 35.16 ;
     RECT  24.659 54.672 24.905 58.728 ;
     RECT  24.899 0.096 24.941 0.456 ;
     RECT  24.905 54.672 24.977 55.848 ;
     RECT  24.689 87.12 25.013 87.144 ;
     RECT  24.659 50.688 25.121 51.192 ;
     RECT  24.445 36.24 25.157 38.76 ;
     RECT  24.977 54.672 25.157 55.464 ;
     RECT  24.304 82.656 25.157 83.256 ;
     RECT  24.905 57.408 25.193 58.728 ;
     RECT  25.157 54.672 25.229 55.416 ;
     RECT  24.659 53.52 25.265 53.544 ;
     RECT  24.833 68.688 25.265 80.328 ;
     RECT  24.659 45.6 25.297 48.696 ;
     RECT  25.297 45.6 25.301 49.608 ;
     RECT  25.265 78.96 25.373 80.328 ;
     RECT  25.301 45.648 25.427 49.608 ;
     RECT  25.157 82.704 25.441 83.256 ;
     RECT  24.304 84.336 25.441 84.36 ;
     RECT  25.193 57.552 25.475 57.576 ;
     RECT  25.265 68.688 25.475 77.976 ;
     RECT  25.229 54.672 25.481 55.32 ;
     RECT  25.475 68.688 25.481 76.92 ;
     RECT  24.515 39.888 25.58 41.064 ;
     RECT  24.659 42.144 25.58 44.472 ;
     RECT  24.689 85.776 25.621 86.088 ;
     RECT  25.157 36.24 25.633 38.04 ;
     RECT  25.58 39.888 25.667 44.472 ;
     RECT  25.481 68.688 25.697 69.864 ;
     RECT  25.667 39.888 25.705 40.44 ;
     RECT  25.633 36.24 25.733 36.408 ;
     RECT  25.633 37.44 25.733 38.04 ;
     RECT  25.733 37.584 25.769 38.04 ;
     RECT  25.121 50.688 25.769 50.712 ;
     RECT  25.427 47.808 25.805 49.608 ;
     RECT  25.373 78.96 25.805 78.984 ;
     RECT  24.833 59.856 25.837 61.368 ;
     RECT  24.833 62.736 25.837 65.544 ;
     RECT  24.473 67.248 25.837 67.608 ;
     RECT  25.697 68.688 25.837 69.528 ;
     RECT  25.441 82.704 25.837 84.36 ;
     RECT  25.621 85.488 25.837 86.088 ;
     RECT  24.941 0.144 25.909 0.456 ;
     RECT  24.899 1.728 25.909 35.16 ;
     RECT  25.909 1.728 25.955 36.024 ;
     RECT  25.909 0.144 25.973 0.504 ;
     RECT  25.837 59.856 26.021 61.464 ;
     RECT  25.193 58.704 26.093 58.728 ;
     RECT  25.955 1.728 26.099 34.296 ;
     RECT  25.837 82.704 26.125 86.088 ;
     RECT  25.705 39.888 26.129 39.96 ;
     RECT  26.099 1.728 26.14 34.104 ;
     RECT  24.833 81.456 26.197 81.48 ;
     RECT  26.129 39.888 26.237 39.912 ;
     RECT  26.197 81.408 26.3 81.48 ;
     RECT  26.125 82.656 26.3 86.088 ;
     RECT  25.837 67.248 26.305 69.528 ;
     RECT  25.805 47.808 26.309 48.984 ;
     RECT  25.837 62.592 26.309 65.544 ;
     RECT  26.3 81.408 26.341 86.088 ;
     RECT  26.309 62.592 26.345 65.256 ;
     RECT  25.373 80.064 26.377 80.328 ;
     RECT  25.667 42.144 26.381 44.472 ;
     RECT  25.427 45.648 26.387 46.824 ;
     RECT  26.341 81.408 26.387 86.76 ;
     RECT  25.973 0.096 26.435 0.504 ;
     RECT  26.387 45.84 26.453 46.824 ;
     RECT  26.305 67.2 26.485 69.528 ;
     RECT  24.304 88.32 26.485 88.344 ;
     RECT  26.345 63.216 26.525 65.256 ;
     RECT  26.485 87.792 26.525 88.344 ;
     RECT  26.309 47.808 26.557 48.696 ;
     RECT  25.481 70.848 26.665 76.92 ;
     RECT  25.955 35.28 26.701 36.024 ;
     RECT  26.377 80.064 26.741 80.424 ;
     RECT  26.14 1.728 26.771 33.96 ;
     RECT  26.665 70.8 26.773 76.92 ;
     RECT  25.475 77.952 26.773 77.976 ;
     RECT  26.387 82.656 26.773 86.76 ;
     RECT  26.525 87.792 26.773 87.816 ;
     RECT  26.525 63.216 26.813 65.208 ;
     RECT  26.737 56.976 26.849 57 ;
     RECT  26.387 81.408 26.957 81.48 ;
     RECT  26.876 39.216 26.963 39.24 ;
     RECT  26.021 60.288 26.993 61.464 ;
     RECT  26.381 42.144 27.101 42.216 ;
     RECT  26.557 54.768 27.205 54.792 ;
     RECT  26.701 35.28 27.269 36.552 ;
     RECT  25.769 37.584 27.269 37.896 ;
     RECT  27.269 35.28 27.277 37.896 ;
     RECT  26.521 51.648 27.277 51.672 ;
     RECT  26.741 80.4 27.301 80.424 ;
     RECT  27.301 80.4 27.347 80.52 ;
     RECT  27.277 35.28 27.349 38.76 ;
     RECT  27.277 51.648 27.349 51.816 ;
     RECT  26.773 82.656 27.349 87.816 ;
     RECT  27.205 53.04 27.385 54.792 ;
     RECT  26.485 66.864 27.457 69.528 ;
     RECT  26.813 64.848 27.497 65.208 ;
     RECT  27.347 80.496 27.497 80.52 ;
     RECT  27.457 66.672 27.529 69.528 ;
     RECT  27.205 57.312 27.533 57.336 ;
     RECT  26.813 63.216 27.533 63.816 ;
     RECT  27.349 51.648 27.565 51.864 ;
     RECT  27.385 53.04 27.565 55.752 ;
     RECT  27.529 66.672 27.596 69.72 ;
     RECT  27.596 66.528 27.601 69.72 ;
     RECT  26.773 70.8 27.601 77.976 ;
     RECT  27.133 79.152 27.601 79.176 ;
     RECT  26.453 45.84 27.605 45.864 ;
     RECT  27.349 82.272 27.605 87.816 ;
     RECT  27.601 66.528 27.683 69.768 ;
     RECT  27.605 86.88 27.713 87.816 ;
     RECT  27.683 66.672 27.781 69.768 ;
     RECT  27.601 70.8 27.781 79.176 ;
     RECT  27.605 82.272 27.827 85.416 ;
     RECT  26.917 40.944 27.845 40.968 ;
     RECT  27.349 35.04 27.857 38.76 ;
     RECT  27.781 66.672 27.893 79.176 ;
     RECT  26.381 43.344 27.925 44.472 ;
     RECT  26.771 33.648 27.929 33.96 ;
     RECT  27.565 51.648 27.929 55.752 ;
     RECT  27.893 66.816 27.929 79.176 ;
     RECT  27.929 51.648 27.965 54.168 ;
     RECT  27.929 67.104 27.965 79.176 ;
     RECT  26.771 1.728 28.019 32.28 ;
     RECT  27.781 58.416 28.033 58.44 ;
     RECT  27.857 35.04 28.141 38.664 ;
     RECT  26.993 60.288 28.141 61.224 ;
     RECT  28.019 1.728 28.181 27.48 ;
     RECT  27.845 40.944 28.181 41.64 ;
     RECT  27.965 51.648 28.181 53.928 ;
     RECT  28.181 51.648 28.249 53.544 ;
     RECT  27.925 42.768 28.285 44.472 ;
     RECT  28.141 60.288 28.289 61.272 ;
     RECT  28.285 41.808 28.357 44.472 ;
     RECT  26.557 47.328 28.357 48.696 ;
     RECT  27.929 55.536 28.361 55.752 ;
     RECT  27.533 63.264 28.433 63.816 ;
     RECT  28.357 46.752 28.444 48.696 ;
     RECT  26.435 0.096 28.501 0.408 ;
     RECT  28.181 1.728 28.501 27.384 ;
     RECT  28.501 64.608 28.537 64.632 ;
     RECT  28.501 0.096 28.585 27.384 ;
     RECT  27.827 82.272 28.609 83.208 ;
     RECT  28.537 64.608 28.645 65.304 ;
     RECT  28.033 57.84 28.681 58.44 ;
     RECT  27.713 86.88 28.681 86.904 ;
     RECT  28.141 34.704 28.897 38.664 ;
     RECT  28.645 64.608 28.897 65.688 ;
     RECT  28.609 81.36 29.005 83.208 ;
     RECT  27.827 84.384 29.005 85.416 ;
     RECT  28.897 34.704 29.077 39.336 ;
     RECT  28.019 28.464 29.116 32.28 ;
     RECT  29.116 28.416 29.173 32.28 ;
     RECT  28.585 1.728 29.221 27.384 ;
     RECT  29.173 28.416 29.221 32.52 ;
     RECT  29.077 34.656 29.221 39.336 ;
     RECT  28.465 40.32 29.221 40.584 ;
     RECT  28.897 64.608 29.221 65.976 ;
     RECT  28.357 41.808 29.249 44.712 ;
     RECT  27.965 67.104 29.257 78.456 ;
     RECT  27.929 33.648 29.269 33.672 ;
     RECT  29.221 34.656 29.269 40.584 ;
     RECT  29.249 41.808 29.269 44.856 ;
     RECT  29.005 80.784 29.269 85.416 ;
     RECT  29.221 64.608 29.293 66.024 ;
     RECT  29.257 67.104 29.293 78.744 ;
     RECT  28.249 51.12 29.365 53.544 ;
     RECT  29.269 80.112 29.365 85.416 ;
     RECT  28.681 86.88 29.365 87.576 ;
     RECT  29.221 1.728 29.408 32.52 ;
     RECT  29.269 33.648 29.408 44.856 ;
     RECT  28.444 46.848 29.408 48.696 ;
     RECT  28.933 49.968 29.408 49.992 ;
     RECT  29.365 51.12 29.408 54.12 ;
     RECT  28.681 57.84 29.408 58.728 ;
     RECT  28.289 60.288 29.408 61.224 ;
     RECT  28.433 63.264 29.408 63.288 ;
     RECT  29.293 64.608 29.408 78.744 ;
     RECT  29.365 80.112 29.408 87.576 ;
     RECT  29.408 1.728 29.512 88.572 ;
     RECT  29.512 1.728 29.585 88.302 ;
     RECT  29.585 2.256 29.704 88.302 ;
     RECT  29.704 58.896 29.873 61.224 ;
     RECT  29.704 41.952 29.909 48.696 ;
     RECT  28.585 0.096 29.939 0.552 ;
     RECT  29.909 43.632 30.089 48.696 ;
     RECT  29.704 2.256 30.125 40.632 ;
     RECT  30.089 43.872 30.125 48.696 ;
     RECT  30.125 2.256 30.172 38.568 ;
     RECT  29.704 67.584 30.197 83.832 ;
     RECT  29.704 84.96 30.197 88.008 ;
     RECT  30.197 75.072 30.233 83.832 ;
     RECT  30.172 2.256 30.241 38.232 ;
     RECT  30.241 2.256 30.377 37.608 ;
     RECT  30.125 39.6 30.377 40.632 ;
     RECT  30.125 43.872 30.377 46.056 ;
     RECT  29.909 41.952 30.413 42.6 ;
     RECT  30.233 75.072 30.521 83.784 ;
     RECT  30.521 75.072 30.557 76.344 ;
     RECT  30.197 85.392 30.563 88.008 ;
     RECT  30.563 85.488 30.601 88.008 ;
     RECT  29.939 0.144 30.659 0.552 ;
     RECT  30.377 40.608 30.665 40.632 ;
     RECT  30.125 47.376 30.697 48.696 ;
     RECT  29.704 49.728 30.697 53.544 ;
     RECT  29.704 55.248 30.773 57.48 ;
     RECT  29.873 59.184 30.841 61.224 ;
     RECT  30.773 55.248 30.845 55.272 ;
     RECT  30.659 0.528 30.917 0.552 ;
     RECT  30.841 59.184 30.997 61.368 ;
     RECT  30.197 67.584 31.025 74.088 ;
     RECT  29.704 63.792 31.093 66.36 ;
     RECT  31.025 67.584 31.093 72.456 ;
     RECT  31.025 73.776 31.097 74.088 ;
     RECT  31.093 63.792 31.129 72.456 ;
     RECT  30.521 77.664 31.133 83.784 ;
     RECT  31.097 74.064 31.165 74.088 ;
     RECT  30.557 75.072 31.165 75.672 ;
     RECT  30.601 87.744 31.169 88.008 ;
     RECT  30.377 39.6 31.201 39.624 ;
     RECT  30.377 46.032 31.201 46.056 ;
     RECT  30.697 47.376 31.201 53.544 ;
     RECT  31.129 62.976 31.205 72.456 ;
     RECT  30.413 42.144 31.237 42.6 ;
     RECT  30.377 43.872 31.237 45 ;
     RECT  30.773 56.544 31.313 57.48 ;
     RECT  31.205 66 31.385 72.456 ;
     RECT  30.377 2.256 31.477 13.224 ;
     RECT  30.377 14.256 31.477 37.608 ;
     RECT  31.165 74.064 31.525 75.672 ;
     RECT  31.525 74.064 31.565 76.392 ;
     RECT  30.997 59.184 31.571 61.56 ;
     RECT  31.385 66 31.571 72.36 ;
     RECT  31.477 2.256 31.597 37.608 ;
     RECT  31.133 79.68 31.601 83.784 ;
     RECT  31.133 77.664 31.633 78.456 ;
     RECT  31.201 46.032 31.637 53.544 ;
     RECT  31.637 46.752 31.745 53.544 ;
     RECT  31.597 2.256 31.763 37.704 ;
     RECT  31.763 2.256 31.811 36.504 ;
     RECT  31.313 57.024 31.817 57.48 ;
     RECT  31.237 42.144 31.861 45 ;
     RECT  31.571 67.056 31.889 72.36 ;
     RECT  31.861 42.144 31.921 45.192 ;
     RECT  31.565 74.112 31.961 76.392 ;
     RECT  31.571 59.184 32.033 61.368 ;
     RECT  31.889 70.272 32.069 72.36 ;
     RECT  30.985 54.72 32.101 54.744 ;
     RECT  31.633 77.568 32.105 78.456 ;
     RECT  31.763 37.488 32.108 37.704 ;
     RECT  32.101 54.72 32.173 55.416 ;
     RECT  31.961 74.208 32.173 76.392 ;
     RECT  31.921 41.664 32.177 45.192 ;
     RECT  32.108 37.488 32.195 38.04 ;
     RECT  32.173 54.72 32.245 55.464 ;
     RECT  32.069 70.272 32.285 72.072 ;
     RECT  32.033 59.184 32.461 61.224 ;
     RECT  31.811 2.688 32.476 36.504 ;
     RECT  32.476 19.68 32.483 36.504 ;
     RECT  31.205 63.984 32.501 64.632 ;
     RECT  31.205 62.976 32.533 63 ;
     RECT  31.601 80.688 32.533 83.784 ;
     RECT  30.601 85.488 32.533 86.376 ;
     RECT  32.483 19.68 32.537 36.408 ;
     RECT  32.501 63.984 32.609 64.392 ;
     RECT  32.245 57.552 32.681 57.576 ;
     RECT  31.889 67.056 32.681 68.952 ;
     RECT  32.537 19.68 32.717 35.976 ;
     RECT  31.601 79.68 32.785 79.704 ;
     RECT  31.169 87.744 32.828 87.768 ;
     RECT  32.476 2.688 32.869 18.6 ;
     RECT  32.533 80.688 32.869 86.376 ;
     RECT  32.828 87.744 32.869 87.816 ;
     RECT  32.245 54.72 32.893 55.512 ;
     RECT  32.785 79.536 32.893 79.704 ;
     RECT  32.869 80.688 32.893 87.816 ;
     RECT  31.745 46.752 32.915 53.496 ;
     RECT  31.571 66 32.965 66.024 ;
     RECT  32.915 49.056 33.001 53.496 ;
     RECT  32.461 58.944 33.005 61.224 ;
     RECT  32.173 74.208 33.041 76.92 ;
     RECT  33.041 74.208 33.071 76.872 ;
     RECT  33.005 59.28 33.073 61.224 ;
     RECT  32.533 62.544 33.073 63 ;
     RECT  32.285 72.048 33.073 72.072 ;
     RECT  32.105 77.904 33.073 78.456 ;
     RECT  32.893 79.536 33.073 87.816 ;
     RECT  33.073 59.28 33.113 63 ;
     RECT  33.073 77.904 33.149 87.816 ;
     RECT  32.717 19.92 33.203 35.976 ;
     RECT  32.177 42.72 33.221 45.192 ;
     RECT  32.915 46.752 33.221 47.88 ;
     RECT  32.681 67.536 33.289 68.952 ;
     RECT  33.203 21.648 33.293 35.976 ;
     RECT  32.285 70.272 33.293 70.92 ;
     RECT  33.113 59.28 33.299 62.76 ;
     RECT  33.149 86.64 33.301 87.816 ;
     RECT  31.201 39.312 33.325 39.624 ;
     RECT  33.149 77.904 33.347 85.656 ;
     RECT  32.893 54.672 33.361 55.512 ;
     RECT  33.221 42.72 33.365 42.792 ;
     RECT  33.001 49.056 33.397 53.592 ;
     RECT  33.361 54.672 33.397 55.56 ;
     RECT  32.177 41.664 33.437 41.688 ;
     RECT  32.869 2.592 33.493 18.6 ;
     RECT  33.289 56.544 33.509 56.568 ;
     RECT  33.293 21.648 33.545 34.248 ;
     RECT  33.071 74.16 33.545 76.872 ;
     RECT  33.365 42.72 33.577 42.744 ;
     RECT  33.293 35.328 33.613 35.976 ;
     RECT  32.195 37.488 33.613 37.512 ;
     RECT  32.609 64.32 33.613 64.392 ;
     RECT  32.965 66 33.613 66.12 ;
     RECT  33.299 59.28 33.617 62.184 ;
     RECT  33.325 39.216 33.653 39.912 ;
     RECT  33.221 47.376 33.653 47.88 ;
     RECT  33.577 42.672 33.661 42.744 ;
     RECT  33.397 49.056 33.685 55.56 ;
     RECT  33.613 64.32 33.685 66.12 ;
     RECT  33.289 67.536 33.685 69.048 ;
     RECT  33.347 77.904 33.689 84.696 ;
     RECT  33.653 39.216 33.713 39.624 ;
     RECT  33.685 64.32 33.731 69.048 ;
     RECT  33.493 2.592 33.733 18.696 ;
     RECT  33.689 78.432 33.761 84.696 ;
     RECT  33.613 35.328 33.829 37.512 ;
     RECT  33.713 38.784 33.829 39.624 ;
     RECT  33.733 2.544 33.877 18.84 ;
     RECT  33.203 19.92 33.877 20.568 ;
     RECT  33.545 74.16 33.901 74.424 ;
     RECT  33.731 66 33.937 69.048 ;
     RECT  33.293 70.272 33.937 70.872 ;
     RECT  33.877 2.544 34.021 20.568 ;
     RECT  33.685 49.056 34.021 55.992 ;
     RECT  34.021 2.256 34.213 20.568 ;
     RECT  33.545 21.648 34.213 31.896 ;
     RECT  33.301 86.64 34.213 87.912 ;
     RECT  34.213 86.64 34.369 88.152 ;
     RECT  34.213 2.256 34.508 31.896 ;
     RECT  33.545 32.928 34.508 34.248 ;
     RECT  33.661 42.72 34.549 42.744 ;
     RECT  34.508 2.256 34.621 34.248 ;
     RECT  33.653 47.664 34.657 47.88 ;
     RECT  34.021 49.008 34.657 55.992 ;
     RECT  33.829 35.328 34.693 39.624 ;
     RECT  33.731 64.32 34.693 64.344 ;
     RECT  33.937 66 34.765 70.872 ;
     RECT  33.073 72.048 34.765 72.216 ;
     RECT  34.621 2.064 34.808 34.248 ;
     RECT  34.693 35.328 34.808 40.44 ;
     RECT  34.549 42.72 34.808 42.792 ;
     RECT  33.221 43.92 34.808 45.192 ;
     RECT  34.657 47.664 34.808 55.992 ;
     RECT  33.617 59.76 34.808 62.184 ;
     RECT  34.693 64.32 34.808 64.44 ;
     RECT  34.765 66 34.808 72.216 ;
     RECT  33.901 73.536 34.808 74.424 ;
     RECT  33.545 75.984 34.808 76.872 ;
     RECT  33.761 78.432 34.808 82.968 ;
     RECT  33.761 84.24 34.808 84.696 ;
     RECT  34.369 86.352 34.808 88.152 ;
     RECT  34.808 2.064 34.912 88.572 ;
     RECT  34.912 2.064 35.104 88.302 ;
     RECT  35.104 43.92 35.201 47.88 ;
     RECT  35.104 2.064 35.219 35.784 ;
     RECT  35.104 79.536 35.237 84.84 ;
     RECT  35.219 2.064 35.267 35.544 ;
     RECT  35.104 49.008 35.267 53.64 ;
     RECT  35.104 73.536 35.381 76.872 ;
     RECT  35.267 17.088 35.497 35.544 ;
     RECT  35.267 49.008 35.597 53.592 ;
     RECT  35.104 67.248 35.597 72.36 ;
     RECT  35.597 49.296 35.705 53.592 ;
     RECT  35.237 80.16 35.741 84.84 ;
     RECT  35.267 2.064 35.749 16.104 ;
     RECT  35.104 37.008 35.795 41.64 ;
     RECT  35.741 81.456 35.849 84.84 ;
     RECT  35.104 62.16 35.932 62.664 ;
     RECT  35.795 37.008 35.957 41.112 ;
     RECT  35.705 49.296 35.957 53.112 ;
     RECT  35.381 73.536 35.957 75.672 ;
     RECT  35.957 49.488 35.993 53.112 ;
     RECT  35.932 62.544 35.993 62.664 ;
     RECT  35.104 63.792 36.029 63.816 ;
     RECT  35.993 62.64 36.065 62.664 ;
     RECT  35.993 49.488 36.101 50.808 ;
     RECT  35.104 86.064 36.101 86.088 ;
     RECT  35.104 87.168 36.101 87.912 ;
     RECT  35.497 33.264 36.137 35.544 ;
     RECT  35.381 76.848 36.169 76.872 ;
     RECT  35.104 77.952 36.169 78.456 ;
     RECT  35.201 43.92 36.173 44.616 ;
     RECT  36.169 76.848 36.173 78.456 ;
     RECT  35.201 45.936 36.205 47.688 ;
     RECT  35.957 73.536 36.205 75.576 ;
     RECT  36.173 76.848 36.209 77.976 ;
     RECT  36.101 87.504 36.209 87.912 ;
     RECT  35.749 2.016 36.229 16.104 ;
     RECT  35.497 17.088 36.229 32.184 ;
     RECT  35.597 67.248 36.245 68.376 ;
     RECT  35.849 81.456 36.245 84.408 ;
     RECT  36.229 2.016 36.281 32.184 ;
     RECT  36.205 73.44 36.317 75.576 ;
     RECT  36.281 2.064 36.371 32.184 ;
     RECT  36.245 67.248 36.389 67.272 ;
     RECT  36.245 68.352 36.389 68.376 ;
     RECT  35.104 58.032 36.469 58.056 ;
     RECT  35.104 59.232 36.469 60.312 ;
     RECT  36.317 73.44 36.493 74.904 ;
     RECT  36.469 58.032 36.515 58.152 ;
     RECT  36.469 59.232 36.525 60.504 ;
     RECT  36.173 43.92 36.533 44.04 ;
     RECT  35.104 55.488 36.533 56.136 ;
     RECT  36.493 73.392 36.533 74.904 ;
     RECT  36.245 82.176 36.533 84.408 ;
     RECT  36.525 60.48 36.556 60.504 ;
     RECT  35.597 69.504 36.565 72.36 ;
     RECT  36.533 73.392 36.565 74.712 ;
     RECT  36.533 82.176 36.569 83.784 ;
     RECT  36.565 54.912 36.601 54.936 ;
     RECT  35.957 37.008 36.605 40.488 ;
     RECT  36.565 69.504 36.605 74.712 ;
     RECT  35.104 65.808 36.62 66.024 ;
     RECT  36.525 59.232 36.661 59.256 ;
     RECT  36.62 64.896 36.661 66.024 ;
     RECT  35.993 51.936 36.673 53.112 ;
     RECT  36.601 54.576 36.673 54.936 ;
     RECT  36.137 33.264 36.677 35.016 ;
     RECT  36.661 64.896 36.707 67.128 ;
     RECT  36.533 56.112 36.709 56.136 ;
     RECT  36.605 37.008 36.713 39.624 ;
     RECT  36.713 37.008 36.745 38.472 ;
     RECT  36.371 12.528 36.755 32.184 ;
     RECT  36.605 69.504 36.755 74.136 ;
     RECT  35.741 80.16 36.781 80.184 ;
     RECT  36.755 26.208 36.785 32.184 ;
     RECT  36.569 82.176 36.785 83.64 ;
     RECT  36.745 36.48 36.857 38.472 ;
     RECT  36.755 12.528 36.893 25.128 ;
     RECT  36.755 69.504 36.929 72.36 ;
     RECT  36.515 58.128 36.949 58.152 ;
     RECT  36.661 59.184 36.949 59.256 ;
     RECT  36.205 45.024 36.956 47.688 ;
     RECT  36.781 79.776 36.997 80.184 ;
     RECT  36.949 58.128 37.036 59.256 ;
     RECT  36.673 51.936 37.037 54.936 ;
     RECT  35.104 42.72 37.069 42.792 ;
     RECT  36.533 43.92 37.069 43.944 ;
     RECT  36.713 39.504 37.073 39.624 ;
     RECT  36.313 62.736 37.073 62.76 ;
     RECT  36.209 87.696 37.073 87.912 ;
     RECT  36.101 49.488 37.105 50.712 ;
     RECT  37.037 51.936 37.109 53.112 ;
     RECT  37.036 58.128 37.109 58.152 ;
     RECT  36.785 82.176 37.109 82.632 ;
     RECT  37.109 51.936 37.145 51.96 ;
     RECT  36.785 26.208 37.153 29.112 ;
     RECT  36.893 13.584 37.181 25.128 ;
     RECT  37.037 54.576 37.181 54.936 ;
     RECT  36.709 56.112 37.217 57.048 ;
     RECT  36.785 30.384 37.249 32.184 ;
     RECT  36.677 33.264 37.249 33.96 ;
     RECT  37.181 54.912 37.289 54.936 ;
     RECT  36.209 76.848 37.357 77.544 ;
     RECT  37.181 13.584 37.361 25.08 ;
     RECT  36.857 36.48 37.361 38.184 ;
     RECT  36.371 2.064 37.505 11.544 ;
     RECT  37.105 49.44 37.577 50.712 ;
     RECT  37.069 42.72 37.58 43.944 ;
     RECT  36.956 45.024 37.58 47.88 ;
     RECT  37.073 87.696 37.613 87.864 ;
     RECT  37.361 13.584 37.619 21.336 ;
     RECT  37.58 42.72 37.621 47.88 ;
     RECT  37.577 49.44 37.621 50.328 ;
     RECT  37.249 30.384 37.645 33.96 ;
     RECT  36.677 34.992 37.645 35.016 ;
     RECT  37.357 76.128 37.649 77.544 ;
     RECT  37.621 42.72 37.667 50.328 ;
     RECT  37.649 76.128 37.667 76.968 ;
     RECT  37.073 39.504 37.676 39.528 ;
     RECT  37.465 68.784 37.681 68.808 ;
     RECT  37.036 59.184 37.685 59.256 ;
     RECT  37.667 76.464 37.693 76.968 ;
     RECT  37.681 68.4 37.721 68.808 ;
     RECT  36.929 70.176 37.721 72.36 ;
     RECT  37.645 30.384 37.757 35.016 ;
     RECT  37.667 42.72 37.757 47.352 ;
     RECT  37.685 59.232 37.757 59.256 ;
     RECT  37.721 70.176 37.793 70.2 ;
     RECT  37.109 82.608 37.829 82.632 ;
     RECT  37.505 2.208 37.861 11.544 ;
     RECT  36.893 12.528 37.861 12.552 ;
     RECT  37.757 30.384 37.865 34.248 ;
     RECT  37.721 71.184 37.937 72.36 ;
     RECT  36.785 83.616 37.969 83.64 ;
     RECT  37.361 38.16 38.005 38.184 ;
     RECT  37.676 39.456 38.005 39.528 ;
     RECT  36.707 65.136 38.113 67.128 ;
     RECT  37.861 2.208 38.117 12.6 ;
     RECT  38.117 2.304 38.149 12.6 ;
     RECT  37.619 13.584 38.149 16.248 ;
     RECT  37.109 52.944 38.149 53.112 ;
     RECT  36.755 73.44 38.149 74.136 ;
     RECT  37.613 87.84 38.149 87.864 ;
     RECT  37.619 17.616 38.153 21.336 ;
     RECT  36.889 41.568 38.225 41.592 ;
     RECT  37.361 22.752 38.243 25.08 ;
     RECT  38.149 52.944 38.333 53.4 ;
     RECT  37.153 26.208 38.365 28.68 ;
     RECT  37.217 56.112 38.389 56.136 ;
     RECT  37.937 71.28 38.401 72.36 ;
     RECT  38.149 73.44 38.401 74.856 ;
     RECT  38.243 22.752 38.405 24.504 ;
     RECT  38.389 55.248 38.435 56.136 ;
     RECT  38.153 18.144 38.437 21.336 ;
     RECT  38.405 22.752 38.437 24.12 ;
     RECT  38.437 18.144 38.441 24.12 ;
     RECT  37.969 83.616 38.441 84.6 ;
     RECT  38.435 55.248 38.476 55.272 ;
     RECT  36.997 79.776 38.581 80.76 ;
     RECT  37.757 43.92 38.621 44.376 ;
     RECT  37.361 36.48 38.629 37.032 ;
     RECT  38.005 38.16 38.629 39.528 ;
     RECT  38.629 36.48 38.653 39.528 ;
     RECT  37.693 76.464 38.653 76.92 ;
     RECT  38.441 18.144 38.657 22.248 ;
     RECT  37.865 30.384 38.689 34.2 ;
     RECT  38.113 65.136 38.725 67.176 ;
     RECT  37.721 68.4 38.725 68.424 ;
     RECT  38.441 83.616 38.725 84.36 ;
     RECT  38.657 19.968 38.771 22.248 ;
     RECT  38.365 25.632 38.797 28.68 ;
     RECT  38.689 29.952 38.797 34.2 ;
     RECT  37.757 42.72 38.797 42.744 ;
     RECT  38.333 53.088 38.797 53.4 ;
     RECT  37.757 45.36 38.837 47.352 ;
     RECT  38.725 82.896 38.837 84.36 ;
     RECT  38.401 71.28 38.879 74.856 ;
     RECT  38.581 79.776 38.981 81.48 ;
     RECT  38.797 25.632 39.013 34.2 ;
     RECT  38.797 42.72 39.013 42.84 ;
     RECT  38.879 71.28 39.049 75.144 ;
     RECT  38.965 51.6 39.052 51.624 ;
     RECT  39.013 25.632 39.059 34.248 ;
     RECT  39.013 42.144 39.059 42.84 ;
     RECT  39.049 70.848 39.059 75.144 ;
     RECT  38.653 76.368 39.059 76.92 ;
     RECT  39.059 70.848 39.061 75.096 ;
     RECT  38.725 65.136 39.157 68.424 ;
     RECT  38.657 18.144 39.193 18.984 ;
     RECT  38.149 2.304 39.26 16.248 ;
     RECT  39.26 2.256 39.265 16.248 ;
     RECT  39.059 30.768 39.265 34.248 ;
     RECT  38.653 36.48 39.265 40.488 ;
     RECT  39.265 2.256 39.337 16.584 ;
     RECT  39.059 25.632 39.409 29.256 ;
     RECT  39.337 2.256 39.589 16.632 ;
     RECT  39.193 17.616 39.589 18.984 ;
     RECT  39.265 36.048 39.733 40.488 ;
     RECT  39.061 70.416 39.805 75.096 ;
     RECT  39.265 30.768 39.841 34.68 ;
     RECT  39.733 36.048 39.841 41.064 ;
     RECT  39.841 30.768 39.877 41.064 ;
     RECT  39.059 42.144 39.877 42.744 ;
     RECT  38.837 46.608 39.877 47.352 ;
     RECT  37.667 48.384 39.877 50.328 ;
     RECT  39.877 46.608 39.913 50.328 ;
     RECT  39.913 46.608 40.057 50.952 ;
     RECT  39.805 70.368 40.057 75.096 ;
     RECT  39.059 76.368 40.057 76.392 ;
     RECT  40.057 70.368 40.129 76.392 ;
     RECT  38.797 53.088 40.165 54.072 ;
     RECT  39.589 2.256 40.208 18.984 ;
     RECT  38.771 19.968 40.208 21.96 ;
     RECT  38.441 23.328 40.208 24.12 ;
     RECT  39.409 25.248 40.208 29.256 ;
     RECT  39.877 30.768 40.208 42.744 ;
     RECT  38.621 43.92 40.208 43.944 ;
     RECT  38.837 45.36 40.208 45.384 ;
     RECT  40.057 46.608 40.208 51.384 ;
     RECT  40.165 52.8 40.208 54.072 ;
     RECT  39.589 58.656 40.208 58.68 ;
     RECT  38.761 63.168 40.208 63.192 ;
     RECT  39.157 65.136 40.208 68.952 ;
     RECT  40.129 70.368 40.208 77.064 ;
     RECT  38.761 78.624 40.208 78.648 ;
     RECT  38.981 79.824 40.208 81.48 ;
     RECT  38.837 83.616 40.208 84.36 ;
     RECT  39.877 86.304 40.208 86.328 ;
     RECT  38.149 87.84 40.208 88.104 ;
     RECT  40.208 2.148 40.312 88.572 ;
     RECT  40.312 2.418 40.504 88.302 ;
     RECT  40.504 77.04 40.529 77.064 ;
     RECT  40.504 41.76 40.673 44.664 ;
     RECT  40.504 65.136 40.681 74.136 ;
     RECT  40.504 87.84 40.709 88.104 ;
     RECT  40.504 20.976 40.739 21 ;
     RECT  40.504 75.12 40.781 75.72 ;
     RECT  40.504 2.832 40.825 16.008 ;
     RECT  40.504 50.016 40.889 51.384 ;
     RECT  40.504 22.56 40.925 23.928 ;
     RECT  40.504 86.304 40.925 86.328 ;
     RECT  40.504 61.44 40.997 62.04 ;
     RECT  40.504 78.912 41.027 84.456 ;
     RECT  40.504 17.088 41.033 18.84 ;
     RECT  40.925 23.328 41.069 23.928 ;
     RECT  40.504 30.864 41.069 39.912 ;
     RECT  41.027 78.912 41.069 82.344 ;
     RECT  40.504 56.544 41.249 56.568 ;
     RECT  41.069 37.008 41.357 37.032 ;
     RECT  40.889 50.112 41.357 51.384 ;
     RECT  40.504 46.32 41.401 49.032 ;
     RECT  41.069 23.904 41.429 23.928 ;
     RECT  41.357 51.36 41.429 51.384 ;
     RECT  40.681 69.312 41.429 74.136 ;
     RECT  40.781 75.12 41.465 75.576 ;
     RECT  40.673 41.76 41.533 44.232 ;
     RECT  41.069 78.912 41.537 82.056 ;
     RECT  40.504 25.92 41.569 25.944 ;
     RECT  40.504 27.12 41.569 29.544 ;
     RECT  41.533 40.992 41.573 44.232 ;
     RECT  41.465 75.216 41.573 75.576 ;
     RECT  40.825 2.88 41.605 16.008 ;
     RECT  41.033 17.088 41.605 18.696 ;
     RECT  41.401 46.32 41.609 48.552 ;
     RECT  41.357 50.112 41.609 50.28 ;
     RECT  41.569 25.92 41.677 29.544 ;
     RECT  41.605 2.88 41.681 18.696 ;
     RECT  41.069 38.256 41.789 39.912 ;
     RECT  41.573 44.016 41.821 44.232 ;
     RECT  41.537 78.912 41.821 78.936 ;
     RECT  40.504 52.8 41.965 53.112 ;
     RECT  41.605 86.64 41.965 86.664 ;
     RECT  41.429 70.128 41.969 74.136 ;
     RECT  41.681 2.88 41.996 6.936 ;
     RECT  41.789 38.256 42.037 39.864 ;
     RECT  41.677 25.056 42.077 29.544 ;
     RECT  41.069 30.864 42.077 35.736 ;
     RECT  42.077 26.736 42.131 29.544 ;
     RECT  41.965 52.224 42.14 53.112 ;
     RECT  41.681 7.92 42.185 18.696 ;
     RECT  42.185 15.84 42.217 18.696 ;
     RECT  42.14 52.224 42.227 53.592 ;
     RECT  42.037 38.112 42.253 39.864 ;
     RECT  41.537 80.4 42.257 82.056 ;
     RECT  41.749 58.128 42.329 58.152 ;
     RECT  42.131 26.784 42.365 29.544 ;
     RECT  42.365 28.032 42.397 29.544 ;
     RECT  42.077 30.864 42.397 34.2 ;
     RECT  41.609 50.112 42.397 50.136 ;
     RECT  42.145 59.52 42.433 59.544 ;
     RECT  42.253 37.392 42.467 39.864 ;
     RECT  40.681 65.136 42.469 67.416 ;
     RECT  42.077 35.568 42.505 35.736 ;
     RECT  41.609 46.512 42.541 48.552 ;
     RECT  42.145 76.8 42.541 76.824 ;
     RECT  42.541 76.464 42.545 76.824 ;
     RECT  42.397 28.032 42.581 34.2 ;
     RECT  41.965 85.776 42.581 86.664 ;
     RECT  41.573 40.992 42.613 42.552 ;
     RECT  42.361 20.064 42.617 20.088 ;
     RECT  41.996 2.736 42.649 6.936 ;
     RECT  42.185 7.92 42.649 14.856 ;
     RECT  42.541 46.512 42.685 48.744 ;
     RECT  42.397 49.776 42.685 50.136 ;
     RECT  42.365 26.784 42.689 26.808 ;
     RECT  42.649 2.736 42.709 14.856 ;
     RECT  42.581 86.4 42.721 86.664 ;
     RECT  42.361 21.168 42.725 21.192 ;
     RECT  41.497 56.064 42.725 56.088 ;
     RECT  42.541 57.12 42.725 57.144 ;
     RECT  42.685 46.512 42.757 50.136 ;
     RECT  41.713 62.736 42.757 62.76 ;
     RECT  41.027 83.376 42.757 84.456 ;
     RECT  42.721 86.4 42.757 86.904 ;
     RECT  40.709 88.08 42.757 88.104 ;
     RECT  42.757 82.464 42.793 84.456 ;
     RECT  42.433 58.416 42.797 59.544 ;
     RECT  41.821 78.72 42.829 78.936 ;
     RECT  42.793 82.464 42.829 84.552 ;
     RECT  42.217 15.84 42.833 18.792 ;
     RECT  42.227 52.224 42.865 53.112 ;
     RECT  42.757 62.448 42.869 62.76 ;
     RECT  41.969 70.656 42.869 74.136 ;
     RECT  42.797 58.416 42.905 58.872 ;
     RECT  42.829 78.72 42.937 79.08 ;
     RECT  42.709 2.256 42.977 14.856 ;
     RECT  42.829 82.464 42.977 85.176 ;
     RECT  42.869 62.448 43.009 62.616 ;
     RECT  42.757 46.416 43.013 50.136 ;
     RECT  42.937 78.672 43.045 79.08 ;
     RECT  42.467 37.968 43.081 39.864 ;
     RECT  42.613 40.848 43.081 42.552 ;
     RECT  42.581 28.032 43.157 29.544 ;
     RECT  43.009 61.488 43.157 62.616 ;
     RECT  42.145 63.792 43.157 63.816 ;
     RECT  42.545 76.464 43.157 76.488 ;
     RECT  43.013 46.464 43.229 50.136 ;
     RECT  42.869 70.656 43.229 71.928 ;
     RECT  43.045 78.672 43.261 79.224 ;
     RECT  42.977 82.464 43.265 84.552 ;
     RECT  42.977 2.88 43.292 14.856 ;
     RECT  42.833 15.84 43.292 18.696 ;
     RECT  43.261 78.144 43.297 79.224 ;
     RECT  42.505 35.568 43.333 36.504 ;
     RECT  42.257 80.4 43.333 81.192 ;
     RECT  43.229 70.896 43.337 71.928 ;
     RECT  43.265 82.464 43.373 83.64 ;
     RECT  43.292 2.88 43.379 18.696 ;
     RECT  43.333 35.472 43.42 36.504 ;
     RECT  42.469 65.136 43.441 67.848 ;
     RECT  42.077 25.056 43.445 25.08 ;
     RECT  41.573 75.216 43.481 75.24 ;
     RECT  43.333 80.4 43.517 81.432 ;
     RECT  41.821 44.016 43.549 44.904 ;
     RECT  43.081 37.968 43.553 42.552 ;
     RECT  42.581 30.672 43.621 34.2 ;
     RECT  43.42 35.472 43.621 35.832 ;
     RECT  43.553 42.048 43.621 42.552 ;
     RECT  43.549 44.016 43.621 45.48 ;
     RECT  43.553 37.968 43.625 40.872 ;
     RECT  43.621 42.048 43.733 45.48 ;
     RECT  43.621 30.672 43.765 35.832 ;
     RECT  43.229 47.712 43.765 50.136 ;
     RECT  42.865 51.264 43.765 53.112 ;
     RECT  42.757 86.4 43.769 88.104 ;
     RECT  43.297 77.568 43.801 79.224 ;
     RECT  43.517 80.4 43.801 81.192 ;
     RECT  43.801 77.568 43.805 81.192 ;
     RECT  43.769 86.4 43.805 86.664 ;
     RECT  42.905 58.704 43.841 58.872 ;
     RECT  43.625 38.448 43.877 40.872 ;
     RECT  43.805 86.4 43.877 86.616 ;
     RECT  43.379 15.936 43.909 18.696 ;
     RECT  43.157 62.352 43.913 62.616 ;
     RECT  43.765 47.712 43.945 53.112 ;
     RECT  42.869 72.96 43.945 73.896 ;
     RECT  43.805 77.568 43.949 77.64 ;
     RECT  43.837 56.112 43.985 56.136 ;
     RECT  43.405 20.112 44.089 20.136 ;
     RECT  43.841 58.8 44.093 58.872 ;
     RECT  43.441 65.136 44.093 68.808 ;
     RECT  43.805 78.672 44.093 81.192 ;
     RECT  43.733 43.248 44.129 45.48 ;
     RECT  43.945 47.712 44.129 53.496 ;
     RECT  44.093 78.672 44.129 80.904 ;
     RECT  43.373 82.656 44.129 83.64 ;
     RECT  44.129 52.224 44.197 53.496 ;
     RECT  44.089 20.112 44.269 20.376 ;
     RECT  44.129 47.712 44.281 50.856 ;
     RECT  43.157 28.416 44.305 28.776 ;
     RECT  43.765 30.048 44.305 35.832 ;
     RECT  43.229 46.464 44.341 46.536 ;
     RECT  44.281 47.712 44.341 47.928 ;
     RECT  43.379 2.88 44.377 14.856 ;
     RECT  44.093 58.848 44.417 58.872 ;
     RECT  43.337 70.896 44.417 71.496 ;
     RECT  43.877 86.592 44.453 86.616 ;
     RECT  44.093 65.136 44.489 66.552 ;
     RECT  43.945 72.864 44.489 73.896 ;
     RECT  44.305 27.36 44.521 27.384 ;
     RECT  44.305 28.368 44.521 35.832 ;
     RECT  44.129 82.8 44.525 83.64 ;
     RECT  44.093 67.776 44.561 68.808 ;
     RECT  44.129 78.768 44.633 80.904 ;
     RECT  43.233 69.84 44.701 69.864 ;
     RECT  44.521 27.36 44.737 35.832 ;
     RECT  44.557 36.864 44.737 36.888 ;
     RECT  43.877 38.448 44.737 40.344 ;
     RECT  44.489 72.864 44.737 73.848 ;
     RECT  44.737 38.016 44.845 40.344 ;
     RECT  43.949 77.616 44.917 77.64 ;
     RECT  43.733 42.048 44.953 42.072 ;
     RECT  44.945 85.488 44.965 85.512 ;
     RECT  44.701 69.504 44.989 69.864 ;
     RECT  44.417 70.896 44.989 71.208 ;
     RECT  44.917 77.472 45.133 77.64 ;
     RECT  44.845 38.016 45.169 40.392 ;
     RECT  43.913 62.592 45.169 62.616 ;
     RECT  44.129 45.456 45.205 45.48 ;
     RECT  44.341 46.464 45.205 47.928 ;
     RECT  44.269 20.064 45.277 20.376 ;
     RECT  43.769 88.08 45.349 88.104 ;
     RECT  44.737 27.36 45.385 36.888 ;
     RECT  44.881 75.984 45.385 76.008 ;
     RECT  45.169 38.016 45.457 40.44 ;
     RECT  44.953 41.472 45.457 42.072 ;
     RECT  44.561 67.776 45.457 68.232 ;
     RECT  44.737 72.192 45.457 73.848 ;
     RECT  44.989 69.504 45.529 71.208 ;
     RECT  44.281 49.008 45.601 50.856 ;
     RECT  44.197 52.224 45.601 53.592 ;
     RECT  44.377 2.592 45.608 14.856 ;
     RECT  43.909 15.936 45.608 18.84 ;
     RECT  45.277 20.064 45.608 20.424 ;
     RECT  45.385 27.36 45.608 36.936 ;
     RECT  45.457 38.016 45.608 42.072 ;
     RECT  44.129 43.248 45.608 44.472 ;
     RECT  45.205 45.456 45.608 47.928 ;
     RECT  45.601 49.008 45.608 53.592 ;
     RECT  42.181 54.672 45.608 54.696 ;
     RECT  43.729 57.12 45.608 57.144 ;
     RECT  44.989 59.04 45.608 59.064 ;
     RECT  44.917 61.008 45.608 61.032 ;
     RECT  45.169 62.448 45.608 62.664 ;
     RECT  44.489 66 45.608 66.552 ;
     RECT  45.457 67.632 45.608 68.232 ;
     RECT  45.529 69.456 45.608 71.208 ;
     RECT  45.457 72.192 45.608 74.136 ;
     RECT  45.385 75.696 45.608 76.008 ;
     RECT  45.133 77.472 45.608 77.688 ;
     RECT  44.633 78.912 45.608 80.904 ;
     RECT  44.525 83.616 45.608 83.64 ;
     RECT  44.965 84.912 45.608 85.512 ;
     RECT  44.773 86.736 45.608 87.096 ;
     RECT  45.349 88.08 45.608 88.2 ;
     RECT  45.608 2.148 45.712 88.572 ;
     RECT  45.712 2.256 45.904 88.302 ;
     RECT  45.904 20.016 45.929 20.424 ;
     RECT  45.904 41.184 45.929 53.112 ;
     RECT  45.904 21.936 46.001 23.592 ;
     RECT  45.904 16.224 46.037 18.84 ;
     RECT  45.904 66 46.163 66.312 ;
     RECT  45.929 41.376 46.181 53.112 ;
     RECT  45.904 77.376 46.181 81 ;
     RECT  46.181 41.376 46.217 52.728 ;
     RECT  45.904 38.16 46.253 39.816 ;
     RECT  45.904 29.856 46.289 37.08 ;
     RECT  45.904 70.608 46.289 71.4 ;
     RECT  46.181 77.376 46.289 78.648 ;
     RECT  46.001 21.936 46.325 21.96 ;
     RECT  45.904 13.584 46.397 15.24 ;
     RECT  46.217 43.296 46.397 52.728 ;
     RECT  46.397 43.344 46.499 52.728 ;
     RECT  45.904 2.256 46.513 12.552 ;
     RECT  46.513 2.256 46.649 9.336 ;
     RECT  46.001 23.184 46.649 23.592 ;
     RECT  46.649 23.184 46.685 23.304 ;
     RECT  46.499 43.344 46.721 52.104 ;
     RECT  46.685 23.184 46.757 23.208 ;
     RECT  45.904 82.608 46.787 84.84 ;
     RECT  46.217 41.376 46.793 42.312 ;
     RECT  46.793 41.376 46.829 42.264 ;
     RECT  46.037 16.224 46.865 18.792 ;
     RECT  45.904 67.632 46.865 69.528 ;
     RECT  46.721 43.344 46.937 46.92 ;
     RECT  45.904 73.008 46.937 74.136 ;
     RECT  46.181 79.728 46.969 81 ;
     RECT  46.865 16.512 46.973 18.792 ;
     RECT  46.721 48.432 46.973 52.104 ;
     RECT  46.787 82.608 46.973 82.632 ;
     RECT  46.513 10.752 46.979 12.552 ;
     RECT  46.649 2.256 47.009 8.76 ;
     RECT  46.937 44.16 47.009 46.92 ;
     RECT  46.397 13.968 47.045 15.24 ;
     RECT  45.904 27.024 47.077 28.728 ;
     RECT  46.289 30.336 47.077 37.08 ;
     RECT  46.253 38.16 47.077 39.576 ;
     RECT  45.904 56.256 47.077 57.576 ;
     RECT  46.289 77.376 47.077 78.072 ;
     RECT  46.787 83.616 47.077 84.84 ;
     RECT  46.969 79.728 47.081 81.336 ;
     RECT  47.045 14.64 47.113 15.24 ;
     RECT  45.904 62.448 47.113 62.568 ;
     RECT  47.077 83.616 47.113 84.936 ;
     RECT  45.904 86.16 47.16 87 ;
     RECT  45.904 88.08 47.16 88.104 ;
     RECT  47.077 30.336 47.161 39.576 ;
     RECT  46.973 48.432 47.171 50.856 ;
     RECT  47.113 62.16 47.185 62.616 ;
     RECT  47.113 83.616 47.267 85.176 ;
     RECT  47.16 86.16 47.267 88.104 ;
     RECT  45.904 54.672 47.293 54.696 ;
     RECT  47.161 30.336 47.315 36.84 ;
     RECT  47.077 76.944 47.329 78.072 ;
     RECT  46.979 11.136 47.363 12.552 ;
     RECT  45.929 20.16 47.365 20.424 ;
     RECT  47.293 54.096 47.365 54.696 ;
     RECT  47.077 55.872 47.365 57.576 ;
     RECT  47.185 61.2 47.365 62.616 ;
     RECT  46.163 66.192 47.365 66.312 ;
     RECT  46.865 67.632 47.365 68.376 ;
     RECT  46.865 69.408 47.401 69.528 ;
     RECT  47.365 19.824 47.405 20.424 ;
     RECT  47.171 48.432 47.405 49.56 ;
     RECT  47.365 54.096 47.405 57.576 ;
     RECT  46.973 18.72 47.411 18.792 ;
     RECT  47.077 26.832 47.411 28.728 ;
     RECT  47.405 54.096 47.411 56.088 ;
     RECT  47.411 54.096 47.452 55.08 ;
     RECT  47.267 87.216 47.473 88.104 ;
     RECT  47.009 2.592 47.477 8.76 ;
     RECT  47.365 61.2 47.477 62.712 ;
     RECT  47.315 30.336 47.513 35.496 ;
     RECT  46.289 70.896 47.513 71.4 ;
     RECT  47.267 83.616 47.513 84.936 ;
     RECT  47.363 11.136 47.549 11.832 ;
     RECT  47.411 26.832 47.549 28.44 ;
     RECT  47.401 69.408 47.581 69.768 ;
     RECT  47.513 70.896 47.581 70.92 ;
     RECT  47.473 87.216 47.617 88.152 ;
     RECT  47.081 80.88 47.621 81.336 ;
     RECT  47.653 64.08 47.689 64.104 ;
     RECT  47.405 57.216 47.693 57.576 ;
     RECT  47.513 30.336 47.699 34.728 ;
     RECT  47.161 37.968 47.725 39.576 ;
     RECT  47.699 30.336 47.761 32.472 ;
     RECT  47.405 48.432 47.761 48.456 ;
     RECT  47.329 76.944 47.797 78.696 ;
     RECT  47.549 26.88 47.801 28.44 ;
     RECT  47.477 61.2 47.801 62.616 ;
     RECT  46.973 52.08 47.833 52.104 ;
     RECT  47.513 83.616 47.837 84.888 ;
     RECT  47.797 76.656 47.869 78.696 ;
     RECT  47.257 79.68 47.869 79.704 ;
     RECT  47.581 69.408 47.873 70.92 ;
     RECT  47.452 54.096 47.891 54.744 ;
     RECT  46.937 73.296 47.891 74.136 ;
     RECT  46.973 16.512 47.909 17.688 ;
     RECT  47.833 22.224 47.917 22.248 ;
     RECT  47.873 69.504 47.939 70.92 ;
     RECT  47.477 2.592 47.945 8.616 ;
     RECT  47.405 49.536 47.945 49.56 ;
     RECT  47.869 76.656 47.945 79.704 ;
     RECT  47.113 14.64 47.977 15.48 ;
     RECT  47.909 16.512 47.977 17.64 ;
     RECT  47.725 37.968 47.977 39.912 ;
     RECT  47.437 75.36 47.977 75.384 ;
     RECT  47.171 50.736 48.017 50.856 ;
     RECT  47.945 76.656 48.049 77.688 ;
     RECT  47.977 14.64 48.121 17.64 ;
     RECT  47.405 19.824 48.125 20.328 ;
     RECT  48.121 13.776 48.229 17.64 ;
     RECT  47.315 36.816 48.229 36.84 ;
     RECT  47.977 37.968 48.229 40.632 ;
     RECT  47.689 64.08 48.233 64.392 ;
     RECT  47.761 47.664 48.269 48.456 ;
     RECT  48.229 36.816 48.301 40.632 ;
     RECT  46.829 42.24 48.301 42.264 ;
     RECT  47.617 87.216 48.301 88.248 ;
     RECT  48.125 20.304 48.305 20.328 ;
     RECT  48.049 76.464 48.377 77.688 ;
     RECT  48.301 87.216 48.377 88.344 ;
     RECT  47.761 29.472 48.413 32.472 ;
     RECT  47.977 60.432 48.413 60.84 ;
     RECT  47.411 56.064 48.449 56.088 ;
     RECT  48.229 72.048 48.449 72.072 ;
     RECT  47.837 84.624 48.476 84.888 ;
     RECT  48.337 85.968 48.476 85.992 ;
     RECT  47.945 79.008 48.481 79.704 ;
     RECT  47.621 80.88 48.481 81 ;
     RECT  47.837 83.616 48.481 83.64 ;
     RECT  48.229 13.536 48.485 17.64 ;
     RECT  48.301 36.192 48.517 42.264 ;
     RECT  47.549 11.376 48.557 11.832 ;
     RECT  48.485 13.536 48.557 13.656 ;
     RECT  48.413 60.816 48.563 60.84 ;
     RECT  48.517 56.4 48.601 56.424 ;
     RECT  47.891 54.576 48.625 54.744 ;
     RECT  48.481 83.376 48.625 83.64 ;
     RECT  48.517 36.144 48.697 42.264 ;
     RECT  48.557 11.376 48.709 11.688 ;
     RECT  47.801 26.88 48.733 27.672 ;
     RECT  47.009 44.16 48.733 46.632 ;
     RECT  48.709 11.136 48.755 11.688 ;
     RECT  47.801 62.4 48.769 62.616 ;
     RECT  47.939 69.744 48.773 70.92 ;
     RECT  48.233 64.368 48.841 64.392 ;
     RECT  48.733 44.16 48.881 46.728 ;
     RECT  48.269 47.712 48.881 48.456 ;
     RECT  48.769 62.4 48.881 62.808 ;
     RECT  48.476 84.624 48.881 85.992 ;
     RECT  48.377 87.888 48.881 88.344 ;
     RECT  47.699 33.552 48.913 34.728 ;
     RECT  48.697 35.952 48.913 42.264 ;
     RECT  48.913 35.952 48.949 42.456 ;
     RECT  48.773 70.512 48.949 70.92 ;
     RECT  48.377 76.464 48.953 77.112 ;
     RECT  47.977 75.216 49.043 75.384 ;
     RECT  48.953 76.464 49.057 76.68 ;
     RECT  48.733 26.832 49.061 27.672 ;
     RECT  47.891 73.296 49.061 74.088 ;
     RECT  48.913 33.552 49.093 34.92 ;
     RECT  49.061 26.88 49.133 27.672 ;
     RECT  47.725 57.6 49.165 58.056 ;
     RECT  49.165 57.6 49.169 58.152 ;
     RECT  48.481 79.008 49.201 81 ;
     RECT  48.881 47.712 49.205 48.264 ;
     RECT  47.945 2.592 49.273 8.52 ;
     RECT  49.093 33.552 49.273 34.968 ;
     RECT  48.949 35.952 49.273 42.552 ;
     RECT  48.841 64.368 49.313 64.44 ;
     RECT  48.625 54.576 49.349 55.272 ;
     RECT  48.413 32.304 49.381 32.472 ;
     RECT  49.273 33.552 49.381 42.552 ;
     RECT  49.061 73.392 49.421 74.088 ;
     RECT  48.413 29.472 49.453 31.32 ;
     RECT  49.381 32.304 49.453 42.552 ;
     RECT  48.949 70.512 49.453 71.784 ;
     RECT  49.201 79.008 49.457 81.48 ;
     RECT  49.453 29.472 49.493 42.552 ;
     RECT  49.493 34.944 49.529 42.552 ;
     RECT  48.755 11.136 49.561 11.16 ;
     RECT  48.881 88.08 49.565 88.344 ;
     RECT  49.493 29.472 49.571 33.912 ;
     RECT  49.453 70.512 49.573 71.832 ;
     RECT  47.365 66.192 49.597 68.376 ;
     RECT  48.881 45.792 49.601 46.728 ;
     RECT  47.833 52.08 49.601 53.016 ;
     RECT  49.313 64.416 49.628 64.44 ;
     RECT  49.597 66.192 49.628 69.288 ;
     RECT  48.881 84.864 49.633 85.992 ;
     RECT  49.529 35.184 49.637 42.552 ;
     RECT  48.017 50.736 49.669 50.76 ;
     RECT  49.457 79.152 49.669 81.48 ;
     RECT  48.625 82.992 49.669 83.64 ;
     RECT  49.637 35.184 49.673 42.456 ;
     RECT  49.673 36.192 49.709 36.888 ;
     RECT  49.628 64.416 49.709 69.288 ;
     RECT  49.565 88.08 49.709 88.152 ;
     RECT  49.709 64.416 49.715 68.952 ;
     RECT  49.273 2.496 49.717 8.52 ;
     RECT  49.669 50.112 49.745 50.76 ;
     RECT  49.417 57.12 49.765 57.144 ;
     RECT  49.561 10.848 49.777 11.16 ;
     RECT  49.715 66.192 49.781 68.952 ;
     RECT  49.633 84.864 49.781 86.76 ;
     RECT  49.745 50.112 49.849 50.184 ;
     RECT  49.781 85.2 49.849 86.76 ;
     RECT  49.717 2.256 49.853 8.52 ;
     RECT  48.881 62.544 49.853 62.808 ;
     RECT  49.573 70.512 49.853 72.408 ;
     RECT  49.853 62.544 49.885 62.664 ;
     RECT  49.057 75.696 49.961 76.68 ;
     RECT  49.961 76.464 50.06 76.68 ;
     RECT  48.557 13.632 50.101 13.656 ;
     RECT  49.205 48.144 50.101 48.264 ;
     RECT  49.849 49.536 50.101 50.184 ;
     RECT  49.601 52.944 50.101 53.016 ;
     RECT  49.349 54.576 50.101 54.6 ;
     RECT  49.849 85.2 50.101 86.856 ;
     RECT  49.709 88.08 50.101 88.104 ;
     RECT  49.777 10.272 50.137 11.16 ;
     RECT  49.705 60.384 50.137 60.408 ;
     RECT  49.669 79.152 50.173 83.64 ;
     RECT  50.06 76.464 50.197 77.592 ;
     RECT  49.853 2.544 50.281 8.52 ;
     RECT  48.881 44.16 50.317 44.76 ;
     RECT  50.317 24.336 50.425 24.36 ;
     RECT  49.765 57.024 50.425 57.144 ;
     RECT  49.169 58.128 50.425 58.152 ;
     RECT  50.137 60 50.425 60.408 ;
     RECT  50.425 24.192 50.497 24.36 ;
     RECT  49.571 33.888 50.533 33.912 ;
     RECT  49.673 35.184 50.533 35.208 ;
     RECT  50.281 2.544 50.569 9 ;
     RECT  50.137 10.032 50.569 11.16 ;
     RECT  49.601 45.792 50.569 46.68 ;
     RECT  50.101 48.144 50.569 50.184 ;
     RECT  50.101 13.056 50.641 13.656 ;
     RECT  50.533 33.888 50.641 35.208 ;
     RECT  50.641 25.824 50.677 25.848 ;
     RECT  49.133 27.168 50.677 27.672 ;
     RECT  49.781 67.488 50.677 68.952 ;
     RECT  50.101 52.944 50.713 54.6 ;
     RECT  49.421 74.064 50.713 74.088 ;
     RECT  49.781 66.192 50.749 66.312 ;
     RECT  50.677 67.488 50.749 69.336 ;
     RECT  47.411 18.72 50.785 18.744 ;
     RECT  49.561 19.872 50.785 19.896 ;
     RECT  49.709 36.816 50.785 36.888 ;
     RECT  49.673 38.16 50.785 42.36 ;
     RECT  50.197 76.464 50.785 78.072 ;
     RECT  50.173 79.152 50.785 84.072 ;
     RECT  50.101 85.2 50.785 88.104 ;
     RECT  50.569 45.792 50.869 50.184 ;
     RECT  50.317 51.408 50.869 51.432 ;
     RECT  50.713 52.944 50.869 54.696 ;
     RECT  50.869 52.464 51.001 54.696 ;
     RECT  50.137 55.68 51.001 55.704 ;
     RECT  50.569 2.544 51.008 11.16 ;
     RECT  50.641 12.528 51.008 13.656 ;
     RECT  48.485 14.64 51.008 17.64 ;
     RECT  50.785 18.72 51.008 19.896 ;
     RECT  50.497 23.664 51.008 24.36 ;
     RECT  50.677 25.824 51.008 27.912 ;
     RECT  49.571 29.472 51.008 32.472 ;
     RECT  50.641 33.888 51.008 35.256 ;
     RECT  50.785 36.816 51.008 42.36 ;
     RECT  50.317 43.872 51.008 44.76 ;
     RECT  50.869 45.792 51.008 51.432 ;
     RECT  51.001 52.464 51.008 55.704 ;
     RECT  50.425 57.024 51.008 58.152 ;
     RECT  50.425 59.28 51.008 60.408 ;
     RECT  49.885 62.064 51.008 62.664 ;
     RECT  49.715 64.416 51.008 64.44 ;
     RECT  50.749 66.192 51.008 69.336 ;
     RECT  49.853 70.512 51.008 72.024 ;
     RECT  50.713 73.296 51.008 74.088 ;
     RECT  50.785 76.464 51.008 88.104 ;
     RECT  51.008 2.148 51.112 88.572 ;
     RECT  51.112 2.418 51.304 88.302 ;
     RECT  51.304 45.792 51.329 49.512 ;
     RECT  51.304 33.984 51.365 35.016 ;
     RECT  51.329 45.792 51.401 49.32 ;
     RECT  51.304 25.824 51.437 27.672 ;
     RECT  51.401 46.224 51.509 49.32 ;
     RECT  51.304 36 51.617 37.128 ;
     RECT  51.304 74.064 51.617 74.088 ;
     RECT  51.304 78.432 51.689 88.104 ;
     RECT  51.304 12 51.725 13.128 ;
     RECT  51.365 33.984 51.761 34.92 ;
     RECT  51.304 14.352 51.779 17.64 ;
     RECT  51.304 9.696 51.797 10.728 ;
     RECT  51.304 21.12 51.833 21.144 ;
     RECT  51.304 29.616 51.833 31.464 ;
     RECT  51.689 80.544 51.905 88.104 ;
     RECT  51.304 44.064 51.923 44.664 ;
     RECT  51.833 30.048 51.941 31.464 ;
     RECT  51.689 78.432 52.013 79.56 ;
     RECT  51.905 80.544 52.013 84.168 ;
     RECT  51.304 58.704 52.157 58.728 ;
     RECT  51.304 70.608 52.157 72.024 ;
     RECT  52.013 80.544 52.229 83.784 ;
     RECT  51.797 9.696 52.265 10.536 ;
     RECT  52.157 70.608 52.301 71.112 ;
     RECT  51.304 38.16 52.333 42.792 ;
     RECT  52.333 38.16 52.337 43.128 ;
     RECT  51.304 54.672 52.369 55.512 ;
     RECT  51.304 57.024 52.369 57.096 ;
     RECT  51.725 12 52.373 12.024 ;
     RECT  51.304 68.16 52.405 69.336 ;
     RECT  52.301 70.608 52.405 70.968 ;
     RECT  51.725 13.104 52.441 13.128 ;
     RECT  51.761 33.984 52.445 34.008 ;
     RECT  51.905 85.248 52.445 88.104 ;
     RECT  51.509 46.224 52.477 49.08 ;
     RECT  51.923 44.16 52.501 44.664 ;
     RECT  52.477 46.224 52.501 49.464 ;
     RECT  52.501 44.16 52.588 49.464 ;
     RECT  51.941 30.048 52.595 31.416 ;
     RECT  52.337 42.768 52.597 43.128 ;
     RECT  51.304 50.928 52.657 50.952 ;
     RECT  52.595 30.288 52.661 31.416 ;
     RECT  52.369 54.672 52.661 57.096 ;
     RECT  51.437 26.352 52.693 27.672 ;
     RECT  52.661 55.2 52.693 57.096 ;
     RECT  52.229 81.216 52.697 83.784 ;
     RECT  51.304 32.448 52.729 32.472 ;
     RECT  51.304 65.712 52.733 66.696 ;
     RECT  51.779 17.616 52.739 17.64 ;
     RECT  51.304 52.464 52.789 52.488 ;
     RECT  52.733 66.288 52.801 66.696 ;
     RECT  52.441 13.104 52.805 13.32 ;
     RECT  51.617 36.816 52.805 37.128 ;
     RECT  52.693 55.2 52.805 57.336 ;
     RECT  52.729 32.448 52.813 32.52 ;
     RECT  52.657 50.688 52.835 50.952 ;
     RECT  52.789 52.176 52.877 52.488 ;
     RECT  52.265 9.936 52.883 10.536 ;
     RECT  52.693 26.352 52.909 28.44 ;
     RECT  52.883 10.272 52.933 10.536 ;
     RECT  52.445 85.248 52.949 87.096 ;
     RECT  52.933 10.272 52.979 11.688 ;
     RECT  51.779 14.352 52.981 16.536 ;
     RECT  51.304 18.72 52.981 19.992 ;
     RECT  52.588 47.232 52.981 49.464 ;
     RECT  52.835 50.688 52.981 50.712 ;
     RECT  51.304 2.496 53.027 8.52 ;
     RECT  52.979 10.272 53.057 10.296 ;
     RECT  52.981 14.16 53.093 16.536 ;
     RECT  53.027 2.496 53.129 7.992 ;
     RECT  52.588 46.224 53.129 46.248 ;
     RECT  52.981 47.232 53.201 50.712 ;
     RECT  52.801 66.288 53.201 66.792 ;
     RECT  52.909 26.304 53.233 28.44 ;
     RECT  52.981 18.72 53.269 20.424 ;
     RECT  53.125 21.6 53.269 21.624 ;
     RECT  52.013 78.432 53.305 79.272 ;
     RECT  52.597 43.104 53.309 43.128 ;
     RECT  51.304 61.536 53.309 62.376 ;
     RECT  52.405 68.16 53.324 70.968 ;
     RECT  53.125 23.328 53.341 23.352 ;
     RECT  53.093 14.16 53.345 16.488 ;
     RECT  53.341 23.328 53.377 23.832 ;
     RECT  53.345 14.352 53.381 16.488 ;
     RECT  52.873 34.08 53.381 34.104 ;
     RECT  51.304 76.08 53.381 76.104 ;
     RECT  53.324 68.16 53.411 71.064 ;
     RECT  53.377 23.328 53.413 24.12 ;
     RECT  53.233 25.344 53.413 28.44 ;
     RECT  53.413 23.328 53.485 28.44 ;
     RECT  52.805 55.488 53.489 57.336 ;
     RECT  53.485 23.28 53.521 28.44 ;
     RECT  53.201 47.232 53.525 49.848 ;
     RECT  52.805 13.104 53.557 13.176 ;
     RECT  53.485 74.64 53.557 74.664 ;
     RECT  52.697 82.992 53.564 83.784 ;
     RECT  53.557 74.448 53.597 74.664 ;
     RECT  53.129 2.592 53.605 7.992 ;
     RECT  53.269 18.72 53.633 21.624 ;
     RECT  53.489 55.488 53.633 55.8 ;
     RECT  53.557 13.056 53.651 13.176 ;
     RECT  53.564 82.992 53.651 84.36 ;
     RECT  53.521 76.176 53.665 76.248 ;
     RECT  53.521 23.28 53.669 28.68 ;
     RECT  52.337 38.16 53.677 41.448 ;
     RECT  52.697 81.216 53.701 82.008 ;
     RECT  53.651 82.992 53.701 83.64 ;
     RECT  53.305 78.432 53.705 79.848 ;
     RECT  53.669 23.28 53.777 28.584 ;
     RECT  53.525 47.328 53.777 49.848 ;
     RECT  53.597 74.448 53.809 74.568 ;
     RECT  53.701 81.216 53.809 83.64 ;
     RECT  53.777 47.856 53.813 49.848 ;
     RECT  53.633 21.12 53.849 21.624 ;
     RECT  52.949 85.68 53.849 87.096 ;
     RECT  53.677 41.376 53.917 41.448 ;
     RECT  53.633 55.776 53.921 55.8 ;
     RECT  53.633 18.72 53.957 19.944 ;
     RECT  53.777 23.28 53.993 24.264 ;
     RECT  53.489 57.072 53.993 57.336 ;
     RECT  53.957 18.72 54.029 18.888 ;
     RECT  53.557 72.672 54.061 72.696 ;
     RECT  53.993 23.328 54.065 24.264 ;
     RECT  53.777 25.248 54.065 28.584 ;
     RECT  53.809 74.304 54.065 74.568 ;
     RECT  52.588 44.16 54.092 45 ;
     RECT  54.092 44.16 54.133 45.336 ;
     RECT  53.381 14.448 54.137 16.488 ;
     RECT  53.849 21.216 54.137 21.624 ;
     RECT  54.065 25.488 54.137 28.584 ;
     RECT  54.065 74.304 54.173 74.472 ;
     RECT  53.809 80.448 54.173 83.64 ;
     RECT  54.133 44.16 54.179 46.2 ;
     RECT  54.133 9.504 54.205 9.528 ;
     RECT  52.805 36.816 54.241 36.888 ;
     RECT  52.877 52.176 54.241 52.2 ;
     RECT  53.813 47.856 54.245 49.656 ;
     RECT  53.705 78.432 54.277 79.272 ;
     RECT  53.665 76.176 54.281 77.112 ;
     RECT  53.849 85.92 54.313 87.096 ;
     RECT  52.445 88.08 54.313 88.104 ;
     RECT  52.661 30.288 54.317 30.984 ;
     RECT  54.205 60.144 54.349 60.168 ;
     RECT  53.605 2.592 54.353 7.8 ;
     RECT  54.173 80.832 54.389 83.64 ;
     RECT  54.313 85.92 54.419 88.104 ;
     RECT  52.813 32.448 54.421 32.472 ;
     RECT  54.137 21.6 54.425 21.624 ;
     RECT  54.029 18.768 54.461 18.888 ;
     RECT  54.389 81.84 54.497 83.64 ;
     RECT  54.241 51.744 54.524 52.2 ;
     RECT  54.353 2.688 54.533 7.8 ;
     RECT  54.137 26.256 54.533 28.584 ;
     RECT  53.309 61.536 54.565 61.56 ;
     RECT  53.917 41.376 54.637 42.216 ;
     RECT  54.461 18.864 54.641 18.888 ;
     RECT  54.179 46.08 54.641 46.2 ;
     RECT  52.979 11.376 54.661 11.688 ;
     RECT  54.349 60.144 54.661 60.264 ;
     RECT  54.565 61.536 54.661 61.656 ;
     RECT  54.421 58.992 54.673 59.016 ;
     RECT  53.521 34.128 54.677 34.152 ;
     RECT  54.277 78.384 54.709 79.272 ;
     RECT  54.661 10.608 54.748 11.688 ;
     RECT  54.179 44.16 54.749 45 ;
     RECT  54.524 51.504 54.749 52.2 ;
     RECT  54.281 76.176 54.749 76.392 ;
     RECT  54.709 78.144 54.781 79.272 ;
     RECT  53.737 64.752 54.785 64.776 ;
     RECT  54.065 23.376 54.857 24.264 ;
     RECT  54.637 41.376 54.889 42.744 ;
     RECT  53.677 38.16 54.893 40.296 ;
     RECT  54.749 51.504 54.925 51.672 ;
     RECT  54.533 26.256 54.929 27.768 ;
     RECT  54.781 78.096 54.929 79.272 ;
     RECT  54.245 47.856 54.961 48.504 ;
     RECT  54.929 78.144 54.961 79.272 ;
     RECT  53.411 68.16 54.965 70.92 ;
     RECT  54.889 41.376 54.973 42.84 ;
     RECT  54.137 14.448 55.001 16.44 ;
     RECT  54.419 86.208 55.001 87.528 ;
     RECT  54.245 49.632 55.033 49.656 ;
     RECT  54.317 30.288 55.037 30.456 ;
     RECT  54.961 78.144 55.037 79.464 ;
     RECT  54.061 72.336 55.069 72.696 ;
     RECT  54.893 38.16 55.073 40.056 ;
     RECT  54.641 46.08 55.091 46.152 ;
     RECT  53.957 19.92 55.093 19.944 ;
     RECT  54.601 53.376 55.109 53.4 ;
     RECT  55.037 78.288 55.109 79.464 ;
     RECT  55.093 19.92 55.139 20.568 ;
     RECT  54.205 9.504 55.177 9.576 ;
     RECT  53.651 13.056 55.177 13.08 ;
     RECT  54.421 32.448 55.177 32.712 ;
     RECT  55.139 20.544 55.18 20.568 ;
     RECT  55.177 9.216 55.213 9.576 ;
     RECT  55.033 49.632 55.249 49.848 ;
     RECT  54.925 50.832 55.249 51.672 ;
     RECT  53.993 57.312 55.249 57.336 ;
     RECT  54.965 70.56 55.249 70.92 ;
     RECT  55.069 71.904 55.249 72.696 ;
     RECT  55.093 21.936 55.253 21.96 ;
     RECT  54.857 24.24 55.253 24.264 ;
     RECT  54.961 47.76 55.253 48.504 ;
     RECT  54.533 2.784 55.285 7.8 ;
     RECT  55.213 9.12 55.285 9.576 ;
     RECT  55.177 32.4 55.285 32.712 ;
     RECT  53.201 66.288 55.285 66.408 ;
     RECT  55.091 46.08 55.289 46.104 ;
     RECT  55.285 66.288 55.321 66.6 ;
     RECT  54.965 68.16 55.321 69.48 ;
     RECT  54.929 26.784 55.325 27.768 ;
     RECT  55.285 32.4 55.331 33.672 ;
     RECT  55.331 32.448 55.361 32.472 ;
     RECT  55.249 57.312 55.393 57.864 ;
     RECT  54.673 58.896 55.393 59.016 ;
     RECT  54.173 74.448 55.429 74.472 ;
     RECT  55.393 57.312 55.465 59.016 ;
     RECT  54.241 36.816 55.537 37.032 ;
     RECT  55.465 57.312 55.573 59.064 ;
     RECT  54.661 60.144 55.573 61.656 ;
     RECT  55.109 78.336 55.573 79.464 ;
     RECT  55.573 57.312 55.609 61.656 ;
     RECT  55.249 70.56 55.628 72.696 ;
     RECT  54.497 81.984 55.681 83.64 ;
     RECT  55.105 84.672 55.681 84.696 ;
     RECT  54.748 10.8 55.717 11.688 ;
     RECT  55.177 13.008 55.717 13.08 ;
     RECT  55.717 10.8 55.753 13.08 ;
     RECT  55.253 47.856 55.765 48.504 ;
     RECT  55.249 49.632 55.765 51.672 ;
     RECT  55.001 14.784 55.789 16.44 ;
     RECT  55.285 2.784 55.969 9.576 ;
     RECT  55.753 10.8 56.005 13.704 ;
     RECT  55.789 14.784 56.005 16.536 ;
     RECT  56.005 10.8 56.041 16.536 ;
     RECT  55.765 47.856 56.077 51.672 ;
     RECT  55.429 74.064 56.113 74.712 ;
     RECT  55.249 76.128 56.113 76.152 ;
     RECT  55.537 36.624 56.149 37.032 ;
     RECT  55.073 38.16 56.185 38.856 ;
     RECT  55.073 39.888 56.185 40.056 ;
     RECT  55.001 86.208 56.257 87.144 ;
     RECT  54.749 44.16 56.293 44.904 ;
     RECT  56.113 74.064 56.401 76.152 ;
     RECT  55.969 2.784 56.408 9.624 ;
     RECT  56.041 10.8 56.408 16.872 ;
     RECT  56.077 19.008 56.408 19.032 ;
     RECT  55.325 26.784 56.408 27.672 ;
     RECT  55.037 30.432 56.408 30.456 ;
     RECT  55.331 33.648 56.408 33.672 ;
     RECT  56.149 36.288 56.408 37.032 ;
     RECT  56.185 38.16 56.408 40.056 ;
     RECT  54.973 41.376 56.408 42.216 ;
     RECT  56.293 44.16 56.408 45 ;
     RECT  56.257 46.704 56.408 46.728 ;
     RECT  56.077 47.856 56.408 51.96 ;
     RECT  55.609 57.312 56.408 62.568 ;
     RECT  55.321 66.288 56.408 69.48 ;
     RECT  55.628 70.56 56.408 72.936 ;
     RECT  56.401 74.064 56.408 76.584 ;
     RECT  55.573 78.336 56.408 79.512 ;
     RECT  54.389 80.832 56.408 80.856 ;
     RECT  55.681 81.984 56.408 84.696 ;
     RECT  56.257 85.68 56.408 87.144 ;
     RECT  55.429 88.128 56.408 88.152 ;
     RECT  56.408 2.148 56.512 88.572 ;
     RECT  56.512 2.418 56.704 88.302 ;
     RECT  56.704 10.752 56.729 16.824 ;
     RECT  56.704 64.656 56.729 64.68 ;
     RECT  56.704 82.464 56.765 88.152 ;
     RECT  56.704 74.112 56.873 74.568 ;
     RECT  56.704 30.432 56.909 33.48 ;
     RECT  56.704 34.704 56.945 40.056 ;
     RECT  56.945 35.28 56.981 40.056 ;
     RECT  56.704 24.48 57.011 24.504 ;
     RECT  56.704 27.792 57.011 29.4 ;
     RECT  56.704 76.56 57.017 76.728 ;
     RECT  57.011 27.792 57.052 29.064 ;
     RECT  56.704 57.312 57.053 62.568 ;
     RECT  56.729 10.752 57.059 16.488 ;
     RECT  57.052 28.416 57.089 29.064 ;
     RECT  57.053 57.312 57.089 62.232 ;
     RECT  56.909 30.432 57.125 33.336 ;
     RECT  56.704 48.96 57.125 52.536 ;
     RECT  57.017 76.56 57.161 76.584 ;
     RECT  56.704 78.432 57.161 80.856 ;
     RECT  56.704 26.208 57.197 26.52 ;
     RECT  57.125 48.96 57.197 49.08 ;
     RECT  57.125 50.304 57.197 52.536 ;
     RECT  56.704 2.784 57.305 9 ;
     RECT  56.765 82.608 57.305 88.152 ;
     RECT  57.197 50.304 57.341 52.44 ;
     RECT  57.161 80.688 57.377 80.856 ;
     RECT  57.089 57.312 57.443 57.336 ;
     RECT  57.089 58.368 57.449 62.232 ;
     RECT  57.305 82.608 57.449 83.64 ;
     RECT  57.305 84.72 57.449 88.152 ;
     RECT  57.449 58.368 57.484 61.224 ;
     RECT  57.449 82.704 57.485 83.64 ;
     RECT  57.484 60.816 57.521 61.224 ;
     RECT  57.485 82.8 57.521 83.64 ;
     RECT  56.981 35.28 57.587 39.912 ;
     RECT  57.059 11.952 57.593 16.488 ;
     RECT  56.704 65.952 57.593 72.264 ;
     RECT  56.704 55.392 57.629 55.416 ;
     RECT  57.587 35.28 57.737 38.808 ;
     RECT  57.341 50.688 57.737 52.44 ;
     RECT  56.704 47.28 57.809 47.304 ;
     RECT  57.484 58.368 57.845 59.64 ;
     RECT  57.737 50.784 57.917 51.672 ;
     RECT  56.704 41.04 57.949 41.4 ;
     RECT  57.089 28.704 58.028 29.064 ;
     RECT  58.028 28.704 58.069 29.4 ;
     RECT  57.737 35.28 58.069 36.456 ;
     RECT  57.593 11.952 58.093 12.024 ;
     RECT  58.069 27.84 58.093 29.4 ;
     RECT  57.125 30.432 58.093 32.472 ;
     RECT  58.093 27.84 58.115 32.472 ;
     RECT  56.704 43.92 58.117 45 ;
     RECT  57.913 63.36 58.117 63.384 ;
     RECT  57.197 48.96 58.124 48.984 ;
     RECT  58.117 62.592 58.163 63.384 ;
     RECT  58.124 48.432 58.165 48.984 ;
     RECT  58.069 35.28 58.169 35.88 ;
     RECT  57.059 10.752 58.201 10.872 ;
     RECT  58.115 31.344 58.205 32.472 ;
     RECT  58.117 43.92 58.205 45.96 ;
     RECT  58.165 48.432 58.211 49.032 ;
     RECT  57.845 58.368 58.237 58.44 ;
     RECT  57.161 78.432 58.273 79.608 ;
     RECT  57.737 37.44 58.277 38.808 ;
     RECT  57.949 41.04 58.277 41.688 ;
     RECT  57.949 73.392 58.277 73.416 ;
     RECT  57.449 84.864 58.277 88.152 ;
     RECT  58.205 43.92 58.309 45 ;
     RECT  56.873 74.544 58.345 74.568 ;
     RECT  58.273 78.432 58.381 79.704 ;
     RECT  57.377 80.688 58.381 80.808 ;
     RECT  57.305 2.784 58.385 7.656 ;
     RECT  58.093 11.904 58.385 12.024 ;
     RECT  58.385 2.784 58.417 3.384 ;
     RECT  58.385 4.368 58.421 7.656 ;
     RECT  57.197 26.208 58.421 26.232 ;
     RECT  58.205 32.448 58.421 32.472 ;
     RECT  58.201 22.8 58.489 22.824 ;
     RECT  58.211 48.96 58.493 49.032 ;
     RECT  57.593 67.296 58.499 71.736 ;
     RECT  58.345 73.776 58.499 74.568 ;
     RECT  58.381 78.432 58.525 80.808 ;
     RECT  57.587 39.888 58.561 39.912 ;
     RECT  57.593 65.952 58.669 66.312 ;
     RECT  58.499 67.296 58.669 69.48 ;
     RECT  57.521 83.04 58.669 83.64 ;
     RECT  56.704 42.72 58.673 42.744 ;
     RECT  57.305 8.976 58.693 9 ;
     RECT  58.201 10.128 58.693 10.872 ;
     RECT  58.309 43.824 58.705 45 ;
     RECT  58.645 21.6 58.721 21.624 ;
     RECT  58.693 8.736 58.741 10.872 ;
     RECT  58.385 11.904 58.741 11.976 ;
     RECT  58.705 19.536 58.741 19.56 ;
     RECT  58.489 22.8 58.745 23.688 ;
     RECT  58.705 42.768 58.745 45 ;
     RECT  57.593 13.104 58.781 16.488 ;
     RECT  57.845 59.616 58.817 59.64 ;
     RECT  58.525 78.432 58.817 80.904 ;
     RECT  58.669 82.848 58.817 83.64 ;
     RECT  58.741 8.736 58.825 11.976 ;
     RECT  58.741 18.768 58.825 19.56 ;
     RECT  58.721 21.552 58.849 21.624 ;
     RECT  58.745 22.8 58.853 22.872 ;
     RECT  58.825 8.736 58.889 10.296 ;
     RECT  58.499 70.8 58.921 71.736 ;
     RECT  58.499 74.208 58.925 74.472 ;
     RECT  58.597 47.76 58.961 47.784 ;
     RECT  58.813 24.144 58.993 24.264 ;
     RECT  58.453 25.392 58.993 25.416 ;
     RECT  58.925 74.448 58.997 74.472 ;
     RECT  58.277 84.864 58.997 86.712 ;
     RECT  58.849 21.456 59.029 21.624 ;
     RECT  58.921 70.8 59.029 71.784 ;
     RECT  58.825 18.768 59.033 18.792 ;
     RECT  58.493 48.96 59.033 48.984 ;
     RECT  58.115 27.84 59.075 28.728 ;
     RECT  59.075 28.416 59.077 28.728 ;
     RECT  59.077 28.416 59.164 29.064 ;
     RECT  58.561 39.888 59.173 40.056 ;
     RECT  58.115 30.288 59.177 30.312 ;
     RECT  58.705 46.752 59.245 46.776 ;
     RECT  58.777 64.8 59.245 64.824 ;
     RECT  58.669 65.952 59.245 69.48 ;
     RECT  59.173 39.888 59.269 40.632 ;
     RECT  58.277 41.664 59.269 41.688 ;
     RECT  57.917 51.36 59.276 51.672 ;
     RECT  58.745 42.768 59.315 43.368 ;
     RECT  59.276 51.36 59.317 51.816 ;
     RECT  59.281 54 59.317 54.024 ;
     RECT  58.993 24.144 59.321 25.416 ;
     RECT  59.269 39.888 59.321 41.688 ;
     RECT  58.997 84.864 59.353 86.568 ;
     RECT  58.825 11.424 59.357 11.976 ;
     RECT  59.321 25.152 59.357 25.416 ;
     RECT  59.321 41.52 59.357 41.688 ;
     RECT  59.317 51.36 59.363 54.024 ;
     RECT  58.781 13.104 59.393 13.56 ;
     RECT  59.029 21.456 59.393 22.776 ;
     RECT  59.363 52.176 59.401 54.024 ;
     RECT  59.357 11.904 59.425 11.976 ;
     RECT  59.393 21.456 59.425 22.728 ;
     RECT  58.345 76.896 59.425 76.92 ;
     RECT  58.817 78.432 59.425 80.808 ;
     RECT  59.425 76.896 59.429 80.808 ;
     RECT  59.425 11.904 59.465 12.024 ;
     RECT  59.425 21.408 59.465 22.728 ;
     RECT  58.781 14.64 59.497 16.488 ;
     RECT  59.429 76.896 59.509 80.664 ;
     RECT  58.745 44.448 59.516 45 ;
     RECT  59.245 46.752 59.516 47.304 ;
     RECT  58.885 20.304 59.573 20.328 ;
     RECT  59.516 44.448 59.573 47.304 ;
     RECT  58.417 2.448 59.605 3.384 ;
     RECT  58.921 63.792 59.605 63.816 ;
     RECT  59.245 64.8 59.605 69.48 ;
     RECT  59.573 44.448 59.617 46.872 ;
     RECT  59.393 13.104 59.645 13.128 ;
     RECT  59.641 50.976 59.677 51 ;
     RECT  59.605 2.208 59.713 3.384 ;
     RECT  58.421 4.656 59.713 7.656 ;
     RECT  59.509 76.896 59.713 77.016 ;
     RECT  57.521 60.816 59.749 60.84 ;
     RECT  59.321 24.144 59.753 24.168 ;
     RECT  59.617 44.448 59.789 45.96 ;
     RECT  59.677 50.16 59.813 51 ;
     RECT  58.889 9.36 59.821 10.296 ;
     RECT  58.163 62.592 59.821 62.616 ;
     RECT  58.205 31.344 59.857 31.368 ;
     RECT  59.785 32.448 59.857 32.472 ;
     RECT  59.029 70.8 59.857 71.928 ;
     RECT  59.497 14.64 59.897 16.92 ;
     RECT  58.093 55.536 59.897 55.56 ;
     RECT  59.101 56.88 59.969 56.904 ;
     RECT  59.315 43.344 60.005 43.368 ;
     RECT  59.509 78.432 60.005 80.664 ;
     RECT  59.713 2.208 60.041 7.656 ;
     RECT  59.813 49.536 60.041 51 ;
     RECT  58.237 58.128 60.073 58.44 ;
     RECT  59.245 18.192 60.109 18.696 ;
     RECT  60.005 78.432 60.113 80.376 ;
     RECT  60.041 49.536 60.181 49.56 ;
     RECT  59.857 31.344 60.221 32.472 ;
     RECT  59.605 63.792 60.221 69.48 ;
     RECT  59.465 11.952 60.253 12.024 ;
     RECT  59.897 14.64 60.253 16.008 ;
     RECT  60.109 18.096 60.257 18.696 ;
     RECT  59.357 25.152 60.257 25.176 ;
     RECT  60.257 18.192 60.293 18.696 ;
     RECT  59.321 39.888 60.316 40.536 ;
     RECT  60.221 63.792 60.329 67.368 ;
     RECT  60.325 74.4 60.361 74.424 ;
     RECT  60.181 49.392 60.365 49.56 ;
     RECT  59.164 29.04 60.397 29.064 ;
     RECT  60.221 68.592 60.401 69.48 ;
     RECT  59.713 76.464 60.428 77.016 ;
     RECT  59.401 52.176 60.437 52.2 ;
     RECT  59.821 9.36 60.469 10.92 ;
     RECT  60.253 11.952 60.469 12.072 ;
     RECT  60.073 58.128 60.505 59.256 ;
     RECT  59.749 60.816 60.505 61.032 ;
     RECT  60.361 74.208 60.505 74.424 ;
     RECT  59.401 54 60.509 54.024 ;
     RECT  60.505 58.128 60.509 61.032 ;
     RECT  60.428 76.368 60.515 77.016 ;
     RECT  60.041 50.688 60.545 51 ;
     RECT  60.509 58.128 60.545 58.152 ;
     RECT  60.041 2.208 60.581 6.648 ;
     RECT  60.365 49.392 60.581 49.464 ;
     RECT  60.515 76.464 60.581 77.016 ;
     RECT  60.469 9.36 60.613 12.072 ;
     RECT  60.113 80.352 60.617 80.376 ;
     RECT  60.433 13.296 60.649 13.32 ;
     RECT  60.509 59.232 60.653 61.032 ;
     RECT  60.581 76.992 60.757 77.016 ;
     RECT  59.533 36.096 60.761 36.12 ;
     RECT  60.316 39.888 60.761 39.912 ;
     RECT  59.857 70.8 60.833 71.976 ;
     RECT  60.397 29.04 60.865 30.024 ;
     RECT  60.221 31.344 60.865 31.848 ;
     RECT  60.649 13.296 60.901 13.464 ;
     RECT  60.253 14.496 60.901 16.008 ;
     RECT  60.901 13.296 60.949 16.008 ;
     RECT  59.789 44.976 61.009 45.96 ;
     RECT  59.353 84.672 61.009 86.568 ;
     RECT  58.817 83.04 61.081 83.64 ;
     RECT  61.009 84.624 61.081 86.568 ;
     RECT  60.469 55.248 61.117 55.272 ;
     RECT  58.277 88.128 61.189 88.152 ;
     RECT  60.577 81.696 61.297 81.72 ;
     RECT  59.465 21.408 61.369 22.488 ;
     RECT  60.865 29.04 61.369 31.848 ;
     RECT  61.297 81.696 61.369 81.912 ;
     RECT  61.081 83.04 61.369 86.568 ;
     RECT  61.1 52.08 61.405 52.104 ;
     RECT  60.041 7.632 61.429 7.656 ;
     RECT  61.369 20.976 61.441 22.488 ;
     RECT  60.973 36.288 61.441 36.312 ;
     RECT  58.277 37.44 61.441 38.712 ;
     RECT  61.009 44.064 61.441 45.96 ;
     RECT  60.581 49.44 61.477 49.464 ;
     RECT  61.117 54.624 61.477 55.272 ;
     RECT  60.973 56.64 61.477 56.664 ;
     RECT  60.949 13.056 61.513 16.584 ;
     RECT  61.225 17.664 61.513 17.688 ;
     RECT  61.513 47.904 61.549 47.928 ;
     RECT  61.477 49.44 61.549 49.752 ;
     RECT  60.545 50.976 61.549 51 ;
     RECT  59.821 62.112 61.549 62.616 ;
     RECT  60.329 63.792 61.549 66.84 ;
     RECT  61.369 81.696 61.549 86.568 ;
     RECT  61.189 87.552 61.549 88.152 ;
     RECT  60.653 59.232 61.585 60.84 ;
     RECT  61.441 20.832 61.621 22.488 ;
     RECT  61.405 52.08 61.621 53.592 ;
     RECT  61.477 54.624 61.621 56.664 ;
     RECT  60.833 71.952 61.621 71.976 ;
     RECT  61.441 44.064 61.657 46.008 ;
     RECT  60.613 8.928 61.693 12.072 ;
     RECT  61.513 13.056 61.693 17.688 ;
     RECT  61.669 75.696 61.693 75.72 ;
     RECT  60.757 76.992 61.693 77.304 ;
     RECT  61.657 43.536 61.729 46.008 ;
     RECT  60.581 2.592 61.765 6.648 ;
     RECT  61.429 7.632 61.765 7.8 ;
     RECT  61.765 2.592 61.808 7.8 ;
     RECT  61.693 8.928 61.808 17.688 ;
     RECT  61.621 20.592 61.808 22.488 ;
     RECT  61.369 29.04 61.808 32.52 ;
     RECT  60.217 33.6 61.808 33.624 ;
     RECT  61.441 36.288 61.808 38.712 ;
     RECT  59.357 41.568 61.808 41.688 ;
     RECT  61.729 43.536 61.808 46.056 ;
     RECT  61.549 47.904 61.808 51 ;
     RECT  61.621 52.08 61.808 56.664 ;
     RECT  61.585 59.04 61.808 60.84 ;
     RECT  61.549 62.112 61.808 66.84 ;
     RECT  60.401 69.456 61.808 69.48 ;
     RECT  60.833 70.8 61.808 70.92 ;
     RECT  61.621 71.952 61.808 72.84 ;
     RECT  60.505 73.872 61.808 74.424 ;
     RECT  61.693 75.696 61.808 77.304 ;
     RECT  60.113 78.432 61.808 79.176 ;
     RECT  61.669 80.64 61.808 80.664 ;
     RECT  61.549 81.696 61.808 88.152 ;
     RECT  61.808 2.148 61.912 88.572 ;
     RECT  61.912 2.304 62.104 88.302 ;
     RECT  62.104 20.88 62.165 23.304 ;
     RECT  62.104 60.24 62.165 62.472 ;
     RECT  62.104 38.688 62.201 38.712 ;
     RECT  62.104 42.72 62.201 45.576 ;
     RECT  62.104 82.608 62.201 86.616 ;
     RECT  62.104 57.552 62.237 59.256 ;
     RECT  62.201 84.624 62.309 86.616 ;
     RECT  62.104 11.952 62.381 13.08 ;
     RECT  62.104 14.736 62.381 17.112 ;
     RECT  62.104 34.656 62.561 34.68 ;
     RECT  62.104 79.728 62.633 81.24 ;
     RECT  62.381 11.952 62.705 13.032 ;
     RECT  62.104 27.888 62.705 27.912 ;
     RECT  62.165 21.504 62.741 23.304 ;
     RECT  62.381 14.736 62.777 16.68 ;
     RECT  62.104 24.48 62.813 26.232 ;
     RECT  62.104 30.816 62.813 32.472 ;
     RECT  62.104 36.288 62.813 37.464 ;
     RECT  62.201 42.72 62.813 42.744 ;
     RECT  62.201 44.256 62.819 45.576 ;
     RECT  62.104 46.656 62.819 47.352 ;
     RECT  62.813 24.48 62.885 24.504 ;
     RECT  62.104 56.064 62.885 56.52 ;
     RECT  62.237 57.552 62.885 57.576 ;
     RECT  62.165 60.24 62.885 62.136 ;
     RECT  62.741 22.464 62.921 23.304 ;
     RECT  62.104 50.016 62.921 51.96 ;
     RECT  62.921 50.016 62.957 50.04 ;
     RECT  62.885 56.064 62.993 56.088 ;
     RECT  62.104 70.896 62.993 77.304 ;
     RECT  62.819 47.04 63.029 47.352 ;
     RECT  62.921 51.168 63.065 51.96 ;
     RECT  62.104 29.52 63.133 29.544 ;
     RECT  62.104 2.304 63.173 8.04 ;
     RECT  62.104 52.992 63.173 53.928 ;
     RECT  63.173 2.88 63.205 8.04 ;
     RECT  62.104 9.072 63.205 10.92 ;
     RECT  62.104 49.008 63.205 49.032 ;
     RECT  63.065 51.744 63.241 51.96 ;
     RECT  63.173 53.568 63.277 53.928 ;
     RECT  63.205 55.392 63.277 55.416 ;
     RECT  62.993 74.496 63.299 77.304 ;
     RECT  63.029 47.04 63.317 47.304 ;
     RECT  62.993 70.896 63.317 73.128 ;
     RECT  63.205 2.88 63.347 10.92 ;
     RECT  62.813 30.816 63.353 32.088 ;
     RECT  62.104 78.432 63.425 78.696 ;
     RECT  63.353 30.816 63.461 31.944 ;
     RECT  62.201 82.608 63.461 83.64 ;
     RECT  63.317 70.896 63.493 72.456 ;
     RECT  62.813 37.44 63.529 37.464 ;
     RECT  62.819 44.352 63.529 45.576 ;
     RECT  62.104 63.504 63.529 69.528 ;
     RECT  62.104 88.128 63.529 88.152 ;
     RECT  63.241 51.744 63.533 52.248 ;
     RECT  63.299 74.496 63.533 76.872 ;
     RECT  62.633 79.728 63.539 80.904 ;
     RECT  63.347 2.88 63.569 8.328 ;
     RECT  62.705 11.952 63.569 12.024 ;
     RECT  63.529 87.744 63.569 88.152 ;
     RECT  63.529 26.784 63.601 26.808 ;
     RECT  63.133 28.704 63.637 29.544 ;
     RECT  63.461 30.816 63.637 30.84 ;
     RECT  62.885 62.112 63.641 62.136 ;
     RECT  63.529 63.456 63.673 69.528 ;
     RECT  63.539 79.728 63.673 79.848 ;
     RECT  63.404 34.704 63.674 36.12 ;
     RECT  63.674 34.752 63.749 36.12 ;
     RECT  63.529 37.44 63.749 38.376 ;
     RECT  62.309 85.488 63.749 86.616 ;
     RECT  63.529 44.352 63.781 45.624 ;
     RECT  63.317 47.04 63.781 47.064 ;
     RECT  63.461 83.184 63.781 83.64 ;
     RECT  63.569 2.88 63.785 8.04 ;
     RECT  63.673 79.584 63.785 79.848 ;
     RECT  63.673 63.072 63.817 69.528 ;
     RECT  63.749 34.752 63.821 36.024 ;
     RECT  63.749 85.92 63.821 86.616 ;
     RECT  63.601 26.784 63.853 27.672 ;
     RECT  63.637 28.704 63.853 30.84 ;
     RECT  62.777 14.736 63.857 14.76 ;
     RECT  63.785 2.88 63.875 7.464 ;
     RECT  63.875 5.136 63.893 7.464 ;
     RECT  62.777 15.792 63.893 16.68 ;
     RECT  62.885 60.24 63.893 60.84 ;
     RECT  63.529 42.144 63.925 42.168 ;
     RECT  62.921 23.28 63.961 23.304 ;
     RECT  63.853 26.784 63.965 30.84 ;
     RECT  63.821 35.328 63.965 36.024 ;
     RECT  63.821 85.92 63.965 85.944 ;
     RECT  63.781 44.352 63.971 47.064 ;
     RECT  62.237 58.704 63.997 59.256 ;
     RECT  63.965 27.84 64.001 30.84 ;
     RECT  63.971 44.352 64.012 44.808 ;
     RECT  63.889 25.68 64.019 25.704 ;
     RECT  63.893 5.232 64.037 7.464 ;
     RECT  63.533 74.496 64.105 74.808 ;
     RECT  64.012 44.352 64.109 44.472 ;
     RECT  62.705 13.008 64.141 13.032 ;
     RECT  63.893 16.656 64.145 16.68 ;
     RECT  63.533 76.08 64.181 76.872 ;
     RECT  63.997 26.736 64.213 26.76 ;
     RECT  64.213 25.872 64.217 26.76 ;
     RECT  63.817 63.072 64.217 69.624 ;
     RECT  63.277 53.568 64.285 55.416 ;
     RECT  64.217 63.264 64.285 69.624 ;
     RECT  63.493 70.608 64.285 72.456 ;
     RECT  64.001 28.464 64.289 30.84 ;
     RECT  63.461 31.92 64.297 31.944 ;
     RECT  64.217 25.872 64.3 26.712 ;
     RECT  63.925 42.144 64.357 42.456 ;
     RECT  63.971 46.08 64.357 47.064 ;
     RECT  63.997 58.32 64.393 59.256 ;
     RECT  64.289 28.896 64.429 30.84 ;
     RECT  63.347 9.648 64.433 10.92 ;
     RECT  63.205 49.008 64.46 49.608 ;
     RECT  64.285 53.568 64.469 55.944 ;
     RECT  64.285 63.264 64.505 72.456 ;
     RECT  63.961 23.28 64.537 23.976 ;
     RECT  64.357 42.144 64.541 42.792 ;
     RECT  64.46 49.008 64.541 49.704 ;
     RECT  64.541 49.68 64.547 49.704 ;
     RECT  63.425 78.432 64.573 78.456 ;
     RECT  63.781 83.184 64.573 84.312 ;
     RECT  64.537 23.28 64.577 24.744 ;
     RECT  64.357 46.08 64.577 47.304 ;
     RECT  64.469 53.952 64.577 55.944 ;
     RECT  64.037 5.232 64.613 6.696 ;
     RECT  64.3 26.688 64.636 26.712 ;
     RECT  64.069 40.176 64.681 40.2 ;
     RECT  63.205 18.432 64.685 18.456 ;
     RECT  63.893 60.816 64.685 60.84 ;
     RECT  63.539 80.88 64.717 80.904 ;
     RECT  64.573 82.656 64.717 84.312 ;
     RECT  64.577 24.72 64.721 24.744 ;
     RECT  64.429 28.896 64.721 31.368 ;
     RECT  64.577 53.952 64.739 54.648 ;
     RECT  64.433 10.512 64.741 10.92 ;
     RECT  63.785 79.728 64.757 79.848 ;
     RECT  64.717 80.88 64.757 84.312 ;
     RECT  63.875 2.88 64.789 3.864 ;
     RECT  64.717 15.408 64.801 15.432 ;
     RECT  63.973 20.16 64.825 20.184 ;
     RECT  63.889 50.688 64.825 50.712 ;
     RECT  64.613 5.28 64.829 6.696 ;
     RECT  64.721 30.72 64.883 31.368 ;
     RECT  64.573 77.664 64.885 78.456 ;
     RECT  64.825 50.256 64.897 50.712 ;
     RECT  64.933 61.872 64.94 61.896 ;
     RECT  64.933 21.936 64.969 21.96 ;
     RECT  64.577 23.28 64.969 23.304 ;
     RECT  64.883 30.72 64.973 30.84 ;
     RECT  64.885 77.664 64.973 79.272 ;
     RECT  64.105 74.352 64.981 74.808 ;
     RECT  64.505 63.312 65.005 72.456 ;
     RECT  64.393 58.32 65.029 59.448 ;
     RECT  65.005 63.312 65.029 72.84 ;
     RECT  64.981 73.92 65.029 74.808 ;
     RECT  64.181 76.08 65.029 76.104 ;
     RECT  65.029 63.312 65.041 72.936 ;
     RECT  65.029 73.92 65.041 76.104 ;
     RECT  64.897 50.256 65.045 51.096 ;
     RECT  64.739 54.624 65.081 54.648 ;
     RECT  64.825 19.056 65.113 20.184 ;
     RECT  65.041 63.312 65.116 76.104 ;
     RECT  64.969 21.936 65.117 23.304 ;
     RECT  64.541 42.192 65.117 42.792 ;
     RECT  64.757 81.84 65.117 84.312 ;
     RECT  64.973 30.816 65.153 30.84 ;
     RECT  64.577 55.68 65.18 55.944 ;
     RECT  64.033 56.976 65.18 57 ;
     RECT  63.569 87.744 65.185 87.768 ;
     RECT  63.749 37.44 65.221 37.608 ;
     RECT  64.973 77.664 65.225 78.696 ;
     RECT  64.141 13.008 65.257 13.656 ;
     RECT  65.029 58.128 65.261 59.448 ;
     RECT  64.681 40.176 65.267 40.824 ;
     RECT  64.933 33.072 65.293 33.096 ;
     RECT  64.109 44.448 65.293 44.472 ;
     RECT  65.293 44.448 65.333 45.048 ;
     RECT  65.116 63.312 65.333 74.76 ;
     RECT  64.825 9.12 65.437 9.288 ;
     RECT  64.741 10.512 65.437 10.968 ;
     RECT  65.045 51.072 65.437 51.096 ;
     RECT  63.533 52.224 65.437 52.248 ;
     RECT  65.221 37.44 65.441 38.04 ;
     RECT  65.365 27.936 65.459 27.96 ;
     RECT  65.18 55.68 65.477 57 ;
     RECT  65.437 9.12 65.509 10.968 ;
     RECT  63.569 11.952 65.509 11.976 ;
     RECT  65.041 34.32 65.509 34.344 ;
     RECT  65.468 86.64 65.509 86.664 ;
     RECT  65.185 87.744 65.509 88.392 ;
     RECT  65.113 19.056 65.513 20.76 ;
     RECT  65.117 42.192 65.513 42.696 ;
     RECT  65.333 63.312 65.513 74.712 ;
     RECT  64.721 29.088 65.549 29.256 ;
     RECT  64.577 46.08 65.549 47.064 ;
     RECT  65.509 34.08 65.555 34.344 ;
     RECT  65.509 86.64 65.555 88.392 ;
     RECT  64.94 60.96 65.581 61.896 ;
     RECT  65.513 63.312 65.581 74.568 ;
     RECT  64.933 17.088 65.657 17.112 ;
     RECT  65.267 40.8 65.729 40.824 ;
     RECT  65.437 51.072 65.729 52.248 ;
     RECT  65.477 55.68 65.765 56.712 ;
     RECT  65.581 60.96 65.837 74.568 ;
     RECT  65.555 86.88 65.873 86.904 ;
     RECT  64.789 2.4 65.909 3.864 ;
     RECT  65.513 19.056 65.909 19.08 ;
     RECT  65.837 73.584 65.909 74.568 ;
     RECT  65.293 33.024 65.941 33.096 ;
     RECT  65.555 34.08 65.941 34.2 ;
     RECT  65.117 81.84 65.941 81.864 ;
     RECT  65.116 76.08 65.945 76.104 ;
     RECT  65.225 77.664 65.945 78.456 ;
     RECT  65.509 9.12 66.013 11.976 ;
     RECT  65.725 27.072 66.013 27.096 ;
     RECT  65.729 51.312 66.013 52.248 ;
     RECT  65.941 30.432 66.028 30.456 ;
     RECT  65.513 20.352 66.037 20.76 ;
     RECT  65.117 21.936 66.037 21.96 ;
     RECT  66.013 8.496 66.053 11.976 ;
     RECT  66.037 20.352 66.083 21.96 ;
     RECT  65.909 2.88 66.085 3.864 ;
     RECT  64.829 5.28 66.085 6.648 ;
     RECT  66.013 26.112 66.085 27.096 ;
     RECT  65.333 45.024 66.089 45.048 ;
     RECT  65.261 58.128 66.089 59.256 ;
     RECT  65.941 81.696 66.121 81.864 ;
     RECT  65.549 29.232 66.133 29.256 ;
     RECT  65.441 37.44 66.133 37.464 ;
     RECT  65.837 60.96 66.133 72.408 ;
     RECT  66.083 21.12 66.161 21.96 ;
     RECT  65.117 23.28 66.161 23.304 ;
     RECT  65.869 24.528 66.161 24.552 ;
     RECT  65.513 42.672 66.161 42.696 ;
     RECT  66.085 25.824 66.179 27.096 ;
     RECT  65.941 33.024 66.205 34.2 ;
     RECT  66.053 10.128 66.229 11.976 ;
     RECT  65.257 13.008 66.229 14.088 ;
     RECT  65.945 77.664 66.229 78.072 ;
     RECT  66.133 60.96 66.233 72.36 ;
     RECT  65.117 83.232 66.337 84.312 ;
     RECT  66.205 33.024 66.445 34.152 ;
     RECT  66.229 77.52 66.445 78.072 ;
     RECT  65.401 43.824 66.697 43.848 ;
     RECT  66.697 31.2 66.733 31.416 ;
     RECT  66.121 81.36 66.733 81.864 ;
     RECT  66.337 82.944 66.733 84.312 ;
     RECT  66.733 81.36 66.841 84.312 ;
     RECT  66.553 87.024 66.877 87.048 ;
     RECT  66.085 2.88 66.949 6.984 ;
     RECT  66.053 8.496 66.949 8.52 ;
     RECT  65.765 56.688 66.949 56.712 ;
     RECT  66.089 58.128 66.949 58.68 ;
     RECT  66.445 77.424 66.949 78.072 ;
     RECT  65.941 79.488 66.949 79.512 ;
     RECT  66.085 40.992 67.057 41.016 ;
     RECT  66.841 81.36 67.057 84.408 ;
     RECT  66.133 37.056 67.093 37.464 ;
     RECT  66.697 43.824 67.129 44.472 ;
     RECT  67.093 37.056 67.165 37.992 ;
     RECT  65.941 55.488 67.165 55.512 ;
     RECT  66.949 56.688 67.165 58.68 ;
     RECT  66.229 10.128 67.201 14.088 ;
     RECT  66.661 15.36 67.201 15.384 ;
     RECT  66.949 2.88 67.208 8.52 ;
     RECT  67.201 10.128 67.208 15.384 ;
     RECT  66.179 25.824 67.208 26.136 ;
     RECT  66.133 29.232 67.208 29.352 ;
     RECT  66.733 31.2 67.208 31.56 ;
     RECT  66.445 32.832 67.208 34.152 ;
     RECT  63.965 35.328 67.208 35.352 ;
     RECT  67.165 36.624 67.208 37.992 ;
     RECT  65.221 39.024 67.208 39.048 ;
     RECT  67.057 40.416 67.208 41.016 ;
     RECT  67.093 42 67.208 42.024 ;
     RECT  67.129 43.296 67.208 44.472 ;
     RECT  65.549 46.08 67.208 46.872 ;
     RECT  66.013 51.312 67.208 52.728 ;
     RECT  67.165 55.488 67.208 58.68 ;
     RECT  66.841 59.76 67.208 59.784 ;
     RECT  66.877 60.768 67.208 60.792 ;
     RECT  66.233 61.776 67.208 72.36 ;
     RECT  65.909 73.584 67.208 73.848 ;
     RECT  66.949 77.424 67.208 79.512 ;
     RECT  67.057 80.544 67.208 84.408 ;
     RECT  66.877 86.304 67.208 87.048 ;
     RECT  65.555 88.368 67.208 88.392 ;
     RECT  67.208 2.148 67.312 88.572 ;
     RECT  67.312 2.418 67.504 88.302 ;
     RECT  67.504 31.392 67.565 31.8 ;
     RECT  67.565 31.776 67.601 31.8 ;
     RECT  67.504 14.64 67.619 14.808 ;
     RECT  67.504 60.96 67.619 67.944 ;
     RECT  67.504 42 67.637 42.024 ;
     RECT  67.504 48.48 67.667 50.664 ;
     RECT  67.504 9.12 67.709 9.144 ;
     RECT  67.504 55.488 67.709 59.784 ;
     RECT  67.504 70.32 67.709 75.144 ;
     RECT  67.504 36.384 67.715 39.048 ;
     RECT  67.504 85.488 67.853 87.288 ;
     RECT  67.715 37.056 67.889 39.048 ;
     RECT  67.504 43.296 67.889 43.32 ;
     RECT  67.504 83.616 67.925 84.408 ;
     RECT  67.889 37.056 67.997 37.464 ;
     RECT  67.709 55.488 67.997 58.2 ;
     RECT  67.709 70.32 67.997 73.848 ;
     RECT  67.853 85.488 67.997 86.616 ;
     RECT  67.619 60.96 68.003 67.704 ;
     RECT  67.709 59.184 68.033 59.784 ;
     RECT  68.003 62.448 68.033 67.704 ;
     RECT  68.003 60.96 68.044 61.368 ;
     RECT  67.889 38.736 68.069 39.048 ;
     RECT  67.504 78.576 68.105 80.328 ;
     RECT  67.504 19.056 68.141 19.944 ;
     RECT  67.667 48.48 68.213 48.504 ;
     RECT  67.997 71.376 68.285 73.848 ;
     RECT  68.285 71.76 68.321 73.848 ;
     RECT  67.997 57.312 68.357 58.2 ;
     RECT  67.504 46.176 68.387 46.872 ;
     RECT  67.504 68.976 68.393 69.288 ;
     RECT  68.141 19.92 68.401 19.944 ;
     RECT  67.667 50.544 68.428 50.664 ;
     RECT  68.069 38.784 68.429 39.048 ;
     RECT  67.504 81.408 68.429 82.44 ;
     RECT  67.504 10.128 68.465 12.552 ;
     RECT  68.321 72.096 68.501 73.848 ;
     RECT  67.504 2.736 68.537 7.992 ;
     RECT  67.709 75.12 68.573 75.144 ;
     RECT  68.537 2.736 68.605 7.944 ;
     RECT  67.504 29.232 68.605 30.168 ;
     RECT  67.504 51.696 68.605 53.16 ;
     RECT  67.504 33.84 68.641 33.864 ;
     RECT  67.504 35.184 68.641 35.208 ;
     RECT  68.387 46.848 68.641 46.872 ;
     RECT  68.105 78.576 68.641 78.696 ;
     RECT  68.465 10.176 68.645 12.552 ;
     RECT  68.033 62.736 68.677 67.704 ;
     RECT  68.641 46.848 68.681 47.016 ;
     RECT  68.429 82.368 68.681 82.44 ;
     RECT  67.504 25.872 68.749 25.896 ;
     RECT  68.641 78.384 68.749 78.696 ;
     RECT  68.641 33.84 68.753 35.208 ;
     RECT  67.504 44.448 68.753 45 ;
     RECT  68.681 82.416 68.753 82.44 ;
     RECT  68.749 25.776 68.821 26.28 ;
     RECT  67.504 27.312 68.821 27.768 ;
     RECT  67.504 21.36 68.857 21.72 ;
     RECT  68.044 61.344 68.861 61.368 ;
     RECT  68.393 69.264 68.893 69.288 ;
     RECT  67.997 70.32 68.893 70.344 ;
     RECT  68.753 44.448 68.917 44.616 ;
     RECT  68.357 57.84 68.917 58.2 ;
     RECT  68.033 59.184 68.917 59.208 ;
     RECT  67.504 22.992 68.929 23.16 ;
     RECT  67.504 24.336 68.929 24.36 ;
     RECT  67.997 55.488 68.963 55.512 ;
     RECT  68.917 57.84 68.963 59.208 ;
     RECT  67.504 40.56 68.969 40.584 ;
     RECT  68.645 10.176 69.005 12.024 ;
     RECT  68.749 78.144 69.005 78.696 ;
     RECT  68.821 25.776 69.077 27.768 ;
     RECT  68.605 29.232 69.077 30.888 ;
     RECT  68.753 35.184 69.077 35.208 ;
     RECT  68.965 48.96 69.077 48.984 ;
     RECT  68.605 51.264 69.077 53.16 ;
     RECT  68.929 22.992 69.145 24.36 ;
     RECT  68.677 62.736 69.145 67.848 ;
     RECT  68.713 75.504 69.145 75.528 ;
     RECT  68.893 69.264 69.149 70.344 ;
     RECT  69.073 40.464 69.157 40.488 ;
     RECT  67.997 85.488 69.185 85.512 ;
     RECT  67.504 13.536 69.217 13.56 ;
     RECT  67.619 14.688 69.217 14.808 ;
     RECT  69.145 22.992 69.217 24.408 ;
     RECT  68.917 43.92 69.253 44.616 ;
     RECT  69.077 52.608 69.257 53.16 ;
     RECT  68.785 18.48 69.289 18.504 ;
     RECT  69.077 25.776 69.293 27.72 ;
     RECT  69.145 75.504 69.293 75.768 ;
     RECT  68.963 58.128 69.325 59.208 ;
     RECT  69.325 58.128 69.329 59.832 ;
     RECT  69.293 75.504 69.329 75.528 ;
     RECT  67.997 86.592 69.349 86.616 ;
     RECT  68.429 38.928 69.361 39.048 ;
     RECT  69.217 13.536 69.397 14.808 ;
     RECT  69.077 51.264 69.433 51.384 ;
     RECT  69.145 62.64 69.433 67.848 ;
     RECT  69.005 10.176 69.437 11.976 ;
     RECT  68.501 73.728 69.437 73.848 ;
     RECT  69.397 13.008 69.443 14.808 ;
     RECT  69.217 22.992 69.505 24.552 ;
     RECT  69.325 35.28 69.539 35.928 ;
     RECT  68.105 80.208 69.545 80.328 ;
     RECT  68.857 21.168 69.577 21.72 ;
     RECT  69.433 51.024 69.581 51.384 ;
     RECT  69.149 70.32 69.581 70.344 ;
     RECT  67.925 83.616 69.613 84.072 ;
     RECT  69.289 18.48 69.617 19.416 ;
     RECT  69.505 22.992 69.649 24.792 ;
     RECT  69.293 25.776 69.649 27.336 ;
     RECT  69.545 80.304 69.689 80.328 ;
     RECT  67.997 37.44 69.721 37.464 ;
     RECT  68.681 46.992 69.721 47.016 ;
     RECT  69.443 14.112 69.793 14.808 ;
     RECT  68.605 2.256 69.833 7.944 ;
     RECT  69.617 19.392 69.973 19.416 ;
     RECT  69.577 20.592 69.973 21.72 ;
     RECT  69.329 59.808 69.977 59.832 ;
     RECT  69.433 62.16 70.009 67.848 ;
     RECT  69.149 69.264 70.009 69.288 ;
     RECT  69.068 56.112 70.045 56.136 ;
     RECT  70.045 56.112 70.069 57.048 ;
     RECT  69.329 58.128 70.069 58.392 ;
     RECT  69.833 2.88 70.085 7.944 ;
     RECT  69.793 14.112 70.117 15 ;
     RECT  69.349 86.16 70.117 86.616 ;
     RECT  70.009 62.16 70.121 69.288 ;
     RECT  70.121 62.16 70.157 68.376 ;
     RECT  70.117 86.16 70.163 87.24 ;
     RECT  69.721 37.44 70.193 37.608 ;
     RECT  70.163 87.216 70.201 87.24 ;
     RECT  69.077 29.232 70.225 30.84 ;
     RECT  70.085 5.088 70.261 7.944 ;
     RECT  69.649 22.992 70.261 27.336 ;
     RECT  70.261 5.088 70.301 8.52 ;
     RECT  69.253 43.824 70.301 44.616 ;
     RECT  70.193 37.44 70.441 37.464 ;
     RECT  70.225 28.704 70.445 30.84 ;
     RECT  69.613 83.616 70.508 84.936 ;
     RECT  70.163 86.16 70.508 86.184 ;
     RECT  69.443 13.008 70.513 13.128 ;
     RECT  70.117 14.112 70.513 15.24 ;
     RECT  70.445 28.704 70.513 29.352 ;
     RECT  69.721 54.384 70.513 54.984 ;
     RECT  70.069 56.112 70.513 58.392 ;
     RECT  70.513 28.32 70.517 29.352 ;
     RECT  70.508 83.616 70.553 86.184 ;
     RECT  70.405 42.72 70.585 42.744 ;
     RECT  70.301 44.208 70.585 44.616 ;
     RECT  70.081 45.744 70.585 45.768 ;
     RECT  69.437 73.824 70.585 73.848 ;
     RECT  70.553 84.048 70.595 86.184 ;
     RECT  69.539 35.28 70.621 35.592 ;
     RECT  70.441 36.672 70.621 37.464 ;
     RECT  70.301 8.496 70.645 8.52 ;
     RECT  69.437 10.272 70.645 11.976 ;
     RECT  69.973 19.392 70.657 21.72 ;
     RECT  70.261 22.944 70.657 27.336 ;
     RECT  70.517 28.32 70.661 29.256 ;
     RECT  70.595 84.048 70.661 84.936 ;
     RECT  69.757 17.52 70.685 17.544 ;
     RECT  70.445 30.672 70.693 30.84 ;
     RECT  68.753 33.84 70.693 33.864 ;
     RECT  70.585 73.824 70.693 74.04 ;
     RECT  70.657 19.392 70.729 27.336 ;
     RECT  70.621 35.28 70.733 37.464 ;
     RECT  70.693 73.824 70.733 74.088 ;
     RECT  70.693 33.6 70.739 33.864 ;
     RECT  69.005 78.48 70.765 78.504 ;
     RECT  70.585 41.76 70.769 42.744 ;
     RECT  70.729 19.248 70.801 27.336 ;
     RECT  69.361 38.928 70.801 39.912 ;
     RECT  70.595 86.16 70.805 86.184 ;
     RECT  70.801 19.2 70.835 27.336 ;
     RECT  70.513 13.008 70.873 15.24 ;
     RECT  70.157 62.64 70.877 68.376 ;
     RECT  70.685 17.52 70.909 18.216 ;
     RECT  70.693 30.672 70.931 31.176 ;
     RECT  70.873 13.008 70.933 15.384 ;
     RECT  70.513 54.384 70.933 58.392 ;
     RECT  69.581 51.024 70.949 51.048 ;
     RECT  70.835 19.2 70.979 22.344 ;
     RECT  70.301 5.088 71.021 7.416 ;
     RECT  70.933 54.384 71.021 58.872 ;
     RECT  70.835 23.472 71.053 27.336 ;
     RECT  71.021 54.384 71.057 54.888 ;
     RECT  70.933 13.008 71.089 15.864 ;
     RECT  70.909 17.04 71.089 18.216 ;
     RECT  70.085 2.88 71.093 3.864 ;
     RECT  71.021 5.088 71.129 7.272 ;
     RECT  70.585 44.208 71.132 45.768 ;
     RECT  69.721 46.992 71.132 47.832 ;
     RECT  70.765 77.904 71.153 78.504 ;
     RECT  71.021 56.112 71.165 58.872 ;
     RECT  70.877 62.64 71.197 62.664 ;
     RECT  70.931 31.152 71.221 31.176 ;
     RECT  70.733 74.016 71.228 74.088 ;
     RECT  71.129 5.088 71.237 7.08 ;
     RECT  71.237 5.376 71.267 7.08 ;
     RECT  70.441 70.272 71.269 70.296 ;
     RECT  71.132 44.208 71.273 47.832 ;
     RECT  70.261 82.416 71.273 82.44 ;
     RECT  71.228 74.016 71.315 74.664 ;
     RECT  70.733 36.528 71.341 37.464 ;
     RECT  70.801 38.688 71.341 39.912 ;
     RECT  70.769 42.72 71.341 42.744 ;
     RECT  71.053 23.472 71.381 27.384 ;
     RECT  71.089 13.008 71.413 18.216 ;
     RECT  71.153 77.904 71.413 78.648 ;
     RECT  71.093 3.168 71.417 3.864 ;
     RECT  69.109 49.104 71.42 49.56 ;
     RECT  70.645 8.496 71.489 11.976 ;
     RECT  71.381 25.536 71.489 27.384 ;
     RECT  70.661 29.136 71.489 29.256 ;
     RECT  71.381 23.472 71.525 24.552 ;
     RECT  71.489 25.776 71.525 27.384 ;
     RECT  71.197 81.024 71.525 81.048 ;
     RECT  71.413 77.904 71.597 78.696 ;
     RECT  69.257 53.136 71.629 53.16 ;
     RECT  71.525 23.472 71.633 24.264 ;
     RECT  70.739 33.6 71.797 33.624 ;
     RECT  71.269 76.176 71.797 76.2 ;
     RECT  71.597 77.904 71.797 77.928 ;
     RECT  70.979 19.248 71.809 22.344 ;
     RECT  71.633 23.472 71.809 24.216 ;
     RECT  71.797 40.992 71.809 41.016 ;
     RECT  71.057 54.384 71.809 54.456 ;
     RECT  71.341 36.528 71.845 39.912 ;
     RECT  71.489 8.784 71.948 11.976 ;
     RECT  71.413 13.008 71.948 18.264 ;
     RECT  71.269 70.272 71.953 70.824 ;
     RECT  71.165 57.696 71.989 58.872 ;
     RECT  71.809 59.856 71.989 59.88 ;
     RECT  71.701 82.608 71.989 82.824 ;
     RECT  70.661 84.048 71.989 84.12 ;
     RECT  71.809 54.144 72.025 54.456 ;
     RECT  71.989 82.608 72.205 84.12 ;
     RECT  70.733 35.28 72.229 35.304 ;
     RECT  71.845 36.336 72.229 39.912 ;
     RECT  71.809 40.944 72.229 41.64 ;
     RECT  71.267 5.52 72.236 7.08 ;
     RECT  72.205 82.608 72.277 84.36 ;
     RECT  71.417 3.312 72.313 3.864 ;
     RECT  72.236 5.52 72.313 7.416 ;
     RECT  71.629 52.8 72.313 53.16 ;
     RECT  72.025 54.144 72.313 55.224 ;
     RECT  70.877 64.032 72.313 68.376 ;
     RECT  72.229 35.28 72.349 41.64 ;
     RECT  71.341 42.72 72.349 42.792 ;
     RECT  70.729 79.68 72.349 79.704 ;
     RECT  72.241 80.928 72.349 80.952 ;
     RECT  72.349 35.28 72.373 42.792 ;
     RECT  71.273 44.208 72.373 47.208 ;
     RECT  71.197 61.872 72.385 62.664 ;
     RECT  72.313 63.792 72.385 68.376 ;
     RECT  71.221 31.152 72.457 31.56 ;
     RECT  71.42 48.24 72.457 49.56 ;
     RECT  72.385 50.592 72.457 50.616 ;
     RECT  72.313 51.936 72.469 55.224 ;
     RECT  71.165 56.352 72.469 56.616 ;
     RECT  71.953 70.272 72.469 71.304 ;
     RECT  72.313 3.312 72.601 7.416 ;
     RECT  71.948 8.784 72.601 18.264 ;
     RECT  72.601 3.312 72.608 18.264 ;
     RECT  71.809 19.248 72.608 24.216 ;
     RECT  71.525 25.776 72.608 25.8 ;
     RECT  71.525 26.784 72.608 27.384 ;
     RECT  71.489 29.232 72.608 29.256 ;
     RECT  72.457 31.152 72.608 32.52 ;
     RECT  71.797 33.6 72.608 34.2 ;
     RECT  72.373 35.28 72.608 47.208 ;
     RECT  72.457 48.24 72.608 50.616 ;
     RECT  72.469 51.936 72.608 56.616 ;
     RECT  71.989 57.696 72.608 59.88 ;
     RECT  72.385 61.872 72.608 68.376 ;
     RECT  72.469 70.272 72.608 71.4 ;
     RECT  71.315 74.016 72.608 74.04 ;
     RECT  71.797 76.176 72.608 77.928 ;
     RECT  72.349 79.68 72.608 80.952 ;
     RECT  72.277 82.608 72.608 85.224 ;
     RECT  72.608 2.148 72.712 88.572 ;
     RECT  72.712 2.304 72.904 88.302 ;
     RECT  72.904 2.304 72.965 6.936 ;
     RECT  72.904 42.672 72.965 48.264 ;
     RECT  72.904 49.776 72.965 51.096 ;
     RECT  72.904 35.28 73.001 35.304 ;
     RECT  72.904 84.048 73.073 85.224 ;
     RECT  72.904 62.16 73.109 70.248 ;
     RECT  72.904 78.672 73.109 78.936 ;
     RECT  72.904 52.416 73.145 56.616 ;
     RECT  72.904 58.944 73.145 58.968 ;
     RECT  72.904 25.776 73.181 26.904 ;
     RECT  72.904 10.368 73.235 13.032 ;
     RECT  72.904 14.064 73.235 15.576 ;
     RECT  73.235 10.368 73.325 10.776 ;
     RECT  72.904 31.776 73.361 33.096 ;
     RECT  73.145 54.144 73.361 56.616 ;
     RECT  72.904 82.8 73.397 83.064 ;
     RECT  73.361 54.144 73.433 55.704 ;
     RECT  73.109 78.912 73.433 78.936 ;
     RECT  73.433 54.384 73.469 55.704 ;
     RECT  72.904 7.92 73.523 9.144 ;
     RECT  72.965 42.672 73.541 47.304 ;
     RECT  72.904 36.432 73.571 38.856 ;
     RECT  73.361 31.776 73.577 33 ;
     RECT  73.571 38.4 73.577 38.856 ;
     RECT  73.541 43.584 73.577 47.304 ;
     RECT  73.469 54.384 73.577 55.56 ;
     RECT  72.904 23.616 73.613 23.928 ;
     RECT  72.904 34.176 73.613 34.2 ;
     RECT  73.577 38.4 73.613 38.808 ;
     RECT  73.577 54.384 73.721 55.416 ;
     RECT  73.109 62.16 73.757 65.208 ;
     RECT  72.904 76.992 73.933 77.64 ;
     RECT  73.109 66.768 73.937 70.248 ;
     RECT  73.577 31.776 73.969 32.952 ;
     RECT  73.181 25.968 73.973 26.904 ;
     RECT  72.904 74.064 73.973 74.088 ;
     RECT  73.937 66.768 74.003 69.432 ;
     RECT  72.965 2.304 74.005 5.88 ;
     RECT  72.965 6.864 74.005 6.936 ;
     RECT  73.973 26.4 74.009 26.904 ;
     RECT  74.003 66.768 74.045 68.952 ;
     RECT  73.523 7.92 74.051 8.904 ;
     RECT  72.904 40.848 74.077 41.64 ;
     RECT  72.965 50.88 74.081 51.096 ;
     RECT  72.904 80.112 74.108 80.136 ;
     RECT  74.045 66.768 74.113 68.808 ;
     RECT  73.325 10.368 74.114 10.44 ;
     RECT  72.904 21.696 74.117 22.536 ;
     RECT  74.005 2.304 74.141 6.936 ;
     RECT  74.051 7.92 74.141 8.808 ;
     RECT  72.904 75.216 74.149 75.432 ;
     RECT  74.108 80.112 74.149 80.856 ;
     RECT  72.904 16.848 74.153 16.872 ;
     RECT  73.073 84.048 74.153 84.36 ;
     RECT  74.009 26.496 74.185 26.904 ;
     RECT  74.149 28.128 74.185 28.152 ;
     RECT  74.149 75.168 74.185 75.432 ;
     RECT  73.235 11.856 74.189 13.032 ;
     RECT  72.904 19.248 74.189 19.272 ;
     RECT  74.149 80.112 74.195 81.528 ;
     RECT  74.077 40.56 74.221 41.64 ;
     RECT  74.185 71.232 74.221 71.256 ;
     RECT  74.141 2.304 74.225 8.808 ;
     RECT  74.185 75.168 74.257 76.008 ;
     RECT  74.185 26.496 74.261 28.152 ;
     RECT  74.261 26.496 74.269 27.384 ;
     RECT  73.397 82.8 74.357 82.824 ;
     RECT  73.571 36.432 74.365 37.32 ;
     RECT  74.195 81.504 74.365 81.528 ;
     RECT  74.357 82.656 74.365 82.824 ;
     RECT  74.365 35.904 74.405 37.32 ;
     RECT  74.365 81.504 74.405 82.824 ;
     RECT  74.221 70.608 74.435 71.256 ;
     RECT  73.757 62.208 74.441 65.208 ;
     RECT  74.405 35.904 74.449 35.928 ;
     RECT  74.225 2.304 74.477 5.544 ;
     RECT  73.613 23.904 74.477 23.928 ;
     RECT  73.613 38.784 74.557 38.808 ;
     RECT  73.933 76.992 74.581 77.832 ;
     RECT  74.269 26.496 74.585 26.76 ;
     RECT  74.257 74.736 74.585 76.008 ;
     RECT  74.117 21.696 74.617 22.248 ;
     RECT  72.965 49.776 74.617 49.896 ;
     RECT  74.221 40.56 74.621 42.216 ;
     RECT  74.405 82.032 74.629 82.824 ;
     RECT  74.153 84.048 74.629 84.12 ;
     RECT  73.969 31.44 74.657 32.952 ;
     RECT  74.509 86.592 74.657 86.616 ;
     RECT  74.657 31.44 74.725 32.904 ;
     RECT  73.577 46.032 74.725 46.776 ;
     RECT  73.145 52.416 74.725 53.016 ;
     RECT  74.617 49.776 74.729 50.664 ;
     RECT  74.189 11.904 74.761 13.032 ;
     RECT  73.235 14.4 74.761 15.576 ;
     RECT  74.149 60.384 74.761 60.408 ;
     RECT  74.621 41.856 74.765 42.216 ;
     RECT  74.725 52.416 74.797 53.304 ;
     RECT  73.721 54.384 74.797 54.648 ;
     RECT  74.441 62.208 74.828 63.528 ;
     RECT  74.797 52.416 74.837 54.648 ;
     RECT  74.761 60.384 74.837 61.032 ;
     RECT  74.617 18.576 74.869 18.6 ;
     RECT  74.761 72.912 74.873 72.936 ;
     RECT  74.617 21.12 74.905 22.248 ;
     RECT  74.828 62.064 74.915 63.528 ;
     RECT  74.765 42.192 74.963 42.216 ;
     RECT  74.905 21.072 75.017 22.248 ;
     RECT  74.113 66.72 75.017 68.808 ;
     RECT  74.581 76.992 75.017 77.88 ;
     RECT  74.441 64.752 75.085 65.208 ;
     RECT  74.905 80.016 75.085 80.04 ;
     RECT  75.017 21.12 75.089 22.248 ;
     RECT  75.013 71.808 75.097 71.832 ;
     RECT  74.405 37.2 75.125 37.32 ;
     RECT  74.837 53.568 75.125 54.648 ;
     RECT  73.577 43.584 75.157 44.472 ;
     RECT  75.017 76.992 75.157 77.592 ;
     RECT  75.085 79.968 75.157 80.04 ;
     RECT  74.114 10.416 75.161 10.44 ;
     RECT  74.725 46.032 75.193 47.208 ;
     RECT  74.729 50.592 75.197 50.664 ;
     RECT  74.585 74.736 75.197 75.192 ;
     RECT  74.477 3.408 75.212 5.544 ;
     RECT  74.225 6.912 75.212 8.808 ;
     RECT  75.157 43.536 75.229 44.472 ;
     RECT  75.193 46.032 75.229 47.256 ;
     RECT  74.629 82.032 75.233 84.12 ;
     RECT  74.761 11.904 75.251 15.576 ;
     RECT  75.212 3.408 75.299 8.808 ;
     RECT  74.621 40.56 75.301 40.872 ;
     RECT  74.837 52.416 75.305 52.44 ;
     RECT  75.251 14.592 75.373 15.576 ;
     RECT  75.229 42.288 75.373 47.256 ;
     RECT  75.157 76.368 75.377 77.592 ;
     RECT  75.373 14.592 75.413 16.392 ;
     RECT  75.157 79.968 75.481 80.088 ;
     RECT  75.233 82.032 75.481 84.072 ;
     RECT  75.251 11.904 75.517 13.032 ;
     RECT  74.477 2.304 75.553 2.328 ;
     RECT  75.299 3.408 75.553 5.88 ;
     RECT  75.089 21.408 75.589 22.248 ;
     RECT  75.553 2.304 75.593 5.88 ;
     RECT  74.435 70.608 75.685 70.632 ;
     RECT  75.685 70.032 75.731 70.632 ;
     RECT  74.725 31.152 75.733 32.904 ;
     RECT  75.085 64.752 75.733 65.736 ;
     RECT  75.017 66.72 75.733 68.28 ;
     RECT  75.731 70.032 75.773 70.056 ;
     RECT  75.413 16.368 75.805 16.392 ;
     RECT  72.904 57.696 75.805 57.72 ;
     RECT  75.733 64.752 75.827 68.28 ;
     RECT  75.481 79.968 75.841 84.072 ;
     RECT  75.377 76.992 75.845 77.592 ;
     RECT  75.125 53.568 75.849 54.408 ;
     RECT  75.373 42.288 75.877 47.88 ;
     RECT  75.661 49.056 75.877 49.08 ;
     RECT  75.841 79.728 75.877 84.072 ;
     RECT  75.517 11.328 75.881 13.032 ;
     RECT  74.837 61.008 75.881 61.032 ;
     RECT  74.585 26.496 75.953 26.52 ;
     RECT  75.96 26.208 75.98 26.232 ;
     RECT  75.845 77.52 75.98 77.592 ;
     RECT  75.877 78.912 75.98 84.072 ;
     RECT  75.413 14.592 75.989 14.616 ;
     RECT  75.733 31.152 75.989 33.576 ;
     RECT  75.593 2.736 76.019 5.88 ;
     RECT  75.98 25.392 76.021 26.232 ;
     RECT  75.589 21.408 76.025 22.776 ;
     RECT  75.625 51.696 76.025 51.816 ;
     RECT  75.827 64.752 76.025 66.84 ;
     RECT  74.915 62.112 76.061 63.528 ;
     RECT  76.025 64.752 76.061 66.744 ;
     RECT  75.299 7.296 76.097 8.808 ;
     RECT  75.805 57.024 76.117 57.72 ;
     RECT  75.989 31.44 76.133 33.576 ;
     RECT  76.061 64.752 76.133 65.736 ;
     RECT  75.98 77.52 76.169 84.072 ;
     RECT  76.133 33.072 76.205 33.576 ;
     RECT  75.661 74.688 76.205 74.712 ;
     RECT  75.877 42.288 76.241 49.08 ;
     RECT  76.169 77.52 76.241 83.4 ;
     RECT  76.133 31.44 76.349 31.992 ;
     RECT  76.241 77.52 76.349 82.2 ;
     RECT  75.193 72.288 76.355 72.312 ;
     RECT  76.241 45.216 76.403 49.08 ;
     RECT  75.197 50.592 76.417 50.616 ;
     RECT  76.019 2.736 76.421 2.76 ;
     RECT  76.241 83.28 76.421 83.4 ;
     RECT  76.417 50.256 76.453 50.616 ;
     RECT  75.697 37.488 76.525 37.512 ;
     RECT  76.025 21.408 76.529 22.296 ;
     RECT  75.301 39.888 76.565 40.872 ;
     RECT  75.827 68.256 76.565 68.28 ;
     RECT  76.097 7.968 76.597 8.808 ;
     RECT  75.881 11.328 76.597 11.352 ;
     RECT  76.529 21.408 76.601 21.528 ;
     RECT  76.117 57.024 76.601 58.152 ;
     RECT  76.349 79.968 76.601 82.2 ;
     RECT  74.869 18.432 76.633 18.6 ;
     RECT  76.597 10.896 76.637 11.352 ;
     RECT  76.021 25.152 76.637 26.232 ;
     RECT  76.637 25.152 76.681 25.656 ;
     RECT  76.309 73.536 76.705 73.56 ;
     RECT  76.601 21.504 76.709 21.528 ;
     RECT  75.733 35.136 76.709 35.16 ;
     RECT  76.453 50.256 76.777 50.664 ;
     RECT  76.601 57.408 76.777 58.152 ;
     RECT  76.061 62.112 76.817 63.096 ;
     RECT  76.633 18.288 76.844 18.6 ;
     RECT  76.844 18.24 76.849 18.6 ;
     RECT  76.021 19.824 76.849 19.848 ;
     RECT  76.525 37.392 76.849 37.512 ;
     RECT  76.241 42.288 76.849 43.656 ;
     RECT  76.403 45.216 76.853 47.352 ;
     RECT  76.061 66.72 76.853 66.744 ;
     RECT  76.849 18.24 76.885 19.848 ;
     RECT  75.733 75.936 76.933 75.96 ;
     RECT  76.705 72.912 76.961 73.56 ;
     RECT  76.933 75.792 76.979 75.96 ;
     RECT  76.417 52.224 76.993 52.248 ;
     RECT  75.849 53.376 76.993 54.408 ;
     RECT  76.133 64.752 76.997 65.4 ;
     RECT  76.705 70.608 76.997 70.632 ;
     RECT  76.637 10.896 77.093 10.92 ;
     RECT  76.403 48.48 77.101 49.08 ;
     RECT  76.777 50.256 77.101 51.096 ;
     RECT  76.849 42.24 77.209 43.656 ;
     RECT  76.777 57.408 77.209 58.44 ;
     RECT  76.997 64.752 77.281 65.16 ;
     RECT  76.349 31.44 77.317 31.464 ;
     RECT  76.681 25.152 77.389 25.176 ;
     RECT  76.849 36.624 77.389 37.512 ;
     RECT  76.349 77.52 77.42 78.936 ;
     RECT  76.601 79.968 77.42 80.904 ;
     RECT  75.805 16.368 77.425 16.68 ;
     RECT  77.281 85.44 77.425 85.464 ;
     RECT  77.425 15.552 77.461 16.68 ;
     RECT  76.885 18.096 77.461 19.848 ;
     RECT  76.019 3.984 77.497 5.88 ;
     RECT  76.993 52.224 77.497 54.408 ;
     RECT  77.389 36.336 77.509 37.512 ;
     RECT  77.425 85.2 77.569 85.464 ;
     RECT  77.425 86.544 77.569 86.568 ;
     RECT  77.389 25.104 77.641 25.176 ;
     RECT  77.641 24.432 77.749 25.176 ;
     RECT  77.497 3.984 77.785 6.84 ;
     RECT  76.597 7.968 77.785 9.672 ;
     RECT  77.093 10.848 77.785 10.92 ;
     RECT  77.461 15.552 77.821 19.848 ;
     RECT  77.509 35.28 77.885 35.304 ;
     RECT  77.885 35.28 77.893 35.352 ;
     RECT  77.749 24.432 77.929 25.56 ;
     RECT  77.317 31.44 77.929 31.752 ;
     RECT  76.601 81.984 77.929 82.2 ;
     RECT  76.421 83.28 77.929 83.304 ;
     RECT  77.453 55.872 77.965 55.896 ;
     RECT  77.209 57.408 77.965 58.68 ;
     RECT  77.929 81.984 78.001 83.304 ;
     RECT  77.389 2.256 78.008 2.28 ;
     RECT  77.785 3.984 78.008 10.92 ;
     RECT  75.881 12.48 78.008 13.032 ;
     RECT  77.821 14.736 78.008 19.848 ;
     RECT  77.641 21.408 78.008 21.432 ;
     RECT  77.893 22.464 78.008 22.488 ;
     RECT  77.929 24.432 78.008 26.088 ;
     RECT  77.677 27.312 78.008 27.336 ;
     RECT  77.929 31.152 78.008 31.752 ;
     RECT  76.205 33.552 78.008 33.576 ;
     RECT  77.893 34.656 78.008 35.352 ;
     RECT  77.509 36.336 78.008 38.424 ;
     RECT  76.565 40.848 78.008 40.872 ;
     RECT  77.209 42.24 78.008 44.424 ;
     RECT  76.853 45.696 78.008 47.352 ;
     RECT  77.101 48.48 78.008 51.096 ;
     RECT  77.497 52.176 78.008 54.408 ;
     RECT  77.965 55.872 78.008 58.68 ;
     RECT  76.777 60.096 78.008 60.12 ;
     RECT  76.817 62.448 78.008 63.096 ;
     RECT  77.281 64.368 78.008 65.16 ;
     RECT  77.569 68.928 78.008 68.952 ;
     RECT  76.961 72.912 78.008 72.936 ;
     RECT  77.173 74.544 78.008 74.568 ;
     RECT  76.979 75.792 78.008 75.816 ;
     RECT  77.42 77.52 78.008 80.904 ;
     RECT  78.001 81.936 78.008 83.304 ;
     RECT  77.569 85.2 78.008 86.568 ;
     RECT  78.008 2.148 78.112 88.572 ;
     RECT  78.112 2.256 78.304 88.302 ;
     RECT  78.304 25.536 78.419 25.56 ;
     RECT  78.304 75.792 78.419 78.168 ;
     RECT  78.304 10.272 78.437 10.344 ;
     RECT  78.304 61.104 78.437 61.128 ;
     RECT  78.304 11.424 78.467 20.04 ;
     RECT  78.304 30.816 78.473 34.68 ;
     RECT  78.304 36.288 78.473 36.36 ;
     RECT  78.304 64.32 78.473 65.16 ;
     RECT  78.304 85.152 78.473 85.224 ;
     RECT  78.304 2.256 78.509 2.28 ;
     RECT  78.467 11.424 78.545 14.136 ;
     RECT  78.467 15.552 78.617 20.04 ;
     RECT  78.473 36.336 78.653 36.36 ;
     RECT  78.617 15.552 78.689 18.264 ;
     RECT  78.617 19.296 78.689 20.04 ;
     RECT  78.304 3.312 78.707 8.808 ;
     RECT  78.304 68.928 78.725 68.952 ;
     RECT  78.707 4.272 78.733 4.296 ;
     RECT  78.304 50.112 78.869 59.256 ;
     RECT  78.304 79.728 78.869 80.328 ;
     RECT  78.473 85.152 78.869 85.176 ;
     RECT  78.419 76.464 78.905 78.168 ;
     RECT  78.304 87.12 78.905 87.144 ;
     RECT  78.869 51.984 78.941 59.256 ;
     RECT  78.689 15.552 78.977 15.576 ;
     RECT  78.304 46.752 79.013 47.592 ;
     RECT  78.941 51.984 79.013 55.56 ;
     RECT  78.707 5.472 79.049 8.808 ;
     RECT  79.049 6.24 79.057 8.808 ;
     RECT  78.304 38.4 79.085 38.76 ;
     RECT  79.013 52.176 79.085 55.56 ;
     RECT  78.304 24.192 79.121 24.504 ;
     RECT  78.304 40.176 79.121 43.656 ;
     RECT  78.304 62.112 79.121 63.24 ;
     RECT  78.689 19.344 79.157 20.04 ;
     RECT  78.473 64.32 79.229 64.344 ;
     RECT  79.121 40.176 79.235 41.976 ;
     RECT  79.085 38.736 79.297 38.76 ;
     RECT  79.121 43.008 79.301 43.656 ;
     RECT  78.869 50.112 79.337 50.856 ;
     RECT  78.304 45.024 79.405 45.576 ;
     RECT  78.941 56.544 79.409 59.256 ;
     RECT  79.405 45.024 79.441 45.72 ;
     RECT  79.057 6.672 79.445 8.808 ;
     RECT  78.473 30.816 79.445 34.248 ;
     RECT  78.905 76.896 79.477 78.168 ;
     RECT  79.409 58.704 79.481 59.016 ;
     RECT  79.301 43.056 79.513 43.656 ;
     RECT  79.337 50.112 79.532 50.232 ;
     RECT  79.477 76.896 79.585 78.216 ;
     RECT  79.532 49.536 79.619 50.232 ;
     RECT  78.689 16.656 79.625 18.072 ;
     RECT  79.513 43.056 79.657 43.704 ;
     RECT  79.441 44.976 79.693 45.72 ;
     RECT  79.625 16.944 79.697 18.072 ;
     RECT  78.545 12.48 79.729 14.136 ;
     RECT  79.513 37.056 79.733 37.08 ;
     RECT  79.697 18.048 79.765 18.072 ;
     RECT  79.657 43.056 79.765 43.848 ;
     RECT  79.693 44.832 79.765 45.72 ;
     RECT  79.445 33.6 79.769 34.248 ;
     RECT  79.121 62.688 79.769 63.24 ;
     RECT  79.445 6.768 79.801 8.808 ;
     RECT  78.437 10.272 79.801 10.296 ;
     RECT  79.765 43.056 79.805 45.72 ;
     RECT  79.805 43.056 79.811 45 ;
     RECT  79.157 19.344 79.841 19.368 ;
     RECT  79.445 30.816 79.841 32.568 ;
     RECT  79.585 76.896 79.873 78.504 ;
     RECT  78.869 79.728 79.873 79.896 ;
     RECT  79.841 30.816 79.877 31.992 ;
     RECT  79.477 35.424 79.877 35.448 ;
     RECT  78.545 11.424 79.901 11.448 ;
     RECT  79.729 12.48 79.901 14.808 ;
     RECT  79.901 11.424 79.985 14.808 ;
     RECT  79.697 16.944 80.021 17.016 ;
     RECT  79.121 24.192 80.165 24.216 ;
     RECT  79.873 76.896 80.165 79.896 ;
     RECT  79.765 85.44 80.197 85.464 ;
     RECT  79.801 6.768 80.201 10.296 ;
     RECT  79.297 38.736 80.201 39.336 ;
     RECT  79.801 86.88 80.201 86.904 ;
     RECT  79.769 33.6 80.237 33.624 ;
     RECT  80.021 16.992 80.273 17.016 ;
     RECT  79.481 58.992 80.273 59.016 ;
     RECT  79.981 68.928 80.273 68.952 ;
     RECT  79.693 2.256 80.309 2.904 ;
     RECT  79.945 25.872 80.413 25.896 ;
     RECT  79.085 52.176 80.413 55.224 ;
     RECT  80.201 39.216 80.417 39.24 ;
     RECT  79.945 71.328 80.449 71.352 ;
     RECT  80.201 8.784 80.453 10.296 ;
     RECT  80.413 25.728 80.489 25.896 ;
     RECT  79.409 56.544 80.489 57.72 ;
     RECT  80.197 85.392 80.521 85.464 ;
     RECT  80.309 2.88 80.525 2.904 ;
     RECT  79.765 18.048 80.525 18.264 ;
     RECT  79.877 30.864 80.525 31.992 ;
     RECT  79.985 12.48 80.557 14.808 ;
     RECT  80.521 85.248 80.593 85.464 ;
     RECT  80.557 12.48 80.629 14.856 ;
     RECT  79.619 50.016 80.629 50.232 ;
     RECT  80.413 52.176 80.633 55.32 ;
     RECT  79.985 11.424 80.665 11.448 ;
     RECT  79.235 41.28 80.665 41.976 ;
     RECT  80.489 25.728 80.669 25.752 ;
     RECT  80.629 12.48 80.675 15.432 ;
     RECT  80.525 18.24 80.675 18.264 ;
     RECT  80.665 41.28 80.701 42.072 ;
     RECT  79.811 43.056 80.701 43.896 ;
     RECT  78.304 81.792 80.701 83.64 ;
     RECT  80.593 85.248 80.701 85.704 ;
     RECT  80.629 50.016 80.737 50.472 ;
     RECT  80.633 52.176 80.737 55.176 ;
     RECT  80.165 76.896 80.741 79.752 ;
     RECT  80.701 41.28 80.773 43.896 ;
     RECT  80.665 10.848 80.777 11.448 ;
     RECT  80.701 81.792 80.777 85.704 ;
     RECT  80.773 40.848 80.849 43.896 ;
     RECT  80.777 81.792 80.849 85.416 ;
     RECT  80.413 74.4 80.881 74.424 ;
     RECT  80.849 40.848 80.885 42.072 ;
     RECT  79.769 62.736 80.917 63.24 ;
     RECT  80.849 81.792 80.957 85.272 ;
     RECT  80.449 70.992 80.989 71.352 ;
     RECT  80.737 50.016 80.993 55.176 ;
     RECT  80.917 61.968 81.025 63.24 ;
     RECT  80.881 74.4 81.029 74.616 ;
     RECT  80.741 77.088 81.029 79.752 ;
     RECT  80.885 40.848 81.061 41.304 ;
     RECT  80.201 6.768 81.065 6.84 ;
     RECT  80.453 8.784 81.065 9.672 ;
     RECT  80.957 83.616 81.101 85.272 ;
     RECT  79.013 46.752 81.164 47.4 ;
     RECT  81.065 8.784 81.169 8.808 ;
     RECT  81.029 79.44 81.169 79.752 ;
     RECT  80.989 70.992 81.173 71.496 ;
     RECT  81.101 83.616 81.173 84.408 ;
     RECT  81.164 46.32 81.205 47.4 ;
     RECT  80.917 68.736 81.241 68.76 ;
     RECT  81.173 70.992 81.281 71.016 ;
     RECT  80.849 43.056 81.313 43.896 ;
     RECT  81.169 79.44 81.313 79.944 ;
     RECT  81.241 68.4 81.353 68.76 ;
     RECT  81.029 77.088 81.353 78.36 ;
     RECT  78.304 29.808 81.389 29.832 ;
     RECT  80.489 56.688 81.445 57.72 ;
     RECT  80.557 28.416 81.457 28.44 ;
     RECT  81.205 46.32 81.457 47.928 ;
     RECT  80.701 60.96 81.457 60.984 ;
     RECT  81.025 61.968 81.457 63.816 ;
     RECT  80.675 12.528 81.461 15.432 ;
     RECT  80.773 33.072 81.491 33.096 ;
     RECT  81.445 56.688 81.493 58.104 ;
     RECT  81.313 79.44 81.497 80.04 ;
     RECT  81.457 28.272 81.529 28.44 ;
     RECT  81.313 37.968 81.533 38.184 ;
     RECT  81.061 40.608 81.565 41.304 ;
     RECT  81.497 80.016 81.569 80.04 ;
     RECT  81.029 74.592 81.605 74.616 ;
     RECT  81.457 60.96 81.713 63.816 ;
     RECT  81.461 13.056 81.827 15.432 ;
     RECT  81.565 40.56 81.857 41.304 ;
     RECT  81.713 61.2 81.857 63.816 ;
     RECT  80.957 81.792 81.877 82.2 ;
     RECT  80.993 50.016 81.893 55.032 ;
     RECT  80.917 5.712 81.961 5.736 ;
     RECT  81.065 6.768 81.961 6.792 ;
     RECT  81.601 19.344 81.961 19.368 ;
     RECT  80.525 30.864 81.961 31.848 ;
     RECT  81.857 40.896 81.965 41.304 ;
     RECT  81.457 25.536 81.997 25.56 ;
     RECT  81.877 81.312 81.997 82.2 ;
     RECT  81.893 52.176 82.033 55.032 ;
     RECT  81.493 56.688 82.033 58.68 ;
     RECT  81.169 8.544 82.037 8.808 ;
     RECT  81.313 43.056 82.069 43.992 ;
     RECT  81.457 46.08 82.069 47.928 ;
     RECT  81.893 50.016 82.073 51.192 ;
     RECT  81.961 18.816 82.105 19.368 ;
     RECT  81.533 38.16 82.105 38.184 ;
     RECT  81.353 77.088 82.105 78.216 ;
     RECT  80.917 4.512 82.109 4.536 ;
     RECT  82.033 52.176 82.145 58.68 ;
     RECT  82.145 52.512 82.181 58.68 ;
     RECT  81.173 84.336 82.181 84.408 ;
     RECT  81.961 5.712 82.213 6.792 ;
     RECT  82.037 8.784 82.213 8.808 ;
     RECT  82.069 42.768 82.253 43.992 ;
     RECT  82.105 77.04 82.253 78.216 ;
     RECT  81.857 61.632 82.285 63.816 ;
     RECT  81.349 2.736 82.316 2.76 ;
     RECT  81.529 28.224 82.325 28.44 ;
     RECT  82.181 57.696 82.325 58.68 ;
     RECT  81.827 13.632 82.357 15.432 ;
     RECT  82.069 46.08 82.357 48.504 ;
     RECT  82.181 52.512 82.361 56.712 ;
     RECT  81.961 30.864 82.364 31.944 ;
     RECT  81.997 25.488 82.397 25.56 ;
     RECT  82.316 2.256 82.403 2.76 ;
     RECT  82.357 13.632 82.403 15.576 ;
     RECT  82.364 30.768 82.405 31.944 ;
     RECT  82.285 61.632 82.429 63.912 ;
     RECT  82.405 30.192 82.433 31.944 ;
     RECT  80.777 11.424 82.453 11.448 ;
     RECT  82.357 46.08 82.46 48.744 ;
     RECT  82.537 79.728 82.573 79.752 ;
     RECT  82.105 38.16 82.609 38.712 ;
     RECT  81.965 41.28 82.609 41.304 ;
     RECT  82.253 42.768 82.609 43.944 ;
     RECT  82.033 85.68 82.609 85.704 ;
     RECT  82.609 38.16 82.681 39.096 ;
     RECT  81.445 34.08 82.693 34.104 ;
     RECT  82.681 37.392 82.717 39.096 ;
     RECT  82.213 5.088 82.933 6.792 ;
     RECT  82.717 37.248 82.933 39.096 ;
     RECT  81.997 81.312 82.933 82.68 ;
     RECT  82.213 8.784 82.969 8.856 ;
     RECT  82.429 61.632 82.969 64.152 ;
     RECT  82.403 15.504 82.988 15.576 ;
     RECT  78.304 21.408 83.005 21.432 ;
     RECT  82.933 78.432 83.077 78.456 ;
     RECT  82.969 61.104 83.113 64.152 ;
     RECT  82.46 46.08 83.141 49.56 ;
     RECT  82.933 5.088 83.173 6.84 ;
     RECT  82.403 2.736 83.185 2.76 ;
     RECT  83.173 3.936 83.185 6.84 ;
     RECT  82.609 41.28 83.221 43.944 ;
     RECT  83.141 46.08 83.269 49.608 ;
     RECT  82.073 50.592 83.269 51.192 ;
     RECT  82.361 52.512 83.269 55.944 ;
     RECT  83.221 40.944 83.293 43.944 ;
     RECT  82.105 18.72 83.329 19.368 ;
     RECT  83.293 22.752 83.329 22.776 ;
     RECT  82.609 85.68 83.329 85.752 ;
     RECT  83.185 2.736 83.408 6.84 ;
     RECT  82.969 8.784 83.408 9.816 ;
     RECT  82.453 11.424 83.408 12.312 ;
     RECT  82.403 13.632 83.408 14.184 ;
     RECT  82.988 15.504 83.408 16.44 ;
     RECT  83.329 18.432 83.408 19.368 ;
     RECT  83.005 20.544 83.408 21.432 ;
     RECT  83.329 22.752 83.408 23.16 ;
     RECT  83.005 24.528 83.408 25.032 ;
     RECT  82.325 28.416 83.408 28.44 ;
     RECT  82.433 30.192 83.408 31.368 ;
     RECT  82.693 33.648 83.408 34.104 ;
     RECT  83.365 35.76 83.408 35.784 ;
     RECT  82.933 37.248 83.408 39.288 ;
     RECT  83.293 40.608 83.408 43.944 ;
     RECT  79.811 44.976 83.408 45 ;
     RECT  83.269 46.08 83.408 55.944 ;
     RECT  82.325 57.696 83.408 58.104 ;
     RECT  82.501 59.184 83.408 59.208 ;
     RECT  83.113 60.912 83.408 64.152 ;
     RECT  81.353 68.4 83.408 68.424 ;
     RECT  83.149 75.36 83.408 75.384 ;
     RECT  82.253 77.04 83.408 77.352 ;
     RECT  83.077 78.432 83.408 78.504 ;
     RECT  82.573 79.728 83.408 80.28 ;
     RECT  82.933 81.312 83.408 82.968 ;
     RECT  82.181 84.336 83.408 84.36 ;
     RECT  83.329 85.392 83.408 85.752 ;
     RECT  83.408 2.148 83.512 88.572 ;
     RECT  83.512 2.418 83.704 88.302 ;
     RECT  83.704 54.672 83.837 55.8 ;
     RECT  83.704 32.352 83.843 33.096 ;
     RECT  83.704 45.6 83.873 48.744 ;
     RECT  83.704 50.16 83.873 50.616 ;
     RECT  83.704 82.944 83.881 85.752 ;
     RECT  83.704 3.408 83.981 3.432 ;
     RECT  83.704 65.52 83.981 65.544 ;
     RECT  83.704 40.56 84.017 43.944 ;
     RECT  83.704 8.544 84.028 10.296 ;
     RECT  83.704 30.576 84.053 31.32 ;
     RECT  83.704 57.072 84.083 60.024 ;
     RECT  83.704 61.104 84.083 63.096 ;
     RECT  84.017 40.56 84.089 42.696 ;
     RECT  84.083 58.896 84.124 60.024 ;
     RECT  83.873 50.16 84.125 50.424 ;
     RECT  83.704 78.48 84.161 81.48 ;
     RECT  83.873 46.896 84.197 48.744 ;
     RECT  83.837 54.672 84.197 55.272 ;
     RECT  84.089 40.56 84.233 41.976 ;
     RECT  83.843 33.072 84.305 33.096 ;
     RECT  84.197 54.72 84.305 55.272 ;
     RECT  84.161 80.16 84.323 81.48 ;
     RECT  83.704 35.712 84.377 35.784 ;
     RECT  84.083 57.072 84.377 57.72 ;
     RECT  83.704 4.512 84.413 6.936 ;
     RECT  83.704 25.008 84.485 25.128 ;
     RECT  83.881 84.384 84.485 85.752 ;
     RECT  83.704 21.072 84.521 22.872 ;
     RECT  83.881 82.944 84.521 82.968 ;
     RECT  84.521 21.072 84.593 21.432 ;
     RECT  84.233 40.56 84.593 41.928 ;
     RECT  83.704 72.912 84.593 73.32 ;
     RECT  84.413 4.512 84.652 6.84 ;
     RECT  84.161 78.48 84.665 78.84 ;
     RECT  84.323 80.448 84.665 81.48 ;
     RECT  84.593 40.896 84.701 41.928 ;
     RECT  83.704 34.08 84.733 34.104 ;
     RECT  84.652 5.088 84.773 6.84 ;
     RECT  83.704 11.328 84.773 12.024 ;
     RECT  84.485 25.104 84.809 25.128 ;
     RECT  84.485 84.384 84.809 85.704 ;
     RECT  84.028 8.544 84.953 10.248 ;
     RECT  83.704 37.68 84.953 39.288 ;
     RECT  84.733 34.08 84.985 34.728 ;
     RECT  83.704 13.68 84.989 15.576 ;
     RECT  83.873 45.6 84.989 45.624 ;
     RECT  84.083 62.304 84.989 63.096 ;
     RECT  83.704 27.216 85.097 27.432 ;
     RECT  84.017 43.92 85.097 43.944 ;
     RECT  84.953 37.68 85.133 38.952 ;
     RECT  84.701 41.088 85.133 41.928 ;
     RECT  85.133 37.68 85.165 38.856 ;
     RECT  84.989 14.16 85.169 15.576 ;
     RECT  84.305 54.72 85.169 55.176 ;
     RECT  84.989 62.304 85.169 62.76 ;
     RECT  84.124 58.896 85.201 59.496 ;
     RECT  84.805 60.816 85.201 60.84 ;
     RECT  85.097 27.216 85.205 27.24 ;
     RECT  85.165 37.248 85.205 38.856 ;
     RECT  84.665 80.448 85.205 80.952 ;
     RECT  84.125 50.16 85.237 50.184 ;
     RECT  83.704 77.328 85.237 77.352 ;
     RECT  85.169 54.72 85.241 54.984 ;
     RECT  84.377 57.696 85.273 57.72 ;
     RECT  83.704 74.592 85.273 74.616 ;
     RECT  85.201 58.896 85.277 60.84 ;
     RECT  85.237 77.328 85.277 77.448 ;
     RECT  84.053 30.576 85.349 30.936 ;
     RECT  84.197 46.896 85.349 48.504 ;
     RECT  84.953 9.216 85.385 10.248 ;
     RECT  83.704 64.368 85.385 64.392 ;
     RECT  85.273 57.696 85.453 57.864 ;
     RECT  85.277 58.896 85.453 59.304 ;
     RECT  85.201 35.856 85.457 35.88 ;
     RECT  85.205 37.248 85.457 38.328 ;
     RECT  84.593 72.912 85.457 72.936 ;
     RECT  85.277 77.424 85.477 77.448 ;
     RECT  84.665 78.48 85.477 78.504 ;
     RECT  84.521 22.848 85.493 22.872 ;
     RECT  85.457 37.248 85.493 38.136 ;
     RECT  85.277 60.336 85.493 60.84 ;
     RECT  85.237 50.16 85.529 50.616 ;
     RECT  84.809 84.384 85.529 84.888 ;
     RECT  85.493 60.336 85.565 60.36 ;
     RECT  85.381 52.992 85.571 53.016 ;
     RECT  85.489 64.416 85.573 64.44 ;
     RECT  85.477 77.424 85.584 78.504 ;
     RECT  84.773 6.816 85.669 6.84 ;
     RECT  85.385 9.216 85.673 9.24 ;
     RECT  85.349 46.896 85.709 46.92 ;
     RECT  83.704 18.96 85.713 18.984 ;
     RECT  84.913 17.088 85.717 17.112 ;
     RECT  85.713 18.96 85.717 19.128 ;
     RECT  85.717 16.512 85.763 17.112 ;
     RECT  85.169 14.16 85.778 14.712 ;
     RECT  85.717 18.192 85.813 19.128 ;
     RECT  85.584 77.52 85.817 78.504 ;
     RECT  85.669 6.816 85.849 7.464 ;
     RECT  84.593 21.408 85.849 21.432 ;
     RECT  85.349 48.096 85.849 48.504 ;
     RECT  84.773 5.088 85.853 5.112 ;
     RECT  84.773 11.328 85.853 11.352 ;
     RECT  85.813 18.048 85.853 19.128 ;
     RECT  85.853 18.048 85.961 18.072 ;
     RECT  85.525 25.008 85.961 25.032 ;
     RECT  85.493 37.68 85.961 38.136 ;
     RECT  85.453 57.696 85.961 59.304 ;
     RECT  85.853 19.104 86.005 19.128 ;
     RECT  85.669 70.8 86.029 70.824 ;
     RECT  86.005 19.104 86.051 19.944 ;
     RECT  85.849 21.216 86.051 21.432 ;
     RECT  84.985 34.08 86.065 34.776 ;
     RECT  85.961 57.696 86.065 57.72 ;
     RECT  85.993 13.056 86.101 13.08 ;
     RECT  85.849 6.144 86.105 7.464 ;
     RECT  86.051 19.92 86.141 19.944 ;
     RECT  85.993 25.152 86.177 25.176 ;
     RECT  85.529 50.16 86.177 50.568 ;
     RECT  85.529 84.384 86.213 84.408 ;
     RECT  86.065 57.072 86.249 57.72 ;
     RECT  85.133 41.088 86.281 41.736 ;
     RECT  86.051 21.216 86.321 21.24 ;
     RECT  85.205 80.928 86.339 80.952 ;
     RECT  85.849 48.096 86.353 49.032 ;
     RECT  86.065 34.08 86.357 35.496 ;
     RECT  86.293 79.728 86.38 79.752 ;
     RECT  86.281 41.088 86.389 42.024 ;
     RECT  86.105 6.144 86.429 6.168 ;
     RECT  85.961 37.92 86.465 38.136 ;
     RECT  86.389 40.176 86.465 42.024 ;
     RECT  86.249 57.072 86.465 57.096 ;
     RECT  85.349 30.768 86.533 30.936 ;
     RECT  85.129 44.448 86.533 44.472 ;
     RECT  86.065 46.368 86.533 46.392 ;
     RECT  85.241 54.96 86.569 54.984 ;
     RECT  86.101 12.528 86.605 13.08 ;
     RECT  85.273 74.592 86.609 75.144 ;
     RECT  86.533 43.872 86.627 44.472 ;
     RECT  85.961 59.184 86.641 59.304 ;
     RECT  85.169 62.736 86.645 62.76 ;
     RECT  86.569 54.96 86.677 55.752 ;
     RECT  85.957 8.544 86.681 8.568 ;
     RECT  86.605 11.664 86.681 13.08 ;
     RECT  86.533 45.552 86.681 46.392 ;
     RECT  86.461 63.744 86.681 63.768 ;
     RECT  86.533 29.856 86.713 30.936 ;
     RECT  86.029 70.8 86.753 71.208 ;
     RECT  86.677 54.672 86.789 55.752 ;
     RECT  85.385 10.224 86.825 10.248 ;
     RECT  86.789 54.96 86.825 55.752 ;
     RECT  86.681 11.664 86.861 12.552 ;
     RECT  86.825 55.728 86.861 55.752 ;
     RECT  86.713 29.856 86.897 31.272 ;
     RECT  86.465 40.176 86.897 41.112 ;
     RECT  86.353 47.808 86.897 49.032 ;
     RECT  85.817 77.52 86.933 77.544 ;
     RECT  86.641 59.184 86.965 59.928 ;
     RECT  86.965 59.184 86.969 60.456 ;
     RECT  86.897 30.816 87.001 31.272 ;
     RECT  86.627 44.448 87.041 44.472 ;
     RECT  86.681 46.368 87.073 46.392 ;
     RECT  87.001 30.816 87.085 31.368 ;
     RECT  87.073 46.368 87.113 46.92 ;
     RECT  87.013 24.48 87.137 24.504 ;
     RECT  85.778 14.208 87.149 14.712 ;
     RECT  86.969 60.432 87.149 60.456 ;
     RECT  86.609 74.928 87.149 75.144 ;
     RECT  86.357 35.472 87.185 35.496 ;
     RECT  86.969 59.184 87.203 59.208 ;
     RECT  86.105 7.44 87.221 7.464 ;
     RECT  87.137 23.952 87.221 24.504 ;
     RECT  87.157 58.128 87.257 58.152 ;
     RECT  86.465 38.112 87.293 38.136 ;
     RECT  86.897 40.176 87.293 40.2 ;
     RECT  87.221 24.48 87.329 24.504 ;
     RECT  85.763 16.512 87.365 16.536 ;
     RECT  87.085 30.816 87.365 30.84 ;
     RECT  87.181 36.48 87.452 36.504 ;
     RECT  86.861 11.664 87.473 11.688 ;
     RECT  87.149 14.208 87.473 14.232 ;
     RECT  86.533 42.768 87.473 42.792 ;
     RECT  86.897 48.48 87.473 49.032 ;
     RECT  87.473 48.48 87.509 48.504 ;
     RECT  86.821 72.768 87.509 72.792 ;
     RECT  87.149 75.12 87.509 75.144 ;
     RECT  86.357 34.08 87.538 34.104 ;
     RECT  87.538 34.08 87.539 34.152 ;
     RECT  87.452 35.664 87.539 36.504 ;
     RECT  87.109 52.464 87.545 52.488 ;
     RECT  87.469 20.928 87.653 20.952 ;
     RECT  87.539 34.128 87.689 34.152 ;
     RECT  87.113 46.896 87.869 46.92 ;
     RECT  87.793 37.056 87.941 37.08 ;
    LAYER M5 ;
     RECT  5.088 0.016 29.592 0.085 ;
     RECT  5.088 0.085 29.928 0.133 ;
     RECT  5.088 0.133 30.648 1.763 ;
     RECT  35.76 2.005 35.784 2.053 ;
     RECT  35.76 2.053 36.6 2.101 ;
     RECT  35.712 2.101 36.6 2.137 ;
     RECT  2.4 2.137 2.52 2.151 ;
     RECT  40.2 2.137 40.32 2.151 ;
     RECT  45.6 2.137 45.72 2.151 ;
     RECT  51 2.137 51.12 2.151 ;
     RECT  56.4 2.137 56.52 2.151 ;
     RECT  61.8 2.137 61.92 2.151 ;
     RECT  67.2 2.137 67.32 2.151 ;
     RECT  72.6 2.137 72.72 2.151 ;
     RECT  78 2.137 78.12 2.151 ;
     RECT  83.4 2.137 83.52 2.151 ;
     RECT  34.8 2.137 36.6 2.197 ;
     RECT  34.8 2.197 36.84 2.245 ;
     RECT  40.2 2.151 40.512 2.245 ;
     RECT  5.472 1.763 30.648 2.291 ;
     RECT  34.032 2.245 36.84 2.533 ;
     RECT  51 2.151 51.312 2.533 ;
     RECT  33.744 2.533 36.84 2.581 ;
     RECT  32.88 2.581 36.84 2.629 ;
     RECT  5.616 2.291 30.648 2.677 ;
     RECT  31.776 2.245 31.8 2.677 ;
     RECT  32.88 2.629 36.888 2.677 ;
     RECT  39.312 2.245 40.512 2.677 ;
     RECT  42.72 2.245 42.744 2.725 ;
     RECT  5.616 2.677 36.888 2.773 ;
     RECT  5.616 2.773 36.936 2.821 ;
     RECT  38.736 2.677 40.512 2.821 ;
     RECT  61.8 2.151 62.112 2.821 ;
     RECT  50.736 2.533 51.312 2.867 ;
     RECT  49.728 2.245 49.752 3.059 ;
     RECT  61.68 2.821 62.112 3.155 ;
     RECT  38.736 2.821 40.776 3.205 ;
     RECT  5.616 2.821 37.032 3.253 ;
     RECT  38.688 3.205 40.776 3.253 ;
     RECT  5.616 3.253 37.224 3.301 ;
     RECT  38.592 3.253 40.776 3.301 ;
     RECT  42.048 2.725 42.744 3.301 ;
     RECT  78 2.151 78.312 3.301 ;
     RECT  5.616 3.301 37.56 3.349 ;
     RECT  38.592 3.301 42.744 3.349 ;
     RECT  67.2 2.151 67.512 3.925 ;
     RECT  74.4 2.869 74.424 3.925 ;
     RECT  75.984 3.397 76.008 3.925 ;
     RECT  82.368 2.245 82.392 3.925 ;
     RECT  83.4 2.151 83.712 3.925 ;
     RECT  56.4 2.151 56.712 4.117 ;
     RECT  74.4 3.925 76.008 4.261 ;
     RECT  74.112 4.261 76.008 4.307 ;
     RECT  44.448 3.829 44.472 4.501 ;
     RECT  45.6 2.151 45.912 4.501 ;
     RECT  82.368 3.925 83.712 4.501 ;
     RECT  67.2 3.925 68.424 4.547 ;
     RECT  56.4 4.117 56.808 4.643 ;
     RECT  82.368 4.501 84.6 4.691 ;
     RECT  61.8 3.155 62.112 4.693 ;
     RECT  66.096 3.397 66.12 4.787 ;
     RECT  4.512 4.501 4.536 4.837 ;
     RECT  5.616 3.349 42.744 4.837 ;
     RECT  53.856 2.629 53.88 4.885 ;
     RECT  0.288 4.021 0.312 4.981 ;
     RECT  56.4 4.643 56.712 5.029 ;
     RECT  4.512 4.837 42.744 5.077 ;
     RECT  82.368 4.691 82.392 5.077 ;
     RECT  53.568 4.885 53.88 5.123 ;
     RECT  83.4 4.691 84.6 5.123 ;
     RECT  63.84 4.357 63.864 5.171 ;
     RECT  74.112 4.307 74.136 5.171 ;
     RECT  75.264 4.307 76.008 5.171 ;
     RECT  78 3.301 78.696 5.219 ;
     RECT  4.512 5.077 43.32 5.317 ;
     RECT  44.448 4.501 45.912 5.605 ;
     RECT  56.064 5.029 56.712 5.699 ;
     RECT  0.144 4.981 0.312 5.747 ;
     RECT  0.192 5.747 0.312 5.843 ;
     RECT  82.224 5.077 82.392 5.989 ;
     RECT  83.4 5.123 83.712 5.989 ;
     RECT  4.32 5.317 43.32 6.085 ;
     RECT  44.4 5.605 45.912 6.085 ;
     RECT  2.4 2.151 2.712 6.229 ;
     RECT  4.32 6.085 45.912 6.229 ;
     RECT  78 5.219 78.312 6.229 ;
     RECT  48.72 3.925 48.744 6.277 ;
     RECT  58.032 5.317 58.056 6.323 ;
     RECT  72.6 2.151 72.912 6.709 ;
     RECT  82.224 5.989 83.712 6.803 ;
     RECT  67.2 4.547 67.512 6.805 ;
     RECT  71.232 5.365 71.256 6.853 ;
     RECT  2.4 6.229 45.912 6.899 ;
     RECT  47.952 6.277 48.744 6.899 ;
     RECT  51 2.867 51.312 6.901 ;
     RECT  43.872 6.899 45.912 6.947 ;
     RECT  70.608 6.853 71.256 6.995 ;
     RECT  56.4 5.699 56.712 7.045 ;
     RECT  55.872 7.045 56.712 7.187 ;
     RECT  43.92 6.947 45.912 7.381 ;
     RECT  72.48 6.709 72.912 7.381 ;
     RECT  75.264 5.171 75.288 7.381 ;
     RECT  67.2 6.805 67.752 7.427 ;
     RECT  63.84 6.805 63.864 7.475 ;
     RECT  61.536 4.693 62.112 7.765 ;
     RECT  72.288 7.381 72.912 7.909 ;
     RECT  74.16 7.381 74.184 7.909 ;
     RECT  50.352 6.901 51.312 8.003 ;
     RECT  53.568 5.123 53.592 8.003 ;
     RECT  75.168 7.381 75.288 8.051 ;
     RECT  2.4 6.899 42.36 8.099 ;
     RECT  4.848 8.099 42.36 8.437 ;
     RECT  43.92 7.381 46.488 8.437 ;
     RECT  71.232 6.995 71.256 8.485 ;
     RECT  78 6.229 79.032 8.773 ;
     RECT  82.608 6.803 83.712 8.773 ;
     RECT  70.656 8.485 71.256 8.819 ;
     RECT  75.264 8.051 75.288 8.819 ;
     RECT  77.136 8.773 79.032 8.819 ;
     RECT  82.608 8.773 83.976 8.819 ;
     RECT  61.44 7.765 62.112 9.107 ;
     RECT  61.536 9.107 62.112 9.155 ;
     RECT  67.2 7.427 67.608 9.155 ;
     RECT  72.288 7.909 74.184 9.155 ;
     RECT  70.656 8.819 70.92 9.395 ;
     RECT  58.704 8.725 58.728 9.683 ;
     RECT  72.48 9.155 72.912 9.827 ;
     RECT  52.992 8.485 53.016 9.925 ;
     RECT  2.4 8.099 3.672 9.971 ;
     RECT  4.848 8.437 46.488 9.973 ;
     RECT  63.312 8.293 63.336 10.213 ;
     RECT  67.2 9.155 67.512 10.213 ;
     RECT  49.92 8.437 49.944 10.307 ;
     RECT  83.4 8.819 83.976 10.307 ;
     RECT  72.6 9.827 72.912 10.357 ;
     RECT  74.016 9.155 74.184 10.357 ;
     RECT  2.4 9.971 2.856 10.403 ;
     RECT  63.312 10.213 63.96 10.501 ;
     RECT  3.984 9.973 46.488 10.741 ;
     RECT  56.016 7.187 56.712 10.741 ;
     RECT  56.016 10.741 57.576 10.883 ;
     RECT  67.2 10.213 67.8 10.883 ;
     RECT  70.896 9.395 70.92 10.883 ;
     RECT  77.136 8.819 78.312 10.883 ;
     RECT  3.984 10.741 46.968 10.979 ;
     RECT  3.984 10.979 4.872 11.267 ;
     RECT  54.672 10.597 54.696 11.411 ;
     RECT  83.4 10.307 83.712 11.413 ;
     RECT  56.016 10.883 57.048 11.459 ;
     RECT  58.752 10.501 58.776 11.459 ;
     RECT  6.144 10.979 40.512 11.555 ;
     RECT  48.72 6.899 48.744 11.699 ;
     RECT  52.848 9.925 53.016 11.699 ;
     RECT  67.2 10.883 67.512 11.893 ;
     RECT  72.6 10.357 74.184 11.893 ;
     RECT  72.6 11.893 74.76 11.941 ;
     RECT  6.144 11.555 36.36 12.035 ;
     RECT  41.52 10.979 46.968 12.035 ;
     RECT  56.4 11.459 57.048 12.035 ;
     RECT  63.312 10.501 64.776 12.035 ;
     RECT  79.92 10.261 79.944 12.035 ;
     RECT  6.24 12.035 36.36 12.179 ;
     RECT  82.464 11.413 83.712 12.323 ;
     RECT  72.6 11.941 75.144 12.325 ;
     RECT  6.624 12.179 36.36 12.517 ;
     RECT  46.944 12.035 46.968 12.517 ;
     RECT  51 8.003 51.312 12.517 ;
     RECT  72 12.325 75.144 12.517 ;
     RECT  37.776 11.555 40.512 12.901 ;
     RECT  41.52 12.035 45.912 12.901 ;
     RECT  69.936 11.365 69.96 12.997 ;
     RECT  80.64 12.469 80.664 12.997 ;
     RECT  56.4 12.035 56.808 13.045 ;
     RECT  61.8 9.155 62.112 13.045 ;
     RECT  4.464 11.267 4.872 13.139 ;
     RECT  52.848 11.699 52.872 13.139 ;
     RECT  69.408 12.997 69.96 13.139 ;
     RECT  72 12.517 75.24 13.379 ;
     RECT  66.24 11.893 67.512 13.525 ;
     RECT  37.776 12.901 45.912 13.573 ;
     RECT  46.944 12.517 47.352 13.573 ;
     RECT  81.792 13.045 81.816 13.667 ;
     RECT  55.776 13.045 56.808 13.715 ;
     RECT  75.216 13.379 75.24 13.715 ;
     RECT  79.824 12.997 80.664 13.811 ;
     RECT  69.408 13.139 69.432 13.859 ;
     RECT  66.24 13.525 67.608 14.099 ;
     RECT  72 13.379 74.184 14.099 ;
     RECT  6.624 12.517 36.456 14.197 ;
     RECT  37.776 13.573 47.352 14.197 ;
     RECT  6.096 14.197 47.352 14.339 ;
     RECT  33.6 14.339 47.352 14.387 ;
     RECT  51 12.517 51.672 14.435 ;
     RECT  67.2 14.099 67.608 14.675 ;
     RECT  33.6 14.387 45.912 14.723 ;
     RECT  78 10.883 78.312 14.725 ;
     RECT  72 14.099 72.912 14.819 ;
     RECT  46.944 14.387 47.352 14.867 ;
     RECT  4.704 13.139 4.872 14.917 ;
     RECT  47.328 14.867 47.352 15.061 ;
     RECT  33.84 14.723 45.912 15.203 ;
     RECT  72.048 14.819 72.912 15.203 ;
     RECT  53.616 13.141 53.64 15.253 ;
     RECT  52.992 15.253 53.64 15.299 ;
     RECT  38.736 15.203 45.912 15.443 ;
     RECT  63.936 12.035 64.776 15.443 ;
     RECT  4.704 14.917 4.968 15.491 ;
     RECT  47.328 15.061 48.12 15.491 ;
     RECT  82.368 14.773 82.392 15.587 ;
     RECT  70.128 15.205 70.152 15.829 ;
     RECT  4.944 15.491 4.968 15.925 ;
     RECT  52.992 15.299 53.016 15.925 ;
     RECT  6.096 14.339 32.424 16.019 ;
     RECT  38.88 15.443 45.912 16.019 ;
     RECT  58.128 15.061 58.152 16.019 ;
     RECT  6.624 16.019 32.424 16.261 ;
     RECT  83.4 12.323 83.712 16.405 ;
     RECT  6.624 16.261 32.472 16.501 ;
     RECT  33.84 15.203 37.608 16.501 ;
     RECT  6.624 16.501 37.608 16.595 ;
     RECT  60.96 13.045 62.112 16.595 ;
     RECT  70.128 15.829 70.968 16.741 ;
     RECT  72.6 15.203 72.912 16.741 ;
     RECT  6.624 16.595 35.88 16.883 ;
     RECT  51 14.435 51.312 16.885 ;
     RECT  52.704 15.925 53.016 16.885 ;
     RECT  48.096 15.491 48.12 16.931 ;
     RECT  36.912 16.595 37.608 17.123 ;
     RECT  41.616 16.019 45.912 17.123 ;
     RECT  78 14.725 78.456 17.123 ;
     RECT  70.128 16.741 72.912 17.507 ;
     RECT  72 17.507 72.912 17.603 ;
     RECT  39.264 16.019 40.512 17.605 ;
     RECT  6.624 16.883 8.664 17.699 ;
     RECT  61.248 16.595 62.112 17.699 ;
     RECT  10.224 16.883 35.88 18.181 ;
     RECT  36.912 17.123 37.032 18.181 ;
     RECT  41.616 17.123 44.472 18.275 ;
     RECT  76.896 18.085 76.92 18.275 ;
     RECT  80.64 13.811 80.664 18.275 ;
     RECT  42.528 18.275 43.512 18.323 ;
     RECT  4.944 15.925 5.016 18.469 ;
     RECT  42.528 18.323 42.6 18.515 ;
     RECT  39.216 17.605 40.512 18.661 ;
     RECT  42.528 18.515 42.552 18.707 ;
     RECT  4.8 18.469 5.016 18.757 ;
     RECT  6.624 17.699 8.424 18.757 ;
     RECT  10.224 18.181 37.032 18.757 ;
     RECT  85.728 16.501 85.752 19.093 ;
     RECT  85.728 19.093 86.04 19.139 ;
     RECT  70.128 17.507 70.968 19.235 ;
     RECT  63.936 15.443 63.96 19.333 ;
     RECT  51 16.885 53.016 19.427 ;
     RECT  51 19.427 52.728 19.475 ;
     RECT  58.752 19.429 58.776 19.571 ;
     RECT  47.376 18.757 47.4 19.813 ;
     RECT  6.624 18.757 9.192 19.859 ;
     RECT  47.376 19.813 47.88 19.859 ;
     RECT  63.936 19.333 64.872 19.909 ;
     RECT  67.2 14.675 67.512 19.909 ;
     RECT  4.8 18.757 5.064 20.003 ;
     RECT  51 19.475 52.296 20.003 ;
     RECT  10.224 18.757 37.464 20.053 ;
     RECT  4.8 20.003 4.824 20.147 ;
     RECT  10.176 20.053 37.464 20.149 ;
     RECT  39.216 18.661 40.728 20.149 ;
     RECT  70.128 19.235 70.824 20.293 ;
     RECT  63.936 19.909 65.448 20.341 ;
     RECT  70.128 20.293 70.92 20.389 ;
     RECT  70.128 20.389 70.968 20.437 ;
     RECT  83.04 16.405 83.712 20.579 ;
     RECT  70.128 20.437 71.496 20.581 ;
     RECT  72.6 17.603 72.912 20.581 ;
     RECT  61.8 17.699 62.112 20.869 ;
     RECT  61.68 20.869 62.112 21.059 ;
     RECT  3.84 20.197 3.864 21.155 ;
     RECT  9.888 20.149 37.464 21.155 ;
     RECT  51 20.003 51.768 21.155 ;
     RECT  63.936 20.341 66.072 21.155 ;
     RECT  70.128 20.581 72.912 21.157 ;
     RECT  9.888 21.155 37.272 21.299 ;
     RECT  78 17.123 78.312 21.397 ;
     RECT  86.016 19.139 86.04 21.443 ;
     RECT  6.624 19.859 8.424 21.637 ;
     RECT  67.2 19.909 68.376 21.637 ;
     RECT  69.552 21.157 72.912 21.637 ;
     RECT  6.624 21.637 8.808 21.685 ;
     RECT  9.888 21.299 37.176 21.685 ;
     RECT  55.104 19.909 55.128 21.971 ;
     RECT  74.16 14.099 74.184 22.165 ;
     RECT  38.736 20.149 40.728 22.259 ;
     RECT  47.856 19.859 47.88 22.259 ;
     RECT  6.624 21.685 37.176 22.307 ;
     RECT  6.624 22.307 10.872 22.403 ;
     RECT  6.624 22.403 8.808 22.451 ;
     RECT  58.656 21.589 58.68 22.453 ;
     RECT  77.904 21.397 78.312 22.499 ;
     RECT  11.856 22.307 37.176 22.741 ;
     RECT  58.656 22.453 59.064 22.835 ;
     RECT  9.888 22.403 10.872 22.931 ;
     RECT  39.216 22.259 40.728 23.363 ;
     RECT  4.176 21.637 4.2 23.411 ;
     RECT  11.856 22.741 38.232 23.507 ;
     RECT  67.2 21.637 72.912 23.699 ;
     RECT  37.44 23.507 38.232 23.701 ;
     RECT  39.216 23.363 40.512 23.701 ;
     RECT  87.168 16.501 87.192 23.987 ;
     RECT  6.624 22.451 8.568 24.085 ;
     RECT  9.888 22.931 10.44 24.085 ;
     RECT  4.32 24.373 4.344 24.469 ;
     RECT  56.4 13.715 56.808 24.469 ;
     RECT  61.8 21.059 62.112 24.469 ;
     RECT  78 22.499 78.312 24.469 ;
     RECT  83.136 20.579 83.712 24.563 ;
     RECT  37.44 23.701 40.512 24.853 ;
     RECT  6.624 24.085 10.44 24.997 ;
     RECT  70.656 23.699 71.448 25.139 ;
     RECT  11.856 23.507 36.072 25.189 ;
     RECT  61.8 24.469 62.76 25.331 ;
     RECT  77.76 24.469 78.312 25.525 ;
     RECT  77.76 25.525 78.408 25.571 ;
     RECT  76.032 19.813 76.056 25.621 ;
     RECT  11.424 25.189 36.072 25.861 ;
     RECT  37.104 24.853 40.512 25.861 ;
     RECT  74.16 22.165 74.52 25.957 ;
     RECT  63.936 21.155 65.448 26.101 ;
     RECT  67.2 23.699 69.576 26.197 ;
     RECT  70.896 25.139 71.448 26.197 ;
     RECT  11.424 25.861 40.512 26.243 ;
     RECT  56.4 24.469 57 26.243 ;
     RECT  76.032 25.621 76.632 26.243 ;
     RECT  5.904 24.997 10.44 26.339 ;
     RECT  11.952 26.243 37.128 26.435 ;
     RECT  7.68 26.339 10.44 26.483 ;
     RECT  73.92 25.957 74.52 26.531 ;
     RECT  67.2 26.197 71.448 26.771 ;
     RECT  7.68 26.483 8.424 26.819 ;
     RECT  11.952 26.435 14.568 26.819 ;
     RECT  15.6 26.435 37.128 26.867 ;
     RECT  2.4 10.403 2.712 27.061 ;
     RECT  7.8 26.819 8.424 27.155 ;
     RECT  51 21.155 51.312 27.157 ;
     RECT  15.6 26.867 35.88 27.395 ;
     RECT  45.6 17.123 45.912 27.637 ;
     RECT  37.104 26.867 37.128 27.781 ;
     RECT  38.304 26.243 40.512 27.781 ;
     RECT  42.096 26.725 42.12 27.781 ;
     RECT  56.4 26.243 56.808 27.781 ;
     RECT  42 27.781 42.12 27.827 ;
     RECT  59.04 22.835 59.064 27.829 ;
     RECT  58.08 27.829 59.064 27.875 ;
     RECT  63.936 26.101 66.168 27.971 ;
     RECT  5.904 26.339 6.648 28.117 ;
     RECT  74.16 26.531 74.52 28.163 ;
     RECT  5.52 28.117 6.648 28.403 ;
     RECT  52.752 27.157 52.776 28.405 ;
     RECT  9.456 26.483 10.44 28.453 ;
     RECT  11.952 26.819 14.424 28.547 ;
     RECT  12.48 28.547 14.424 28.691 ;
     RECT  42 27.827 42.024 28.787 ;
     RECT  9.312 28.453 10.44 29.027 ;
     RECT  37.104 27.781 40.512 29.123 ;
     RECT  70.896 26.771 71.448 29.171 ;
     RECT  67.2 26.771 69.576 29.317 ;
     RECT  70.896 29.171 70.92 29.317 ;
     RECT  66.144 27.971 66.168 29.363 ;
     RECT  7.8 27.155 8.112 29.365 ;
     RECT  9.312 29.027 9.768 29.365 ;
     RECT  15.6 27.395 35.832 29.507 ;
     RECT  50.16 27.157 51.312 29.507 ;
     RECT  4.32 24.469 4.488 29.699 ;
     RECT  5.904 28.403 6.648 29.843 ;
     RECT  52.752 28.405 53.64 30.037 ;
     RECT  83.4 24.563 83.712 30.181 ;
     RECT  63.936 27.971 64.872 30.275 ;
     RECT  67.2 29.317 70.92 30.275 ;
     RECT  7.8 29.365 9.768 30.323 ;
     RECT  59.088 28.405 59.112 30.323 ;
     RECT  7.8 30.323 9.336 30.611 ;
     RECT  15.6 29.507 16.344 30.611 ;
     RECT  17.52 29.507 35.832 30.611 ;
     RECT  34.56 30.611 35.832 30.803 ;
     RECT  82.416 30.181 83.712 30.803 ;
     RECT  67.2 30.275 69.576 30.851 ;
     RECT  47.376 28.693 47.4 30.997 ;
     RECT  47.376 30.997 47.688 31.043 ;
     RECT  34.56 30.803 35.736 31.139 ;
     RECT  70.704 30.275 70.92 31.187 ;
     RECT  37.68 29.123 40.512 31.235 ;
     RECT  34.704 31.139 35.736 31.379 ;
     RECT  58.08 27.875 58.104 31.379 ;
     RECT  64.224 30.275 64.872 31.379 ;
     RECT  87.024 24.469 87.048 31.379 ;
     RECT  76.608 26.243 76.632 31.475 ;
     RECT  15.696 30.611 16.344 31.619 ;
     RECT  44.16 28.405 44.184 31.861 ;
     RECT  45.6 27.637 46.056 31.861 ;
     RECT  74.496 28.163 74.52 31.861 ;
     RECT  16.224 31.619 16.344 31.955 ;
     RECT  64.224 31.379 64.248 31.955 ;
     RECT  38.16 31.235 40.512 32.005 ;
     RECT  44.16 31.861 46.056 32.197 ;
     RECT  38.16 32.005 41.016 32.243 ;
     RECT  43.344 32.197 46.056 32.341 ;
     RECT  82.704 30.803 83.712 32.341 ;
     RECT  6.624 29.843 6.648 32.437 ;
     RECT  7.8 30.611 8.112 32.437 ;
     RECT  34.704 31.379 35.64 32.437 ;
     RECT  52.56 30.037 53.64 32.531 ;
     RECT  16.224 31.955 16.248 32.723 ;
     RECT  17.52 30.611 33.576 32.917 ;
     RECT  34.56 32.437 35.64 32.917 ;
     RECT  47.664 31.043 47.688 33.011 ;
     RECT  2.4 27.061 3.288 33.013 ;
     RECT  65.952 30.421 65.976 33.013 ;
     RECT  43.344 32.341 46.152 33.107 ;
     RECT  49.536 32.293 49.56 33.107 ;
     RECT  82.704 32.341 83.832 33.107 ;
     RECT  45.504 33.107 46.152 33.109 ;
     RECT  17.52 32.917 35.64 33.251 ;
     RECT  17.52 33.251 26.232 33.299 ;
     RECT  43.344 33.107 44.472 33.347 ;
     RECT  23.904 33.299 26.232 33.395 ;
     RECT  27.312 33.251 35.64 33.445 ;
     RECT  27.312 33.445 36.456 33.587 ;
     RECT  45.504 33.109 46.488 33.589 ;
     RECT  71.232 31.525 71.256 33.589 ;
     RECT  72.6 23.699 72.912 33.589 ;
     RECT  27.312 33.587 33.576 33.683 ;
     RECT  55.296 32.389 55.32 33.683 ;
     RECT  82.704 33.107 83.712 33.683 ;
     RECT  24 33.395 26.232 33.731 ;
     RECT  15.264 33.541 15.288 33.781 ;
     RECT  6.624 32.437 8.112 33.827 ;
     RECT  12.48 28.691 14.232 33.827 ;
     RECT  24 33.731 26.184 33.827 ;
     RECT  7.8 33.827 8.112 33.829 ;
     RECT  9.312 30.611 9.336 33.829 ;
     RECT  70.704 33.589 72.912 33.875 ;
     RECT  78 25.571 78.408 33.875 ;
     RECT  43.344 33.347 43.368 33.925 ;
     RECT  45.504 33.589 47.016 33.971 ;
     RECT  42.336 33.925 43.368 34.067 ;
     RECT  81.456 33.061 81.48 34.115 ;
     RECT  65.52 33.013 65.976 34.165 ;
     RECT  15.264 33.781 15.384 34.211 ;
     RECT  38.16 32.243 40.824 34.211 ;
     RECT  44.448 33.347 44.472 34.211 ;
     RECT  71.232 33.875 72.912 34.211 ;
     RECT  2.304 33.013 3.288 34.259 ;
     RECT  28.08 33.683 33.576 34.259 ;
     RECT  34.56 33.587 36.456 34.259 ;
     RECT  39.024 34.211 40.824 34.259 ;
     RECT  24 33.827 26.088 34.307 ;
     RECT  65.52 34.165 66.168 34.355 ;
     RECT  16.512 34.165 16.536 34.453 ;
     RECT  12.48 33.827 13.944 34.499 ;
     RECT  17.52 33.299 22.92 34.645 ;
     RECT  24 34.307 25.944 34.645 ;
     RECT  78 33.875 78.312 34.645 ;
     RECT  16.416 34.453 16.536 34.741 ;
     RECT  17.52 34.645 25.944 34.741 ;
     RECT  2.4 34.259 3.288 34.787 ;
     RECT  34.56 34.259 36.168 34.787 ;
     RECT  7.8 33.829 9.336 34.835 ;
     RECT  34.56 34.787 35.448 34.835 ;
     RECT  45.504 33.971 46.488 34.933 ;
     RECT  45.504 34.933 47.064 35.029 ;
     RECT  45.504 35.029 47.112 35.221 ;
     RECT  67.2 30.851 69.144 35.269 ;
     RECT  77.904 34.645 78.312 35.269 ;
     RECT  6.624 33.827 6.648 35.317 ;
     RECT  7.8 34.835 8.328 35.317 ;
     RECT  33.552 34.259 33.576 35.363 ;
     RECT  15.36 34.211 15.384 35.411 ;
     RECT  34.56 34.835 35.352 35.411 ;
     RECT  63.456 35.365 63.48 35.843 ;
     RECT  28.08 34.259 32.472 35.845 ;
     RECT  45.504 35.221 47.304 35.939 ;
     RECT  67.2 35.269 69.528 35.939 ;
     RECT  72.6 34.211 72.912 36.133 ;
     RECT  45.504 35.939 47.112 36.323 ;
     RECT  72.24 36.133 72.912 36.421 ;
     RECT  74.4 31.861 74.52 36.421 ;
     RECT  39.6 34.259 40.824 36.469 ;
     RECT  12.48 34.499 13.512 36.515 ;
     RECT  27.408 35.845 32.472 36.515 ;
     RECT  42.432 34.067 43.368 36.515 ;
     RECT  87.504 34.069 87.528 36.515 ;
     RECT  6.624 35.317 8.328 36.563 ;
     RECT  29.088 36.515 30.408 36.563 ;
     RECT  33.648 36.757 33.672 36.805 ;
     RECT  56.4 27.781 57 36.901 ;
     RECT  58.032 36.421 58.056 36.901 ;
     RECT  33.648 36.805 33.768 36.949 ;
     RECT  34.8 35.411 35.352 36.949 ;
     RECT  27.408 36.515 27.672 36.997 ;
     RECT  61.8 25.331 62.112 37.045 ;
     RECT  12.624 36.515 13.512 37.091 ;
     RECT  27.312 36.997 27.672 37.091 ;
     RECT  66.144 34.355 66.168 37.091 ;
     RECT  61.8 37.045 62.664 37.379 ;
     RECT  42.432 36.515 42.456 37.427 ;
     RECT  71.232 34.211 71.256 37.475 ;
     RECT  16.416 34.741 25.944 37.477 ;
     RECT  61.8 37.379 62.112 37.477 ;
     RECT  72.24 36.421 74.52 37.477 ;
     RECT  29.088 36.563 29.928 37.573 ;
     RECT  15.84 37.477 25.944 37.621 ;
     RECT  27.312 37.091 27.336 37.667 ;
     RECT  45.6 36.323 47.112 37.667 ;
     RECT  31.632 36.515 32.184 37.715 ;
     RECT  56.4 36.901 58.056 37.859 ;
     RECT  7.8 36.563 8.328 37.861 ;
     RECT  9.312 34.835 9.336 37.861 ;
     RECT  15.84 37.621 26.184 37.907 ;
     RECT  38.64 36.469 40.824 38.003 ;
     RECT  38.64 38.003 38.664 38.149 ;
     RECT  4.32 29.699 4.344 38.243 ;
     RECT  12.768 37.091 13.512 38.243 ;
     RECT  15.936 37.907 26.184 38.243 ;
     RECT  29.088 37.573 30.216 38.243 ;
     RECT  33.648 36.949 35.352 38.243 ;
     RECT  39.84 38.003 40.824 38.291 ;
     RECT  7.8 37.861 9.336 38.435 ;
     RECT  71.808 37.477 74.52 38.435 ;
     RECT  77.52 35.269 78.312 38.435 ;
     RECT  37.728 38.149 38.664 38.675 ;
     RECT  2.4 34.787 3.192 38.677 ;
     RECT  7.8 38.435 8.52 38.723 ;
     RECT  34.8 38.243 35.352 38.771 ;
     RECT  33.648 38.243 33.768 38.819 ;
     RECT  74.496 38.435 74.52 38.819 ;
     RECT  15.936 38.243 16.392 39.059 ;
     RECT  17.616 38.243 26.184 39.205 ;
     RECT  13.2 38.243 13.512 39.301 ;
     RECT  56.4 37.859 57.576 39.395 ;
     RECT  37.728 38.675 37.752 39.491 ;
     RECT  45.6 37.667 46.488 39.493 ;
     RECT  33.648 38.819 33.672 39.539 ;
     RECT  41.664 39.493 41.688 39.635 ;
     RECT  2.4 38.677 4.008 39.731 ;
     RECT  56.4 39.395 57.048 39.877 ;
     RECT  17.616 39.205 26.952 39.923 ;
     RECT  65.232 38.005 65.256 40.165 ;
     RECT  78 38.435 78.312 40.165 ;
     RECT  64.992 40.165 65.256 40.211 ;
     RECT  15.936 39.059 15.96 40.405 ;
     RECT  45.6 39.493 46.776 40.405 ;
     RECT  67.2 35.939 69.144 40.405 ;
     RECT  17.616 39.923 22.776 40.499 ;
     RECT  67.104 40.405 69.144 40.499 ;
     RECT  60.24 39.877 60.264 40.547 ;
     RECT  29.088 38.243 30.12 40.595 ;
     RECT  21.456 40.499 22.584 40.643 ;
     RECT  24 39.923 26.952 40.933 ;
     RECT  39.84 38.291 40.512 40.933 ;
     RECT  71.808 38.435 72.912 41.027 ;
     RECT  17.616 40.499 18.912 41.075 ;
     RECT  20.112 40.499 20.424 41.075 ;
     RECT  39.744 40.933 40.512 41.075 ;
     RECT  53.616 32.531 53.64 41.075 ;
     RECT  34.8 38.771 35.256 41.077 ;
     RECT  39.984 41.075 40.512 41.123 ;
     RECT  83.4 33.683 83.712 41.173 ;
     RECT  78 40.165 79.224 41.315 ;
     RECT  49.824 36.853 49.848 41.363 ;
     RECT  55.872 39.877 57.048 41.365 ;
     RECT  54.912 41.365 57.048 41.411 ;
     RECT  15.456 40.405 15.96 41.651 ;
     RECT  20.4 41.075 20.424 41.651 ;
     RECT  24 40.933 27.912 41.651 ;
     RECT  34.8 41.077 35.784 41.651 ;
     RECT  48.576 40.789 48.6 41.651 ;
     RECT  54.912 41.411 56.712 41.651 ;
     RECT  61.488 37.477 62.112 41.651 ;
     RECT  67.104 40.499 68.952 42.035 ;
     RECT  17.76 41.075 18.912 42.133 ;
     RECT  51 29.507 51.312 42.133 ;
     RECT  52.56 32.531 52.584 42.133 ;
     RECT  24 41.651 26.952 42.227 ;
     RECT  40.08 41.123 40.512 42.227 ;
     RECT  64.992 40.211 65.016 42.227 ;
     RECT  15.936 41.651 15.96 42.419 ;
     RECT  21.6 40.643 22.584 42.469 ;
     RECT  21.408 42.469 22.584 42.517 ;
     RECT  48.96 42.229 48.984 42.563 ;
     RECT  29.232 40.595 30.12 42.565 ;
     RECT  32.16 37.715 32.184 42.613 ;
     RECT  20.16 42.565 20.184 42.709 ;
     RECT  21.408 42.517 22.68 42.709 ;
     RECT  31.584 42.613 32.184 42.755 ;
     RECT  51 42.133 52.584 42.803 ;
     RECT  59.28 41.509 59.304 42.803 ;
     RECT  39.024 42.133 39.048 42.851 ;
     RECT  54.912 41.651 54.936 42.851 ;
     RECT  72.384 41.027 72.912 43.141 ;
     RECT  78 41.315 78.312 43.333 ;
     RECT  45.216 40.405 46.776 43.379 ;
     RECT  2.4 39.731 3.192 43.427 ;
     RECT  6.624 36.563 6.648 43.427 ;
     RECT  78 43.333 78.696 43.475 ;
     RECT  45.216 43.379 46.056 43.717 ;
     RECT  12.96 39.301 13.512 43.813 ;
     RECT  24 42.227 26.184 43.813 ;
     RECT  31.584 42.755 31.608 43.861 ;
     RECT  31.584 43.861 31.896 43.907 ;
     RECT  45.024 43.717 46.056 43.909 ;
     RECT  56.4 41.651 56.712 43.909 ;
     RECT  17.616 42.133 18.912 43.955 ;
     RECT  20.16 42.709 22.68 43.955 ;
     RECT  67.2 42.035 68.952 43.955 ;
     RECT  83.28 41.173 83.712 43.955 ;
     RECT  51 42.803 51.672 44.053 ;
     RECT  0.192 5.843 0.216 44.147 ;
     RECT  56.4 43.909 57.048 44.195 ;
     RECT  61.8 41.651 62.112 44.245 ;
     RECT  63.648 38.149 63.672 44.245 ;
     RECT  56.4 44.195 56.952 44.291 ;
     RECT  18.048 43.955 18.912 44.339 ;
     RECT  58.608 43.909 58.632 44.437 ;
     RECT  12.96 43.813 13.992 44.483 ;
     RECT  28.56 42.565 30.12 44.483 ;
     RECT  44.208 43.909 46.056 44.483 ;
     RECT  74.928 42.181 74.952 44.483 ;
     RECT  86.592 43.861 86.616 44.483 ;
     RECT  72.384 43.141 73.512 44.627 ;
     RECT  51 44.053 51.912 44.629 ;
     RECT  61.8 44.245 63.672 44.773 ;
     RECT  29.28 44.483 30.12 44.867 ;
     RECT  48.48 44.149 48.504 44.867 ;
     RECT  79.776 41.941 79.8 44.867 ;
     RECT  20.16 43.955 20.472 44.915 ;
     RECT  58.608 44.437 59.592 44.965 ;
     RECT  61.8 44.773 63.96 45.011 ;
     RECT  21.744 43.955 22.68 45.013 ;
     RECT  13.2 44.483 13.992 45.155 ;
     RECT  72.6 44.627 73.512 45.155 ;
     RECT  31.872 43.907 31.896 45.203 ;
     RECT  78 43.475 78.312 45.541 ;
     RECT  20.448 44.915 20.472 45.635 ;
     RECT  63.792 45.011 63.96 45.635 ;
     RECT  24 43.813 26.376 45.683 ;
     RECT  34.8 41.651 35.112 45.925 ;
     RECT  58.128 44.965 59.592 45.971 ;
     RECT  21.648 45.013 22.68 46.067 ;
     RECT  54.144 44.437 54.168 46.117 ;
     RECT  54.144 46.117 55.08 46.211 ;
     RECT  67.2 43.955 68.376 46.211 ;
     RECT  37.632 42.709 37.656 46.213 ;
     RECT  2.4 43.427 2.712 46.261 ;
     RECT  18.6 44.339 18.912 46.357 ;
     RECT  51 44.629 52.536 46.595 ;
     RECT  18.6 46.357 19.8 46.645 ;
     RECT  22.176 46.067 22.68 46.645 ;
     RECT  51 46.595 51.912 46.645 ;
     RECT  71.184 46.117 71.208 46.645 ;
     RECT  72.6 45.155 72.912 46.645 ;
     RECT  9.744 46.549 9.768 46.691 ;
     RECT  78 45.541 78.696 46.741 ;
     RECT  22.176 46.645 22.872 46.789 ;
     RECT  58.608 45.971 59.592 46.883 ;
     RECT  71.184 46.645 72.912 47.027 ;
     RECT  40.2 42.227 40.512 47.029 ;
     RECT  63.792 45.635 63.816 47.029 ;
     RECT  64.896 46.933 64.92 47.029 ;
     RECT  71.184 47.027 71.496 47.219 ;
     RECT  34.8 45.925 35.208 47.267 ;
     RECT  37.632 46.213 37.992 47.269 ;
     RECT  39.312 47.029 40.512 47.317 ;
     RECT  83.4 43.955 83.712 47.317 ;
     RECT  18.24 46.645 19.8 47.363 ;
     RECT  61.8 45.011 62.808 47.363 ;
     RECT  77.04 46.741 78.696 47.363 ;
     RECT  50.16 46.645 51.912 47.555 ;
     RECT  78 47.363 78.696 47.603 ;
     RECT  22.176 46.789 23.016 47.605 ;
     RECT  24 45.683 26.184 47.605 ;
     RECT  33.6 42.661 33.624 47.653 ;
     RECT  18.6 47.363 19.8 47.749 ;
     RECT  21.072 46.309 21.096 47.749 ;
     RECT  39.312 47.317 40.632 47.749 ;
     RECT  32.88 47.653 33.624 47.845 ;
     RECT  34.8 47.267 35.112 47.845 ;
     RECT  37.632 47.269 38.232 47.845 ;
     RECT  55.056 46.211 55.08 47.845 ;
     RECT  56.4 44.291 56.712 47.845 ;
     RECT  76.368 47.749 76.392 47.845 ;
     RECT  81.216 46.309 81.24 47.939 ;
     RECT  22.176 47.605 26.184 47.987 ;
     RECT  42.768 47.269 42.792 48.371 ;
     RECT  28.368 46.741 28.392 48.419 ;
     RECT  37.008 47.845 38.232 48.421 ;
     RECT  39.312 47.749 41.352 48.421 ;
     RECT  58.608 46.883 58.632 48.421 ;
     RECT  67.2 46.211 67.512 48.469 ;
     RECT  22.656 47.987 26.184 48.515 ;
     RECT  37.008 48.421 41.352 48.515 ;
     RECT  44.208 44.483 44.232 48.515 ;
     RECT  55.056 47.845 56.712 48.515 ;
     RECT  22.656 48.515 24.648 48.563 ;
     RECT  32.88 47.845 35.112 48.661 ;
     RECT  32.496 48.661 35.112 48.707 ;
     RECT  76.176 47.845 76.392 48.757 ;
     RECT  75.888 48.757 76.392 48.803 ;
     RECT  78 47.603 78.312 48.949 ;
     RECT  38.208 48.515 41.352 49.043 ;
     RECT  58.176 48.421 58.632 49.043 ;
     RECT  71.472 47.219 71.496 49.091 ;
     RECT  75.888 48.803 76.2 49.091 ;
     RECT  38.208 49.043 40.512 49.139 ;
     RECT  18.6 47.749 21.096 49.187 ;
     RECT  55.776 48.515 56.712 49.331 ;
     RECT  83.184 47.317 83.712 49.525 ;
     RECT  10.8 47.845 10.824 49.619 ;
     RECT  15.6 47.173 15.624 49.619 ;
     RECT  22.656 48.563 24.312 49.619 ;
     RECT  63.792 47.029 64.92 49.715 ;
     RECT  13.2 45.155 13.512 49.717 ;
     RECT  29.4 44.867 30.12 49.763 ;
     RECT  33.6 48.707 35.112 50.003 ;
     RECT  55.824 49.331 56.712 50.149 ;
     RECT  23.328 49.619 24.312 50.195 ;
     RECT  50.16 47.555 51.72 50.195 ;
     RECT  38.208 49.139 38.232 50.243 ;
     RECT  37.008 48.515 37.032 50.291 ;
     RECT  47.136 48.421 47.16 50.291 ;
     RECT  13.2 49.717 14.472 50.533 ;
     RECT  67.2 48.469 67.656 50.533 ;
     RECT  69.12 49.525 69.144 50.533 ;
     RECT  67.2 50.533 69.144 50.675 ;
     RECT  23.664 50.195 24.312 50.677 ;
     RECT  55.824 50.149 57.096 50.771 ;
     RECT  56.4 50.771 57.096 50.819 ;
     RECT  45.6 44.483 46.056 50.821 ;
     RECT  61.8 47.363 62.112 50.965 ;
     RECT  59.856 49.525 59.88 51.011 ;
     RECT  11.856 50.965 11.88 51.253 ;
     RECT  33.6 50.003 33.624 51.301 ;
     RECT  34.8 50.003 35.112 51.301 ;
     RECT  64.896 49.715 64.92 51.301 ;
     RECT  38.976 50.245 39 51.635 ;
     RECT  29.4 49.763 29.712 51.637 ;
     RECT  58.608 49.043 58.632 51.683 ;
     RECT  23.664 50.677 24.648 51.829 ;
     RECT  77.472 48.949 78.312 51.829 ;
     RECT  79.584 49.525 79.608 51.829 ;
     RECT  2.4 46.261 3.144 51.923 ;
     RECT  13.2 50.533 15.432 51.923 ;
     RECT  29.136 51.637 29.712 51.971 ;
     RECT  22.8 51.829 24.648 52.019 ;
     RECT  11.04 51.253 11.88 52.067 ;
     RECT  23.664 52.019 24.648 52.163 ;
     RECT  32.496 48.707 32.52 52.163 ;
     RECT  54.576 51.493 54.6 52.211 ;
     RECT  77.472 51.829 79.608 52.213 ;
     RECT  63.792 49.715 63.816 52.259 ;
     RECT  13.2 51.923 15.336 52.499 ;
     RECT  18.6 49.187 20.52 52.499 ;
     RECT  52.8 50.917 52.824 52.499 ;
     RECT  77.472 52.213 79.8 52.643 ;
     RECT  7.8 38.723 8.112 52.693 ;
     RECT  11.856 52.067 11.88 52.739 ;
     RECT  45.6 50.821 46.488 52.739 ;
     RECT  50.88 50.195 51.72 53.027 ;
     RECT  18.6 52.499 20.28 53.075 ;
     RECT  59.328 51.781 59.352 53.075 ;
     RECT  33.6 51.301 35.112 53.219 ;
     RECT  32.448 53.221 32.472 53.411 ;
     RECT  75.888 49.091 75.912 53.411 ;
     RECT  23.664 52.163 24.312 53.507 ;
     RECT  44.112 52.213 44.136 53.507 ;
     RECT  34.8 53.219 35.112 53.509 ;
     RECT  64.896 51.301 65.64 53.557 ;
     RECT  22.416 53.029 22.44 53.651 ;
     RECT  34.8 53.509 35.256 53.651 ;
     RECT  77.472 52.643 79.608 53.651 ;
     RECT  24 53.507 24.312 53.941 ;
     RECT  33.6 53.219 33.624 54.179 ;
     RECT  27.408 53.317 27.432 54.227 ;
     RECT  2.4 51.923 2.712 54.421 ;
     RECT  72.6 47.027 72.912 54.421 ;
     RECT  24 53.941 24.648 54.707 ;
     RECT  42.192 53.557 42.216 54.707 ;
     RECT  18.6 53.075 19.8 54.755 ;
     RECT  47.856 54.085 47.88 54.755 ;
     RECT  61.152 50.965 62.112 54.755 ;
     RECT  81.216 50.677 81.24 54.901 ;
     RECT  80.88 54.901 81.24 55.139 ;
     RECT  2.4 54.421 2.952 55.379 ;
     RECT  72.48 54.421 72.912 55.715 ;
     RECT  24 54.707 24.312 55.813 ;
     RECT  18.6 54.755 19.656 55.907 ;
     RECT  47.376 55.045 47.4 55.907 ;
     RECT  77.472 53.651 78.408 55.907 ;
     RECT  68.928 50.675 69.144 56.101 ;
     RECT  38.4 55.237 38.424 56.147 ;
     RECT  22.176 55.237 22.2 56.291 ;
     RECT  7.8 52.693 8.856 56.483 ;
     RECT  24 55.813 24.6 56.627 ;
     RECT  7.8 56.483 8.808 56.963 ;
     RECT  81.216 55.139 81.24 56.965 ;
     RECT  37.008 56.101 37.032 57.059 ;
     RECT  68.928 56.101 70.104 57.157 ;
     RECT  56.4 50.819 56.712 57.301 ;
     RECT  52.704 55.189 52.728 57.347 ;
     RECT  26.16 48.515 26.184 57.541 ;
     RECT  82.512 49.525 83.712 57.925 ;
     RECT  81.216 56.965 81.48 58.115 ;
     RECT  49.776 57.013 49.8 58.117 ;
     RECT  51 53.027 51.72 58.117 ;
     RECT  68.928 57.157 70.968 58.163 ;
     RECT  76.128 53.557 76.152 58.163 ;
     RECT  78 55.907 78.408 58.163 ;
     RECT  68.928 58.163 69.144 58.403 ;
     RECT  18.6 55.907 18.912 58.501 ;
     RECT  36.48 58.021 36.504 58.501 ;
     RECT  64.416 53.557 65.64 58.547 ;
     RECT  24 56.627 24.312 58.693 ;
     RECT  25.44 57.541 26.184 58.693 ;
     RECT  70.944 58.163 70.968 58.883 ;
     RECT  19.968 58.501 19.992 59.027 ;
     RECT  87.168 58.117 87.192 59.173 ;
     RECT  18.048 58.501 18.912 59.219 ;
     RECT  36.48 58.501 36.984 59.219 ;
     RECT  86.976 59.173 87.192 59.219 ;
     RECT  34.8 53.651 35.112 59.221 ;
     RECT  36.48 59.219 36.696 59.221 ;
     RECT  7.8 56.963 8.568 59.315 ;
     RECT  49.776 58.117 51.72 59.315 ;
     RECT  4.944 57.205 4.968 59.749 ;
     RECT  24 58.693 26.184 59.795 ;
     RECT  7.8 59.315 8.112 59.797 ;
     RECT  31.056 52.213 31.08 59.987 ;
     RECT  4.944 59.749 5.112 60.275 ;
     RECT  86.976 59.219 87 60.467 ;
     RECT  56.4 57.301 57.432 60.515 ;
     RECT  7.584 59.797 8.112 60.851 ;
     RECT  67.2 50.675 67.512 60.949 ;
     RECT  25.44 59.795 26.184 61.043 ;
     RECT  15.312 52.499 15.336 61.045 ;
     RECT  15.312 61.045 15.912 61.525 ;
     RECT  31.008 60.277 31.032 61.525 ;
     RECT  32.16 60.277 32.184 61.525 ;
     RECT  31.008 61.525 32.184 61.571 ;
     RECT  54.672 60.853 54.696 61.667 ;
     RECT  67.2 60.949 67.992 61.667 ;
     RECT  82.512 57.925 84.072 61.667 ;
     RECT  67.2 61.667 67.512 61.765 ;
     RECT  72.6 55.715 72.912 61.861 ;
     RECT  6.384 60.997 6.408 62.195 ;
     RECT  34.8 59.221 36.696 62.195 ;
     RECT  48.528 56.389 48.552 62.435 ;
     RECT  71.76 61.861 72.912 62.435 ;
     RECT  74.88 62.053 74.904 62.533 ;
     RECT  4.944 60.275 4.968 62.579 ;
     RECT  74.88 62.533 75.816 62.579 ;
     RECT  26.16 61.043 26.184 62.581 ;
     RECT  66.96 61.765 67.512 62.629 ;
     RECT  79.584 53.651 79.608 62.723 ;
     RECT  33.264 60.949 33.288 62.771 ;
     RECT  49.776 59.315 49.8 62.771 ;
     RECT  18.6 59.219 18.912 63.013 ;
     RECT  26.16 62.581 26.232 63.251 ;
     RECT  81.216 58.115 81.24 63.299 ;
     RECT  66.912 62.629 67.512 63.587 ;
     RECT  15.312 61.525 15.96 63.779 ;
     RECT  18.6 63.013 19.704 63.779 ;
     RECT  21.456 58.117 21.48 63.781 ;
     RECT  20.496 63.781 21.48 63.827 ;
     RECT  31.536 61.571 32.184 64.019 ;
     RECT  82.512 61.667 83.712 64.163 ;
     RECT  26.16 63.251 26.184 64.165 ;
     RECT  72.336 62.435 72.912 64.213 ;
     RECT  85.536 52.981 85.56 64.451 ;
     RECT  67.2 63.587 67.512 64.933 ;
     RECT  69.12 58.403 69.144 64.933 ;
     RECT  71.808 64.213 72.912 64.979 ;
     RECT  64.896 58.547 65.64 64.981 ;
     RECT  33.648 64.357 33.672 65.269 ;
     RECT  64.8 64.981 65.64 65.269 ;
     RECT  64.032 65.269 65.64 65.555 ;
     RECT  61.8 54.755 62.112 65.701 ;
     RECT  64.8 65.555 65.64 65.749 ;
     RECT  61.8 65.701 62.28 65.843 ;
     RECT  67.2 64.933 69.144 65.987 ;
     RECT  45.6 52.739 46.056 65.989 ;
     RECT  64.8 65.749 66.12 65.989 ;
     RECT  67.2 65.987 67.512 65.989 ;
     RECT  20.496 63.827 20.52 66.085 ;
     RECT  75.792 62.579 75.816 66.085 ;
     RECT  45.6 65.989 46.152 66.227 ;
     RECT  49.68 64.405 49.704 66.323 ;
     RECT  51 59.315 51.72 66.419 ;
     RECT  36.672 62.195 36.696 66.563 ;
     RECT  55.296 66.373 55.32 66.565 ;
     RECT  56.4 60.515 57.096 66.565 ;
     RECT  55.296 66.565 57.096 66.611 ;
     RECT  69.12 65.987 69.144 66.661 ;
     RECT  69.12 66.661 69.528 66.707 ;
     RECT  19.968 66.085 20.52 66.755 ;
     RECT  33.648 65.269 33.72 66.755 ;
     RECT  64.8 65.989 67.512 66.803 ;
     RECT  25.632 64.165 26.184 67.283 ;
     RECT  27.648 66.517 27.672 67.331 ;
     RECT  33.648 66.755 33.672 67.571 ;
     RECT  69.504 66.707 69.528 67.571 ;
     RECT  75.744 66.085 75.816 67.669 ;
     RECT  75.024 67.669 75.816 67.715 ;
     RECT  20.112 66.755 20.52 67.859 ;
     RECT  49.104 67.237 49.128 67.859 ;
     RECT  71.952 64.979 72.912 67.859 ;
     RECT  64.896 66.803 67.512 67.861 ;
     RECT  64.752 67.861 67.512 67.909 ;
     RECT  58.128 62.581 58.152 68.101 ;
     RECT  40.2 49.139 40.512 68.245 ;
     RECT  64.752 67.909 67.608 68.245 ;
     RECT  34.8 62.195 35.112 68.341 ;
     RECT  39.408 68.245 40.512 68.341 ;
     RECT  64.608 68.245 67.608 68.341 ;
     RECT  58.128 68.101 58.296 68.483 ;
     RECT  29.4 51.971 29.712 68.533 ;
     RECT  24 59.795 24.312 68.773 ;
     RECT  2.4 55.379 2.712 68.917 ;
     RECT  51 66.419 51.312 68.917 ;
     RECT  39.408 68.341 40.632 68.963 ;
     RECT  24 68.773 24.408 69.061 ;
     RECT  64.416 68.341 67.608 69.251 ;
     RECT  64.608 69.251 67.608 69.395 ;
     RECT  73.968 67.717 73.992 69.443 ;
     RECT  2.304 68.917 2.712 69.587 ;
     RECT  53.568 68.917 53.592 69.587 ;
     RECT  64.704 69.395 67.608 69.587 ;
     RECT  64.704 69.587 66.12 69.635 ;
     RECT  23.472 69.061 24.408 69.685 ;
     RECT  5.232 68.341 5.256 69.731 ;
     RECT  34.176 68.341 35.112 69.731 ;
     RECT  23.472 69.685 25.08 69.923 ;
     RECT  58.128 68.483 58.152 69.923 ;
     RECT  75.024 67.715 75.192 70.021 ;
     RECT  55.68 66.611 57.096 70.067 ;
     RECT  18.6 63.779 18.912 70.069 ;
     RECT  47.904 69.493 47.928 70.259 ;
     RECT  50.496 68.917 51.312 70.643 ;
     RECT  75.024 70.021 75.72 70.643 ;
     RECT  72.6 67.859 72.912 70.645 ;
     RECT  40.2 68.963 40.632 70.693 ;
     RECT  5.088 69.973 5.112 70.741 ;
     RECT  23.472 69.923 24.312 71.075 ;
     RECT  53.376 70.405 53.4 71.075 ;
     RECT  67.2 69.587 67.608 71.173 ;
     RECT  75.024 70.643 75.192 71.221 ;
     RECT  9.168 70.645 9.672 71.315 ;
     RECT  26.16 67.283 26.184 71.315 ;
     RECT  64.752 69.635 66.12 71.315 ;
     RECT  72.48 70.645 72.912 71.411 ;
     RECT  9.648 71.315 9.672 71.603 ;
     RECT  61.8 65.843 62.112 71.749 ;
     RECT  40.2 70.693 41.064 71.795 ;
     RECT  29.28 68.533 29.712 71.797 ;
     RECT  39.072 70.405 39.096 71.797 ;
     RECT  40.2 71.795 40.632 71.797 ;
     RECT  67.2 71.173 67.656 71.893 ;
     RECT  43.248 69.829 43.272 71.939 ;
     RECT  39.072 71.797 40.632 71.941 ;
     RECT  38.928 71.941 40.632 71.987 ;
     RECT  28.752 71.797 29.712 71.989 ;
     RECT  15.312 63.779 15.336 72.181 ;
     RECT  36.624 70.069 36.648 72.181 ;
     RECT  18.192 70.069 18.912 72.227 ;
     RECT  36.624 72.181 36.744 72.227 ;
     RECT  67.2 71.893 67.8 72.227 ;
     RECT  64.896 71.315 66.12 72.325 ;
     RECT  67.2 72.227 67.512 72.325 ;
     RECT  49.584 71.797 49.608 72.419 ;
     RECT  64.896 72.325 67.512 72.419 ;
     RECT  28.416 71.989 29.712 72.661 ;
     RECT  24 71.075 24.312 72.757 ;
     RECT  78 58.163 78.312 72.901 ;
     RECT  26.64 71.845 27 72.997 ;
     RECT  26.496 72.997 27 73.043 ;
     RECT  36.72 72.227 36.744 73.091 ;
     RECT  11.424 71.413 11.448 73.139 ;
     RECT  27.984 72.661 29.712 73.139 ;
     RECT  26.496 73.043 26.664 73.187 ;
     RECT  5.088 70.741 5.448 73.235 ;
     RECT  13.2 52.499 13.512 73.381 ;
     RECT  28.416 73.139 29.712 73.427 ;
     RECT  38.928 71.987 40.512 73.475 ;
     RECT  24 72.757 24.552 73.477 ;
     RECT  26.304 73.237 26.328 73.477 ;
     RECT  76.32 72.277 76.344 73.571 ;
     RECT  24 73.477 26.328 73.859 ;
     RECT  66.672 72.419 67.512 73.859 ;
     RECT  48.24 70.597 48.264 74.053 ;
     RECT  55.68 70.067 56.712 74.053 ;
     RECT  48.24 74.053 49.032 74.101 ;
     RECT  5.088 73.235 5.112 74.291 ;
     RECT  77.424 72.901 78.312 74.533 ;
     RECT  12.336 73.381 13.512 74.579 ;
     RECT  58.464 69.973 58.488 74.579 ;
     RECT  64.896 72.419 65.64 74.581 ;
     RECT  14.784 72.181 15.336 74.627 ;
     RECT  13.2 74.579 13.512 74.629 ;
     RECT  28.512 73.427 29.712 74.723 ;
     RECT  55.44 74.053 56.712 74.723 ;
     RECT  64.416 74.581 65.64 74.819 ;
     RECT  61.8 71.749 62.424 74.963 ;
     RECT  21.696 71.029 21.72 75.107 ;
     RECT  39.936 73.475 40.512 75.107 ;
     RECT  38.928 73.475 38.952 75.109 ;
     RECT  38.928 75.109 39.048 75.155 ;
     RECT  18.6 72.227 18.912 75.205 ;
     RECT  47.856 74.101 49.032 75.251 ;
     RECT  47.856 75.251 48.264 75.299 ;
     RECT  24 73.859 25.464 75.347 ;
     RECT  47.856 75.299 47.88 75.395 ;
     RECT  61.8 74.963 62.112 75.685 ;
     RECT  77.184 74.533 78.312 75.781 ;
     RECT  76.944 75.781 78.408 75.827 ;
     RECT  24 75.347 24.408 75.875 ;
     RECT  76.944 75.827 76.968 75.971 ;
     RECT  71.28 74.629 71.304 76.165 ;
     RECT  72.6 71.411 72.912 76.165 ;
     RECT  71.28 76.165 72.912 76.211 ;
     RECT  18.24 75.205 18.912 76.309 ;
     RECT  20.112 67.859 20.136 76.357 ;
     RECT  21.648 75.733 21.672 76.357 ;
     RECT  28.752 74.723 29.712 76.357 ;
     RECT  31.536 64.019 31.56 76.357 ;
     RECT  32.832 76.165 32.856 76.357 ;
     RECT  20.112 76.357 21.672 76.403 ;
     RECT  31.536 76.357 32.856 76.403 ;
     RECT  74.4 71.221 75.192 76.403 ;
     RECT  32.448 76.403 32.856 76.451 ;
     RECT  78 75.827 78.408 76.499 ;
     RECT  51 70.643 51.312 76.645 ;
     RECT  28.416 76.357 29.712 76.691 ;
     RECT  4.896 74.581 4.92 76.979 ;
     RECT  13.2 74.629 14.232 76.979 ;
     RECT  37.632 76.117 37.656 76.979 ;
     RECT  60.48 76.357 60.504 77.027 ;
     RECT  63.264 76.069 63.288 77.315 ;
     RECT  15.312 74.627 15.336 77.413 ;
     RECT  14.928 77.413 15.336 77.459 ;
     RECT  17.616 76.309 18.912 77.509 ;
     RECT  20.112 76.403 20.904 77.509 ;
     RECT  17.616 77.509 20.904 77.555 ;
     RECT  25.44 75.347 25.464 77.555 ;
     RECT  28.752 76.691 29.712 77.555 ;
     RECT  47.808 76.645 47.832 77.555 ;
     RECT  59.472 76.885 59.496 77.555 ;
     RECT  85.488 77.413 85.512 77.555 ;
     RECT  71.808 76.211 72.912 77.939 ;
     RECT  17.616 77.555 20.136 78.083 ;
     RECT  55.68 74.723 56.712 78.469 ;
     RECT  83.4 64.163 83.712 78.469 ;
     RECT  75.792 77.125 75.816 78.517 ;
     RECT  54.816 78.469 56.712 78.611 ;
     RECT  24 75.875 24.312 78.613 ;
     RECT  45.6 66.227 45.912 78.613 ;
     RECT  67.2 73.859 67.512 78.613 ;
     RECT  18 78.083 20.136 78.659 ;
     RECT  14.928 77.459 15.096 78.707 ;
     RECT  78 76.499 78.312 79.189 ;
     RECT  50.112 76.645 51.312 79.235 ;
     RECT  64.896 74.819 65.64 79.283 ;
     RECT  55.584 78.611 56.712 79.475 ;
     RECT  77.472 79.189 78.312 79.523 ;
     RECT  71.184 78.613 71.208 79.715 ;
     RECT  34.8 69.731 35.112 79.717 ;
     RECT  45.6 78.613 46.152 79.763 ;
     RECT  40.2 75.107 40.512 79.765 ;
     RECT  39.024 75.155 39.048 79.859 ;
     RECT  24 78.613 24.888 79.955 ;
     RECT  13.2 76.979 13.512 80.101 ;
     RECT  15.072 78.707 15.096 80.101 ;
     RECT  29.4 77.555 29.712 80.101 ;
     RECT  83.4 78.469 83.976 80.149 ;
     RECT  34.608 79.717 35.112 80.387 ;
     RECT  27.312 79.141 27.336 80.531 ;
     RECT  61.68 75.685 62.112 80.675 ;
     RECT  37.008 79.765 37.032 80.771 ;
     RECT  32.448 76.451 32.472 80.773 ;
     RECT  29.28 80.101 29.712 80.819 ;
     RECT  74.4 76.403 74.424 80.821 ;
     RECT  20.112 78.659 20.136 80.917 ;
     RECT  21.552 80.341 21.576 80.917 ;
     RECT  86.304 79.717 86.328 80.963 ;
     RECT  20.112 80.917 21.576 81.011 ;
     RECT  13.2 80.101 15.096 81.059 ;
     RECT  18 78.659 18.912 81.107 ;
     RECT  61.8 80.675 62.112 81.205 ;
     RECT  81.888 77.989 81.912 81.301 ;
     RECT  81.888 81.301 82.056 81.347 ;
     RECT  18.6 81.107 18.912 81.445 ;
     RECT  83.4 80.149 84.312 81.445 ;
     RECT  83.088 81.445 84.312 81.491 ;
     RECT  74.16 80.821 74.424 81.539 ;
     RECT  21.072 81.011 21.576 81.875 ;
     RECT  75.792 78.517 76.056 81.875 ;
     RECT  74.4 81.539 74.424 82.021 ;
     RECT  75.792 81.875 75.816 82.021 ;
     RECT  74.4 82.021 75.816 82.067 ;
     RECT  32.256 80.773 32.472 82.069 ;
     RECT  54.96 82.021 54.984 82.163 ;
     RECT  32.256 82.069 33.096 82.405 ;
     RECT  18.6 81.445 19.272 82.451 ;
     RECT  22.704 80.869 22.728 82.451 ;
     RECT  67.2 78.613 67.656 82.451 ;
     RECT  45.6 79.763 45.912 82.597 ;
     RECT  72.6 77.939 72.912 82.597 ;
     RECT  40.2 79.765 41.016 82.691 ;
     RECT  74.4 82.067 75.624 82.691 ;
     RECT  82.032 81.347 82.056 82.691 ;
     RECT  83.088 81.491 83.712 82.691 ;
     RECT  61.8 81.205 62.232 82.739 ;
     RECT  36.096 81.445 36.12 82.883 ;
     RECT  83.4 82.691 83.712 82.933 ;
     RECT  7.8 60.851 8.112 82.981 ;
     RECT  79.488 82.645 79.512 83.123 ;
     RECT  21.552 81.875 21.576 83.173 ;
     RECT  78 79.523 78.312 83.173 ;
     RECT  21.456 83.173 21.576 83.219 ;
     RECT  58.752 80.341 58.776 83.267 ;
     RECT  65.616 79.283 65.64 83.267 ;
     RECT  74.64 82.691 75.624 83.267 ;
     RECT  12.144 82.933 12.168 83.365 ;
     RECT  13.2 81.059 13.512 83.365 ;
     RECT  83.4 82.933 83.832 83.459 ;
     RECT  63.504 80.629 63.528 83.557 ;
     RECT  32.16 82.405 33.096 83.795 ;
     RECT  72 82.597 72.912 83.795 ;
     RECT  29.4 80.819 29.712 83.797 ;
     RECT  7.8 82.981 8.856 84.035 ;
     RECT  27.792 83.125 27.816 84.035 ;
     RECT  45.6 82.597 46.776 84.035 ;
     RECT  75.6 83.267 75.624 84.083 ;
     RECT  26.352 81.973 26.376 84.181 ;
     RECT  26.208 84.181 26.376 84.227 ;
     RECT  63.504 83.557 63.816 84.323 ;
     RECT  40.2 82.691 40.512 84.325 ;
     RECT  9.12 84.277 9.144 84.419 ;
     RECT  5.664 83.749 5.688 84.611 ;
     RECT  12.144 83.365 13.512 84.611 ;
     RECT  16.992 83.749 17.016 84.853 ;
     RECT  45.6 84.035 45.912 84.901 ;
     RECT  12.432 84.611 13.512 84.995 ;
     RECT  15.072 81.059 15.096 84.995 ;
     RECT  16.992 84.853 17.112 84.995 ;
     RECT  3.984 84.325 4.008 85.091 ;
     RECT  26.208 84.227 26.232 85.091 ;
     RECT  78 83.173 78.408 85.187 ;
     RECT  48.768 83.365 48.792 85.237 ;
     RECT  29.4 83.797 29.832 85.381 ;
     RECT  10.752 84.325 10.776 85.523 ;
     RECT  44.976 84.901 45.912 85.523 ;
     RECT  33.072 83.795 33.096 85.621 ;
     RECT  33.072 85.621 33.336 85.667 ;
     RECT  48.528 85.237 48.792 85.907 ;
     RECT  53.616 81.205 53.64 85.909 ;
     RECT  48.528 85.907 48.552 85.955 ;
     RECT  53.616 85.909 54.408 85.955 ;
     RECT  50.4 79.235 51.312 86.003 ;
     RECT  63.504 84.323 63.528 86.099 ;
     RECT  69.36 84.037 69.384 86.149 ;
     RECT  70.56 85.381 70.584 86.149 ;
     RECT  69.36 86.149 70.584 86.195 ;
     RECT  34.8 80.387 35.112 86.341 ;
     RECT  13.2 84.995 13.512 86.437 ;
     RECT  24 79.955 24.312 86.581 ;
     RECT  13.104 86.437 13.512 86.627 ;
     RECT  56.4 79.475 56.712 86.773 ;
     RECT  21.456 83.219 21.48 86.821 ;
     RECT  33.312 85.667 33.336 86.821 ;
     RECT  24 86.581 24.648 87.155 ;
     RECT  16.992 84.995 17.016 87.203 ;
     RECT  29.4 85.381 30.552 87.251 ;
     RECT  47.232 85.141 47.256 87.251 ;
     RECT  70.128 86.195 70.152 87.251 ;
     RECT  32.88 86.821 33.336 87.445 ;
     RECT  34.464 86.341 35.112 87.445 ;
     RECT  65.52 86.629 65.544 87.779 ;
     RECT  20.544 86.821 21.48 87.827 ;
     RECT  32.88 87.445 35.112 87.827 ;
     RECT  39.792 84.325 40.512 87.875 ;
     RECT  33.312 87.827 35.112 87.923 ;
     RECT  54.384 85.955 54.408 88.115 ;
     RECT  34.224 87.923 35.112 88.163 ;
     RECT  55.44 86.773 56.712 88.163 ;
     RECT  5.376 87.781 5.4 88.309 ;
     RECT  5.184 88.309 5.4 88.357 ;
     RECT  7.8 84.035 8.112 88.357 ;
     RECT  2.4 69.587 2.712 88.569 ;
     RECT  5.184 88.357 8.112 88.569 ;
     RECT  13.2 86.627 13.512 88.569 ;
     RECT  18.6 82.451 18.912 88.569 ;
     RECT  24 87.155 24.312 88.569 ;
     RECT  29.4 87.251 29.712 88.569 ;
     RECT  34.8 88.163 35.112 88.569 ;
     RECT  40.2 87.875 40.512 88.569 ;
     RECT  45.6 85.523 45.912 88.569 ;
     RECT  51 86.003 51.312 88.569 ;
     RECT  56.4 88.163 56.712 88.569 ;
     RECT  61.8 82.739 62.112 88.569 ;
     RECT  67.2 82.451 67.512 88.569 ;
     RECT  72.6 83.795 72.912 88.569 ;
     RECT  78 85.187 78.312 88.569 ;
     RECT  83.4 83.459 83.712 88.569 ;
     RECT  2.4 88.569 2.52 88.583 ;
     RECT  5.184 88.569 7.92 88.583 ;
     RECT  13.2 88.569 13.32 88.583 ;
     RECT  18.6 88.569 18.72 88.583 ;
     RECT  24 88.569 24.12 88.583 ;
     RECT  29.4 88.569 29.52 88.583 ;
     RECT  34.8 88.569 34.92 88.583 ;
     RECT  40.2 88.569 40.32 88.583 ;
     RECT  45.6 88.569 45.72 88.583 ;
     RECT  51 88.569 51.12 88.583 ;
     RECT  56.4 88.569 56.52 88.583 ;
     RECT  61.8 88.569 61.92 88.583 ;
     RECT  67.2 88.569 67.32 88.583 ;
     RECT  72.6 88.569 72.72 88.583 ;
     RECT  78 88.569 78.12 88.583 ;
     RECT  83.4 88.569 83.52 88.583 ;
     RECT  5.184 88.583 7.416 89.461 ;
     RECT  5.088 89.461 7.416 90.037 ;
     RECT  5.088 90.037 7.8 90.373 ;
     RECT  5.088 90.373 8.088 90.704 ;
     RECT  30.648 2.245 31.776 2.677 ;
     RECT  49.752 2.245 51 2.533 ;
     RECT  82.392 2.245 83.4 3.925 ;
     RECT  49.752 2.533 50.736 2.867 ;
     RECT  31.8 2.581 32.88 2.677 ;
     RECT  40.776 2.821 42.048 3.301 ;
     RECT  49.752 2.867 51 3.059 ;
     RECT  72.912 2.869 74.4 4.261 ;
     RECT  37.224 3.253 38.592 3.301 ;
     RECT  37.56 3.301 38.592 3.349 ;
     RECT  66.12 3.397 67.2 4.787 ;
     RECT  44.472 3.829 45.6 4.501 ;
     RECT  72.912 4.261 74.112 5.171 ;
     RECT  74.136 4.307 75.264 5.171 ;
     RECT  4.536 4.501 5.616 4.837 ;
     RECT  56.712 4.643 56.808 5.317 ;
     RECT  82.392 4.691 83.4 5.989 ;
     RECT  43.32 5.077 44.448 5.605 ;
     RECT  78.312 5.219 78.696 6.229 ;
     RECT  56.712 5.317 58.032 6.323 ;
     RECT  71.256 5.365 72.6 6.709 ;
     RECT  43.32 5.605 44.4 6.085 ;
     RECT  56.064 5.699 56.4 7.045 ;
     RECT  71.256 6.709 72.48 7.381 ;
     RECT  42.36 6.899 43.872 6.947 ;
     RECT  42.36 6.947 43.92 8.437 ;
     RECT  70.656 6.995 71.232 8.485 ;
     RECT  71.256 7.381 72.288 8.819 ;
     RECT  72.912 7.381 74.16 7.909 ;
     RECT  74.184 7.381 75.168 8.051 ;
     RECT  50.352 8.003 51 8.437 ;
     RECT  74.184 8.051 75.264 8.819 ;
     RECT  3.672 8.099 4.848 9.971 ;
     RECT  62.112 8.293 63.312 12.035 ;
     RECT  48.744 8.437 49.92 10.307 ;
     RECT  49.944 8.437 51 10.307 ;
     RECT  70.92 8.819 72.288 9.155 ;
     RECT  67.512 9.155 67.608 10.213 ;
     RECT  72.912 9.155 74.016 10.357 ;
     RECT  58.704 9.683 58.728 10.501 ;
     RECT  2.856 9.971 4.848 9.973 ;
     RECT  2.856 9.973 3.984 10.403 ;
     RECT  2.712 10.403 3.984 11.267 ;
     RECT  58.704 10.501 58.752 10.741 ;
     RECT  54.696 10.597 56.016 11.411 ;
     RECT  57.576 10.741 58.752 10.883 ;
     RECT  4.872 10.979 6.144 12.035 ;
     RECT  40.512 10.979 41.52 12.901 ;
     RECT  36.36 11.555 37.776 12.517 ;
     RECT  64.776 11.893 66.24 14.099 ;
     RECT  4.872 12.035 6.24 12.179 ;
     RECT  45.912 12.035 46.944 13.573 ;
     RECT  79.92 12.035 79.944 12.469 ;
     RECT  79.92 12.469 80.64 12.997 ;
     RECT  36.456 12.517 37.776 14.197 ;
     RECT  51.672 12.517 52.848 13.139 ;
     RECT  78.312 12.997 79.824 13.811 ;
     RECT  80.664 13.045 81.792 13.667 ;
     RECT  74.184 13.379 75.216 13.715 ;
     RECT  78.312 13.811 78.456 14.725 ;
     RECT  72.912 14.099 74.16 25.957 ;
     RECT  4.872 14.197 6.096 14.917 ;
     RECT  32.424 14.339 33.6 14.723 ;
     RECT  45.912 14.387 46.944 14.867 ;
     RECT  51.312 14.435 51.672 15.253 ;
     RECT  32.424 14.723 33.84 16.261 ;
     RECT  82.392 14.773 83.4 15.587 ;
     RECT  45.912 14.867 47.328 15.491 ;
     RECT  4.968 14.917 6.096 15.925 ;
     RECT  56.808 15.061 58.128 16.019 ;
     RECT  37.608 15.203 38.736 15.443 ;
     RECT  51.312 15.253 52.992 15.925 ;
     RECT  37.608 15.443 38.88 16.019 ;
     RECT  83.04 15.587 83.4 16.405 ;
     RECT  5.016 15.925 6.096 16.019 ;
     RECT  51.312 15.925 52.704 16.885 ;
     RECT  40.512 16.019 41.616 18.275 ;
     RECT  32.472 16.261 33.84 16.501 ;
     RECT  85.752 16.501 87.168 19.093 ;
     RECT  35.88 16.595 36.912 18.181 ;
     RECT  44.472 17.123 45.6 18.275 ;
     RECT  70.968 17.507 72 17.603 ;
     RECT  8.424 17.699 8.664 18.757 ;
     RECT  76.92 18.085 78 18.275 ;
     RECT  40.512 18.275 40.728 18.661 ;
     RECT  9.192 18.757 10.224 19.859 ;
     RECT  45.912 18.757 47.376 19.859 ;
     RECT  86.04 19.093 87.168 21.443 ;
     RECT  70.824 19.235 70.968 20.293 ;
     RECT  8.424 19.859 10.224 20.053 ;
     RECT  55.128 19.909 56.4 21.971 ;
     RECT  8.424 20.053 10.176 20.149 ;
     RECT  8.424 20.149 9.888 21.637 ;
     RECT  37.464 20.149 38.736 21.155 ;
     RECT  2.712 20.197 3.84 21.155 ;
     RECT  70.92 20.293 70.968 20.389 ;
     RECT  66.072 20.341 67.2 21.155 ;
     RECT  71.496 20.437 72.6 20.581 ;
     RECT  2.712 21.155 3.864 21.637 ;
     RECT  37.272 21.155 38.736 21.299 ;
     RECT  68.376 21.157 69.552 21.637 ;
     RECT  37.176 21.299 38.736 22.259 ;
     RECT  2.712 21.637 4.176 23.411 ;
     RECT  8.808 21.637 9.888 21.685 ;
     RECT  74.52 22.165 76.032 26.243 ;
     RECT  37.176 22.259 39.216 22.741 ;
     RECT  10.872 22.307 11.856 22.931 ;
     RECT  8.808 22.403 9.888 22.451 ;
     RECT  8.568 22.451 9.888 24.085 ;
     RECT  38.232 22.741 39.216 23.701 ;
     RECT  10.44 22.931 11.856 25.189 ;
     RECT  36.072 23.507 37.44 24.853 ;
     RECT  69.576 23.699 70.656 25.139 ;
     RECT  71.448 23.699 72.6 29.171 ;
     RECT  62.76 24.469 63.936 25.331 ;
     RECT  36.072 24.853 37.104 25.861 ;
     RECT  4.488 24.997 5.904 28.117 ;
     RECT  69.576 25.139 70.896 26.197 ;
     RECT  10.44 25.189 11.424 26.243 ;
     RECT  77.76 25.571 78 25.621 ;
     RECT  76.632 25.621 78 31.475 ;
     RECT  72.912 25.957 73.92 26.531 ;
     RECT  66.168 26.101 67.2 29.363 ;
     RECT  10.44 26.243 11.952 28.547 ;
     RECT  37.128 26.243 38.304 27.781 ;
     RECT  6.648 26.339 7.68 26.819 ;
     RECT  14.568 26.435 15.6 26.819 ;
     RECT  8.424 26.483 9.456 27.155 ;
     RECT  72.912 26.531 74.16 28.163 ;
     RECT  69.576 26.771 70.896 29.317 ;
     RECT  6.648 26.819 7.8 32.437 ;
     RECT  14.424 26.819 15.6 28.691 ;
     RECT  35.88 26.867 37.104 27.395 ;
     RECT  3.288 27.061 4.32 34.787 ;
     RECT  8.112 27.155 9.456 28.453 ;
     RECT  51.312 27.157 52.752 30.037 ;
     RECT  35.832 27.395 37.104 29.123 ;
     RECT  40.512 27.781 42 28.787 ;
     RECT  57 27.829 58.08 31.379 ;
     RECT  58.104 27.875 59.064 28.405 ;
     RECT  64.872 27.971 66.144 29.363 ;
     RECT  4.488 28.117 5.52 28.403 ;
     RECT  4.488 28.403 5.904 29.699 ;
     RECT  44.184 28.405 45.6 31.861 ;
     RECT  58.104 28.405 59.088 30.323 ;
     RECT  8.112 28.453 9.312 29.365 ;
     RECT  14.232 28.691 15.6 30.611 ;
     RECT  46.056 28.693 47.376 31.043 ;
     RECT  64.872 29.363 67.2 30.421 ;
     RECT  16.344 29.507 17.52 31.955 ;
     RECT  51.312 30.037 52.56 42.133 ;
     RECT  69.576 30.275 70.704 30.851 ;
     RECT  64.872 30.421 65.952 31.379 ;
     RECT  65.976 30.421 67.2 34.165 ;
     RECT  8.112 30.611 9.312 33.829 ;
     RECT  14.232 30.611 15.696 31.619 ;
     RECT  33.576 30.611 34.56 31.139 ;
     RECT  46.056 31.043 47.664 32.341 ;
     RECT  33.576 31.139 34.704 32.437 ;
     RECT  71.256 31.525 72.6 33.589 ;
     RECT  72.912 31.861 74.4 36.421 ;
     RECT  16.248 31.955 17.52 32.723 ;
     RECT  49.56 32.293 51 33.107 ;
     RECT  46.152 32.341 47.664 33.011 ;
     RECT  55.32 32.389 56.4 33.683 ;
     RECT  33.576 32.437 34.56 32.917 ;
     RECT  52.584 32.531 53.616 41.075 ;
     RECT  16.224 32.723 17.52 33.541 ;
     RECT  46.152 33.011 47.016 33.109 ;
     RECT  81.48 33.061 82.704 33.683 ;
     RECT  44.472 33.107 45.504 34.211 ;
     RECT  46.488 33.109 47.016 33.589 ;
     RECT  26.232 33.251 27.312 33.683 ;
     RECT  22.92 33.299 23.904 33.395 ;
     RECT  43.368 33.347 44.448 34.211 ;
     RECT  22.92 33.395 24 34.645 ;
     RECT  14.232 33.541 15.264 33.827 ;
     RECT  15.288 33.541 17.52 33.781 ;
     RECT  33.576 33.587 34.56 35.363 ;
     RECT  15.384 33.781 17.52 34.165 ;
     RECT  6.648 33.827 7.8 35.317 ;
     RECT  13.944 33.827 15.264 34.211 ;
     RECT  40.824 33.925 42.336 34.067 ;
     RECT  46.488 33.971 47.016 34.933 ;
     RECT  15.384 34.165 16.512 34.453 ;
     RECT  16.536 34.165 17.52 34.741 ;
     RECT  66.168 34.165 67.2 37.091 ;
     RECT  13.944 34.211 15.36 34.499 ;
     RECT  71.256 34.211 72.6 36.133 ;
     RECT  32.472 34.259 33.552 35.363 ;
     RECT  15.384 34.453 16.416 35.411 ;
     RECT  3.192 34.787 4.32 38.243 ;
     RECT  8.328 34.835 9.312 37.861 ;
     RECT  32.472 35.363 34.56 35.411 ;
     RECT  62.112 35.365 63.456 35.843 ;
     RECT  32.472 35.411 34.8 36.515 ;
     RECT  62.112 35.843 62.664 37.045 ;
     RECT  25.944 35.845 27.408 36.997 ;
     RECT  71.256 36.133 72.24 37.475 ;
     RECT  57 36.421 58.032 36.901 ;
     RECT  27.672 36.515 29.088 37.091 ;
     RECT  30.408 36.515 31.632 36.563 ;
     RECT  32.184 36.515 34.8 36.757 ;
     RECT  6.648 36.563 7.8 43.427 ;
     RECT  29.928 36.563 31.632 37.573 ;
     RECT  32.184 36.757 33.648 39.539 ;
     RECT  33.672 36.757 34.8 36.805 ;
     RECT  33.768 36.805 34.8 36.949 ;
     RECT  49.848 36.853 51 41.363 ;
     RECT  25.944 36.997 27.312 37.621 ;
     RECT  71.808 37.475 72.24 37.477 ;
     RECT  30.216 37.573 31.632 37.715 ;
     RECT  26.184 37.621 27.312 37.667 ;
     RECT  38.664 38.003 39.84 38.675 ;
     RECT  3.192 38.243 4.008 38.677 ;
     RECT  12.96 38.243 13.2 39.301 ;
     RECT  16.392 38.243 17.616 39.059 ;
     RECT  33.768 38.243 34.8 38.819 ;
     RECT  40.512 38.291 40.824 39.493 ;
     RECT  33.672 38.819 34.8 39.539 ;
     RECT  40.512 39.493 41.664 39.635 ;
     RECT  60.264 39.877 61.488 40.547 ;
     RECT  22.776 39.923 24 40.499 ;
     RECT  63.672 40.165 64.992 42.227 ;
     RECT  18.912 40.499 20.112 41.075 ;
     RECT  20.424 40.499 21.456 40.643 ;
     RECT  22.584 40.499 24 42.517 ;
     RECT  29.088 40.595 29.232 40.933 ;
     RECT  20.424 40.643 21.6 41.651 ;
     RECT  48.6 40.789 49.824 41.363 ;
     RECT  27.912 40.933 29.232 41.651 ;
     RECT  17.616 41.075 17.76 42.133 ;
     RECT  18.912 41.075 20.4 41.651 ;
     RECT  39.744 41.075 39.984 41.123 ;
     RECT  39.744 41.123 40.08 42.133 ;
     RECT  78.312 41.315 79.224 41.941 ;
     RECT  48.6 41.363 48.984 41.651 ;
     RECT  18.912 41.651 21.6 42.469 ;
     RECT  28.56 41.651 29.232 42.565 ;
     RECT  48.96 41.651 48.984 42.229 ;
     RECT  54.936 41.651 56.4 42.851 ;
     RECT  78.312 41.941 79.776 43.333 ;
     RECT  39.048 42.133 40.08 42.227 ;
     RECT  39.048 42.227 40.2 42.851 ;
     RECT  18.912 42.469 21.408 42.565 ;
     RECT  22.68 42.517 24 46.645 ;
     RECT  18.912 42.565 20.16 44.915 ;
     RECT  20.184 42.565 21.408 42.709 ;
     RECT  30.12 42.613 31.584 43.907 ;
     RECT  32.184 42.661 33.6 42.755 ;
     RECT  33.624 42.661 34.8 47.845 ;
     RECT  37.656 42.709 39.024 42.851 ;
     RECT  31.608 42.755 31.896 43.861 ;
     RECT  51.672 42.803 51.912 44.053 ;
     RECT  73.512 43.141 74.928 44.483 ;
     RECT  78.696 43.333 79.776 43.475 ;
     RECT  78.312 43.475 79.776 44.867 ;
     RECT  20.472 43.955 21.744 45.013 ;
     RECT  56.952 44.195 57.048 44.291 ;
     RECT  56.712 44.291 57.048 44.965 ;
     RECT  44.232 44.483 45.6 48.515 ;
     RECT  72.384 44.627 72.6 46.117 ;
     RECT  78.312 44.867 78.696 45.541 ;
     RECT  18.912 44.915 20.448 45.635 ;
     RECT  56.712 44.965 58.128 45.971 ;
     RECT  62.808 45.011 63.792 47.363 ;
     RECT  20.472 45.013 21.648 45.635 ;
     RECT  18.912 45.635 21.648 46.067 ;
     RECT  63.816 45.635 63.96 46.933 ;
     RECT  18.912 46.067 22.176 46.309 ;
     RECT  55.08 46.117 56.4 47.845 ;
     RECT  71.208 46.117 72.6 46.645 ;
     RECT  18.912 46.309 21.072 46.357 ;
     RECT  21.096 46.309 22.176 47.987 ;
     RECT  19.8 46.357 21.072 47.749 ;
     RECT  22.872 46.645 24 46.789 ;
     RECT  28.392 46.741 29.4 48.419 ;
     RECT  23.016 46.789 24 47.605 ;
     RECT  63.816 46.933 64.896 47.029 ;
     RECT  71.496 47.027 72.6 49.091 ;
     RECT  37.992 47.029 39.312 47.269 ;
     RECT  38.232 47.269 39.312 48.421 ;
     RECT  42.792 47.269 44.208 48.371 ;
     RECT  41.352 47.749 42.768 48.371 ;
     RECT  46.056 48.421 47.136 50.291 ;
     RECT  56.712 48.421 58.176 49.043 ;
     RECT  24.648 48.515 26.16 48.563 ;
     RECT  37.032 48.515 38.208 50.243 ;
     RECT  32.52 48.707 33.6 52.163 ;
     RECT  76.2 48.803 76.392 48.949 ;
     RECT  76.2 48.949 77.472 49.091 ;
     RECT  56.712 49.043 58.608 50.149 ;
     RECT  38.232 49.139 40.2 50.243 ;
     RECT  58.632 49.525 59.856 51.011 ;
     RECT  67.656 49.525 69.12 50.533 ;
     RECT  78.312 49.525 79.584 51.829 ;
     RECT  63.816 49.715 64.896 52.259 ;
     RECT  33.624 50.003 34.8 51.301 ;
     RECT  57.096 50.149 58.608 50.819 ;
     RECT  38.976 50.243 40.2 50.245 ;
     RECT  39 50.245 40.2 51.635 ;
     RECT  46.056 50.291 46.488 50.821 ;
     RECT  67.512 50.675 68.928 58.403 ;
     RECT  24.648 50.677 26.16 52.163 ;
     RECT  81.24 50.677 82.512 56.965 ;
     RECT  51.72 50.917 52.8 52.499 ;
     RECT  11.88 50.965 13.2 52.739 ;
     RECT  59.88 50.965 61.152 51.011 ;
     RECT  58.632 51.011 59.352 51.683 ;
     RECT  59.328 51.683 59.352 51.781 ;
     RECT  22.8 52.019 23.664 53.029 ;
     RECT  32.496 52.163 33.6 52.213 ;
     RECT  29.712 52.213 31.056 59.987 ;
     RECT  31.08 52.213 33.6 53.221 ;
     RECT  44.136 52.213 45.6 53.507 ;
     RECT  79.8 52.213 81.216 52.643 ;
     RECT  64.416 52.259 64.896 53.557 ;
     RECT  22.44 53.029 23.664 53.507 ;
     RECT  33.624 53.219 34.8 54.179 ;
     RECT  31.08 53.221 32.448 53.411 ;
     RECT  32.472 53.221 33.6 53.411 ;
     RECT  26.184 53.317 27.408 54.227 ;
     RECT  76.152 53.557 77.472 55.907 ;
     RECT  78.408 53.651 79.584 58.163 ;
     RECT  24.648 53.941 26.16 54.707 ;
     RECT  24.312 54.707 24.6 55.813 ;
     RECT  79.608 54.901 80.88 55.139 ;
     RECT  46.056 55.045 47.376 55.907 ;
     RECT  51.72 55.189 52.704 57.347 ;
     RECT  37.032 56.101 38.4 56.147 ;
     RECT  24.312 56.627 24.6 57.541 ;
     RECT  81.48 56.965 82.512 58.115 ;
     RECT  48.552 57.013 49.776 62.435 ;
     RECT  49.8 57.013 51 58.117 ;
     RECT  24.312 57.541 25.44 58.693 ;
     RECT  84.072 57.925 85.536 61.667 ;
     RECT  35.112 58.021 36.48 59.221 ;
     RECT  81.24 58.115 82.512 63.299 ;
     RECT  78.312 58.163 79.584 62.723 ;
     RECT  18.912 58.501 19.968 59.027 ;
     RECT  19.992 58.501 21.456 59.027 ;
     RECT  85.56 59.173 86.976 60.467 ;
     RECT  49.8 59.315 51 62.771 ;
     RECT  24.312 59.795 25.44 61.043 ;
     RECT  29.712 59.987 31.08 60.277 ;
     RECT  4.968 60.275 5.112 60.997 ;
     RECT  29.712 60.277 31.008 61.571 ;
     RECT  31.032 60.277 32.16 61.525 ;
     RECT  7.584 60.851 7.8 60.997 ;
     RECT  32.184 60.949 33.264 62.771 ;
     RECT  33.288 60.949 34.8 62.771 ;
     RECT  67.992 60.949 69.12 61.667 ;
     RECT  4.968 60.997 6.384 62.195 ;
     RECT  6.408 60.997 7.8 62.195 ;
     RECT  65.64 61.765 66.96 62.629 ;
     RECT  57.096 62.581 58.128 69.923 ;
     RECT  65.64 62.629 66.912 63.587 ;
     RECT  24.312 64.165 25.632 67.283 ;
     RECT  33.672 64.357 34.8 65.269 ;
     RECT  49.704 64.405 51 66.323 ;
     RECT  33.72 65.269 34.8 66.755 ;
     RECT  66.12 65.749 67.2 65.989 ;
     RECT  18.912 66.085 19.968 66.755 ;
     RECT  55.32 66.373 56.4 66.565 ;
     RECT  26.184 66.517 27.648 67.331 ;
     RECT  18.912 66.755 20.112 77.509 ;
     RECT  33.672 66.755 34.8 67.571 ;
     RECT  64.8 66.803 64.896 67.861 ;
     RECT  24.312 67.283 24.408 68.773 ;
     RECT  34.176 67.571 34.8 68.341 ;
     RECT  72.912 67.717 73.968 69.443 ;
     RECT  73.992 67.717 75.024 69.443 ;
     RECT  58.152 68.483 58.296 69.923 ;
     RECT  39.408 68.963 40.2 70.405 ;
     RECT  66.12 69.587 67.2 72.325 ;
     RECT  25.08 69.685 26.16 69.923 ;
     RECT  5.232 69.731 5.256 69.973 ;
     RECT  57.096 69.923 58.296 69.973 ;
     RECT  5.112 69.973 5.256 70.741 ;
     RECT  57.096 69.973 58.464 70.067 ;
     RECT  35.112 70.069 36.624 72.227 ;
     RECT  39.096 70.405 40.2 71.797 ;
     RECT  50.496 70.643 51 71.797 ;
     RECT  8.112 70.645 9.168 71.315 ;
     RECT  72.912 71.221 74.4 80.821 ;
     RECT  48.264 71.797 49.584 72.419 ;
     RECT  49.608 71.797 51 72.419 ;
     RECT  27 71.989 28.416 72.661 ;
     RECT  13.512 72.181 14.784 74.627 ;
     RECT  75.192 72.277 76.32 73.571 ;
     RECT  65.64 72.419 66.672 73.859 ;
     RECT  27 72.661 27.984 73.043 ;
     RECT  76.344 72.901 77.424 73.571 ;
     RECT  26.664 73.043 27.984 73.139 ;
     RECT  38.952 73.475 39.936 75.107 ;
     RECT  77.184 73.571 77.424 74.533 ;
     RECT  13.512 74.627 15.312 74.629 ;
     RECT  14.232 74.629 15.312 76.979 ;
     RECT  71.304 74.629 72.6 76.165 ;
     RECT  62.112 74.963 62.424 76.069 ;
     RECT  38.952 75.107 40.2 75.109 ;
     RECT  39.048 75.109 40.2 79.859 ;
     RECT  38.928 75.155 39.024 76.117 ;
     RECT  24.408 75.347 25.44 75.875 ;
     RECT  20.136 75.733 21.648 76.357 ;
     RECT  76.968 75.827 78 75.971 ;
     RECT  24.312 75.875 25.44 77.555 ;
     RECT  62.112 76.069 63.264 77.315 ;
     RECT  37.656 76.117 39.024 76.979 ;
     RECT  31.56 76.165 32.832 76.357 ;
     RECT  60.504 76.357 61.68 77.027 ;
     RECT  74.424 76.403 75.192 77.125 ;
     RECT  59.496 76.885 60.48 77.027 ;
     RECT  13.512 76.979 15.312 77.413 ;
     RECT  74.424 77.125 75.792 82.021 ;
     RECT  13.512 77.413 14.928 78.707 ;
     RECT  24.312 77.555 24.888 78.613 ;
     RECT  71.808 77.939 72.6 78.613 ;
     RECT  81.912 77.989 83.4 81.301 ;
     RECT  71.208 78.613 72.6 79.715 ;
     RECT  18.912 78.659 20.112 81.011 ;
     RECT  13.512 78.707 15.072 80.101 ;
     RECT  76.056 79.189 77.472 79.523 ;
     RECT  20.136 80.341 21.552 80.917 ;
     RECT  62.112 80.629 63.504 81.205 ;
     RECT  72.912 80.821 74.16 81.539 ;
     RECT  21.576 80.869 22.704 82.451 ;
     RECT  22.728 80.869 24 82.451 ;
     RECT  18.912 81.011 19.272 81.445 ;
     RECT  62.232 81.205 63.504 82.739 ;
     RECT  82.056 81.301 83.4 81.445 ;
     RECT  35.112 81.445 36.096 82.883 ;
     RECT  82.056 81.445 83.088 82.691 ;
     RECT  83.712 81.491 83.832 82.933 ;
     RECT  72.912 81.539 74.4 82.691 ;
     RECT  21.456 81.875 21.552 83.173 ;
     RECT  53.64 82.021 54.96 82.163 ;
     RECT  54.984 82.021 56.4 82.163 ;
     RECT  78.312 82.645 79.488 83.123 ;
     RECT  62.112 82.739 63.504 86.099 ;
     RECT  12.168 82.933 13.2 83.365 ;
     RECT  78.312 83.123 78.408 83.173 ;
     RECT  26.376 83.125 27.792 84.035 ;
     RECT  8.112 84.035 8.856 84.277 ;
     RECT  45.912 84.035 46.776 85.141 ;
     RECT  8.112 84.277 9.12 84.419 ;
     RECT  2.712 84.325 3.984 85.091 ;
     RECT  10.776 84.325 12.144 84.611 ;
     RECT  17.112 84.853 18.6 84.995 ;
     RECT  13.104 84.995 13.2 86.437 ;
     RECT  45.912 85.141 47.232 87.251 ;
     RECT  47.256 85.141 48.768 85.237 ;
     RECT  47.256 85.237 48.528 85.955 ;
     RECT  69.384 85.381 70.56 86.149 ;
     RECT  33.336 85.621 34.8 86.341 ;
     RECT  33.072 85.667 33.312 86.821 ;
     RECT  33.336 86.341 34.464 87.445 ;
     RECT  54.408 86.773 55.44 88.115 ;
     RECT  7.416 88.583 7.8 90.037 ;
  END
END ot_s81_engram_chunk8
END LIBRARY
